VERSION 5.8 ;
BUSBITCHARS "[]" ;
DIVIDERCHAR "/" ;
UNITS
    DATABASE MICRONS 1000 ;
END UNITS

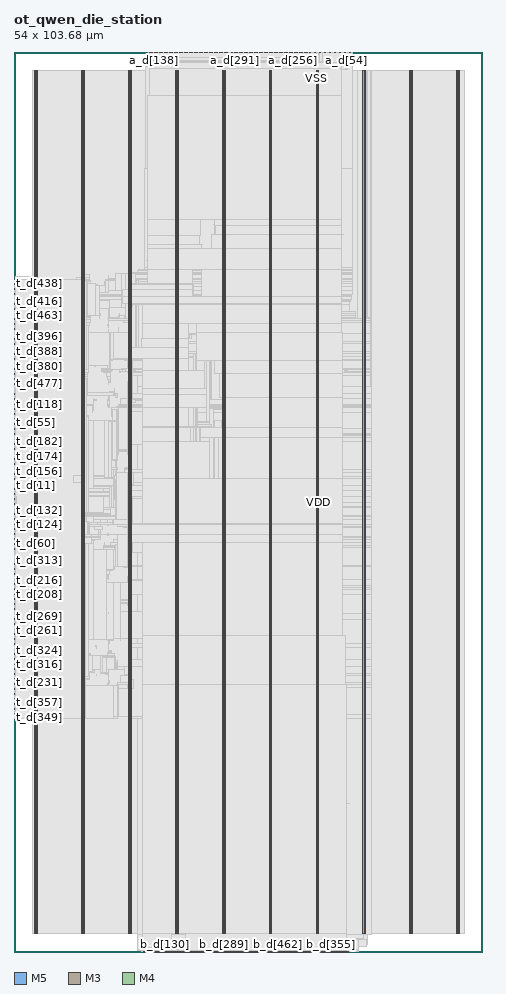
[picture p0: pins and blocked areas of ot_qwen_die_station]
MACRO ot_qwen_die_station
  FOREIGN ot_qwen_die_station 0 0 ;
  CLASS BLOCK ;
  SIZE 54 BY 103.68 ;
  PIN a_d[0]
    DIRECTION INPUT ;
    USE SIGNAL ;
    PORT
      LAYER M5 ;
        RECT  15.696 103.596 15.72 103.68 ;
    END
  END a_d[0]
  PIN a_d[100]
    DIRECTION INPUT ;
    USE SIGNAL ;
    PORT
      LAYER M5 ;
        RECT  22.224 103.596 22.248 103.68 ;
    END
  END a_d[100]
  PIN a_d[101]
    DIRECTION INPUT ;
    USE SIGNAL ;
    PORT
      LAYER M5 ;
        RECT  22.32 103.596 22.344 103.68 ;
    END
  END a_d[101]
  PIN a_d[102]
    DIRECTION INPUT ;
    USE SIGNAL ;
    PORT
      LAYER M5 ;
        RECT  22.416 103.596 22.44 103.68 ;
    END
  END a_d[102]
  PIN a_d[103]
    DIRECTION INPUT ;
    USE SIGNAL ;
    PORT
      LAYER M5 ;
        RECT  22.512 103.596 22.536 103.68 ;
    END
  END a_d[103]
  PIN a_d[104]
    DIRECTION INPUT ;
    USE SIGNAL ;
    PORT
      LAYER M5 ;
        RECT  22.608 103.596 22.632 103.68 ;
    END
  END a_d[104]
  PIN a_d[105]
    DIRECTION INPUT ;
    USE SIGNAL ;
    PORT
      LAYER M5 ;
        RECT  22.704 103.596 22.728 103.68 ;
    END
  END a_d[105]
  PIN a_d[106]
    DIRECTION INPUT ;
    USE SIGNAL ;
    PORT
      LAYER M5 ;
        RECT  22.8 103.596 22.824 103.68 ;
    END
  END a_d[106]
  PIN a_d[107]
    DIRECTION INPUT ;
    USE SIGNAL ;
    PORT
      LAYER M5 ;
        RECT  22.896 103.596 22.92 103.68 ;
    END
  END a_d[107]
  PIN a_d[108]
    DIRECTION INPUT ;
    USE SIGNAL ;
    PORT
      LAYER M5 ;
        RECT  22.992 103.596 23.016 103.68 ;
    END
  END a_d[108]
  PIN a_d[109]
    DIRECTION INPUT ;
    USE SIGNAL ;
    PORT
      LAYER M5 ;
        RECT  23.088 103.596 23.112 103.68 ;
    END
  END a_d[109]
  PIN a_d[10]
    DIRECTION INPUT ;
    USE SIGNAL ;
    PORT
      LAYER M5 ;
        RECT  16.656 103.596 16.68 103.68 ;
    END
  END a_d[10]
  PIN a_d[110]
    DIRECTION INPUT ;
    USE SIGNAL ;
    PORT
      LAYER M5 ;
        RECT  23.184 103.596 23.208 103.68 ;
    END
  END a_d[110]
  PIN a_d[111]
    DIRECTION INPUT ;
    USE SIGNAL ;
    PORT
      LAYER M5 ;
        RECT  23.28 103.596 23.304 103.68 ;
    END
  END a_d[111]
  PIN a_d[112]
    DIRECTION INPUT ;
    USE SIGNAL ;
    PORT
      LAYER M5 ;
        RECT  23.376 103.596 23.4 103.68 ;
    END
  END a_d[112]
  PIN a_d[113]
    DIRECTION INPUT ;
    USE SIGNAL ;
    PORT
      LAYER M5 ;
        RECT  23.472 103.596 23.496 103.68 ;
    END
  END a_d[113]
  PIN a_d[114]
    DIRECTION INPUT ;
    USE SIGNAL ;
    PORT
      LAYER M5 ;
        RECT  23.568 103.596 23.592 103.68 ;
    END
  END a_d[114]
  PIN a_d[115]
    DIRECTION INPUT ;
    USE SIGNAL ;
    PORT
      LAYER M5 ;
        RECT  23.664 103.596 23.688 103.68 ;
    END
  END a_d[115]
  PIN a_d[116]
    DIRECTION INPUT ;
    USE SIGNAL ;
    PORT
      LAYER M5 ;
        RECT  23.76 103.596 23.784 103.68 ;
    END
  END a_d[116]
  PIN a_d[117]
    DIRECTION INPUT ;
    USE SIGNAL ;
    PORT
      LAYER M5 ;
        RECT  23.856 103.596 23.88 103.68 ;
    END
  END a_d[117]
  PIN a_d[118]
    DIRECTION INPUT ;
    USE SIGNAL ;
    PORT
      LAYER M5 ;
        RECT  23.952 103.596 23.976 103.68 ;
    END
  END a_d[118]
  PIN a_d[119]
    DIRECTION INPUT ;
    USE SIGNAL ;
    PORT
      LAYER M5 ;
        RECT  24.048 103.596 24.072 103.68 ;
    END
  END a_d[119]
  PIN a_d[11]
    DIRECTION INPUT ;
    USE SIGNAL ;
    PORT
      LAYER M5 ;
        RECT  16.752 103.596 16.776 103.68 ;
    END
  END a_d[11]
  PIN a_d[120]
    DIRECTION INPUT ;
    USE SIGNAL ;
    PORT
      LAYER M5 ;
        RECT  24.144 103.596 24.168 103.68 ;
    END
  END a_d[120]
  PIN a_d[121]
    DIRECTION INPUT ;
    USE SIGNAL ;
    PORT
      LAYER M5 ;
        RECT  24.24 103.596 24.264 103.68 ;
    END
  END a_d[121]
  PIN a_d[122]
    DIRECTION INPUT ;
    USE SIGNAL ;
    PORT
      LAYER M5 ;
        RECT  24.336 103.596 24.36 103.68 ;
    END
  END a_d[122]
  PIN a_d[123]
    DIRECTION INPUT ;
    USE SIGNAL ;
    PORT
      LAYER M5 ;
        RECT  24.432 103.596 24.456 103.68 ;
    END
  END a_d[123]
  PIN a_d[124]
    DIRECTION INPUT ;
    USE SIGNAL ;
    PORT
      LAYER M5 ;
        RECT  24.528 103.596 24.552 103.68 ;
    END
  END a_d[124]
  PIN a_d[125]
    DIRECTION INPUT ;
    USE SIGNAL ;
    PORT
      LAYER M5 ;
        RECT  24.624 103.596 24.648 103.68 ;
    END
  END a_d[125]
  PIN a_d[126]
    DIRECTION INPUT ;
    USE SIGNAL ;
    PORT
      LAYER M5 ;
        RECT  24.72 103.596 24.744 103.68 ;
    END
  END a_d[126]
  PIN a_d[127]
    DIRECTION INPUT ;
    USE SIGNAL ;
    PORT
      LAYER M5 ;
        RECT  24.816 103.596 24.84 103.68 ;
    END
  END a_d[127]
  PIN a_d[128]
    DIRECTION INPUT ;
    USE SIGNAL ;
    PORT
      LAYER M3 ;
        RECT  15.444 103.643 15.462 103.68 ;
    END
  END a_d[128]
  PIN a_d[129]
    DIRECTION INPUT ;
    USE SIGNAL ;
    PORT
      LAYER M3 ;
        RECT  15.516 103.643 15.534 103.68 ;
    END
  END a_d[129]
  PIN a_d[12]
    DIRECTION INPUT ;
    USE SIGNAL ;
    PORT
      LAYER M5 ;
        RECT  16.848 103.596 16.872 103.68 ;
    END
  END a_d[12]
  PIN a_d[130]
    DIRECTION INPUT ;
    USE SIGNAL ;
    PORT
      LAYER M3 ;
        RECT  15.588 103.643 15.606 103.68 ;
    END
  END a_d[130]
  PIN a_d[131]
    DIRECTION INPUT ;
    USE SIGNAL ;
    PORT
      LAYER M3 ;
        RECT  15.66 103.643 15.678 103.68 ;
    END
  END a_d[131]
  PIN a_d[132]
    DIRECTION INPUT ;
    USE SIGNAL ;
    PORT
      LAYER M3 ;
        RECT  15.732 103.643 15.75 103.68 ;
    END
  END a_d[132]
  PIN a_d[133]
    DIRECTION INPUT ;
    USE SIGNAL ;
    PORT
      LAYER M3 ;
        RECT  15.804 103.643 15.822 103.68 ;
    END
  END a_d[133]
  PIN a_d[134]
    DIRECTION INPUT ;
    USE SIGNAL ;
    PORT
      LAYER M3 ;
        RECT  15.876 103.643 15.894 103.68 ;
    END
  END a_d[134]
  PIN a_d[135]
    DIRECTION INPUT ;
    USE SIGNAL ;
    PORT
      LAYER M3 ;
        RECT  15.948 103.643 15.966 103.68 ;
    END
  END a_d[135]
  PIN a_d[136]
    DIRECTION INPUT ;
    USE SIGNAL ;
    PORT
      LAYER M3 ;
        RECT  16.02 103.643 16.038 103.68 ;
    END
  END a_d[136]
  PIN a_d[137]
    DIRECTION INPUT ;
    USE SIGNAL ;
    PORT
      LAYER M3 ;
        RECT  16.092 103.643 16.11 103.68 ;
    END
  END a_d[137]
  PIN a_d[138]
    DIRECTION INPUT ;
    USE SIGNAL ;
    PORT
      LAYER M3 ;
        RECT  16.164 103.643 16.182 103.68 ;
    END
  END a_d[138]
  PIN a_d[139]
    DIRECTION INPUT ;
    USE SIGNAL ;
    PORT
      LAYER M3 ;
        RECT  16.236 103.643 16.254 103.68 ;
    END
  END a_d[139]
  PIN a_d[13]
    DIRECTION INPUT ;
    USE SIGNAL ;
    PORT
      LAYER M5 ;
        RECT  16.944 103.596 16.968 103.68 ;
    END
  END a_d[13]
  PIN a_d[140]
    DIRECTION INPUT ;
    USE SIGNAL ;
    PORT
      LAYER M3 ;
        RECT  16.308 103.643 16.326 103.68 ;
    END
  END a_d[140]
  PIN a_d[141]
    DIRECTION INPUT ;
    USE SIGNAL ;
    PORT
      LAYER M3 ;
        RECT  16.38 103.643 16.398 103.68 ;
    END
  END a_d[141]
  PIN a_d[142]
    DIRECTION INPUT ;
    USE SIGNAL ;
    PORT
      LAYER M3 ;
        RECT  16.452 103.643 16.47 103.68 ;
    END
  END a_d[142]
  PIN a_d[143]
    DIRECTION INPUT ;
    USE SIGNAL ;
    PORT
      LAYER M3 ;
        RECT  16.524 103.643 16.542 103.68 ;
    END
  END a_d[143]
  PIN a_d[144]
    DIRECTION INPUT ;
    USE SIGNAL ;
    PORT
      LAYER M3 ;
        RECT  16.596 103.643 16.614 103.68 ;
    END
  END a_d[144]
  PIN a_d[145]
    DIRECTION INPUT ;
    USE SIGNAL ;
    PORT
      LAYER M3 ;
        RECT  16.668 103.643 16.686 103.68 ;
    END
  END a_d[145]
  PIN a_d[146]
    DIRECTION INPUT ;
    USE SIGNAL ;
    PORT
      LAYER M3 ;
        RECT  16.74 103.643 16.758 103.68 ;
    END
  END a_d[146]
  PIN a_d[147]
    DIRECTION INPUT ;
    USE SIGNAL ;
    PORT
      LAYER M3 ;
        RECT  16.812 103.643 16.83 103.68 ;
    END
  END a_d[147]
  PIN a_d[148]
    DIRECTION INPUT ;
    USE SIGNAL ;
    PORT
      LAYER M3 ;
        RECT  16.884 103.643 16.902 103.68 ;
    END
  END a_d[148]
  PIN a_d[149]
    DIRECTION INPUT ;
    USE SIGNAL ;
    PORT
      LAYER M3 ;
        RECT  16.956 103.643 16.974 103.68 ;
    END
  END a_d[149]
  PIN a_d[14]
    DIRECTION INPUT ;
    USE SIGNAL ;
    PORT
      LAYER M5 ;
        RECT  17.04 103.596 17.064 103.68 ;
    END
  END a_d[14]
  PIN a_d[150]
    DIRECTION INPUT ;
    USE SIGNAL ;
    PORT
      LAYER M3 ;
        RECT  17.028 103.643 17.046 103.68 ;
    END
  END a_d[150]
  PIN a_d[151]
    DIRECTION INPUT ;
    USE SIGNAL ;
    PORT
      LAYER M3 ;
        RECT  17.1 103.643 17.118 103.68 ;
    END
  END a_d[151]
  PIN a_d[152]
    DIRECTION INPUT ;
    USE SIGNAL ;
    PORT
      LAYER M3 ;
        RECT  17.172 103.643 17.19 103.68 ;
    END
  END a_d[152]
  PIN a_d[153]
    DIRECTION INPUT ;
    USE SIGNAL ;
    PORT
      LAYER M3 ;
        RECT  17.244 103.643 17.262 103.68 ;
    END
  END a_d[153]
  PIN a_d[154]
    DIRECTION INPUT ;
    USE SIGNAL ;
    PORT
      LAYER M3 ;
        RECT  17.316 103.643 17.334 103.68 ;
    END
  END a_d[154]
  PIN a_d[155]
    DIRECTION INPUT ;
    USE SIGNAL ;
    PORT
      LAYER M3 ;
        RECT  17.388 103.643 17.406 103.68 ;
    END
  END a_d[155]
  PIN a_d[156]
    DIRECTION INPUT ;
    USE SIGNAL ;
    PORT
      LAYER M3 ;
        RECT  17.46 103.643 17.478 103.68 ;
    END
  END a_d[156]
  PIN a_d[157]
    DIRECTION INPUT ;
    USE SIGNAL ;
    PORT
      LAYER M3 ;
        RECT  17.532 103.643 17.55 103.68 ;
    END
  END a_d[157]
  PIN a_d[158]
    DIRECTION INPUT ;
    USE SIGNAL ;
    PORT
      LAYER M3 ;
        RECT  17.604 103.643 17.622 103.68 ;
    END
  END a_d[158]
  PIN a_d[159]
    DIRECTION INPUT ;
    USE SIGNAL ;
    PORT
      LAYER M3 ;
        RECT  17.676 103.643 17.694 103.68 ;
    END
  END a_d[159]
  PIN a_d[15]
    DIRECTION INPUT ;
    USE SIGNAL ;
    PORT
      LAYER M5 ;
        RECT  17.136 103.596 17.16 103.68 ;
    END
  END a_d[15]
  PIN a_d[160]
    DIRECTION INPUT ;
    USE SIGNAL ;
    PORT
      LAYER M5 ;
        RECT  24.912 103.596 24.936 103.68 ;
    END
  END a_d[160]
  PIN a_d[161]
    DIRECTION INPUT ;
    USE SIGNAL ;
    PORT
      LAYER M5 ;
        RECT  25.008 103.596 25.032 103.68 ;
    END
  END a_d[161]
  PIN a_d[162]
    DIRECTION INPUT ;
    USE SIGNAL ;
    PORT
      LAYER M5 ;
        RECT  25.104 103.596 25.128 103.68 ;
    END
  END a_d[162]
  PIN a_d[163]
    DIRECTION INPUT ;
    USE SIGNAL ;
    PORT
      LAYER M5 ;
        RECT  25.2 103.596 25.224 103.68 ;
    END
  END a_d[163]
  PIN a_d[164]
    DIRECTION INPUT ;
    USE SIGNAL ;
    PORT
      LAYER M5 ;
        RECT  25.296 103.596 25.32 103.68 ;
    END
  END a_d[164]
  PIN a_d[165]
    DIRECTION INPUT ;
    USE SIGNAL ;
    PORT
      LAYER M5 ;
        RECT  25.392 103.596 25.416 103.68 ;
    END
  END a_d[165]
  PIN a_d[166]
    DIRECTION INPUT ;
    USE SIGNAL ;
    PORT
      LAYER M5 ;
        RECT  25.488 103.596 25.512 103.68 ;
    END
  END a_d[166]
  PIN a_d[167]
    DIRECTION INPUT ;
    USE SIGNAL ;
    PORT
      LAYER M5 ;
        RECT  25.584 103.596 25.608 103.68 ;
    END
  END a_d[167]
  PIN a_d[168]
    DIRECTION INPUT ;
    USE SIGNAL ;
    PORT
      LAYER M5 ;
        RECT  25.68 103.596 25.704 103.68 ;
    END
  END a_d[168]
  PIN a_d[169]
    DIRECTION INPUT ;
    USE SIGNAL ;
    PORT
      LAYER M5 ;
        RECT  25.776 103.596 25.8 103.68 ;
    END
  END a_d[169]
  PIN a_d[16]
    DIRECTION INPUT ;
    USE SIGNAL ;
    PORT
      LAYER M5 ;
        RECT  17.232 103.596 17.256 103.68 ;
    END
  END a_d[16]
  PIN a_d[170]
    DIRECTION INPUT ;
    USE SIGNAL ;
    PORT
      LAYER M5 ;
        RECT  25.872 103.596 25.896 103.68 ;
    END
  END a_d[170]
  PIN a_d[171]
    DIRECTION INPUT ;
    USE SIGNAL ;
    PORT
      LAYER M5 ;
        RECT  25.968 103.596 25.992 103.68 ;
    END
  END a_d[171]
  PIN a_d[172]
    DIRECTION INPUT ;
    USE SIGNAL ;
    PORT
      LAYER M5 ;
        RECT  26.064 103.596 26.088 103.68 ;
    END
  END a_d[172]
  PIN a_d[173]
    DIRECTION INPUT ;
    USE SIGNAL ;
    PORT
      LAYER M5 ;
        RECT  26.16 103.596 26.184 103.68 ;
    END
  END a_d[173]
  PIN a_d[174]
    DIRECTION INPUT ;
    USE SIGNAL ;
    PORT
      LAYER M5 ;
        RECT  26.256 103.596 26.28 103.68 ;
    END
  END a_d[174]
  PIN a_d[175]
    DIRECTION INPUT ;
    USE SIGNAL ;
    PORT
      LAYER M5 ;
        RECT  26.352 103.596 26.376 103.68 ;
    END
  END a_d[175]
  PIN a_d[176]
    DIRECTION INPUT ;
    USE SIGNAL ;
    PORT
      LAYER M5 ;
        RECT  26.448 103.596 26.472 103.68 ;
    END
  END a_d[176]
  PIN a_d[177]
    DIRECTION INPUT ;
    USE SIGNAL ;
    PORT
      LAYER M5 ;
        RECT  26.544 103.596 26.568 103.68 ;
    END
  END a_d[177]
  PIN a_d[178]
    DIRECTION INPUT ;
    USE SIGNAL ;
    PORT
      LAYER M5 ;
        RECT  26.64 103.596 26.664 103.68 ;
    END
  END a_d[178]
  PIN a_d[179]
    DIRECTION INPUT ;
    USE SIGNAL ;
    PORT
      LAYER M5 ;
        RECT  26.736 103.596 26.76 103.68 ;
    END
  END a_d[179]
  PIN a_d[17]
    DIRECTION INPUT ;
    USE SIGNAL ;
    PORT
      LAYER M5 ;
        RECT  17.328 103.596 17.352 103.68 ;
    END
  END a_d[17]
  PIN a_d[180]
    DIRECTION INPUT ;
    USE SIGNAL ;
    PORT
      LAYER M5 ;
        RECT  26.832 103.596 26.856 103.68 ;
    END
  END a_d[180]
  PIN a_d[181]
    DIRECTION INPUT ;
    USE SIGNAL ;
    PORT
      LAYER M5 ;
        RECT  26.928 103.596 26.952 103.68 ;
    END
  END a_d[181]
  PIN a_d[182]
    DIRECTION INPUT ;
    USE SIGNAL ;
    PORT
      LAYER M5 ;
        RECT  27.024 103.596 27.048 103.68 ;
    END
  END a_d[182]
  PIN a_d[183]
    DIRECTION INPUT ;
    USE SIGNAL ;
    PORT
      LAYER M5 ;
        RECT  27.12 103.596 27.144 103.68 ;
    END
  END a_d[183]
  PIN a_d[184]
    DIRECTION INPUT ;
    USE SIGNAL ;
    PORT
      LAYER M5 ;
        RECT  27.216 103.596 27.24 103.68 ;
    END
  END a_d[184]
  PIN a_d[185]
    DIRECTION INPUT ;
    USE SIGNAL ;
    PORT
      LAYER M5 ;
        RECT  27.312 103.596 27.336 103.68 ;
    END
  END a_d[185]
  PIN a_d[186]
    DIRECTION INPUT ;
    USE SIGNAL ;
    PORT
      LAYER M5 ;
        RECT  27.408 103.596 27.432 103.68 ;
    END
  END a_d[186]
  PIN a_d[187]
    DIRECTION INPUT ;
    USE SIGNAL ;
    PORT
      LAYER M5 ;
        RECT  27.504 103.596 27.528 103.68 ;
    END
  END a_d[187]
  PIN a_d[188]
    DIRECTION INPUT ;
    USE SIGNAL ;
    PORT
      LAYER M5 ;
        RECT  27.6 103.596 27.624 103.68 ;
    END
  END a_d[188]
  PIN a_d[189]
    DIRECTION INPUT ;
    USE SIGNAL ;
    PORT
      LAYER M5 ;
        RECT  27.696 103.596 27.72 103.68 ;
    END
  END a_d[189]
  PIN a_d[18]
    DIRECTION INPUT ;
    USE SIGNAL ;
    PORT
      LAYER M5 ;
        RECT  17.424 103.596 17.448 103.68 ;
    END
  END a_d[18]
  PIN a_d[190]
    DIRECTION INPUT ;
    USE SIGNAL ;
    PORT
      LAYER M5 ;
        RECT  27.792 103.596 27.816 103.68 ;
    END
  END a_d[190]
  PIN a_d[191]
    DIRECTION INPUT ;
    USE SIGNAL ;
    PORT
      LAYER M5 ;
        RECT  27.888 103.596 27.912 103.68 ;
    END
  END a_d[191]
  PIN a_d[192]
    DIRECTION INPUT ;
    USE SIGNAL ;
    PORT
      LAYER M5 ;
        RECT  27.984 103.596 28.008 103.68 ;
    END
  END a_d[192]
  PIN a_d[193]
    DIRECTION INPUT ;
    USE SIGNAL ;
    PORT
      LAYER M5 ;
        RECT  28.08 103.596 28.104 103.68 ;
    END
  END a_d[193]
  PIN a_d[194]
    DIRECTION INPUT ;
    USE SIGNAL ;
    PORT
      LAYER M5 ;
        RECT  28.176 103.596 28.2 103.68 ;
    END
  END a_d[194]
  PIN a_d[195]
    DIRECTION INPUT ;
    USE SIGNAL ;
    PORT
      LAYER M5 ;
        RECT  28.272 103.596 28.296 103.68 ;
    END
  END a_d[195]
  PIN a_d[196]
    DIRECTION INPUT ;
    USE SIGNAL ;
    PORT
      LAYER M5 ;
        RECT  28.368 103.596 28.392 103.68 ;
    END
  END a_d[196]
  PIN a_d[197]
    DIRECTION INPUT ;
    USE SIGNAL ;
    PORT
      LAYER M5 ;
        RECT  28.464 103.596 28.488 103.68 ;
    END
  END a_d[197]
  PIN a_d[198]
    DIRECTION INPUT ;
    USE SIGNAL ;
    PORT
      LAYER M5 ;
        RECT  28.56 103.596 28.584 103.68 ;
    END
  END a_d[198]
  PIN a_d[199]
    DIRECTION INPUT ;
    USE SIGNAL ;
    PORT
      LAYER M5 ;
        RECT  28.656 103.596 28.68 103.68 ;
    END
  END a_d[199]
  PIN a_d[19]
    DIRECTION INPUT ;
    USE SIGNAL ;
    PORT
      LAYER M5 ;
        RECT  17.52 103.596 17.544 103.68 ;
    END
  END a_d[19]
  PIN a_d[1]
    DIRECTION INPUT ;
    USE SIGNAL ;
    PORT
      LAYER M5 ;
        RECT  15.792 103.596 15.816 103.68 ;
    END
  END a_d[1]
  PIN a_d[200]
    DIRECTION INPUT ;
    USE SIGNAL ;
    PORT
      LAYER M5 ;
        RECT  28.752 103.596 28.776 103.68 ;
    END
  END a_d[200]
  PIN a_d[201]
    DIRECTION INPUT ;
    USE SIGNAL ;
    PORT
      LAYER M5 ;
        RECT  28.848 103.596 28.872 103.68 ;
    END
  END a_d[201]
  PIN a_d[202]
    DIRECTION INPUT ;
    USE SIGNAL ;
    PORT
      LAYER M5 ;
        RECT  28.944 103.596 28.968 103.68 ;
    END
  END a_d[202]
  PIN a_d[203]
    DIRECTION INPUT ;
    USE SIGNAL ;
    PORT
      LAYER M5 ;
        RECT  29.04 103.596 29.064 103.68 ;
    END
  END a_d[203]
  PIN a_d[204]
    DIRECTION INPUT ;
    USE SIGNAL ;
    PORT
      LAYER M5 ;
        RECT  29.136 103.596 29.16 103.68 ;
    END
  END a_d[204]
  PIN a_d[205]
    DIRECTION INPUT ;
    USE SIGNAL ;
    PORT
      LAYER M5 ;
        RECT  29.232 103.596 29.256 103.68 ;
    END
  END a_d[205]
  PIN a_d[206]
    DIRECTION INPUT ;
    USE SIGNAL ;
    PORT
      LAYER M5 ;
        RECT  29.328 103.596 29.352 103.68 ;
    END
  END a_d[206]
  PIN a_d[207]
    DIRECTION INPUT ;
    USE SIGNAL ;
    PORT
      LAYER M5 ;
        RECT  29.424 103.596 29.448 103.68 ;
    END
  END a_d[207]
  PIN a_d[208]
    DIRECTION INPUT ;
    USE SIGNAL ;
    PORT
      LAYER M5 ;
        RECT  29.52 103.596 29.544 103.68 ;
    END
  END a_d[208]
  PIN a_d[209]
    DIRECTION INPUT ;
    USE SIGNAL ;
    PORT
      LAYER M5 ;
        RECT  29.616 103.596 29.64 103.68 ;
    END
  END a_d[209]
  PIN a_d[20]
    DIRECTION INPUT ;
    USE SIGNAL ;
    PORT
      LAYER M5 ;
        RECT  17.616 103.596 17.64 103.68 ;
    END
  END a_d[20]
  PIN a_d[210]
    DIRECTION INPUT ;
    USE SIGNAL ;
    PORT
      LAYER M5 ;
        RECT  29.712 103.596 29.736 103.68 ;
    END
  END a_d[210]
  PIN a_d[211]
    DIRECTION INPUT ;
    USE SIGNAL ;
    PORT
      LAYER M5 ;
        RECT  29.808 103.596 29.832 103.68 ;
    END
  END a_d[211]
  PIN a_d[212]
    DIRECTION INPUT ;
    USE SIGNAL ;
    PORT
      LAYER M5 ;
        RECT  29.904 103.596 29.928 103.68 ;
    END
  END a_d[212]
  PIN a_d[213]
    DIRECTION INPUT ;
    USE SIGNAL ;
    PORT
      LAYER M5 ;
        RECT  30 103.596 30.024 103.68 ;
    END
  END a_d[213]
  PIN a_d[214]
    DIRECTION INPUT ;
    USE SIGNAL ;
    PORT
      LAYER M5 ;
        RECT  30.096 103.596 30.12 103.68 ;
    END
  END a_d[214]
  PIN a_d[215]
    DIRECTION INPUT ;
    USE SIGNAL ;
    PORT
      LAYER M5 ;
        RECT  30.192 103.596 30.216 103.68 ;
    END
  END a_d[215]
  PIN a_d[216]
    DIRECTION INPUT ;
    USE SIGNAL ;
    PORT
      LAYER M5 ;
        RECT  30.288 103.596 30.312 103.68 ;
    END
  END a_d[216]
  PIN a_d[217]
    DIRECTION INPUT ;
    USE SIGNAL ;
    PORT
      LAYER M5 ;
        RECT  30.384 103.596 30.408 103.68 ;
    END
  END a_d[217]
  PIN a_d[218]
    DIRECTION INPUT ;
    USE SIGNAL ;
    PORT
      LAYER M5 ;
        RECT  30.48 103.596 30.504 103.68 ;
    END
  END a_d[218]
  PIN a_d[219]
    DIRECTION INPUT ;
    USE SIGNAL ;
    PORT
      LAYER M5 ;
        RECT  30.576 103.596 30.6 103.68 ;
    END
  END a_d[219]
  PIN a_d[21]
    DIRECTION INPUT ;
    USE SIGNAL ;
    PORT
      LAYER M5 ;
        RECT  17.712 103.596 17.736 103.68 ;
    END
  END a_d[21]
  PIN a_d[220]
    DIRECTION INPUT ;
    USE SIGNAL ;
    PORT
      LAYER M5 ;
        RECT  30.672 103.596 30.696 103.68 ;
    END
  END a_d[220]
  PIN a_d[221]
    DIRECTION INPUT ;
    USE SIGNAL ;
    PORT
      LAYER M5 ;
        RECT  30.768 103.596 30.792 103.68 ;
    END
  END a_d[221]
  PIN a_d[222]
    DIRECTION INPUT ;
    USE SIGNAL ;
    PORT
      LAYER M5 ;
        RECT  30.864 103.596 30.888 103.68 ;
    END
  END a_d[222]
  PIN a_d[223]
    DIRECTION INPUT ;
    USE SIGNAL ;
    PORT
      LAYER M5 ;
        RECT  30.96 103.596 30.984 103.68 ;
    END
  END a_d[223]
  PIN a_d[224]
    DIRECTION INPUT ;
    USE SIGNAL ;
    PORT
      LAYER M5 ;
        RECT  31.056 103.596 31.08 103.68 ;
    END
  END a_d[224]
  PIN a_d[225]
    DIRECTION INPUT ;
    USE SIGNAL ;
    PORT
      LAYER M5 ;
        RECT  31.152 103.596 31.176 103.68 ;
    END
  END a_d[225]
  PIN a_d[226]
    DIRECTION INPUT ;
    USE SIGNAL ;
    PORT
      LAYER M5 ;
        RECT  31.248 103.596 31.272 103.68 ;
    END
  END a_d[226]
  PIN a_d[227]
    DIRECTION INPUT ;
    USE SIGNAL ;
    PORT
      LAYER M5 ;
        RECT  31.344 103.596 31.368 103.68 ;
    END
  END a_d[227]
  PIN a_d[228]
    DIRECTION INPUT ;
    USE SIGNAL ;
    PORT
      LAYER M5 ;
        RECT  31.44 103.596 31.464 103.68 ;
    END
  END a_d[228]
  PIN a_d[229]
    DIRECTION INPUT ;
    USE SIGNAL ;
    PORT
      LAYER M5 ;
        RECT  31.536 103.596 31.56 103.68 ;
    END
  END a_d[229]
  PIN a_d[22]
    DIRECTION INPUT ;
    USE SIGNAL ;
    PORT
      LAYER M5 ;
        RECT  17.808 103.596 17.832 103.68 ;
    END
  END a_d[22]
  PIN a_d[230]
    DIRECTION INPUT ;
    USE SIGNAL ;
    PORT
      LAYER M5 ;
        RECT  31.632 103.596 31.656 103.68 ;
    END
  END a_d[230]
  PIN a_d[231]
    DIRECTION INPUT ;
    USE SIGNAL ;
    PORT
      LAYER M5 ;
        RECT  31.728 103.596 31.752 103.68 ;
    END
  END a_d[231]
  PIN a_d[232]
    DIRECTION INPUT ;
    USE SIGNAL ;
    PORT
      LAYER M5 ;
        RECT  31.824 103.596 31.848 103.68 ;
    END
  END a_d[232]
  PIN a_d[233]
    DIRECTION INPUT ;
    USE SIGNAL ;
    PORT
      LAYER M5 ;
        RECT  31.92 103.596 31.944 103.68 ;
    END
  END a_d[233]
  PIN a_d[234]
    DIRECTION INPUT ;
    USE SIGNAL ;
    PORT
      LAYER M5 ;
        RECT  32.016 103.596 32.04 103.68 ;
    END
  END a_d[234]
  PIN a_d[235]
    DIRECTION INPUT ;
    USE SIGNAL ;
    PORT
      LAYER M5 ;
        RECT  32.112 103.596 32.136 103.68 ;
    END
  END a_d[235]
  PIN a_d[236]
    DIRECTION INPUT ;
    USE SIGNAL ;
    PORT
      LAYER M5 ;
        RECT  32.208 103.596 32.232 103.68 ;
    END
  END a_d[236]
  PIN a_d[237]
    DIRECTION INPUT ;
    USE SIGNAL ;
    PORT
      LAYER M5 ;
        RECT  32.304 103.596 32.328 103.68 ;
    END
  END a_d[237]
  PIN a_d[238]
    DIRECTION INPUT ;
    USE SIGNAL ;
    PORT
      LAYER M5 ;
        RECT  32.4 103.596 32.424 103.68 ;
    END
  END a_d[238]
  PIN a_d[239]
    DIRECTION INPUT ;
    USE SIGNAL ;
    PORT
      LAYER M5 ;
        RECT  32.496 103.596 32.52 103.68 ;
    END
  END a_d[239]
  PIN a_d[23]
    DIRECTION INPUT ;
    USE SIGNAL ;
    PORT
      LAYER M5 ;
        RECT  17.904 103.596 17.928 103.68 ;
    END
  END a_d[23]
  PIN a_d[240]
    DIRECTION INPUT ;
    USE SIGNAL ;
    PORT
      LAYER M5 ;
        RECT  32.592 103.596 32.616 103.68 ;
    END
  END a_d[240]
  PIN a_d[241]
    DIRECTION INPUT ;
    USE SIGNAL ;
    PORT
      LAYER M5 ;
        RECT  32.688 103.596 32.712 103.68 ;
    END
  END a_d[241]
  PIN a_d[242]
    DIRECTION INPUT ;
    USE SIGNAL ;
    PORT
      LAYER M5 ;
        RECT  32.784 103.596 32.808 103.68 ;
    END
  END a_d[242]
  PIN a_d[243]
    DIRECTION INPUT ;
    USE SIGNAL ;
    PORT
      LAYER M5 ;
        RECT  32.88 103.596 32.904 103.68 ;
    END
  END a_d[243]
  PIN a_d[244]
    DIRECTION INPUT ;
    USE SIGNAL ;
    PORT
      LAYER M5 ;
        RECT  32.976 103.596 33 103.68 ;
    END
  END a_d[244]
  PIN a_d[245]
    DIRECTION INPUT ;
    USE SIGNAL ;
    PORT
      LAYER M5 ;
        RECT  33.072 103.596 33.096 103.68 ;
    END
  END a_d[245]
  PIN a_d[246]
    DIRECTION INPUT ;
    USE SIGNAL ;
    PORT
      LAYER M5 ;
        RECT  33.168 103.596 33.192 103.68 ;
    END
  END a_d[246]
  PIN a_d[247]
    DIRECTION INPUT ;
    USE SIGNAL ;
    PORT
      LAYER M5 ;
        RECT  33.264 103.596 33.288 103.68 ;
    END
  END a_d[247]
  PIN a_d[248]
    DIRECTION INPUT ;
    USE SIGNAL ;
    PORT
      LAYER M5 ;
        RECT  33.36 103.596 33.384 103.68 ;
    END
  END a_d[248]
  PIN a_d[249]
    DIRECTION INPUT ;
    USE SIGNAL ;
    PORT
      LAYER M5 ;
        RECT  33.456 103.596 33.48 103.68 ;
    END
  END a_d[249]
  PIN a_d[24]
    DIRECTION INPUT ;
    USE SIGNAL ;
    PORT
      LAYER M5 ;
        RECT  18 103.596 18.024 103.68 ;
    END
  END a_d[24]
  PIN a_d[250]
    DIRECTION INPUT ;
    USE SIGNAL ;
    PORT
      LAYER M5 ;
        RECT  33.552 103.596 33.576 103.68 ;
    END
  END a_d[250]
  PIN a_d[251]
    DIRECTION INPUT ;
    USE SIGNAL ;
    PORT
      LAYER M5 ;
        RECT  33.648 103.596 33.672 103.68 ;
    END
  END a_d[251]
  PIN a_d[252]
    DIRECTION INPUT ;
    USE SIGNAL ;
    PORT
      LAYER M5 ;
        RECT  33.744 103.596 33.768 103.68 ;
    END
  END a_d[252]
  PIN a_d[253]
    DIRECTION INPUT ;
    USE SIGNAL ;
    PORT
      LAYER M5 ;
        RECT  33.84 103.596 33.864 103.68 ;
    END
  END a_d[253]
  PIN a_d[254]
    DIRECTION INPUT ;
    USE SIGNAL ;
    PORT
      LAYER M5 ;
        RECT  33.936 103.596 33.96 103.68 ;
    END
  END a_d[254]
  PIN a_d[255]
    DIRECTION INPUT ;
    USE SIGNAL ;
    PORT
      LAYER M5 ;
        RECT  34.032 103.596 34.056 103.68 ;
    END
  END a_d[255]
  PIN a_d[256]
    DIRECTION INPUT ;
    USE SIGNAL ;
    PORT
      LAYER M3 ;
        RECT  32.148 103.643 32.166 103.68 ;
    END
  END a_d[256]
  PIN a_d[257]
    DIRECTION INPUT ;
    USE SIGNAL ;
    PORT
      LAYER M3 ;
        RECT  32.22 103.643 32.238 103.68 ;
    END
  END a_d[257]
  PIN a_d[258]
    DIRECTION INPUT ;
    USE SIGNAL ;
    PORT
      LAYER M3 ;
        RECT  32.292 103.643 32.31 103.68 ;
    END
  END a_d[258]
  PIN a_d[259]
    DIRECTION INPUT ;
    USE SIGNAL ;
    PORT
      LAYER M3 ;
        RECT  32.364 103.643 32.382 103.68 ;
    END
  END a_d[259]
  PIN a_d[25]
    DIRECTION INPUT ;
    USE SIGNAL ;
    PORT
      LAYER M5 ;
        RECT  18.096 103.596 18.12 103.68 ;
    END
  END a_d[25]
  PIN a_d[260]
    DIRECTION INPUT ;
    USE SIGNAL ;
    PORT
      LAYER M3 ;
        RECT  32.436 103.643 32.454 103.68 ;
    END
  END a_d[260]
  PIN a_d[261]
    DIRECTION INPUT ;
    USE SIGNAL ;
    PORT
      LAYER M3 ;
        RECT  32.508 103.643 32.526 103.68 ;
    END
  END a_d[261]
  PIN a_d[262]
    DIRECTION INPUT ;
    USE SIGNAL ;
    PORT
      LAYER M3 ;
        RECT  32.58 103.643 32.598 103.68 ;
    END
  END a_d[262]
  PIN a_d[263]
    DIRECTION INPUT ;
    USE SIGNAL ;
    PORT
      LAYER M3 ;
        RECT  32.652 103.643 32.67 103.68 ;
    END
  END a_d[263]
  PIN a_d[264]
    DIRECTION INPUT ;
    USE SIGNAL ;
    PORT
      LAYER M3 ;
        RECT  32.724 103.643 32.742 103.68 ;
    END
  END a_d[264]
  PIN a_d[265]
    DIRECTION INPUT ;
    USE SIGNAL ;
    PORT
      LAYER M3 ;
        RECT  32.796 103.643 32.814 103.68 ;
    END
  END a_d[265]
  PIN a_d[266]
    DIRECTION INPUT ;
    USE SIGNAL ;
    PORT
      LAYER M3 ;
        RECT  32.868 103.643 32.886 103.68 ;
    END
  END a_d[266]
  PIN a_d[267]
    DIRECTION INPUT ;
    USE SIGNAL ;
    PORT
      LAYER M3 ;
        RECT  32.94 103.643 32.958 103.68 ;
    END
  END a_d[267]
  PIN a_d[268]
    DIRECTION INPUT ;
    USE SIGNAL ;
    PORT
      LAYER M3 ;
        RECT  33.012 103.643 33.03 103.68 ;
    END
  END a_d[268]
  PIN a_d[269]
    DIRECTION INPUT ;
    USE SIGNAL ;
    PORT
      LAYER M3 ;
        RECT  33.084 103.643 33.102 103.68 ;
    END
  END a_d[269]
  PIN a_d[26]
    DIRECTION INPUT ;
    USE SIGNAL ;
    PORT
      LAYER M5 ;
        RECT  18.192 103.596 18.216 103.68 ;
    END
  END a_d[26]
  PIN a_d[270]
    DIRECTION INPUT ;
    USE SIGNAL ;
    PORT
      LAYER M3 ;
        RECT  33.156 103.643 33.174 103.68 ;
    END
  END a_d[270]
  PIN a_d[271]
    DIRECTION INPUT ;
    USE SIGNAL ;
    PORT
      LAYER M3 ;
        RECT  33.228 103.643 33.246 103.68 ;
    END
  END a_d[271]
  PIN a_d[272]
    DIRECTION INPUT ;
    USE SIGNAL ;
    PORT
      LAYER M3 ;
        RECT  33.3 103.643 33.318 103.68 ;
    END
  END a_d[272]
  PIN a_d[273]
    DIRECTION INPUT ;
    USE SIGNAL ;
    PORT
      LAYER M3 ;
        RECT  33.372 103.643 33.39 103.68 ;
    END
  END a_d[273]
  PIN a_d[274]
    DIRECTION INPUT ;
    USE SIGNAL ;
    PORT
      LAYER M3 ;
        RECT  33.444 103.643 33.462 103.68 ;
    END
  END a_d[274]
  PIN a_d[275]
    DIRECTION INPUT ;
    USE SIGNAL ;
    PORT
      LAYER M3 ;
        RECT  33.516 103.643 33.534 103.68 ;
    END
  END a_d[275]
  PIN a_d[276]
    DIRECTION INPUT ;
    USE SIGNAL ;
    PORT
      LAYER M3 ;
        RECT  33.588 103.643 33.606 103.68 ;
    END
  END a_d[276]
  PIN a_d[277]
    DIRECTION INPUT ;
    USE SIGNAL ;
    PORT
      LAYER M3 ;
        RECT  33.66 103.643 33.678 103.68 ;
    END
  END a_d[277]
  PIN a_d[278]
    DIRECTION INPUT ;
    USE SIGNAL ;
    PORT
      LAYER M3 ;
        RECT  33.732 103.643 33.75 103.68 ;
    END
  END a_d[278]
  PIN a_d[279]
    DIRECTION INPUT ;
    USE SIGNAL ;
    PORT
      LAYER M3 ;
        RECT  33.804 103.643 33.822 103.68 ;
    END
  END a_d[279]
  PIN a_d[27]
    DIRECTION INPUT ;
    USE SIGNAL ;
    PORT
      LAYER M5 ;
        RECT  18.288 103.596 18.312 103.68 ;
    END
  END a_d[27]
  PIN a_d[280]
    DIRECTION INPUT ;
    USE SIGNAL ;
    PORT
      LAYER M3 ;
        RECT  33.876 103.643 33.894 103.68 ;
    END
  END a_d[280]
  PIN a_d[281]
    DIRECTION INPUT ;
    USE SIGNAL ;
    PORT
      LAYER M3 ;
        RECT  33.948 103.643 33.966 103.68 ;
    END
  END a_d[281]
  PIN a_d[282]
    DIRECTION INPUT ;
    USE SIGNAL ;
    PORT
      LAYER M3 ;
        RECT  34.02 103.643 34.038 103.68 ;
    END
  END a_d[282]
  PIN a_d[283]
    DIRECTION INPUT ;
    USE SIGNAL ;
    PORT
      LAYER M3 ;
        RECT  34.092 103.643 34.11 103.68 ;
    END
  END a_d[283]
  PIN a_d[284]
    DIRECTION INPUT ;
    USE SIGNAL ;
    PORT
      LAYER M3 ;
        RECT  34.164 103.643 34.182 103.68 ;
    END
  END a_d[284]
  PIN a_d[285]
    DIRECTION INPUT ;
    USE SIGNAL ;
    PORT
      LAYER M3 ;
        RECT  34.236 103.643 34.254 103.68 ;
    END
  END a_d[285]
  PIN a_d[286]
    DIRECTION INPUT ;
    USE SIGNAL ;
    PORT
      LAYER M3 ;
        RECT  34.308 103.643 34.326 103.68 ;
    END
  END a_d[286]
  PIN a_d[287]
    DIRECTION INPUT ;
    USE SIGNAL ;
    PORT
      LAYER M3 ;
        RECT  34.38 103.643 34.398 103.68 ;
    END
  END a_d[287]
  PIN a_d[288]
    DIRECTION INPUT ;
    USE SIGNAL ;
    PORT
      LAYER M3 ;
        RECT  25.236 103.643 25.254 103.68 ;
    END
  END a_d[288]
  PIN a_d[289]
    DIRECTION INPUT ;
    USE SIGNAL ;
    PORT
      LAYER M3 ;
        RECT  25.308 103.643 25.326 103.68 ;
    END
  END a_d[289]
  PIN a_d[28]
    DIRECTION INPUT ;
    USE SIGNAL ;
    PORT
      LAYER M5 ;
        RECT  18.384 103.596 18.408 103.68 ;
    END
  END a_d[28]
  PIN a_d[290]
    DIRECTION INPUT ;
    USE SIGNAL ;
    PORT
      LAYER M3 ;
        RECT  25.38 103.643 25.398 103.68 ;
    END
  END a_d[290]
  PIN a_d[291]
    DIRECTION INPUT ;
    USE SIGNAL ;
    PORT
      LAYER M3 ;
        RECT  25.452 103.643 25.47 103.68 ;
    END
  END a_d[291]
  PIN a_d[292]
    DIRECTION INPUT ;
    USE SIGNAL ;
    PORT
      LAYER M3 ;
        RECT  25.524 103.643 25.542 103.68 ;
    END
  END a_d[292]
  PIN a_d[293]
    DIRECTION INPUT ;
    USE SIGNAL ;
    PORT
      LAYER M3 ;
        RECT  25.596 103.643 25.614 103.68 ;
    END
  END a_d[293]
  PIN a_d[294]
    DIRECTION INPUT ;
    USE SIGNAL ;
    PORT
      LAYER M3 ;
        RECT  25.668 103.643 25.686 103.68 ;
    END
  END a_d[294]
  PIN a_d[295]
    DIRECTION INPUT ;
    USE SIGNAL ;
    PORT
      LAYER M3 ;
        RECT  25.74 103.643 25.758 103.68 ;
    END
  END a_d[295]
  PIN a_d[296]
    DIRECTION INPUT ;
    USE SIGNAL ;
    PORT
      LAYER M3 ;
        RECT  25.812 103.643 25.83 103.68 ;
    END
  END a_d[296]
  PIN a_d[297]
    DIRECTION INPUT ;
    USE SIGNAL ;
    PORT
      LAYER M3 ;
        RECT  25.884 103.643 25.902 103.68 ;
    END
  END a_d[297]
  PIN a_d[298]
    DIRECTION INPUT ;
    USE SIGNAL ;
    PORT
      LAYER M3 ;
        RECT  25.956 103.643 25.974 103.68 ;
    END
  END a_d[298]
  PIN a_d[299]
    DIRECTION INPUT ;
    USE SIGNAL ;
    PORT
      LAYER M3 ;
        RECT  26.028 103.643 26.046 103.68 ;
    END
  END a_d[299]
  PIN a_d[29]
    DIRECTION INPUT ;
    USE SIGNAL ;
    PORT
      LAYER M5 ;
        RECT  18.48 103.596 18.504 103.68 ;
    END
  END a_d[29]
  PIN a_d[2]
    DIRECTION INPUT ;
    USE SIGNAL ;
    PORT
      LAYER M5 ;
        RECT  15.888 103.596 15.912 103.68 ;
    END
  END a_d[2]
  PIN a_d[300]
    DIRECTION INPUT ;
    USE SIGNAL ;
    PORT
      LAYER M3 ;
        RECT  26.1 103.643 26.118 103.68 ;
    END
  END a_d[300]
  PIN a_d[301]
    DIRECTION INPUT ;
    USE SIGNAL ;
    PORT
      LAYER M3 ;
        RECT  26.172 103.643 26.19 103.68 ;
    END
  END a_d[301]
  PIN a_d[302]
    DIRECTION INPUT ;
    USE SIGNAL ;
    PORT
      LAYER M3 ;
        RECT  26.244 103.643 26.262 103.68 ;
    END
  END a_d[302]
  PIN a_d[303]
    DIRECTION INPUT ;
    USE SIGNAL ;
    PORT
      LAYER M3 ;
        RECT  26.316 103.643 26.334 103.68 ;
    END
  END a_d[303]
  PIN a_d[304]
    DIRECTION INPUT ;
    USE SIGNAL ;
    PORT
      LAYER M3 ;
        RECT  26.388 103.643 26.406 103.68 ;
    END
  END a_d[304]
  PIN a_d[305]
    DIRECTION INPUT ;
    USE SIGNAL ;
    PORT
      LAYER M3 ;
        RECT  26.46 103.643 26.478 103.68 ;
    END
  END a_d[305]
  PIN a_d[306]
    DIRECTION INPUT ;
    USE SIGNAL ;
    PORT
      LAYER M3 ;
        RECT  26.532 103.643 26.55 103.68 ;
    END
  END a_d[306]
  PIN a_d[307]
    DIRECTION INPUT ;
    USE SIGNAL ;
    PORT
      LAYER M3 ;
        RECT  26.604 103.643 26.622 103.68 ;
    END
  END a_d[307]
  PIN a_d[308]
    DIRECTION INPUT ;
    USE SIGNAL ;
    PORT
      LAYER M3 ;
        RECT  26.676 103.643 26.694 103.68 ;
    END
  END a_d[308]
  PIN a_d[309]
    DIRECTION INPUT ;
    USE SIGNAL ;
    PORT
      LAYER M3 ;
        RECT  26.748 103.643 26.766 103.68 ;
    END
  END a_d[309]
  PIN a_d[30]
    DIRECTION INPUT ;
    USE SIGNAL ;
    PORT
      LAYER M5 ;
        RECT  18.576 103.596 18.6 103.68 ;
    END
  END a_d[30]
  PIN a_d[310]
    DIRECTION INPUT ;
    USE SIGNAL ;
    PORT
      LAYER M3 ;
        RECT  26.82 103.643 26.838 103.68 ;
    END
  END a_d[310]
  PIN a_d[311]
    DIRECTION INPUT ;
    USE SIGNAL ;
    PORT
      LAYER M3 ;
        RECT  26.892 103.643 26.91 103.68 ;
    END
  END a_d[311]
  PIN a_d[312]
    DIRECTION INPUT ;
    USE SIGNAL ;
    PORT
      LAYER M3 ;
        RECT  26.964 103.643 26.982 103.68 ;
    END
  END a_d[312]
  PIN a_d[313]
    DIRECTION INPUT ;
    USE SIGNAL ;
    PORT
      LAYER M3 ;
        RECT  27.036 103.643 27.054 103.68 ;
    END
  END a_d[313]
  PIN a_d[314]
    DIRECTION INPUT ;
    USE SIGNAL ;
    PORT
      LAYER M3 ;
        RECT  27.108 103.643 27.126 103.68 ;
    END
  END a_d[314]
  PIN a_d[315]
    DIRECTION INPUT ;
    USE SIGNAL ;
    PORT
      LAYER M3 ;
        RECT  27.18 103.643 27.198 103.68 ;
    END
  END a_d[315]
  PIN a_d[316]
    DIRECTION INPUT ;
    USE SIGNAL ;
    PORT
      LAYER M3 ;
        RECT  27.252 103.643 27.27 103.68 ;
    END
  END a_d[316]
  PIN a_d[317]
    DIRECTION INPUT ;
    USE SIGNAL ;
    PORT
      LAYER M3 ;
        RECT  27.324 103.643 27.342 103.68 ;
    END
  END a_d[317]
  PIN a_d[318]
    DIRECTION INPUT ;
    USE SIGNAL ;
    PORT
      LAYER M3 ;
        RECT  27.396 103.643 27.414 103.68 ;
    END
  END a_d[318]
  PIN a_d[319]
    DIRECTION INPUT ;
    USE SIGNAL ;
    PORT
      LAYER M3 ;
        RECT  27.468 103.643 27.486 103.68 ;
    END
  END a_d[319]
  PIN a_d[31]
    DIRECTION INPUT ;
    USE SIGNAL ;
    PORT
      LAYER M5 ;
        RECT  18.672 103.596 18.696 103.68 ;
    END
  END a_d[31]
  PIN a_d[320]
    DIRECTION INPUT ;
    USE SIGNAL ;
    PORT
      LAYER M3 ;
        RECT  27.54 103.643 27.558 103.68 ;
    END
  END a_d[320]
  PIN a_d[321]
    DIRECTION INPUT ;
    USE SIGNAL ;
    PORT
      LAYER M3 ;
        RECT  27.612 103.643 27.63 103.68 ;
    END
  END a_d[321]
  PIN a_d[322]
    DIRECTION INPUT ;
    USE SIGNAL ;
    PORT
      LAYER M3 ;
        RECT  27.684 103.643 27.702 103.68 ;
    END
  END a_d[322]
  PIN a_d[323]
    DIRECTION INPUT ;
    USE SIGNAL ;
    PORT
      LAYER M3 ;
        RECT  27.756 103.643 27.774 103.68 ;
    END
  END a_d[323]
  PIN a_d[324]
    DIRECTION INPUT ;
    USE SIGNAL ;
    PORT
      LAYER M3 ;
        RECT  27.828 103.643 27.846 103.68 ;
    END
  END a_d[324]
  PIN a_d[325]
    DIRECTION INPUT ;
    USE SIGNAL ;
    PORT
      LAYER M3 ;
        RECT  27.9 103.643 27.918 103.68 ;
    END
  END a_d[325]
  PIN a_d[326]
    DIRECTION INPUT ;
    USE SIGNAL ;
    PORT
      LAYER M3 ;
        RECT  27.972 103.643 27.99 103.68 ;
    END
  END a_d[326]
  PIN a_d[327]
    DIRECTION INPUT ;
    USE SIGNAL ;
    PORT
      LAYER M3 ;
        RECT  28.044 103.643 28.062 103.68 ;
    END
  END a_d[327]
  PIN a_d[328]
    DIRECTION INPUT ;
    USE SIGNAL ;
    PORT
      LAYER M3 ;
        RECT  28.116 103.643 28.134 103.68 ;
    END
  END a_d[328]
  PIN a_d[329]
    DIRECTION INPUT ;
    USE SIGNAL ;
    PORT
      LAYER M3 ;
        RECT  28.188 103.643 28.206 103.68 ;
    END
  END a_d[329]
  PIN a_d[32]
    DIRECTION INPUT ;
    USE SIGNAL ;
    PORT
      LAYER M3 ;
        RECT  36.756 103.643 36.774 103.68 ;
    END
  END a_d[32]
  PIN a_d[330]
    DIRECTION INPUT ;
    USE SIGNAL ;
    PORT
      LAYER M3 ;
        RECT  28.26 103.643 28.278 103.68 ;
    END
  END a_d[330]
  PIN a_d[331]
    DIRECTION INPUT ;
    USE SIGNAL ;
    PORT
      LAYER M3 ;
        RECT  28.332 103.643 28.35 103.68 ;
    END
  END a_d[331]
  PIN a_d[332]
    DIRECTION INPUT ;
    USE SIGNAL ;
    PORT
      LAYER M3 ;
        RECT  28.404 103.643 28.422 103.68 ;
    END
  END a_d[332]
  PIN a_d[333]
    DIRECTION INPUT ;
    USE SIGNAL ;
    PORT
      LAYER M3 ;
        RECT  28.476 103.643 28.494 103.68 ;
    END
  END a_d[333]
  PIN a_d[334]
    DIRECTION INPUT ;
    USE SIGNAL ;
    PORT
      LAYER M3 ;
        RECT  28.548 103.643 28.566 103.68 ;
    END
  END a_d[334]
  PIN a_d[335]
    DIRECTION INPUT ;
    USE SIGNAL ;
    PORT
      LAYER M3 ;
        RECT  28.62 103.643 28.638 103.68 ;
    END
  END a_d[335]
  PIN a_d[336]
    DIRECTION INPUT ;
    USE SIGNAL ;
    PORT
      LAYER M3 ;
        RECT  28.692 103.643 28.71 103.68 ;
    END
  END a_d[336]
  PIN a_d[337]
    DIRECTION INPUT ;
    USE SIGNAL ;
    PORT
      LAYER M3 ;
        RECT  28.764 103.643 28.782 103.68 ;
    END
  END a_d[337]
  PIN a_d[338]
    DIRECTION INPUT ;
    USE SIGNAL ;
    PORT
      LAYER M3 ;
        RECT  28.836 103.643 28.854 103.68 ;
    END
  END a_d[338]
  PIN a_d[339]
    DIRECTION INPUT ;
    USE SIGNAL ;
    PORT
      LAYER M3 ;
        RECT  28.908 103.643 28.926 103.68 ;
    END
  END a_d[339]
  PIN a_d[33]
    DIRECTION INPUT ;
    USE SIGNAL ;
    PORT
      LAYER M3 ;
        RECT  36.828 103.643 36.846 103.68 ;
    END
  END a_d[33]
  PIN a_d[340]
    DIRECTION INPUT ;
    USE SIGNAL ;
    PORT
      LAYER M3 ;
        RECT  28.98 103.643 28.998 103.68 ;
    END
  END a_d[340]
  PIN a_d[341]
    DIRECTION INPUT ;
    USE SIGNAL ;
    PORT
      LAYER M3 ;
        RECT  29.052 103.643 29.07 103.68 ;
    END
  END a_d[341]
  PIN a_d[342]
    DIRECTION INPUT ;
    USE SIGNAL ;
    PORT
      LAYER M3 ;
        RECT  29.124 103.643 29.142 103.68 ;
    END
  END a_d[342]
  PIN a_d[343]
    DIRECTION INPUT ;
    USE SIGNAL ;
    PORT
      LAYER M3 ;
        RECT  29.196 103.643 29.214 103.68 ;
    END
  END a_d[343]
  PIN a_d[344]
    DIRECTION INPUT ;
    USE SIGNAL ;
    PORT
      LAYER M3 ;
        RECT  29.268 103.643 29.286 103.68 ;
    END
  END a_d[344]
  PIN a_d[345]
    DIRECTION INPUT ;
    USE SIGNAL ;
    PORT
      LAYER M3 ;
        RECT  29.34 103.643 29.358 103.68 ;
    END
  END a_d[345]
  PIN a_d[346]
    DIRECTION INPUT ;
    USE SIGNAL ;
    PORT
      LAYER M3 ;
        RECT  29.412 103.643 29.43 103.68 ;
    END
  END a_d[346]
  PIN a_d[347]
    DIRECTION INPUT ;
    USE SIGNAL ;
    PORT
      LAYER M3 ;
        RECT  29.484 103.643 29.502 103.68 ;
    END
  END a_d[347]
  PIN a_d[348]
    DIRECTION INPUT ;
    USE SIGNAL ;
    PORT
      LAYER M3 ;
        RECT  29.556 103.643 29.574 103.68 ;
    END
  END a_d[348]
  PIN a_d[349]
    DIRECTION INPUT ;
    USE SIGNAL ;
    PORT
      LAYER M3 ;
        RECT  29.628 103.643 29.646 103.68 ;
    END
  END a_d[349]
  PIN a_d[34]
    DIRECTION INPUT ;
    USE SIGNAL ;
    PORT
      LAYER M3 ;
        RECT  36.9 103.643 36.918 103.68 ;
    END
  END a_d[34]
  PIN a_d[350]
    DIRECTION INPUT ;
    USE SIGNAL ;
    PORT
      LAYER M3 ;
        RECT  29.7 103.643 29.718 103.68 ;
    END
  END a_d[350]
  PIN a_d[351]
    DIRECTION INPUT ;
    USE SIGNAL ;
    PORT
      LAYER M3 ;
        RECT  29.772 103.643 29.79 103.68 ;
    END
  END a_d[351]
  PIN a_d[352]
    DIRECTION INPUT ;
    USE SIGNAL ;
    PORT
      LAYER M3 ;
        RECT  34.452 103.643 34.47 103.68 ;
    END
  END a_d[352]
  PIN a_d[353]
    DIRECTION INPUT ;
    USE SIGNAL ;
    PORT
      LAYER M3 ;
        RECT  34.524 103.643 34.542 103.68 ;
    END
  END a_d[353]
  PIN a_d[354]
    DIRECTION INPUT ;
    USE SIGNAL ;
    PORT
      LAYER M3 ;
        RECT  34.596 103.643 34.614 103.68 ;
    END
  END a_d[354]
  PIN a_d[355]
    DIRECTION INPUT ;
    USE SIGNAL ;
    PORT
      LAYER M3 ;
        RECT  34.668 103.643 34.686 103.68 ;
    END
  END a_d[355]
  PIN a_d[356]
    DIRECTION INPUT ;
    USE SIGNAL ;
    PORT
      LAYER M3 ;
        RECT  34.74 103.643 34.758 103.68 ;
    END
  END a_d[356]
  PIN a_d[357]
    DIRECTION INPUT ;
    USE SIGNAL ;
    PORT
      LAYER M3 ;
        RECT  34.812 103.643 34.83 103.68 ;
    END
  END a_d[357]
  PIN a_d[358]
    DIRECTION INPUT ;
    USE SIGNAL ;
    PORT
      LAYER M3 ;
        RECT  34.884 103.643 34.902 103.68 ;
    END
  END a_d[358]
  PIN a_d[359]
    DIRECTION INPUT ;
    USE SIGNAL ;
    PORT
      LAYER M3 ;
        RECT  34.956 103.643 34.974 103.68 ;
    END
  END a_d[359]
  PIN a_d[35]
    DIRECTION INPUT ;
    USE SIGNAL ;
    PORT
      LAYER M3 ;
        RECT  36.972 103.643 36.99 103.68 ;
    END
  END a_d[35]
  PIN a_d[360]
    DIRECTION INPUT ;
    USE SIGNAL ;
    PORT
      LAYER M3 ;
        RECT  35.028 103.643 35.046 103.68 ;
    END
  END a_d[360]
  PIN a_d[361]
    DIRECTION INPUT ;
    USE SIGNAL ;
    PORT
      LAYER M3 ;
        RECT  35.1 103.643 35.118 103.68 ;
    END
  END a_d[361]
  PIN a_d[362]
    DIRECTION INPUT ;
    USE SIGNAL ;
    PORT
      LAYER M3 ;
        RECT  35.172 103.643 35.19 103.68 ;
    END
  END a_d[362]
  PIN a_d[363]
    DIRECTION INPUT ;
    USE SIGNAL ;
    PORT
      LAYER M3 ;
        RECT  35.244 103.643 35.262 103.68 ;
    END
  END a_d[363]
  PIN a_d[364]
    DIRECTION INPUT ;
    USE SIGNAL ;
    PORT
      LAYER M3 ;
        RECT  35.316 103.643 35.334 103.68 ;
    END
  END a_d[364]
  PIN a_d[365]
    DIRECTION INPUT ;
    USE SIGNAL ;
    PORT
      LAYER M3 ;
        RECT  35.388 103.643 35.406 103.68 ;
    END
  END a_d[365]
  PIN a_d[366]
    DIRECTION INPUT ;
    USE SIGNAL ;
    PORT
      LAYER M3 ;
        RECT  35.46 103.643 35.478 103.68 ;
    END
  END a_d[366]
  PIN a_d[367]
    DIRECTION INPUT ;
    USE SIGNAL ;
    PORT
      LAYER M3 ;
        RECT  35.532 103.643 35.55 103.68 ;
    END
  END a_d[367]
  PIN a_d[368]
    DIRECTION INPUT ;
    USE SIGNAL ;
    PORT
      LAYER M3 ;
        RECT  35.604 103.643 35.622 103.68 ;
    END
  END a_d[368]
  PIN a_d[369]
    DIRECTION INPUT ;
    USE SIGNAL ;
    PORT
      LAYER M3 ;
        RECT  35.676 103.643 35.694 103.68 ;
    END
  END a_d[369]
  PIN a_d[36]
    DIRECTION INPUT ;
    USE SIGNAL ;
    PORT
      LAYER M3 ;
        RECT  37.044 103.643 37.062 103.68 ;
    END
  END a_d[36]
  PIN a_d[370]
    DIRECTION INPUT ;
    USE SIGNAL ;
    PORT
      LAYER M3 ;
        RECT  35.748 103.643 35.766 103.68 ;
    END
  END a_d[370]
  PIN a_d[371]
    DIRECTION INPUT ;
    USE SIGNAL ;
    PORT
      LAYER M3 ;
        RECT  35.82 103.643 35.838 103.68 ;
    END
  END a_d[371]
  PIN a_d[372]
    DIRECTION INPUT ;
    USE SIGNAL ;
    PORT
      LAYER M3 ;
        RECT  35.892 103.643 35.91 103.68 ;
    END
  END a_d[372]
  PIN a_d[373]
    DIRECTION INPUT ;
    USE SIGNAL ;
    PORT
      LAYER M3 ;
        RECT  35.964 103.643 35.982 103.68 ;
    END
  END a_d[373]
  PIN a_d[374]
    DIRECTION INPUT ;
    USE SIGNAL ;
    PORT
      LAYER M3 ;
        RECT  36.036 103.643 36.054 103.68 ;
    END
  END a_d[374]
  PIN a_d[375]
    DIRECTION INPUT ;
    USE SIGNAL ;
    PORT
      LAYER M3 ;
        RECT  36.108 103.643 36.126 103.68 ;
    END
  END a_d[375]
  PIN a_d[376]
    DIRECTION INPUT ;
    USE SIGNAL ;
    PORT
      LAYER M3 ;
        RECT  36.18 103.643 36.198 103.68 ;
    END
  END a_d[376]
  PIN a_d[377]
    DIRECTION INPUT ;
    USE SIGNAL ;
    PORT
      LAYER M3 ;
        RECT  36.252 103.643 36.27 103.68 ;
    END
  END a_d[377]
  PIN a_d[378]
    DIRECTION INPUT ;
    USE SIGNAL ;
    PORT
      LAYER M3 ;
        RECT  36.324 103.643 36.342 103.68 ;
    END
  END a_d[378]
  PIN a_d[379]
    DIRECTION INPUT ;
    USE SIGNAL ;
    PORT
      LAYER M3 ;
        RECT  36.396 103.643 36.414 103.68 ;
    END
  END a_d[379]
  PIN a_d[37]
    DIRECTION INPUT ;
    USE SIGNAL ;
    PORT
      LAYER M3 ;
        RECT  37.116 103.643 37.134 103.68 ;
    END
  END a_d[37]
  PIN a_d[380]
    DIRECTION INPUT ;
    USE SIGNAL ;
    PORT
      LAYER M3 ;
        RECT  36.468 103.643 36.486 103.68 ;
    END
  END a_d[380]
  PIN a_d[381]
    DIRECTION INPUT ;
    USE SIGNAL ;
    PORT
      LAYER M3 ;
        RECT  36.54 103.643 36.558 103.68 ;
    END
  END a_d[381]
  PIN a_d[382]
    DIRECTION INPUT ;
    USE SIGNAL ;
    PORT
      LAYER M3 ;
        RECT  36.612 103.643 36.63 103.68 ;
    END
  END a_d[382]
  PIN a_d[383]
    DIRECTION INPUT ;
    USE SIGNAL ;
    PORT
      LAYER M3 ;
        RECT  36.684 103.643 36.702 103.68 ;
    END
  END a_d[383]
  PIN a_d[384]
    DIRECTION INPUT ;
    USE SIGNAL ;
    PORT
      LAYER M3 ;
        RECT  29.844 103.643 29.862 103.68 ;
    END
  END a_d[384]
  PIN a_d[385]
    DIRECTION INPUT ;
    USE SIGNAL ;
    PORT
      LAYER M3 ;
        RECT  29.916 103.643 29.934 103.68 ;
    END
  END a_d[385]
  PIN a_d[386]
    DIRECTION INPUT ;
    USE SIGNAL ;
    PORT
      LAYER M3 ;
        RECT  29.988 103.643 30.006 103.68 ;
    END
  END a_d[386]
  PIN a_d[387]
    DIRECTION INPUT ;
    USE SIGNAL ;
    PORT
      LAYER M3 ;
        RECT  30.06 103.643 30.078 103.68 ;
    END
  END a_d[387]
  PIN a_d[388]
    DIRECTION INPUT ;
    USE SIGNAL ;
    PORT
      LAYER M3 ;
        RECT  30.132 103.643 30.15 103.68 ;
    END
  END a_d[388]
  PIN a_d[389]
    DIRECTION INPUT ;
    USE SIGNAL ;
    PORT
      LAYER M3 ;
        RECT  30.204 103.643 30.222 103.68 ;
    END
  END a_d[389]
  PIN a_d[38]
    DIRECTION INPUT ;
    USE SIGNAL ;
    PORT
      LAYER M3 ;
        RECT  37.188 103.643 37.206 103.68 ;
    END
  END a_d[38]
  PIN a_d[390]
    DIRECTION INPUT ;
    USE SIGNAL ;
    PORT
      LAYER M3 ;
        RECT  30.276 103.643 30.294 103.68 ;
    END
  END a_d[390]
  PIN a_d[391]
    DIRECTION INPUT ;
    USE SIGNAL ;
    PORT
      LAYER M3 ;
        RECT  30.348 103.643 30.366 103.68 ;
    END
  END a_d[391]
  PIN a_d[392]
    DIRECTION INPUT ;
    USE SIGNAL ;
    PORT
      LAYER M3 ;
        RECT  30.42 103.643 30.438 103.68 ;
    END
  END a_d[392]
  PIN a_d[393]
    DIRECTION INPUT ;
    USE SIGNAL ;
    PORT
      LAYER M3 ;
        RECT  30.492 103.643 30.51 103.68 ;
    END
  END a_d[393]
  PIN a_d[394]
    DIRECTION INPUT ;
    USE SIGNAL ;
    PORT
      LAYER M3 ;
        RECT  30.564 103.643 30.582 103.68 ;
    END
  END a_d[394]
  PIN a_d[395]
    DIRECTION INPUT ;
    USE SIGNAL ;
    PORT
      LAYER M3 ;
        RECT  30.636 103.643 30.654 103.68 ;
    END
  END a_d[395]
  PIN a_d[396]
    DIRECTION INPUT ;
    USE SIGNAL ;
    PORT
      LAYER M3 ;
        RECT  30.708 103.643 30.726 103.68 ;
    END
  END a_d[396]
  PIN a_d[397]
    DIRECTION INPUT ;
    USE SIGNAL ;
    PORT
      LAYER M3 ;
        RECT  30.78 103.643 30.798 103.68 ;
    END
  END a_d[397]
  PIN a_d[398]
    DIRECTION INPUT ;
    USE SIGNAL ;
    PORT
      LAYER M3 ;
        RECT  30.852 103.643 30.87 103.68 ;
    END
  END a_d[398]
  PIN a_d[399]
    DIRECTION INPUT ;
    USE SIGNAL ;
    PORT
      LAYER M3 ;
        RECT  30.924 103.643 30.942 103.68 ;
    END
  END a_d[399]
  PIN a_d[39]
    DIRECTION INPUT ;
    USE SIGNAL ;
    PORT
      LAYER M3 ;
        RECT  37.26 103.643 37.278 103.68 ;
    END
  END a_d[39]
  PIN a_d[3]
    DIRECTION INPUT ;
    USE SIGNAL ;
    PORT
      LAYER M5 ;
        RECT  15.984 103.596 16.008 103.68 ;
    END
  END a_d[3]
  PIN a_d[400]
    DIRECTION INPUT ;
    USE SIGNAL ;
    PORT
      LAYER M3 ;
        RECT  30.996 103.643 31.014 103.68 ;
    END
  END a_d[400]
  PIN a_d[401]
    DIRECTION INPUT ;
    USE SIGNAL ;
    PORT
      LAYER M3 ;
        RECT  31.068 103.643 31.086 103.68 ;
    END
  END a_d[401]
  PIN a_d[402]
    DIRECTION INPUT ;
    USE SIGNAL ;
    PORT
      LAYER M3 ;
        RECT  31.14 103.643 31.158 103.68 ;
    END
  END a_d[402]
  PIN a_d[403]
    DIRECTION INPUT ;
    USE SIGNAL ;
    PORT
      LAYER M3 ;
        RECT  31.212 103.643 31.23 103.68 ;
    END
  END a_d[403]
  PIN a_d[404]
    DIRECTION INPUT ;
    USE SIGNAL ;
    PORT
      LAYER M3 ;
        RECT  31.284 103.643 31.302 103.68 ;
    END
  END a_d[404]
  PIN a_d[405]
    DIRECTION INPUT ;
    USE SIGNAL ;
    PORT
      LAYER M3 ;
        RECT  31.356 103.643 31.374 103.68 ;
    END
  END a_d[405]
  PIN a_d[406]
    DIRECTION INPUT ;
    USE SIGNAL ;
    PORT
      LAYER M3 ;
        RECT  31.428 103.643 31.446 103.68 ;
    END
  END a_d[406]
  PIN a_d[407]
    DIRECTION INPUT ;
    USE SIGNAL ;
    PORT
      LAYER M3 ;
        RECT  31.5 103.643 31.518 103.68 ;
    END
  END a_d[407]
  PIN a_d[408]
    DIRECTION INPUT ;
    USE SIGNAL ;
    PORT
      LAYER M3 ;
        RECT  31.572 103.643 31.59 103.68 ;
    END
  END a_d[408]
  PIN a_d[409]
    DIRECTION INPUT ;
    USE SIGNAL ;
    PORT
      LAYER M3 ;
        RECT  31.644 103.643 31.662 103.68 ;
    END
  END a_d[409]
  PIN a_d[40]
    DIRECTION INPUT ;
    USE SIGNAL ;
    PORT
      LAYER M3 ;
        RECT  37.332 103.643 37.35 103.68 ;
    END
  END a_d[40]
  PIN a_d[410]
    DIRECTION INPUT ;
    USE SIGNAL ;
    PORT
      LAYER M3 ;
        RECT  31.716 103.643 31.734 103.68 ;
    END
  END a_d[410]
  PIN a_d[411]
    DIRECTION INPUT ;
    USE SIGNAL ;
    PORT
      LAYER M3 ;
        RECT  31.788 103.643 31.806 103.68 ;
    END
  END a_d[411]
  PIN a_d[412]
    DIRECTION INPUT ;
    USE SIGNAL ;
    PORT
      LAYER M3 ;
        RECT  31.86 103.643 31.878 103.68 ;
    END
  END a_d[412]
  PIN a_d[413]
    DIRECTION INPUT ;
    USE SIGNAL ;
    PORT
      LAYER M3 ;
        RECT  31.932 103.643 31.95 103.68 ;
    END
  END a_d[413]
  PIN a_d[414]
    DIRECTION INPUT ;
    USE SIGNAL ;
    PORT
      LAYER M3 ;
        RECT  32.004 103.643 32.022 103.68 ;
    END
  END a_d[414]
  PIN a_d[415]
    DIRECTION INPUT ;
    USE SIGNAL ;
    PORT
      LAYER M3 ;
        RECT  32.076 103.643 32.094 103.68 ;
    END
  END a_d[415]
  PIN a_d[416]
    DIRECTION INPUT ;
    USE SIGNAL ;
    PORT
      LAYER M3 ;
        RECT  20.052 103.643 20.07 103.68 ;
    END
  END a_d[416]
  PIN a_d[417]
    DIRECTION INPUT ;
    USE SIGNAL ;
    PORT
      LAYER M3 ;
        RECT  20.124 103.643 20.142 103.68 ;
    END
  END a_d[417]
  PIN a_d[418]
    DIRECTION INPUT ;
    USE SIGNAL ;
    PORT
      LAYER M3 ;
        RECT  20.196 103.643 20.214 103.68 ;
    END
  END a_d[418]
  PIN a_d[419]
    DIRECTION INPUT ;
    USE SIGNAL ;
    PORT
      LAYER M3 ;
        RECT  20.268 103.643 20.286 103.68 ;
    END
  END a_d[419]
  PIN a_d[41]
    DIRECTION INPUT ;
    USE SIGNAL ;
    PORT
      LAYER M3 ;
        RECT  37.404 103.643 37.422 103.68 ;
    END
  END a_d[41]
  PIN a_d[420]
    DIRECTION INPUT ;
    USE SIGNAL ;
    PORT
      LAYER M3 ;
        RECT  20.34 103.643 20.358 103.68 ;
    END
  END a_d[420]
  PIN a_d[421]
    DIRECTION INPUT ;
    USE SIGNAL ;
    PORT
      LAYER M3 ;
        RECT  20.412 103.643 20.43 103.68 ;
    END
  END a_d[421]
  PIN a_d[422]
    DIRECTION INPUT ;
    USE SIGNAL ;
    PORT
      LAYER M3 ;
        RECT  20.484 103.643 20.502 103.68 ;
    END
  END a_d[422]
  PIN a_d[423]
    DIRECTION INPUT ;
    USE SIGNAL ;
    PORT
      LAYER M3 ;
        RECT  20.556 103.643 20.574 103.68 ;
    END
  END a_d[423]
  PIN a_d[424]
    DIRECTION INPUT ;
    USE SIGNAL ;
    PORT
      LAYER M3 ;
        RECT  20.628 103.643 20.646 103.68 ;
    END
  END a_d[424]
  PIN a_d[425]
    DIRECTION INPUT ;
    USE SIGNAL ;
    PORT
      LAYER M3 ;
        RECT  20.7 103.643 20.718 103.68 ;
    END
  END a_d[425]
  PIN a_d[426]
    DIRECTION INPUT ;
    USE SIGNAL ;
    PORT
      LAYER M3 ;
        RECT  20.772 103.643 20.79 103.68 ;
    END
  END a_d[426]
  PIN a_d[427]
    DIRECTION INPUT ;
    USE SIGNAL ;
    PORT
      LAYER M3 ;
        RECT  20.844 103.643 20.862 103.68 ;
    END
  END a_d[427]
  PIN a_d[428]
    DIRECTION INPUT ;
    USE SIGNAL ;
    PORT
      LAYER M3 ;
        RECT  20.916 103.643 20.934 103.68 ;
    END
  END a_d[428]
  PIN a_d[429]
    DIRECTION INPUT ;
    USE SIGNAL ;
    PORT
      LAYER M3 ;
        RECT  20.988 103.643 21.006 103.68 ;
    END
  END a_d[429]
  PIN a_d[42]
    DIRECTION INPUT ;
    USE SIGNAL ;
    PORT
      LAYER M3 ;
        RECT  37.476 103.643 37.494 103.68 ;
    END
  END a_d[42]
  PIN a_d[430]
    DIRECTION INPUT ;
    USE SIGNAL ;
    PORT
      LAYER M3 ;
        RECT  21.06 103.643 21.078 103.68 ;
    END
  END a_d[430]
  PIN a_d[431]
    DIRECTION INPUT ;
    USE SIGNAL ;
    PORT
      LAYER M3 ;
        RECT  21.132 103.643 21.15 103.68 ;
    END
  END a_d[431]
  PIN a_d[432]
    DIRECTION INPUT ;
    USE SIGNAL ;
    PORT
      LAYER M3 ;
        RECT  21.204 103.643 21.222 103.68 ;
    END
  END a_d[432]
  PIN a_d[433]
    DIRECTION INPUT ;
    USE SIGNAL ;
    PORT
      LAYER M3 ;
        RECT  21.276 103.643 21.294 103.68 ;
    END
  END a_d[433]
  PIN a_d[434]
    DIRECTION INPUT ;
    USE SIGNAL ;
    PORT
      LAYER M3 ;
        RECT  21.348 103.643 21.366 103.68 ;
    END
  END a_d[434]
  PIN a_d[435]
    DIRECTION INPUT ;
    USE SIGNAL ;
    PORT
      LAYER M3 ;
        RECT  21.42 103.643 21.438 103.68 ;
    END
  END a_d[435]
  PIN a_d[436]
    DIRECTION INPUT ;
    USE SIGNAL ;
    PORT
      LAYER M3 ;
        RECT  21.492 103.643 21.51 103.68 ;
    END
  END a_d[436]
  PIN a_d[437]
    DIRECTION INPUT ;
    USE SIGNAL ;
    PORT
      LAYER M3 ;
        RECT  21.564 103.643 21.582 103.68 ;
    END
  END a_d[437]
  PIN a_d[438]
    DIRECTION INPUT ;
    USE SIGNAL ;
    PORT
      LAYER M3 ;
        RECT  21.636 103.643 21.654 103.68 ;
    END
  END a_d[438]
  PIN a_d[439]
    DIRECTION INPUT ;
    USE SIGNAL ;
    PORT
      LAYER M3 ;
        RECT  21.708 103.643 21.726 103.68 ;
    END
  END a_d[439]
  PIN a_d[43]
    DIRECTION INPUT ;
    USE SIGNAL ;
    PORT
      LAYER M3 ;
        RECT  37.548 103.643 37.566 103.68 ;
    END
  END a_d[43]
  PIN a_d[440]
    DIRECTION INPUT ;
    USE SIGNAL ;
    PORT
      LAYER M3 ;
        RECT  21.78 103.643 21.798 103.68 ;
    END
  END a_d[440]
  PIN a_d[441]
    DIRECTION INPUT ;
    USE SIGNAL ;
    PORT
      LAYER M3 ;
        RECT  21.852 103.643 21.87 103.68 ;
    END
  END a_d[441]
  PIN a_d[442]
    DIRECTION INPUT ;
    USE SIGNAL ;
    PORT
      LAYER M3 ;
        RECT  21.924 103.643 21.942 103.68 ;
    END
  END a_d[442]
  PIN a_d[443]
    DIRECTION INPUT ;
    USE SIGNAL ;
    PORT
      LAYER M3 ;
        RECT  21.996 103.643 22.014 103.68 ;
    END
  END a_d[443]
  PIN a_d[444]
    DIRECTION INPUT ;
    USE SIGNAL ;
    PORT
      LAYER M3 ;
        RECT  22.068 103.643 22.086 103.68 ;
    END
  END a_d[444]
  PIN a_d[445]
    DIRECTION INPUT ;
    USE SIGNAL ;
    PORT
      LAYER M3 ;
        RECT  22.14 103.643 22.158 103.68 ;
    END
  END a_d[445]
  PIN a_d[446]
    DIRECTION INPUT ;
    USE SIGNAL ;
    PORT
      LAYER M3 ;
        RECT  22.212 103.643 22.23 103.68 ;
    END
  END a_d[446]
  PIN a_d[447]
    DIRECTION INPUT ;
    USE SIGNAL ;
    PORT
      LAYER M3 ;
        RECT  22.284 103.643 22.302 103.68 ;
    END
  END a_d[447]
  PIN a_d[448]
    DIRECTION INPUT ;
    USE SIGNAL ;
    PORT
      LAYER M3 ;
        RECT  17.748 103.643 17.766 103.68 ;
    END
  END a_d[448]
  PIN a_d[449]
    DIRECTION INPUT ;
    USE SIGNAL ;
    PORT
      LAYER M3 ;
        RECT  17.82 103.643 17.838 103.68 ;
    END
  END a_d[449]
  PIN a_d[44]
    DIRECTION INPUT ;
    USE SIGNAL ;
    PORT
      LAYER M3 ;
        RECT  37.62 103.643 37.638 103.68 ;
    END
  END a_d[44]
  PIN a_d[450]
    DIRECTION INPUT ;
    USE SIGNAL ;
    PORT
      LAYER M3 ;
        RECT  17.892 103.643 17.91 103.68 ;
    END
  END a_d[450]
  PIN a_d[451]
    DIRECTION INPUT ;
    USE SIGNAL ;
    PORT
      LAYER M3 ;
        RECT  17.964 103.643 17.982 103.68 ;
    END
  END a_d[451]
  PIN a_d[452]
    DIRECTION INPUT ;
    USE SIGNAL ;
    PORT
      LAYER M3 ;
        RECT  18.036 103.643 18.054 103.68 ;
    END
  END a_d[452]
  PIN a_d[453]
    DIRECTION INPUT ;
    USE SIGNAL ;
    PORT
      LAYER M3 ;
        RECT  18.108 103.643 18.126 103.68 ;
    END
  END a_d[453]
  PIN a_d[454]
    DIRECTION INPUT ;
    USE SIGNAL ;
    PORT
      LAYER M3 ;
        RECT  18.18 103.643 18.198 103.68 ;
    END
  END a_d[454]
  PIN a_d[455]
    DIRECTION INPUT ;
    USE SIGNAL ;
    PORT
      LAYER M3 ;
        RECT  18.252 103.643 18.27 103.68 ;
    END
  END a_d[455]
  PIN a_d[456]
    DIRECTION INPUT ;
    USE SIGNAL ;
    PORT
      LAYER M3 ;
        RECT  18.324 103.643 18.342 103.68 ;
    END
  END a_d[456]
  PIN a_d[457]
    DIRECTION INPUT ;
    USE SIGNAL ;
    PORT
      LAYER M3 ;
        RECT  18.396 103.643 18.414 103.68 ;
    END
  END a_d[457]
  PIN a_d[458]
    DIRECTION INPUT ;
    USE SIGNAL ;
    PORT
      LAYER M3 ;
        RECT  18.468 103.643 18.486 103.68 ;
    END
  END a_d[458]
  PIN a_d[459]
    DIRECTION INPUT ;
    USE SIGNAL ;
    PORT
      LAYER M3 ;
        RECT  18.54 103.643 18.558 103.68 ;
    END
  END a_d[459]
  PIN a_d[45]
    DIRECTION INPUT ;
    USE SIGNAL ;
    PORT
      LAYER M3 ;
        RECT  37.692 103.643 37.71 103.68 ;
    END
  END a_d[45]
  PIN a_d[460]
    DIRECTION INPUT ;
    USE SIGNAL ;
    PORT
      LAYER M3 ;
        RECT  18.612 103.643 18.63 103.68 ;
    END
  END a_d[460]
  PIN a_d[461]
    DIRECTION INPUT ;
    USE SIGNAL ;
    PORT
      LAYER M3 ;
        RECT  18.684 103.643 18.702 103.68 ;
    END
  END a_d[461]
  PIN a_d[462]
    DIRECTION INPUT ;
    USE SIGNAL ;
    PORT
      LAYER M3 ;
        RECT  18.756 103.643 18.774 103.68 ;
    END
  END a_d[462]
  PIN a_d[463]
    DIRECTION INPUT ;
    USE SIGNAL ;
    PORT
      LAYER M3 ;
        RECT  18.828 103.643 18.846 103.68 ;
    END
  END a_d[463]
  PIN a_d[464]
    DIRECTION INPUT ;
    USE SIGNAL ;
    PORT
      LAYER M3 ;
        RECT  18.9 103.643 18.918 103.68 ;
    END
  END a_d[464]
  PIN a_d[465]
    DIRECTION INPUT ;
    USE SIGNAL ;
    PORT
      LAYER M3 ;
        RECT  18.972 103.643 18.99 103.68 ;
    END
  END a_d[465]
  PIN a_d[466]
    DIRECTION INPUT ;
    USE SIGNAL ;
    PORT
      LAYER M3 ;
        RECT  19.044 103.643 19.062 103.68 ;
    END
  END a_d[466]
  PIN a_d[467]
    DIRECTION INPUT ;
    USE SIGNAL ;
    PORT
      LAYER M3 ;
        RECT  19.116 103.643 19.134 103.68 ;
    END
  END a_d[467]
  PIN a_d[468]
    DIRECTION INPUT ;
    USE SIGNAL ;
    PORT
      LAYER M3 ;
        RECT  19.188 103.643 19.206 103.68 ;
    END
  END a_d[468]
  PIN a_d[469]
    DIRECTION INPUT ;
    USE SIGNAL ;
    PORT
      LAYER M3 ;
        RECT  19.26 103.643 19.278 103.68 ;
    END
  END a_d[469]
  PIN a_d[46]
    DIRECTION INPUT ;
    USE SIGNAL ;
    PORT
      LAYER M3 ;
        RECT  37.764 103.643 37.782 103.68 ;
    END
  END a_d[46]
  PIN a_d[470]
    DIRECTION INPUT ;
    USE SIGNAL ;
    PORT
      LAYER M3 ;
        RECT  19.332 103.643 19.35 103.68 ;
    END
  END a_d[470]
  PIN a_d[471]
    DIRECTION INPUT ;
    USE SIGNAL ;
    PORT
      LAYER M3 ;
        RECT  19.404 103.643 19.422 103.68 ;
    END
  END a_d[471]
  PIN a_d[472]
    DIRECTION INPUT ;
    USE SIGNAL ;
    PORT
      LAYER M3 ;
        RECT  19.476 103.643 19.494 103.68 ;
    END
  END a_d[472]
  PIN a_d[473]
    DIRECTION INPUT ;
    USE SIGNAL ;
    PORT
      LAYER M3 ;
        RECT  19.548 103.643 19.566 103.68 ;
    END
  END a_d[473]
  PIN a_d[474]
    DIRECTION INPUT ;
    USE SIGNAL ;
    PORT
      LAYER M3 ;
        RECT  19.62 103.643 19.638 103.68 ;
    END
  END a_d[474]
  PIN a_d[475]
    DIRECTION INPUT ;
    USE SIGNAL ;
    PORT
      LAYER M3 ;
        RECT  19.692 103.643 19.71 103.68 ;
    END
  END a_d[475]
  PIN a_d[476]
    DIRECTION INPUT ;
    USE SIGNAL ;
    PORT
      LAYER M3 ;
        RECT  19.764 103.643 19.782 103.68 ;
    END
  END a_d[476]
  PIN a_d[477]
    DIRECTION INPUT ;
    USE SIGNAL ;
    PORT
      LAYER M3 ;
        RECT  19.836 103.643 19.854 103.68 ;
    END
  END a_d[477]
  PIN a_d[478]
    DIRECTION INPUT ;
    USE SIGNAL ;
    PORT
      LAYER M3 ;
        RECT  19.908 103.643 19.926 103.68 ;
    END
  END a_d[478]
  PIN a_d[479]
    DIRECTION INPUT ;
    USE SIGNAL ;
    PORT
      LAYER M3 ;
        RECT  19.98 103.643 19.998 103.68 ;
    END
  END a_d[479]
  PIN a_d[47]
    DIRECTION INPUT ;
    USE SIGNAL ;
    PORT
      LAYER M3 ;
        RECT  37.836 103.643 37.854 103.68 ;
    END
  END a_d[47]
  PIN a_d[480]
    DIRECTION INPUT ;
    USE SIGNAL ;
    PORT
      LAYER M3 ;
        RECT  22.572 103.643 22.59 103.68 ;
    END
  END a_d[480]
  PIN a_d[481]
    DIRECTION INPUT ;
    USE SIGNAL ;
    PORT
      LAYER M3 ;
        RECT  22.644 103.643 22.662 103.68 ;
    END
  END a_d[481]
  PIN a_d[482]
    DIRECTION INPUT ;
    USE SIGNAL ;
    PORT
      LAYER M3 ;
        RECT  22.716 103.643 22.734 103.68 ;
    END
  END a_d[482]
  PIN a_d[483]
    DIRECTION INPUT ;
    USE SIGNAL ;
    PORT
      LAYER M3 ;
        RECT  22.788 103.643 22.806 103.68 ;
    END
  END a_d[483]
  PIN a_d[484]
    DIRECTION INPUT ;
    USE SIGNAL ;
    PORT
      LAYER M3 ;
        RECT  22.86 103.643 22.878 103.68 ;
    END
  END a_d[484]
  PIN a_d[485]
    DIRECTION INPUT ;
    USE SIGNAL ;
    PORT
      LAYER M3 ;
        RECT  22.932 103.643 22.95 103.68 ;
    END
  END a_d[485]
  PIN a_d[486]
    DIRECTION INPUT ;
    USE SIGNAL ;
    PORT
      LAYER M3 ;
        RECT  23.004 103.643 23.022 103.68 ;
    END
  END a_d[486]
  PIN a_d[487]
    DIRECTION INPUT ;
    USE SIGNAL ;
    PORT
      LAYER M3 ;
        RECT  23.076 103.643 23.094 103.68 ;
    END
  END a_d[487]
  PIN a_d[488]
    DIRECTION INPUT ;
    USE SIGNAL ;
    PORT
      LAYER M3 ;
        RECT  23.148 103.643 23.166 103.68 ;
    END
  END a_d[488]
  PIN a_d[489]
    DIRECTION INPUT ;
    USE SIGNAL ;
    PORT
      LAYER M3 ;
        RECT  23.22 103.643 23.238 103.68 ;
    END
  END a_d[489]
  PIN a_d[48]
    DIRECTION INPUT ;
    USE SIGNAL ;
    PORT
      LAYER M3 ;
        RECT  37.908 103.643 37.926 103.68 ;
    END
  END a_d[48]
  PIN a_d[490]
    DIRECTION INPUT ;
    USE SIGNAL ;
    PORT
      LAYER M3 ;
        RECT  23.292 103.643 23.31 103.68 ;
    END
  END a_d[490]
  PIN a_d[491]
    DIRECTION INPUT ;
    USE SIGNAL ;
    PORT
      LAYER M3 ;
        RECT  23.364 103.643 23.382 103.68 ;
    END
  END a_d[491]
  PIN a_d[492]
    DIRECTION INPUT ;
    USE SIGNAL ;
    PORT
      LAYER M3 ;
        RECT  23.436 103.643 23.454 103.68 ;
    END
  END a_d[492]
  PIN a_d[493]
    DIRECTION INPUT ;
    USE SIGNAL ;
    PORT
      LAYER M3 ;
        RECT  23.508 103.643 23.526 103.68 ;
    END
  END a_d[493]
  PIN a_d[494]
    DIRECTION INPUT ;
    USE SIGNAL ;
    PORT
      LAYER M3 ;
        RECT  23.58 103.643 23.598 103.68 ;
    END
  END a_d[494]
  PIN a_d[495]
    DIRECTION INPUT ;
    USE SIGNAL ;
    PORT
      LAYER M3 ;
        RECT  23.652 103.643 23.67 103.68 ;
    END
  END a_d[495]
  PIN a_d[496]
    DIRECTION INPUT ;
    USE SIGNAL ;
    PORT
      LAYER M3 ;
        RECT  23.724 103.643 23.742 103.68 ;
    END
  END a_d[496]
  PIN a_d[497]
    DIRECTION INPUT ;
    USE SIGNAL ;
    PORT
      LAYER M3 ;
        RECT  23.796 103.643 23.814 103.68 ;
    END
  END a_d[497]
  PIN a_d[498]
    DIRECTION INPUT ;
    USE SIGNAL ;
    PORT
      LAYER M3 ;
        RECT  23.868 103.643 23.886 103.68 ;
    END
  END a_d[498]
  PIN a_d[499]
    DIRECTION INPUT ;
    USE SIGNAL ;
    PORT
      LAYER M3 ;
        RECT  23.94 103.643 23.958 103.68 ;
    END
  END a_d[499]
  PIN a_d[49]
    DIRECTION INPUT ;
    USE SIGNAL ;
    PORT
      LAYER M3 ;
        RECT  37.98 103.643 37.998 103.68 ;
    END
  END a_d[49]
  PIN a_d[4]
    DIRECTION INPUT ;
    USE SIGNAL ;
    PORT
      LAYER M5 ;
        RECT  16.08 103.596 16.104 103.68 ;
    END
  END a_d[4]
  PIN a_d[500]
    DIRECTION INPUT ;
    USE SIGNAL ;
    PORT
      LAYER M3 ;
        RECT  24.012 103.643 24.03 103.68 ;
    END
  END a_d[500]
  PIN a_d[501]
    DIRECTION INPUT ;
    USE SIGNAL ;
    PORT
      LAYER M3 ;
        RECT  24.084 103.643 24.102 103.68 ;
    END
  END a_d[501]
  PIN a_d[502]
    DIRECTION INPUT ;
    USE SIGNAL ;
    PORT
      LAYER M3 ;
        RECT  24.156 103.643 24.174 103.68 ;
    END
  END a_d[502]
  PIN a_d[503]
    DIRECTION INPUT ;
    USE SIGNAL ;
    PORT
      LAYER M3 ;
        RECT  24.228 103.643 24.246 103.68 ;
    END
  END a_d[503]
  PIN a_d[504]
    DIRECTION INPUT ;
    USE SIGNAL ;
    PORT
      LAYER M3 ;
        RECT  24.3 103.643 24.318 103.68 ;
    END
  END a_d[504]
  PIN a_d[505]
    DIRECTION INPUT ;
    USE SIGNAL ;
    PORT
      LAYER M3 ;
        RECT  24.372 103.643 24.39 103.68 ;
    END
  END a_d[505]
  PIN a_d[506]
    DIRECTION INPUT ;
    USE SIGNAL ;
    PORT
      LAYER M3 ;
        RECT  24.444 103.643 24.462 103.68 ;
    END
  END a_d[506]
  PIN a_d[507]
    DIRECTION INPUT ;
    USE SIGNAL ;
    PORT
      LAYER M3 ;
        RECT  24.516 103.643 24.534 103.68 ;
    END
  END a_d[507]
  PIN a_d[50]
    DIRECTION INPUT ;
    USE SIGNAL ;
    PORT
      LAYER M3 ;
        RECT  38.052 103.643 38.07 103.68 ;
    END
  END a_d[50]
  PIN a_d[51]
    DIRECTION INPUT ;
    USE SIGNAL ;
    PORT
      LAYER M3 ;
        RECT  38.124 103.643 38.142 103.68 ;
    END
  END a_d[51]
  PIN a_d[52]
    DIRECTION INPUT ;
    USE SIGNAL ;
    PORT
      LAYER M3 ;
        RECT  38.196 103.643 38.214 103.68 ;
    END
  END a_d[52]
  PIN a_d[53]
    DIRECTION INPUT ;
    USE SIGNAL ;
    PORT
      LAYER M3 ;
        RECT  38.268 103.643 38.286 103.68 ;
    END
  END a_d[53]
  PIN a_d[54]
    DIRECTION INPUT ;
    USE SIGNAL ;
    PORT
      LAYER M3 ;
        RECT  38.34 103.643 38.358 103.68 ;
    END
  END a_d[54]
  PIN a_d[55]
    DIRECTION INPUT ;
    USE SIGNAL ;
    PORT
      LAYER M3 ;
        RECT  38.412 103.643 38.43 103.68 ;
    END
  END a_d[55]
  PIN a_d[56]
    DIRECTION INPUT ;
    USE SIGNAL ;
    PORT
      LAYER M3 ;
        RECT  38.484 103.643 38.502 103.68 ;
    END
  END a_d[56]
  PIN a_d[57]
    DIRECTION INPUT ;
    USE SIGNAL ;
    PORT
      LAYER M3 ;
        RECT  38.556 103.643 38.574 103.68 ;
    END
  END a_d[57]
  PIN a_d[58]
    DIRECTION INPUT ;
    USE SIGNAL ;
    PORT
      LAYER M3 ;
        RECT  38.628 103.643 38.646 103.68 ;
    END
  END a_d[58]
  PIN a_d[59]
    DIRECTION INPUT ;
    USE SIGNAL ;
    PORT
      LAYER M3 ;
        RECT  38.7 103.643 38.718 103.68 ;
    END
  END a_d[59]
  PIN a_d[5]
    DIRECTION INPUT ;
    USE SIGNAL ;
    PORT
      LAYER M5 ;
        RECT  16.176 103.596 16.2 103.68 ;
    END
  END a_d[5]
  PIN a_d[60]
    DIRECTION INPUT ;
    USE SIGNAL ;
    PORT
      LAYER M3 ;
        RECT  38.772 103.643 38.79 103.68 ;
    END
  END a_d[60]
  PIN a_d[61]
    DIRECTION INPUT ;
    USE SIGNAL ;
    PORT
      LAYER M3 ;
        RECT  38.844 103.643 38.862 103.68 ;
    END
  END a_d[61]
  PIN a_d[62]
    DIRECTION INPUT ;
    USE SIGNAL ;
    PORT
      LAYER M3 ;
        RECT  38.916 103.643 38.934 103.68 ;
    END
  END a_d[62]
  PIN a_d[63]
    DIRECTION INPUT ;
    USE SIGNAL ;
    PORT
      LAYER M3 ;
        RECT  38.988 103.643 39.006 103.68 ;
    END
  END a_d[63]
  PIN a_d[64]
    DIRECTION INPUT ;
    USE SIGNAL ;
    PORT
      LAYER M5 ;
        RECT  18.768 103.596 18.792 103.68 ;
    END
  END a_d[64]
  PIN a_d[65]
    DIRECTION INPUT ;
    USE SIGNAL ;
    PORT
      LAYER M5 ;
        RECT  18.864 103.596 18.888 103.68 ;
    END
  END a_d[65]
  PIN a_d[66]
    DIRECTION INPUT ;
    USE SIGNAL ;
    PORT
      LAYER M5 ;
        RECT  18.96 103.596 18.984 103.68 ;
    END
  END a_d[66]
  PIN a_d[67]
    DIRECTION INPUT ;
    USE SIGNAL ;
    PORT
      LAYER M5 ;
        RECT  19.056 103.596 19.08 103.68 ;
    END
  END a_d[67]
  PIN a_d[68]
    DIRECTION INPUT ;
    USE SIGNAL ;
    PORT
      LAYER M5 ;
        RECT  19.152 103.596 19.176 103.68 ;
    END
  END a_d[68]
  PIN a_d[69]
    DIRECTION INPUT ;
    USE SIGNAL ;
    PORT
      LAYER M5 ;
        RECT  19.248 103.596 19.272 103.68 ;
    END
  END a_d[69]
  PIN a_d[6]
    DIRECTION INPUT ;
    USE SIGNAL ;
    PORT
      LAYER M5 ;
        RECT  16.272 103.596 16.296 103.68 ;
    END
  END a_d[6]
  PIN a_d[70]
    DIRECTION INPUT ;
    USE SIGNAL ;
    PORT
      LAYER M5 ;
        RECT  19.344 103.596 19.368 103.68 ;
    END
  END a_d[70]
  PIN a_d[71]
    DIRECTION INPUT ;
    USE SIGNAL ;
    PORT
      LAYER M5 ;
        RECT  19.44 103.596 19.464 103.68 ;
    END
  END a_d[71]
  PIN a_d[72]
    DIRECTION INPUT ;
    USE SIGNAL ;
    PORT
      LAYER M5 ;
        RECT  19.536 103.596 19.56 103.68 ;
    END
  END a_d[72]
  PIN a_d[73]
    DIRECTION INPUT ;
    USE SIGNAL ;
    PORT
      LAYER M5 ;
        RECT  19.632 103.596 19.656 103.68 ;
    END
  END a_d[73]
  PIN a_d[74]
    DIRECTION INPUT ;
    USE SIGNAL ;
    PORT
      LAYER M5 ;
        RECT  19.728 103.596 19.752 103.68 ;
    END
  END a_d[74]
  PIN a_d[75]
    DIRECTION INPUT ;
    USE SIGNAL ;
    PORT
      LAYER M5 ;
        RECT  19.824 103.596 19.848 103.68 ;
    END
  END a_d[75]
  PIN a_d[76]
    DIRECTION INPUT ;
    USE SIGNAL ;
    PORT
      LAYER M5 ;
        RECT  19.92 103.596 19.944 103.68 ;
    END
  END a_d[76]
  PIN a_d[77]
    DIRECTION INPUT ;
    USE SIGNAL ;
    PORT
      LAYER M5 ;
        RECT  20.016 103.596 20.04 103.68 ;
    END
  END a_d[77]
  PIN a_d[78]
    DIRECTION INPUT ;
    USE SIGNAL ;
    PORT
      LAYER M5 ;
        RECT  20.112 103.596 20.136 103.68 ;
    END
  END a_d[78]
  PIN a_d[79]
    DIRECTION INPUT ;
    USE SIGNAL ;
    PORT
      LAYER M5 ;
        RECT  20.208 103.596 20.232 103.68 ;
    END
  END a_d[79]
  PIN a_d[7]
    DIRECTION INPUT ;
    USE SIGNAL ;
    PORT
      LAYER M5 ;
        RECT  16.368 103.596 16.392 103.68 ;
    END
  END a_d[7]
  PIN a_d[80]
    DIRECTION INPUT ;
    USE SIGNAL ;
    PORT
      LAYER M5 ;
        RECT  20.304 103.596 20.328 103.68 ;
    END
  END a_d[80]
  PIN a_d[81]
    DIRECTION INPUT ;
    USE SIGNAL ;
    PORT
      LAYER M5 ;
        RECT  20.4 103.596 20.424 103.68 ;
    END
  END a_d[81]
  PIN a_d[82]
    DIRECTION INPUT ;
    USE SIGNAL ;
    PORT
      LAYER M5 ;
        RECT  20.496 103.596 20.52 103.68 ;
    END
  END a_d[82]
  PIN a_d[83]
    DIRECTION INPUT ;
    USE SIGNAL ;
    PORT
      LAYER M5 ;
        RECT  20.592 103.596 20.616 103.68 ;
    END
  END a_d[83]
  PIN a_d[84]
    DIRECTION INPUT ;
    USE SIGNAL ;
    PORT
      LAYER M5 ;
        RECT  20.688 103.596 20.712 103.68 ;
    END
  END a_d[84]
  PIN a_d[85]
    DIRECTION INPUT ;
    USE SIGNAL ;
    PORT
      LAYER M5 ;
        RECT  20.784 103.596 20.808 103.68 ;
    END
  END a_d[85]
  PIN a_d[86]
    DIRECTION INPUT ;
    USE SIGNAL ;
    PORT
      LAYER M5 ;
        RECT  20.88 103.596 20.904 103.68 ;
    END
  END a_d[86]
  PIN a_d[87]
    DIRECTION INPUT ;
    USE SIGNAL ;
    PORT
      LAYER M5 ;
        RECT  20.976 103.596 21 103.68 ;
    END
  END a_d[87]
  PIN a_d[88]
    DIRECTION INPUT ;
    USE SIGNAL ;
    PORT
      LAYER M5 ;
        RECT  21.072 103.596 21.096 103.68 ;
    END
  END a_d[88]
  PIN a_d[89]
    DIRECTION INPUT ;
    USE SIGNAL ;
    PORT
      LAYER M5 ;
        RECT  21.168 103.596 21.192 103.68 ;
    END
  END a_d[89]
  PIN a_d[8]
    DIRECTION INPUT ;
    USE SIGNAL ;
    PORT
      LAYER M5 ;
        RECT  16.464 103.596 16.488 103.68 ;
    END
  END a_d[8]
  PIN a_d[90]
    DIRECTION INPUT ;
    USE SIGNAL ;
    PORT
      LAYER M5 ;
        RECT  21.264 103.596 21.288 103.68 ;
    END
  END a_d[90]
  PIN a_d[91]
    DIRECTION INPUT ;
    USE SIGNAL ;
    PORT
      LAYER M5 ;
        RECT  21.36 103.596 21.384 103.68 ;
    END
  END a_d[91]
  PIN a_d[92]
    DIRECTION INPUT ;
    USE SIGNAL ;
    PORT
      LAYER M5 ;
        RECT  21.456 103.596 21.48 103.68 ;
    END
  END a_d[92]
  PIN a_d[93]
    DIRECTION INPUT ;
    USE SIGNAL ;
    PORT
      LAYER M5 ;
        RECT  21.552 103.596 21.576 103.68 ;
    END
  END a_d[93]
  PIN a_d[94]
    DIRECTION INPUT ;
    USE SIGNAL ;
    PORT
      LAYER M5 ;
        RECT  21.648 103.596 21.672 103.68 ;
    END
  END a_d[94]
  PIN a_d[95]
    DIRECTION INPUT ;
    USE SIGNAL ;
    PORT
      LAYER M5 ;
        RECT  21.744 103.596 21.768 103.68 ;
    END
  END a_d[95]
  PIN a_d[96]
    DIRECTION INPUT ;
    USE SIGNAL ;
    PORT
      LAYER M5 ;
        RECT  21.84 103.596 21.864 103.68 ;
    END
  END a_d[96]
  PIN a_d[97]
    DIRECTION INPUT ;
    USE SIGNAL ;
    PORT
      LAYER M5 ;
        RECT  21.936 103.596 21.96 103.68 ;
    END
  END a_d[97]
  PIN a_d[98]
    DIRECTION INPUT ;
    USE SIGNAL ;
    PORT
      LAYER M5 ;
        RECT  22.032 103.596 22.056 103.68 ;
    END
  END a_d[98]
  PIN a_d[99]
    DIRECTION INPUT ;
    USE SIGNAL ;
    PORT
      LAYER M5 ;
        RECT  22.128 103.596 22.152 103.68 ;
    END
  END a_d[99]
  PIN a_d[9]
    DIRECTION INPUT ;
    USE SIGNAL ;
    PORT
      LAYER M5 ;
        RECT  16.56 103.596 16.584 103.68 ;
    END
  END a_d[9]
  PIN a_r
    DIRECTION OUTPUT ;
    USE SIGNAL ;
    PORT
      LAYER M3 ;
        RECT  24.588 103.643 24.606 103.68 ;
    END
  END a_r
  PIN b_d[0]
    DIRECTION OUTPUT ;
    USE SIGNAL ;
    PORT
      LAYER M3 ;
        RECT  19.548 0 19.566 0.037 ;
    END
  END b_d[0]
  PIN b_d[100]
    DIRECTION OUTPUT ;
    USE SIGNAL ;
    PORT
      LAYER M5 ;
        RECT  20.304 0 20.328 0.084 ;
    END
  END b_d[100]
  PIN b_d[101]
    DIRECTION OUTPUT ;
    USE SIGNAL ;
    PORT
      LAYER M5 ;
        RECT  20.4 0 20.424 0.084 ;
    END
  END b_d[101]
  PIN b_d[102]
    DIRECTION OUTPUT ;
    USE SIGNAL ;
    PORT
      LAYER M5 ;
        RECT  20.496 0 20.52 0.084 ;
    END
  END b_d[102]
  PIN b_d[103]
    DIRECTION OUTPUT ;
    USE SIGNAL ;
    PORT
      LAYER M5 ;
        RECT  20.592 0 20.616 0.084 ;
    END
  END b_d[103]
  PIN b_d[104]
    DIRECTION OUTPUT ;
    USE SIGNAL ;
    PORT
      LAYER M5 ;
        RECT  20.688 0 20.712 0.084 ;
    END
  END b_d[104]
  PIN b_d[105]
    DIRECTION OUTPUT ;
    USE SIGNAL ;
    PORT
      LAYER M5 ;
        RECT  20.784 0 20.808 0.084 ;
    END
  END b_d[105]
  PIN b_d[106]
    DIRECTION OUTPUT ;
    USE SIGNAL ;
    PORT
      LAYER M5 ;
        RECT  20.88 0 20.904 0.084 ;
    END
  END b_d[106]
  PIN b_d[107]
    DIRECTION OUTPUT ;
    USE SIGNAL ;
    PORT
      LAYER M5 ;
        RECT  20.976 0 21 0.084 ;
    END
  END b_d[107]
  PIN b_d[108]
    DIRECTION OUTPUT ;
    USE SIGNAL ;
    PORT
      LAYER M5 ;
        RECT  21.072 0 21.096 0.084 ;
    END
  END b_d[108]
  PIN b_d[109]
    DIRECTION OUTPUT ;
    USE SIGNAL ;
    PORT
      LAYER M5 ;
        RECT  21.168 0 21.192 0.084 ;
    END
  END b_d[109]
  PIN b_d[10]
    DIRECTION OUTPUT ;
    USE SIGNAL ;
    PORT
      LAYER M3 ;
        RECT  20.268 0 20.286 0.037 ;
    END
  END b_d[10]
  PIN b_d[110]
    DIRECTION OUTPUT ;
    USE SIGNAL ;
    PORT
      LAYER M5 ;
        RECT  21.264 0 21.288 0.084 ;
    END
  END b_d[110]
  PIN b_d[111]
    DIRECTION OUTPUT ;
    USE SIGNAL ;
    PORT
      LAYER M5 ;
        RECT  21.36 0 21.384 0.084 ;
    END
  END b_d[111]
  PIN b_d[112]
    DIRECTION OUTPUT ;
    USE SIGNAL ;
    PORT
      LAYER M5 ;
        RECT  21.456 0 21.48 0.084 ;
    END
  END b_d[112]
  PIN b_d[113]
    DIRECTION OUTPUT ;
    USE SIGNAL ;
    PORT
      LAYER M5 ;
        RECT  21.552 0 21.576 0.084 ;
    END
  END b_d[113]
  PIN b_d[114]
    DIRECTION OUTPUT ;
    USE SIGNAL ;
    PORT
      LAYER M5 ;
        RECT  21.648 0 21.672 0.084 ;
    END
  END b_d[114]
  PIN b_d[115]
    DIRECTION OUTPUT ;
    USE SIGNAL ;
    PORT
      LAYER M5 ;
        RECT  21.744 0 21.768 0.084 ;
    END
  END b_d[115]
  PIN b_d[116]
    DIRECTION OUTPUT ;
    USE SIGNAL ;
    PORT
      LAYER M5 ;
        RECT  21.84 0 21.864 0.084 ;
    END
  END b_d[116]
  PIN b_d[117]
    DIRECTION OUTPUT ;
    USE SIGNAL ;
    PORT
      LAYER M5 ;
        RECT  21.936 0 21.96 0.084 ;
    END
  END b_d[117]
  PIN b_d[118]
    DIRECTION OUTPUT ;
    USE SIGNAL ;
    PORT
      LAYER M5 ;
        RECT  22.032 0 22.056 0.084 ;
    END
  END b_d[118]
  PIN b_d[119]
    DIRECTION OUTPUT ;
    USE SIGNAL ;
    PORT
      LAYER M5 ;
        RECT  22.128 0 22.152 0.084 ;
    END
  END b_d[119]
  PIN b_d[11]
    DIRECTION OUTPUT ;
    USE SIGNAL ;
    PORT
      LAYER M3 ;
        RECT  20.34 0 20.358 0.037 ;
    END
  END b_d[11]
  PIN b_d[120]
    DIRECTION OUTPUT ;
    USE SIGNAL ;
    PORT
      LAYER M5 ;
        RECT  22.224 0 22.248 0.084 ;
    END
  END b_d[120]
  PIN b_d[121]
    DIRECTION OUTPUT ;
    USE SIGNAL ;
    PORT
      LAYER M5 ;
        RECT  22.32 0 22.344 0.084 ;
    END
  END b_d[121]
  PIN b_d[122]
    DIRECTION OUTPUT ;
    USE SIGNAL ;
    PORT
      LAYER M5 ;
        RECT  22.416 0 22.44 0.084 ;
    END
  END b_d[122]
  PIN b_d[123]
    DIRECTION OUTPUT ;
    USE SIGNAL ;
    PORT
      LAYER M5 ;
        RECT  22.512 0 22.536 0.084 ;
    END
  END b_d[123]
  PIN b_d[124]
    DIRECTION OUTPUT ;
    USE SIGNAL ;
    PORT
      LAYER M5 ;
        RECT  22.608 0 22.632 0.084 ;
    END
  END b_d[124]
  PIN b_d[125]
    DIRECTION OUTPUT ;
    USE SIGNAL ;
    PORT
      LAYER M5 ;
        RECT  22.704 0 22.728 0.084 ;
    END
  END b_d[125]
  PIN b_d[126]
    DIRECTION OUTPUT ;
    USE SIGNAL ;
    PORT
      LAYER M5 ;
        RECT  22.8 0 22.824 0.084 ;
    END
  END b_d[126]
  PIN b_d[127]
    DIRECTION OUTPUT ;
    USE SIGNAL ;
    PORT
      LAYER M5 ;
        RECT  22.896 0 22.92 0.084 ;
    END
  END b_d[127]
  PIN b_d[128]
    DIRECTION OUTPUT ;
    USE SIGNAL ;
    PORT
      LAYER M3 ;
        RECT  17.244 0 17.262 0.037 ;
    END
  END b_d[128]
  PIN b_d[129]
    DIRECTION OUTPUT ;
    USE SIGNAL ;
    PORT
      LAYER M3 ;
        RECT  17.316 0 17.334 0.037 ;
    END
  END b_d[129]
  PIN b_d[12]
    DIRECTION OUTPUT ;
    USE SIGNAL ;
    PORT
      LAYER M3 ;
        RECT  20.412 0 20.43 0.037 ;
    END
  END b_d[12]
  PIN b_d[130]
    DIRECTION OUTPUT ;
    USE SIGNAL ;
    PORT
      LAYER M3 ;
        RECT  17.388 0 17.406 0.037 ;
    END
  END b_d[130]
  PIN b_d[131]
    DIRECTION OUTPUT ;
    USE SIGNAL ;
    PORT
      LAYER M3 ;
        RECT  17.46 0 17.478 0.037 ;
    END
  END b_d[131]
  PIN b_d[132]
    DIRECTION OUTPUT ;
    USE SIGNAL ;
    PORT
      LAYER M3 ;
        RECT  17.532 0 17.55 0.037 ;
    END
  END b_d[132]
  PIN b_d[133]
    DIRECTION OUTPUT ;
    USE SIGNAL ;
    PORT
      LAYER M3 ;
        RECT  17.604 0 17.622 0.037 ;
    END
  END b_d[133]
  PIN b_d[134]
    DIRECTION OUTPUT ;
    USE SIGNAL ;
    PORT
      LAYER M3 ;
        RECT  17.676 0 17.694 0.037 ;
    END
  END b_d[134]
  PIN b_d[135]
    DIRECTION OUTPUT ;
    USE SIGNAL ;
    PORT
      LAYER M3 ;
        RECT  17.748 0 17.766 0.037 ;
    END
  END b_d[135]
  PIN b_d[136]
    DIRECTION OUTPUT ;
    USE SIGNAL ;
    PORT
      LAYER M3 ;
        RECT  17.82 0 17.838 0.037 ;
    END
  END b_d[136]
  PIN b_d[137]
    DIRECTION OUTPUT ;
    USE SIGNAL ;
    PORT
      LAYER M3 ;
        RECT  17.892 0 17.91 0.037 ;
    END
  END b_d[137]
  PIN b_d[138]
    DIRECTION OUTPUT ;
    USE SIGNAL ;
    PORT
      LAYER M3 ;
        RECT  17.964 0 17.982 0.037 ;
    END
  END b_d[138]
  PIN b_d[139]
    DIRECTION OUTPUT ;
    USE SIGNAL ;
    PORT
      LAYER M3 ;
        RECT  18.036 0 18.054 0.037 ;
    END
  END b_d[139]
  PIN b_d[13]
    DIRECTION OUTPUT ;
    USE SIGNAL ;
    PORT
      LAYER M3 ;
        RECT  20.484 0 20.502 0.037 ;
    END
  END b_d[13]
  PIN b_d[140]
    DIRECTION OUTPUT ;
    USE SIGNAL ;
    PORT
      LAYER M3 ;
        RECT  18.108 0 18.126 0.037 ;
    END
  END b_d[140]
  PIN b_d[141]
    DIRECTION OUTPUT ;
    USE SIGNAL ;
    PORT
      LAYER M3 ;
        RECT  18.18 0 18.198 0.037 ;
    END
  END b_d[141]
  PIN b_d[142]
    DIRECTION OUTPUT ;
    USE SIGNAL ;
    PORT
      LAYER M3 ;
        RECT  18.252 0 18.27 0.037 ;
    END
  END b_d[142]
  PIN b_d[143]
    DIRECTION OUTPUT ;
    USE SIGNAL ;
    PORT
      LAYER M3 ;
        RECT  18.324 0 18.342 0.037 ;
    END
  END b_d[143]
  PIN b_d[144]
    DIRECTION OUTPUT ;
    USE SIGNAL ;
    PORT
      LAYER M3 ;
        RECT  18.396 0 18.414 0.037 ;
    END
  END b_d[144]
  PIN b_d[145]
    DIRECTION OUTPUT ;
    USE SIGNAL ;
    PORT
      LAYER M3 ;
        RECT  18.468 0 18.486 0.037 ;
    END
  END b_d[145]
  PIN b_d[146]
    DIRECTION OUTPUT ;
    USE SIGNAL ;
    PORT
      LAYER M3 ;
        RECT  18.54 0 18.558 0.037 ;
    END
  END b_d[146]
  PIN b_d[147]
    DIRECTION OUTPUT ;
    USE SIGNAL ;
    PORT
      LAYER M3 ;
        RECT  18.612 0 18.63 0.037 ;
    END
  END b_d[147]
  PIN b_d[148]
    DIRECTION OUTPUT ;
    USE SIGNAL ;
    PORT
      LAYER M3 ;
        RECT  18.684 0 18.702 0.037 ;
    END
  END b_d[148]
  PIN b_d[149]
    DIRECTION OUTPUT ;
    USE SIGNAL ;
    PORT
      LAYER M3 ;
        RECT  18.756 0 18.774 0.037 ;
    END
  END b_d[149]
  PIN b_d[14]
    DIRECTION OUTPUT ;
    USE SIGNAL ;
    PORT
      LAYER M3 ;
        RECT  20.556 0 20.574 0.037 ;
    END
  END b_d[14]
  PIN b_d[150]
    DIRECTION OUTPUT ;
    USE SIGNAL ;
    PORT
      LAYER M3 ;
        RECT  18.828 0 18.846 0.037 ;
    END
  END b_d[150]
  PIN b_d[151]
    DIRECTION OUTPUT ;
    USE SIGNAL ;
    PORT
      LAYER M3 ;
        RECT  18.9 0 18.918 0.037 ;
    END
  END b_d[151]
  PIN b_d[152]
    DIRECTION OUTPUT ;
    USE SIGNAL ;
    PORT
      LAYER M3 ;
        RECT  18.972 0 18.99 0.037 ;
    END
  END b_d[152]
  PIN b_d[153]
    DIRECTION OUTPUT ;
    USE SIGNAL ;
    PORT
      LAYER M3 ;
        RECT  19.044 0 19.062 0.037 ;
    END
  END b_d[153]
  PIN b_d[154]
    DIRECTION OUTPUT ;
    USE SIGNAL ;
    PORT
      LAYER M3 ;
        RECT  19.116 0 19.134 0.037 ;
    END
  END b_d[154]
  PIN b_d[155]
    DIRECTION OUTPUT ;
    USE SIGNAL ;
    PORT
      LAYER M3 ;
        RECT  19.188 0 19.206 0.037 ;
    END
  END b_d[155]
  PIN b_d[156]
    DIRECTION OUTPUT ;
    USE SIGNAL ;
    PORT
      LAYER M3 ;
        RECT  19.26 0 19.278 0.037 ;
    END
  END b_d[156]
  PIN b_d[157]
    DIRECTION OUTPUT ;
    USE SIGNAL ;
    PORT
      LAYER M3 ;
        RECT  19.332 0 19.35 0.037 ;
    END
  END b_d[157]
  PIN b_d[158]
    DIRECTION OUTPUT ;
    USE SIGNAL ;
    PORT
      LAYER M3 ;
        RECT  19.404 0 19.422 0.037 ;
    END
  END b_d[158]
  PIN b_d[159]
    DIRECTION OUTPUT ;
    USE SIGNAL ;
    PORT
      LAYER M3 ;
        RECT  19.476 0 19.494 0.037 ;
    END
  END b_d[159]
  PIN b_d[15]
    DIRECTION OUTPUT ;
    USE SIGNAL ;
    PORT
      LAYER M3 ;
        RECT  20.628 0 20.646 0.037 ;
    END
  END b_d[15]
  PIN b_d[160]
    DIRECTION OUTPUT ;
    USE SIGNAL ;
    PORT
      LAYER M5 ;
        RECT  22.992 0 23.016 0.084 ;
    END
  END b_d[160]
  PIN b_d[161]
    DIRECTION OUTPUT ;
    USE SIGNAL ;
    PORT
      LAYER M5 ;
        RECT  23.088 0 23.112 0.084 ;
    END
  END b_d[161]
  PIN b_d[162]
    DIRECTION OUTPUT ;
    USE SIGNAL ;
    PORT
      LAYER M5 ;
        RECT  23.184 0 23.208 0.084 ;
    END
  END b_d[162]
  PIN b_d[163]
    DIRECTION OUTPUT ;
    USE SIGNAL ;
    PORT
      LAYER M5 ;
        RECT  23.28 0 23.304 0.084 ;
    END
  END b_d[163]
  PIN b_d[164]
    DIRECTION OUTPUT ;
    USE SIGNAL ;
    PORT
      LAYER M5 ;
        RECT  23.376 0 23.4 0.084 ;
    END
  END b_d[164]
  PIN b_d[165]
    DIRECTION OUTPUT ;
    USE SIGNAL ;
    PORT
      LAYER M5 ;
        RECT  23.472 0 23.496 0.084 ;
    END
  END b_d[165]
  PIN b_d[166]
    DIRECTION OUTPUT ;
    USE SIGNAL ;
    PORT
      LAYER M5 ;
        RECT  23.568 0 23.592 0.084 ;
    END
  END b_d[166]
  PIN b_d[167]
    DIRECTION OUTPUT ;
    USE SIGNAL ;
    PORT
      LAYER M5 ;
        RECT  23.664 0 23.688 0.084 ;
    END
  END b_d[167]
  PIN b_d[168]
    DIRECTION OUTPUT ;
    USE SIGNAL ;
    PORT
      LAYER M5 ;
        RECT  23.76 0 23.784 0.084 ;
    END
  END b_d[168]
  PIN b_d[169]
    DIRECTION OUTPUT ;
    USE SIGNAL ;
    PORT
      LAYER M5 ;
        RECT  23.856 0 23.88 0.084 ;
    END
  END b_d[169]
  PIN b_d[16]
    DIRECTION OUTPUT ;
    USE SIGNAL ;
    PORT
      LAYER M3 ;
        RECT  20.7 0 20.718 0.037 ;
    END
  END b_d[16]
  PIN b_d[170]
    DIRECTION OUTPUT ;
    USE SIGNAL ;
    PORT
      LAYER M5 ;
        RECT  23.952 0 23.976 0.084 ;
    END
  END b_d[170]
  PIN b_d[171]
    DIRECTION OUTPUT ;
    USE SIGNAL ;
    PORT
      LAYER M5 ;
        RECT  24.048 0 24.072 0.084 ;
    END
  END b_d[171]
  PIN b_d[172]
    DIRECTION OUTPUT ;
    USE SIGNAL ;
    PORT
      LAYER M5 ;
        RECT  24.144 0 24.168 0.084 ;
    END
  END b_d[172]
  PIN b_d[173]
    DIRECTION OUTPUT ;
    USE SIGNAL ;
    PORT
      LAYER M5 ;
        RECT  24.24 0 24.264 0.084 ;
    END
  END b_d[173]
  PIN b_d[174]
    DIRECTION OUTPUT ;
    USE SIGNAL ;
    PORT
      LAYER M5 ;
        RECT  24.336 0 24.36 0.084 ;
    END
  END b_d[174]
  PIN b_d[175]
    DIRECTION OUTPUT ;
    USE SIGNAL ;
    PORT
      LAYER M5 ;
        RECT  24.432 0 24.456 0.084 ;
    END
  END b_d[175]
  PIN b_d[176]
    DIRECTION OUTPUT ;
    USE SIGNAL ;
    PORT
      LAYER M5 ;
        RECT  24.528 0 24.552 0.084 ;
    END
  END b_d[176]
  PIN b_d[177]
    DIRECTION OUTPUT ;
    USE SIGNAL ;
    PORT
      LAYER M5 ;
        RECT  24.624 0 24.648 0.084 ;
    END
  END b_d[177]
  PIN b_d[178]
    DIRECTION OUTPUT ;
    USE SIGNAL ;
    PORT
      LAYER M5 ;
        RECT  24.72 0 24.744 0.084 ;
    END
  END b_d[178]
  PIN b_d[179]
    DIRECTION OUTPUT ;
    USE SIGNAL ;
    PORT
      LAYER M5 ;
        RECT  24.816 0 24.84 0.084 ;
    END
  END b_d[179]
  PIN b_d[17]
    DIRECTION OUTPUT ;
    USE SIGNAL ;
    PORT
      LAYER M3 ;
        RECT  20.772 0 20.79 0.037 ;
    END
  END b_d[17]
  PIN b_d[180]
    DIRECTION OUTPUT ;
    USE SIGNAL ;
    PORT
      LAYER M5 ;
        RECT  24.912 0 24.936 0.084 ;
    END
  END b_d[180]
  PIN b_d[181]
    DIRECTION OUTPUT ;
    USE SIGNAL ;
    PORT
      LAYER M5 ;
        RECT  25.008 0 25.032 0.084 ;
    END
  END b_d[181]
  PIN b_d[182]
    DIRECTION OUTPUT ;
    USE SIGNAL ;
    PORT
      LAYER M5 ;
        RECT  25.104 0 25.128 0.084 ;
    END
  END b_d[182]
  PIN b_d[183]
    DIRECTION OUTPUT ;
    USE SIGNAL ;
    PORT
      LAYER M5 ;
        RECT  25.2 0 25.224 0.084 ;
    END
  END b_d[183]
  PIN b_d[184]
    DIRECTION OUTPUT ;
    USE SIGNAL ;
    PORT
      LAYER M5 ;
        RECT  25.296 0 25.32 0.084 ;
    END
  END b_d[184]
  PIN b_d[185]
    DIRECTION OUTPUT ;
    USE SIGNAL ;
    PORT
      LAYER M5 ;
        RECT  25.392 0 25.416 0.084 ;
    END
  END b_d[185]
  PIN b_d[186]
    DIRECTION OUTPUT ;
    USE SIGNAL ;
    PORT
      LAYER M5 ;
        RECT  25.488 0 25.512 0.084 ;
    END
  END b_d[186]
  PIN b_d[187]
    DIRECTION OUTPUT ;
    USE SIGNAL ;
    PORT
      LAYER M5 ;
        RECT  25.584 0 25.608 0.084 ;
    END
  END b_d[187]
  PIN b_d[188]
    DIRECTION OUTPUT ;
    USE SIGNAL ;
    PORT
      LAYER M5 ;
        RECT  25.68 0 25.704 0.084 ;
    END
  END b_d[188]
  PIN b_d[189]
    DIRECTION OUTPUT ;
    USE SIGNAL ;
    PORT
      LAYER M5 ;
        RECT  25.776 0 25.8 0.084 ;
    END
  END b_d[189]
  PIN b_d[18]
    DIRECTION OUTPUT ;
    USE SIGNAL ;
    PORT
      LAYER M3 ;
        RECT  20.844 0 20.862 0.037 ;
    END
  END b_d[18]
  PIN b_d[190]
    DIRECTION OUTPUT ;
    USE SIGNAL ;
    PORT
      LAYER M5 ;
        RECT  25.872 0 25.896 0.084 ;
    END
  END b_d[190]
  PIN b_d[191]
    DIRECTION OUTPUT ;
    USE SIGNAL ;
    PORT
      LAYER M5 ;
        RECT  25.968 0 25.992 0.084 ;
    END
  END b_d[191]
  PIN b_d[192]
    DIRECTION OUTPUT ;
    USE SIGNAL ;
    PORT
      LAYER M5 ;
        RECT  29.136 0 29.16 0.084 ;
    END
  END b_d[192]
  PIN b_d[193]
    DIRECTION OUTPUT ;
    USE SIGNAL ;
    PORT
      LAYER M5 ;
        RECT  29.232 0 29.256 0.084 ;
    END
  END b_d[193]
  PIN b_d[194]
    DIRECTION OUTPUT ;
    USE SIGNAL ;
    PORT
      LAYER M5 ;
        RECT  29.328 0 29.352 0.084 ;
    END
  END b_d[194]
  PIN b_d[195]
    DIRECTION OUTPUT ;
    USE SIGNAL ;
    PORT
      LAYER M5 ;
        RECT  29.424 0 29.448 0.084 ;
    END
  END b_d[195]
  PIN b_d[196]
    DIRECTION OUTPUT ;
    USE SIGNAL ;
    PORT
      LAYER M5 ;
        RECT  29.52 0 29.544 0.084 ;
    END
  END b_d[196]
  PIN b_d[197]
    DIRECTION OUTPUT ;
    USE SIGNAL ;
    PORT
      LAYER M5 ;
        RECT  29.616 0 29.64 0.084 ;
    END
  END b_d[197]
  PIN b_d[198]
    DIRECTION OUTPUT ;
    USE SIGNAL ;
    PORT
      LAYER M5 ;
        RECT  29.712 0 29.736 0.084 ;
    END
  END b_d[198]
  PIN b_d[199]
    DIRECTION OUTPUT ;
    USE SIGNAL ;
    PORT
      LAYER M5 ;
        RECT  29.808 0 29.832 0.084 ;
    END
  END b_d[199]
  PIN b_d[19]
    DIRECTION OUTPUT ;
    USE SIGNAL ;
    PORT
      LAYER M3 ;
        RECT  20.916 0 20.934 0.037 ;
    END
  END b_d[19]
  PIN b_d[1]
    DIRECTION OUTPUT ;
    USE SIGNAL ;
    PORT
      LAYER M3 ;
        RECT  19.62 0 19.638 0.037 ;
    END
  END b_d[1]
  PIN b_d[200]
    DIRECTION OUTPUT ;
    USE SIGNAL ;
    PORT
      LAYER M5 ;
        RECT  29.904 0 29.928 0.084 ;
    END
  END b_d[200]
  PIN b_d[201]
    DIRECTION OUTPUT ;
    USE SIGNAL ;
    PORT
      LAYER M5 ;
        RECT  30 0 30.024 0.084 ;
    END
  END b_d[201]
  PIN b_d[202]
    DIRECTION OUTPUT ;
    USE SIGNAL ;
    PORT
      LAYER M5 ;
        RECT  30.096 0 30.12 0.084 ;
    END
  END b_d[202]
  PIN b_d[203]
    DIRECTION OUTPUT ;
    USE SIGNAL ;
    PORT
      LAYER M5 ;
        RECT  30.192 0 30.216 0.084 ;
    END
  END b_d[203]
  PIN b_d[204]
    DIRECTION OUTPUT ;
    USE SIGNAL ;
    PORT
      LAYER M5 ;
        RECT  30.288 0 30.312 0.084 ;
    END
  END b_d[204]
  PIN b_d[205]
    DIRECTION OUTPUT ;
    USE SIGNAL ;
    PORT
      LAYER M5 ;
        RECT  30.384 0 30.408 0.084 ;
    END
  END b_d[205]
  PIN b_d[206]
    DIRECTION OUTPUT ;
    USE SIGNAL ;
    PORT
      LAYER M5 ;
        RECT  30.48 0 30.504 0.084 ;
    END
  END b_d[206]
  PIN b_d[207]
    DIRECTION OUTPUT ;
    USE SIGNAL ;
    PORT
      LAYER M5 ;
        RECT  30.576 0 30.6 0.084 ;
    END
  END b_d[207]
  PIN b_d[208]
    DIRECTION OUTPUT ;
    USE SIGNAL ;
    PORT
      LAYER M5 ;
        RECT  30.672 0 30.696 0.084 ;
    END
  END b_d[208]
  PIN b_d[209]
    DIRECTION OUTPUT ;
    USE SIGNAL ;
    PORT
      LAYER M5 ;
        RECT  30.768 0 30.792 0.084 ;
    END
  END b_d[209]
  PIN b_d[20]
    DIRECTION OUTPUT ;
    USE SIGNAL ;
    PORT
      LAYER M3 ;
        RECT  20.988 0 21.006 0.037 ;
    END
  END b_d[20]
  PIN b_d[210]
    DIRECTION OUTPUT ;
    USE SIGNAL ;
    PORT
      LAYER M5 ;
        RECT  30.864 0 30.888 0.084 ;
    END
  END b_d[210]
  PIN b_d[211]
    DIRECTION OUTPUT ;
    USE SIGNAL ;
    PORT
      LAYER M5 ;
        RECT  30.96 0 30.984 0.084 ;
    END
  END b_d[211]
  PIN b_d[212]
    DIRECTION OUTPUT ;
    USE SIGNAL ;
    PORT
      LAYER M5 ;
        RECT  31.056 0 31.08 0.084 ;
    END
  END b_d[212]
  PIN b_d[213]
    DIRECTION OUTPUT ;
    USE SIGNAL ;
    PORT
      LAYER M5 ;
        RECT  31.152 0 31.176 0.084 ;
    END
  END b_d[213]
  PIN b_d[214]
    DIRECTION OUTPUT ;
    USE SIGNAL ;
    PORT
      LAYER M5 ;
        RECT  31.248 0 31.272 0.084 ;
    END
  END b_d[214]
  PIN b_d[215]
    DIRECTION OUTPUT ;
    USE SIGNAL ;
    PORT
      LAYER M5 ;
        RECT  31.344 0 31.368 0.084 ;
    END
  END b_d[215]
  PIN b_d[216]
    DIRECTION OUTPUT ;
    USE SIGNAL ;
    PORT
      LAYER M5 ;
        RECT  31.44 0 31.464 0.084 ;
    END
  END b_d[216]
  PIN b_d[217]
    DIRECTION OUTPUT ;
    USE SIGNAL ;
    PORT
      LAYER M5 ;
        RECT  31.536 0 31.56 0.084 ;
    END
  END b_d[217]
  PIN b_d[218]
    DIRECTION OUTPUT ;
    USE SIGNAL ;
    PORT
      LAYER M5 ;
        RECT  31.632 0 31.656 0.084 ;
    END
  END b_d[218]
  PIN b_d[219]
    DIRECTION OUTPUT ;
    USE SIGNAL ;
    PORT
      LAYER M5 ;
        RECT  31.728 0 31.752 0.084 ;
    END
  END b_d[219]
  PIN b_d[21]
    DIRECTION OUTPUT ;
    USE SIGNAL ;
    PORT
      LAYER M3 ;
        RECT  21.06 0 21.078 0.037 ;
    END
  END b_d[21]
  PIN b_d[220]
    DIRECTION OUTPUT ;
    USE SIGNAL ;
    PORT
      LAYER M5 ;
        RECT  31.824 0 31.848 0.084 ;
    END
  END b_d[220]
  PIN b_d[221]
    DIRECTION OUTPUT ;
    USE SIGNAL ;
    PORT
      LAYER M5 ;
        RECT  31.92 0 31.944 0.084 ;
    END
  END b_d[221]
  PIN b_d[222]
    DIRECTION OUTPUT ;
    USE SIGNAL ;
    PORT
      LAYER M5 ;
        RECT  32.016 0 32.04 0.084 ;
    END
  END b_d[222]
  PIN b_d[223]
    DIRECTION OUTPUT ;
    USE SIGNAL ;
    PORT
      LAYER M5 ;
        RECT  32.112 0 32.136 0.084 ;
    END
  END b_d[223]
  PIN b_d[224]
    DIRECTION OUTPUT ;
    USE SIGNAL ;
    PORT
      LAYER M5 ;
        RECT  26.064 0 26.088 0.084 ;
    END
  END b_d[224]
  PIN b_d[225]
    DIRECTION OUTPUT ;
    USE SIGNAL ;
    PORT
      LAYER M5 ;
        RECT  26.16 0 26.184 0.084 ;
    END
  END b_d[225]
  PIN b_d[226]
    DIRECTION OUTPUT ;
    USE SIGNAL ;
    PORT
      LAYER M5 ;
        RECT  26.256 0 26.28 0.084 ;
    END
  END b_d[226]
  PIN b_d[227]
    DIRECTION OUTPUT ;
    USE SIGNAL ;
    PORT
      LAYER M5 ;
        RECT  26.352 0 26.376 0.084 ;
    END
  END b_d[227]
  PIN b_d[228]
    DIRECTION OUTPUT ;
    USE SIGNAL ;
    PORT
      LAYER M5 ;
        RECT  26.448 0 26.472 0.084 ;
    END
  END b_d[228]
  PIN b_d[229]
    DIRECTION OUTPUT ;
    USE SIGNAL ;
    PORT
      LAYER M5 ;
        RECT  26.544 0 26.568 0.084 ;
    END
  END b_d[229]
  PIN b_d[22]
    DIRECTION OUTPUT ;
    USE SIGNAL ;
    PORT
      LAYER M3 ;
        RECT  21.132 0 21.15 0.037 ;
    END
  END b_d[22]
  PIN b_d[230]
    DIRECTION OUTPUT ;
    USE SIGNAL ;
    PORT
      LAYER M5 ;
        RECT  26.64 0 26.664 0.084 ;
    END
  END b_d[230]
  PIN b_d[231]
    DIRECTION OUTPUT ;
    USE SIGNAL ;
    PORT
      LAYER M5 ;
        RECT  26.736 0 26.76 0.084 ;
    END
  END b_d[231]
  PIN b_d[232]
    DIRECTION OUTPUT ;
    USE SIGNAL ;
    PORT
      LAYER M5 ;
        RECT  26.832 0 26.856 0.084 ;
    END
  END b_d[232]
  PIN b_d[233]
    DIRECTION OUTPUT ;
    USE SIGNAL ;
    PORT
      LAYER M5 ;
        RECT  26.928 0 26.952 0.084 ;
    END
  END b_d[233]
  PIN b_d[234]
    DIRECTION OUTPUT ;
    USE SIGNAL ;
    PORT
      LAYER M5 ;
        RECT  27.024 0 27.048 0.084 ;
    END
  END b_d[234]
  PIN b_d[235]
    DIRECTION OUTPUT ;
    USE SIGNAL ;
    PORT
      LAYER M5 ;
        RECT  27.12 0 27.144 0.084 ;
    END
  END b_d[235]
  PIN b_d[236]
    DIRECTION OUTPUT ;
    USE SIGNAL ;
    PORT
      LAYER M5 ;
        RECT  27.216 0 27.24 0.084 ;
    END
  END b_d[236]
  PIN b_d[237]
    DIRECTION OUTPUT ;
    USE SIGNAL ;
    PORT
      LAYER M5 ;
        RECT  27.312 0 27.336 0.084 ;
    END
  END b_d[237]
  PIN b_d[238]
    DIRECTION OUTPUT ;
    USE SIGNAL ;
    PORT
      LAYER M5 ;
        RECT  27.408 0 27.432 0.084 ;
    END
  END b_d[238]
  PIN b_d[239]
    DIRECTION OUTPUT ;
    USE SIGNAL ;
    PORT
      LAYER M5 ;
        RECT  27.504 0 27.528 0.084 ;
    END
  END b_d[239]
  PIN b_d[23]
    DIRECTION OUTPUT ;
    USE SIGNAL ;
    PORT
      LAYER M3 ;
        RECT  21.204 0 21.222 0.037 ;
    END
  END b_d[23]
  PIN b_d[240]
    DIRECTION OUTPUT ;
    USE SIGNAL ;
    PORT
      LAYER M5 ;
        RECT  27.6 0 27.624 0.084 ;
    END
  END b_d[240]
  PIN b_d[241]
    DIRECTION OUTPUT ;
    USE SIGNAL ;
    PORT
      LAYER M5 ;
        RECT  27.696 0 27.72 0.084 ;
    END
  END b_d[241]
  PIN b_d[242]
    DIRECTION OUTPUT ;
    USE SIGNAL ;
    PORT
      LAYER M5 ;
        RECT  27.792 0 27.816 0.084 ;
    END
  END b_d[242]
  PIN b_d[243]
    DIRECTION OUTPUT ;
    USE SIGNAL ;
    PORT
      LAYER M5 ;
        RECT  27.888 0 27.912 0.084 ;
    END
  END b_d[243]
  PIN b_d[244]
    DIRECTION OUTPUT ;
    USE SIGNAL ;
    PORT
      LAYER M5 ;
        RECT  27.984 0 28.008 0.084 ;
    END
  END b_d[244]
  PIN b_d[245]
    DIRECTION OUTPUT ;
    USE SIGNAL ;
    PORT
      LAYER M5 ;
        RECT  28.08 0 28.104 0.084 ;
    END
  END b_d[245]
  PIN b_d[246]
    DIRECTION OUTPUT ;
    USE SIGNAL ;
    PORT
      LAYER M5 ;
        RECT  28.176 0 28.2 0.084 ;
    END
  END b_d[246]
  PIN b_d[247]
    DIRECTION OUTPUT ;
    USE SIGNAL ;
    PORT
      LAYER M5 ;
        RECT  28.272 0 28.296 0.084 ;
    END
  END b_d[247]
  PIN b_d[248]
    DIRECTION OUTPUT ;
    USE SIGNAL ;
    PORT
      LAYER M5 ;
        RECT  28.368 0 28.392 0.084 ;
    END
  END b_d[248]
  PIN b_d[249]
    DIRECTION OUTPUT ;
    USE SIGNAL ;
    PORT
      LAYER M5 ;
        RECT  28.464 0 28.488 0.084 ;
    END
  END b_d[249]
  PIN b_d[24]
    DIRECTION OUTPUT ;
    USE SIGNAL ;
    PORT
      LAYER M3 ;
        RECT  21.276 0 21.294 0.037 ;
    END
  END b_d[24]
  PIN b_d[250]
    DIRECTION OUTPUT ;
    USE SIGNAL ;
    PORT
      LAYER M5 ;
        RECT  28.56 0 28.584 0.084 ;
    END
  END b_d[250]
  PIN b_d[251]
    DIRECTION OUTPUT ;
    USE SIGNAL ;
    PORT
      LAYER M5 ;
        RECT  28.656 0 28.68 0.084 ;
    END
  END b_d[251]
  PIN b_d[252]
    DIRECTION OUTPUT ;
    USE SIGNAL ;
    PORT
      LAYER M5 ;
        RECT  28.752 0 28.776 0.084 ;
    END
  END b_d[252]
  PIN b_d[253]
    DIRECTION OUTPUT ;
    USE SIGNAL ;
    PORT
      LAYER M5 ;
        RECT  28.848 0 28.872 0.084 ;
    END
  END b_d[253]
  PIN b_d[254]
    DIRECTION OUTPUT ;
    USE SIGNAL ;
    PORT
      LAYER M5 ;
        RECT  28.944 0 28.968 0.084 ;
    END
  END b_d[254]
  PIN b_d[255]
    DIRECTION OUTPUT ;
    USE SIGNAL ;
    PORT
      LAYER M5 ;
        RECT  29.04 0 29.064 0.084 ;
    END
  END b_d[255]
  PIN b_d[256]
    DIRECTION OUTPUT ;
    USE SIGNAL ;
    PORT
      LAYER M5 ;
        RECT  35.28 0 35.304 0.084 ;
    END
  END b_d[256]
  PIN b_d[257]
    DIRECTION OUTPUT ;
    USE SIGNAL ;
    PORT
      LAYER M5 ;
        RECT  35.376 0 35.4 0.084 ;
    END
  END b_d[257]
  PIN b_d[258]
    DIRECTION OUTPUT ;
    USE SIGNAL ;
    PORT
      LAYER M5 ;
        RECT  35.472 0 35.496 0.084 ;
    END
  END b_d[258]
  PIN b_d[259]
    DIRECTION OUTPUT ;
    USE SIGNAL ;
    PORT
      LAYER M5 ;
        RECT  35.568 0 35.592 0.084 ;
    END
  END b_d[259]
  PIN b_d[25]
    DIRECTION OUTPUT ;
    USE SIGNAL ;
    PORT
      LAYER M3 ;
        RECT  21.348 0 21.366 0.037 ;
    END
  END b_d[25]
  PIN b_d[260]
    DIRECTION OUTPUT ;
    USE SIGNAL ;
    PORT
      LAYER M5 ;
        RECT  35.664 0 35.688 0.084 ;
    END
  END b_d[260]
  PIN b_d[261]
    DIRECTION OUTPUT ;
    USE SIGNAL ;
    PORT
      LAYER M5 ;
        RECT  35.76 0 35.784 0.084 ;
    END
  END b_d[261]
  PIN b_d[262]
    DIRECTION OUTPUT ;
    USE SIGNAL ;
    PORT
      LAYER M5 ;
        RECT  35.856 0 35.88 0.084 ;
    END
  END b_d[262]
  PIN b_d[263]
    DIRECTION OUTPUT ;
    USE SIGNAL ;
    PORT
      LAYER M5 ;
        RECT  35.952 0 35.976 0.084 ;
    END
  END b_d[263]
  PIN b_d[264]
    DIRECTION OUTPUT ;
    USE SIGNAL ;
    PORT
      LAYER M5 ;
        RECT  36.048 0 36.072 0.084 ;
    END
  END b_d[264]
  PIN b_d[265]
    DIRECTION OUTPUT ;
    USE SIGNAL ;
    PORT
      LAYER M5 ;
        RECT  36.144 0 36.168 0.084 ;
    END
  END b_d[265]
  PIN b_d[266]
    DIRECTION OUTPUT ;
    USE SIGNAL ;
    PORT
      LAYER M5 ;
        RECT  36.24 0 36.264 0.084 ;
    END
  END b_d[266]
  PIN b_d[267]
    DIRECTION OUTPUT ;
    USE SIGNAL ;
    PORT
      LAYER M5 ;
        RECT  36.336 0 36.36 0.084 ;
    END
  END b_d[267]
  PIN b_d[268]
    DIRECTION OUTPUT ;
    USE SIGNAL ;
    PORT
      LAYER M5 ;
        RECT  36.432 0 36.456 0.084 ;
    END
  END b_d[268]
  PIN b_d[269]
    DIRECTION OUTPUT ;
    USE SIGNAL ;
    PORT
      LAYER M5 ;
        RECT  36.528 0 36.552 0.084 ;
    END
  END b_d[269]
  PIN b_d[26]
    DIRECTION OUTPUT ;
    USE SIGNAL ;
    PORT
      LAYER M3 ;
        RECT  21.42 0 21.438 0.037 ;
    END
  END b_d[26]
  PIN b_d[270]
    DIRECTION OUTPUT ;
    USE SIGNAL ;
    PORT
      LAYER M5 ;
        RECT  36.624 0 36.648 0.084 ;
    END
  END b_d[270]
  PIN b_d[271]
    DIRECTION OUTPUT ;
    USE SIGNAL ;
    PORT
      LAYER M5 ;
        RECT  36.72 0 36.744 0.084 ;
    END
  END b_d[271]
  PIN b_d[272]
    DIRECTION OUTPUT ;
    USE SIGNAL ;
    PORT
      LAYER M5 ;
        RECT  36.816 0 36.84 0.084 ;
    END
  END b_d[272]
  PIN b_d[273]
    DIRECTION OUTPUT ;
    USE SIGNAL ;
    PORT
      LAYER M5 ;
        RECT  36.912 0 36.936 0.084 ;
    END
  END b_d[273]
  PIN b_d[274]
    DIRECTION OUTPUT ;
    USE SIGNAL ;
    PORT
      LAYER M5 ;
        RECT  37.008 0 37.032 0.084 ;
    END
  END b_d[274]
  PIN b_d[275]
    DIRECTION OUTPUT ;
    USE SIGNAL ;
    PORT
      LAYER M5 ;
        RECT  37.104 0 37.128 0.084 ;
    END
  END b_d[275]
  PIN b_d[276]
    DIRECTION OUTPUT ;
    USE SIGNAL ;
    PORT
      LAYER M5 ;
        RECT  37.2 0 37.224 0.084 ;
    END
  END b_d[276]
  PIN b_d[277]
    DIRECTION OUTPUT ;
    USE SIGNAL ;
    PORT
      LAYER M5 ;
        RECT  37.296 0 37.32 0.084 ;
    END
  END b_d[277]
  PIN b_d[278]
    DIRECTION OUTPUT ;
    USE SIGNAL ;
    PORT
      LAYER M5 ;
        RECT  37.392 0 37.416 0.084 ;
    END
  END b_d[278]
  PIN b_d[279]
    DIRECTION OUTPUT ;
    USE SIGNAL ;
    PORT
      LAYER M5 ;
        RECT  37.488 0 37.512 0.084 ;
    END
  END b_d[279]
  PIN b_d[27]
    DIRECTION OUTPUT ;
    USE SIGNAL ;
    PORT
      LAYER M3 ;
        RECT  21.492 0 21.51 0.037 ;
    END
  END b_d[27]
  PIN b_d[280]
    DIRECTION OUTPUT ;
    USE SIGNAL ;
    PORT
      LAYER M5 ;
        RECT  37.584 0 37.608 0.084 ;
    END
  END b_d[280]
  PIN b_d[281]
    DIRECTION OUTPUT ;
    USE SIGNAL ;
    PORT
      LAYER M5 ;
        RECT  37.68 0 37.704 0.084 ;
    END
  END b_d[281]
  PIN b_d[282]
    DIRECTION OUTPUT ;
    USE SIGNAL ;
    PORT
      LAYER M5 ;
        RECT  37.776 0 37.8 0.084 ;
    END
  END b_d[282]
  PIN b_d[283]
    DIRECTION OUTPUT ;
    USE SIGNAL ;
    PORT
      LAYER M5 ;
        RECT  37.872 0 37.896 0.084 ;
    END
  END b_d[283]
  PIN b_d[284]
    DIRECTION OUTPUT ;
    USE SIGNAL ;
    PORT
      LAYER M5 ;
        RECT  37.968 0 37.992 0.084 ;
    END
  END b_d[284]
  PIN b_d[285]
    DIRECTION OUTPUT ;
    USE SIGNAL ;
    PORT
      LAYER M5 ;
        RECT  38.064 0 38.088 0.084 ;
    END
  END b_d[285]
  PIN b_d[286]
    DIRECTION OUTPUT ;
    USE SIGNAL ;
    PORT
      LAYER M5 ;
        RECT  38.16 0 38.184 0.084 ;
    END
  END b_d[286]
  PIN b_d[287]
    DIRECTION OUTPUT ;
    USE SIGNAL ;
    PORT
      LAYER M5 ;
        RECT  38.256 0 38.28 0.084 ;
    END
  END b_d[287]
  PIN b_d[288]
    DIRECTION OUTPUT ;
    USE SIGNAL ;
    PORT
      LAYER M3 ;
        RECT  24.156 0 24.174 0.037 ;
    END
  END b_d[288]
  PIN b_d[289]
    DIRECTION OUTPUT ;
    USE SIGNAL ;
    PORT
      LAYER M3 ;
        RECT  24.228 0 24.246 0.037 ;
    END
  END b_d[289]
  PIN b_d[28]
    DIRECTION OUTPUT ;
    USE SIGNAL ;
    PORT
      LAYER M3 ;
        RECT  21.564 0 21.582 0.037 ;
    END
  END b_d[28]
  PIN b_d[290]
    DIRECTION OUTPUT ;
    USE SIGNAL ;
    PORT
      LAYER M3 ;
        RECT  24.3 0 24.318 0.037 ;
    END
  END b_d[290]
  PIN b_d[291]
    DIRECTION OUTPUT ;
    USE SIGNAL ;
    PORT
      LAYER M3 ;
        RECT  24.372 0 24.39 0.037 ;
    END
  END b_d[291]
  PIN b_d[292]
    DIRECTION OUTPUT ;
    USE SIGNAL ;
    PORT
      LAYER M3 ;
        RECT  24.444 0 24.462 0.037 ;
    END
  END b_d[292]
  PIN b_d[293]
    DIRECTION OUTPUT ;
    USE SIGNAL ;
    PORT
      LAYER M3 ;
        RECT  24.516 0 24.534 0.037 ;
    END
  END b_d[293]
  PIN b_d[294]
    DIRECTION OUTPUT ;
    USE SIGNAL ;
    PORT
      LAYER M3 ;
        RECT  24.588 0 24.606 0.037 ;
    END
  END b_d[294]
  PIN b_d[295]
    DIRECTION OUTPUT ;
    USE SIGNAL ;
    PORT
      LAYER M3 ;
        RECT  24.66 0 24.678 0.037 ;
    END
  END b_d[295]
  PIN b_d[296]
    DIRECTION OUTPUT ;
    USE SIGNAL ;
    PORT
      LAYER M3 ;
        RECT  24.732 0 24.75 0.037 ;
    END
  END b_d[296]
  PIN b_d[297]
    DIRECTION OUTPUT ;
    USE SIGNAL ;
    PORT
      LAYER M3 ;
        RECT  24.804 0 24.822 0.037 ;
    END
  END b_d[297]
  PIN b_d[298]
    DIRECTION OUTPUT ;
    USE SIGNAL ;
    PORT
      LAYER M3 ;
        RECT  24.876 0 24.894 0.037 ;
    END
  END b_d[298]
  PIN b_d[299]
    DIRECTION OUTPUT ;
    USE SIGNAL ;
    PORT
      LAYER M3 ;
        RECT  24.948 0 24.966 0.037 ;
    END
  END b_d[299]
  PIN b_d[29]
    DIRECTION OUTPUT ;
    USE SIGNAL ;
    PORT
      LAYER M3 ;
        RECT  21.636 0 21.654 0.037 ;
    END
  END b_d[29]
  PIN b_d[2]
    DIRECTION OUTPUT ;
    USE SIGNAL ;
    PORT
      LAYER M3 ;
        RECT  19.692 0 19.71 0.037 ;
    END
  END b_d[2]
  PIN b_d[300]
    DIRECTION OUTPUT ;
    USE SIGNAL ;
    PORT
      LAYER M3 ;
        RECT  25.02 0 25.038 0.037 ;
    END
  END b_d[300]
  PIN b_d[301]
    DIRECTION OUTPUT ;
    USE SIGNAL ;
    PORT
      LAYER M3 ;
        RECT  25.092 0 25.11 0.037 ;
    END
  END b_d[301]
  PIN b_d[302]
    DIRECTION OUTPUT ;
    USE SIGNAL ;
    PORT
      LAYER M3 ;
        RECT  25.164 0 25.182 0.037 ;
    END
  END b_d[302]
  PIN b_d[303]
    DIRECTION OUTPUT ;
    USE SIGNAL ;
    PORT
      LAYER M3 ;
        RECT  25.236 0 25.254 0.037 ;
    END
  END b_d[303]
  PIN b_d[304]
    DIRECTION OUTPUT ;
    USE SIGNAL ;
    PORT
      LAYER M3 ;
        RECT  25.308 0 25.326 0.037 ;
    END
  END b_d[304]
  PIN b_d[305]
    DIRECTION OUTPUT ;
    USE SIGNAL ;
    PORT
      LAYER M3 ;
        RECT  25.38 0 25.398 0.037 ;
    END
  END b_d[305]
  PIN b_d[306]
    DIRECTION OUTPUT ;
    USE SIGNAL ;
    PORT
      LAYER M3 ;
        RECT  25.452 0 25.47 0.037 ;
    END
  END b_d[306]
  PIN b_d[307]
    DIRECTION OUTPUT ;
    USE SIGNAL ;
    PORT
      LAYER M3 ;
        RECT  25.524 0 25.542 0.037 ;
    END
  END b_d[307]
  PIN b_d[308]
    DIRECTION OUTPUT ;
    USE SIGNAL ;
    PORT
      LAYER M3 ;
        RECT  25.596 0 25.614 0.037 ;
    END
  END b_d[308]
  PIN b_d[309]
    DIRECTION OUTPUT ;
    USE SIGNAL ;
    PORT
      LAYER M3 ;
        RECT  25.668 0 25.686 0.037 ;
    END
  END b_d[309]
  PIN b_d[30]
    DIRECTION OUTPUT ;
    USE SIGNAL ;
    PORT
      LAYER M3 ;
        RECT  21.708 0 21.726 0.037 ;
    END
  END b_d[30]
  PIN b_d[310]
    DIRECTION OUTPUT ;
    USE SIGNAL ;
    PORT
      LAYER M3 ;
        RECT  25.74 0 25.758 0.037 ;
    END
  END b_d[310]
  PIN b_d[311]
    DIRECTION OUTPUT ;
    USE SIGNAL ;
    PORT
      LAYER M3 ;
        RECT  25.812 0 25.83 0.037 ;
    END
  END b_d[311]
  PIN b_d[312]
    DIRECTION OUTPUT ;
    USE SIGNAL ;
    PORT
      LAYER M3 ;
        RECT  25.884 0 25.902 0.037 ;
    END
  END b_d[312]
  PIN b_d[313]
    DIRECTION OUTPUT ;
    USE SIGNAL ;
    PORT
      LAYER M3 ;
        RECT  25.956 0 25.974 0.037 ;
    END
  END b_d[313]
  PIN b_d[314]
    DIRECTION OUTPUT ;
    USE SIGNAL ;
    PORT
      LAYER M3 ;
        RECT  26.028 0 26.046 0.037 ;
    END
  END b_d[314]
  PIN b_d[315]
    DIRECTION OUTPUT ;
    USE SIGNAL ;
    PORT
      LAYER M3 ;
        RECT  26.1 0 26.118 0.037 ;
    END
  END b_d[315]
  PIN b_d[316]
    DIRECTION OUTPUT ;
    USE SIGNAL ;
    PORT
      LAYER M3 ;
        RECT  26.172 0 26.19 0.037 ;
    END
  END b_d[316]
  PIN b_d[317]
    DIRECTION OUTPUT ;
    USE SIGNAL ;
    PORT
      LAYER M3 ;
        RECT  26.244 0 26.262 0.037 ;
    END
  END b_d[317]
  PIN b_d[318]
    DIRECTION OUTPUT ;
    USE SIGNAL ;
    PORT
      LAYER M3 ;
        RECT  26.316 0 26.334 0.037 ;
    END
  END b_d[318]
  PIN b_d[319]
    DIRECTION OUTPUT ;
    USE SIGNAL ;
    PORT
      LAYER M3 ;
        RECT  26.388 0 26.406 0.037 ;
    END
  END b_d[319]
  PIN b_d[31]
    DIRECTION OUTPUT ;
    USE SIGNAL ;
    PORT
      LAYER M3 ;
        RECT  21.78 0 21.798 0.037 ;
    END
  END b_d[31]
  PIN b_d[320]
    DIRECTION OUTPUT ;
    USE SIGNAL ;
    PORT
      LAYER M3 ;
        RECT  26.46 0 26.478 0.037 ;
    END
  END b_d[320]
  PIN b_d[321]
    DIRECTION OUTPUT ;
    USE SIGNAL ;
    PORT
      LAYER M3 ;
        RECT  26.532 0 26.55 0.037 ;
    END
  END b_d[321]
  PIN b_d[322]
    DIRECTION OUTPUT ;
    USE SIGNAL ;
    PORT
      LAYER M3 ;
        RECT  26.604 0 26.622 0.037 ;
    END
  END b_d[322]
  PIN b_d[323]
    DIRECTION OUTPUT ;
    USE SIGNAL ;
    PORT
      LAYER M3 ;
        RECT  26.676 0 26.694 0.037 ;
    END
  END b_d[323]
  PIN b_d[324]
    DIRECTION OUTPUT ;
    USE SIGNAL ;
    PORT
      LAYER M3 ;
        RECT  26.748 0 26.766 0.037 ;
    END
  END b_d[324]
  PIN b_d[325]
    DIRECTION OUTPUT ;
    USE SIGNAL ;
    PORT
      LAYER M3 ;
        RECT  26.82 0 26.838 0.037 ;
    END
  END b_d[325]
  PIN b_d[326]
    DIRECTION OUTPUT ;
    USE SIGNAL ;
    PORT
      LAYER M3 ;
        RECT  26.892 0 26.91 0.037 ;
    END
  END b_d[326]
  PIN b_d[327]
    DIRECTION OUTPUT ;
    USE SIGNAL ;
    PORT
      LAYER M3 ;
        RECT  26.964 0 26.982 0.037 ;
    END
  END b_d[327]
  PIN b_d[328]
    DIRECTION OUTPUT ;
    USE SIGNAL ;
    PORT
      LAYER M3 ;
        RECT  27.036 0 27.054 0.037 ;
    END
  END b_d[328]
  PIN b_d[329]
    DIRECTION OUTPUT ;
    USE SIGNAL ;
    PORT
      LAYER M3 ;
        RECT  27.108 0 27.126 0.037 ;
    END
  END b_d[329]
  PIN b_d[32]
    DIRECTION OUTPUT ;
    USE SIGNAL ;
    PORT
      LAYER M5 ;
        RECT  32.208 0 32.232 0.084 ;
    END
  END b_d[32]
  PIN b_d[330]
    DIRECTION OUTPUT ;
    USE SIGNAL ;
    PORT
      LAYER M3 ;
        RECT  27.18 0 27.198 0.037 ;
    END
  END b_d[330]
  PIN b_d[331]
    DIRECTION OUTPUT ;
    USE SIGNAL ;
    PORT
      LAYER M3 ;
        RECT  27.252 0 27.27 0.037 ;
    END
  END b_d[331]
  PIN b_d[332]
    DIRECTION OUTPUT ;
    USE SIGNAL ;
    PORT
      LAYER M3 ;
        RECT  27.324 0 27.342 0.037 ;
    END
  END b_d[332]
  PIN b_d[333]
    DIRECTION OUTPUT ;
    USE SIGNAL ;
    PORT
      LAYER M3 ;
        RECT  27.396 0 27.414 0.037 ;
    END
  END b_d[333]
  PIN b_d[334]
    DIRECTION OUTPUT ;
    USE SIGNAL ;
    PORT
      LAYER M3 ;
        RECT  27.468 0 27.486 0.037 ;
    END
  END b_d[334]
  PIN b_d[335]
    DIRECTION OUTPUT ;
    USE SIGNAL ;
    PORT
      LAYER M3 ;
        RECT  27.54 0 27.558 0.037 ;
    END
  END b_d[335]
  PIN b_d[336]
    DIRECTION OUTPUT ;
    USE SIGNAL ;
    PORT
      LAYER M3 ;
        RECT  27.612 0 27.63 0.037 ;
    END
  END b_d[336]
  PIN b_d[337]
    DIRECTION OUTPUT ;
    USE SIGNAL ;
    PORT
      LAYER M3 ;
        RECT  27.684 0 27.702 0.037 ;
    END
  END b_d[337]
  PIN b_d[338]
    DIRECTION OUTPUT ;
    USE SIGNAL ;
    PORT
      LAYER M3 ;
        RECT  27.756 0 27.774 0.037 ;
    END
  END b_d[338]
  PIN b_d[339]
    DIRECTION OUTPUT ;
    USE SIGNAL ;
    PORT
      LAYER M3 ;
        RECT  27.828 0 27.846 0.037 ;
    END
  END b_d[339]
  PIN b_d[33]
    DIRECTION OUTPUT ;
    USE SIGNAL ;
    PORT
      LAYER M5 ;
        RECT  32.304 0 32.328 0.084 ;
    END
  END b_d[33]
  PIN b_d[340]
    DIRECTION OUTPUT ;
    USE SIGNAL ;
    PORT
      LAYER M3 ;
        RECT  27.9 0 27.918 0.037 ;
    END
  END b_d[340]
  PIN b_d[341]
    DIRECTION OUTPUT ;
    USE SIGNAL ;
    PORT
      LAYER M3 ;
        RECT  27.972 0 27.99 0.037 ;
    END
  END b_d[341]
  PIN b_d[342]
    DIRECTION OUTPUT ;
    USE SIGNAL ;
    PORT
      LAYER M3 ;
        RECT  28.044 0 28.062 0.037 ;
    END
  END b_d[342]
  PIN b_d[343]
    DIRECTION OUTPUT ;
    USE SIGNAL ;
    PORT
      LAYER M3 ;
        RECT  28.116 0 28.134 0.037 ;
    END
  END b_d[343]
  PIN b_d[344]
    DIRECTION OUTPUT ;
    USE SIGNAL ;
    PORT
      LAYER M3 ;
        RECT  28.188 0 28.206 0.037 ;
    END
  END b_d[344]
  PIN b_d[345]
    DIRECTION OUTPUT ;
    USE SIGNAL ;
    PORT
      LAYER M3 ;
        RECT  28.26 0 28.278 0.037 ;
    END
  END b_d[345]
  PIN b_d[346]
    DIRECTION OUTPUT ;
    USE SIGNAL ;
    PORT
      LAYER M3 ;
        RECT  28.332 0 28.35 0.037 ;
    END
  END b_d[346]
  PIN b_d[347]
    DIRECTION OUTPUT ;
    USE SIGNAL ;
    PORT
      LAYER M3 ;
        RECT  28.404 0 28.422 0.037 ;
    END
  END b_d[347]
  PIN b_d[348]
    DIRECTION OUTPUT ;
    USE SIGNAL ;
    PORT
      LAYER M3 ;
        RECT  28.476 0 28.494 0.037 ;
    END
  END b_d[348]
  PIN b_d[349]
    DIRECTION OUTPUT ;
    USE SIGNAL ;
    PORT
      LAYER M3 ;
        RECT  28.548 0 28.566 0.037 ;
    END
  END b_d[349]
  PIN b_d[34]
    DIRECTION OUTPUT ;
    USE SIGNAL ;
    PORT
      LAYER M5 ;
        RECT  32.4 0 32.424 0.084 ;
    END
  END b_d[34]
  PIN b_d[350]
    DIRECTION OUTPUT ;
    USE SIGNAL ;
    PORT
      LAYER M3 ;
        RECT  28.62 0 28.638 0.037 ;
    END
  END b_d[350]
  PIN b_d[351]
    DIRECTION OUTPUT ;
    USE SIGNAL ;
    PORT
      LAYER M3 ;
        RECT  28.692 0 28.71 0.037 ;
    END
  END b_d[351]
  PIN b_d[352]
    DIRECTION OUTPUT ;
    USE SIGNAL ;
    PORT
      LAYER M3 ;
        RECT  36.252 0 36.27 0.037 ;
    END
  END b_d[352]
  PIN b_d[353]
    DIRECTION OUTPUT ;
    USE SIGNAL ;
    PORT
      LAYER M3 ;
        RECT  36.324 0 36.342 0.037 ;
    END
  END b_d[353]
  PIN b_d[354]
    DIRECTION OUTPUT ;
    USE SIGNAL ;
    PORT
      LAYER M3 ;
        RECT  36.396 0 36.414 0.037 ;
    END
  END b_d[354]
  PIN b_d[355]
    DIRECTION OUTPUT ;
    USE SIGNAL ;
    PORT
      LAYER M3 ;
        RECT  36.468 0 36.486 0.037 ;
    END
  END b_d[355]
  PIN b_d[356]
    DIRECTION OUTPUT ;
    USE SIGNAL ;
    PORT
      LAYER M3 ;
        RECT  36.54 0 36.558 0.037 ;
    END
  END b_d[356]
  PIN b_d[357]
    DIRECTION OUTPUT ;
    USE SIGNAL ;
    PORT
      LAYER M3 ;
        RECT  36.612 0 36.63 0.037 ;
    END
  END b_d[357]
  PIN b_d[358]
    DIRECTION OUTPUT ;
    USE SIGNAL ;
    PORT
      LAYER M3 ;
        RECT  36.684 0 36.702 0.037 ;
    END
  END b_d[358]
  PIN b_d[359]
    DIRECTION OUTPUT ;
    USE SIGNAL ;
    PORT
      LAYER M3 ;
        RECT  36.756 0 36.774 0.037 ;
    END
  END b_d[359]
  PIN b_d[35]
    DIRECTION OUTPUT ;
    USE SIGNAL ;
    PORT
      LAYER M5 ;
        RECT  32.496 0 32.52 0.084 ;
    END
  END b_d[35]
  PIN b_d[360]
    DIRECTION OUTPUT ;
    USE SIGNAL ;
    PORT
      LAYER M3 ;
        RECT  36.828 0 36.846 0.037 ;
    END
  END b_d[360]
  PIN b_d[361]
    DIRECTION OUTPUT ;
    USE SIGNAL ;
    PORT
      LAYER M3 ;
        RECT  36.9 0 36.918 0.037 ;
    END
  END b_d[361]
  PIN b_d[362]
    DIRECTION OUTPUT ;
    USE SIGNAL ;
    PORT
      LAYER M3 ;
        RECT  36.972 0 36.99 0.037 ;
    END
  END b_d[362]
  PIN b_d[363]
    DIRECTION OUTPUT ;
    USE SIGNAL ;
    PORT
      LAYER M3 ;
        RECT  37.044 0 37.062 0.037 ;
    END
  END b_d[363]
  PIN b_d[364]
    DIRECTION OUTPUT ;
    USE SIGNAL ;
    PORT
      LAYER M3 ;
        RECT  37.116 0 37.134 0.037 ;
    END
  END b_d[364]
  PIN b_d[365]
    DIRECTION OUTPUT ;
    USE SIGNAL ;
    PORT
      LAYER M3 ;
        RECT  37.188 0 37.206 0.037 ;
    END
  END b_d[365]
  PIN b_d[366]
    DIRECTION OUTPUT ;
    USE SIGNAL ;
    PORT
      LAYER M3 ;
        RECT  37.26 0 37.278 0.037 ;
    END
  END b_d[366]
  PIN b_d[367]
    DIRECTION OUTPUT ;
    USE SIGNAL ;
    PORT
      LAYER M3 ;
        RECT  37.332 0 37.35 0.037 ;
    END
  END b_d[367]
  PIN b_d[368]
    DIRECTION OUTPUT ;
    USE SIGNAL ;
    PORT
      LAYER M3 ;
        RECT  37.404 0 37.422 0.037 ;
    END
  END b_d[368]
  PIN b_d[369]
    DIRECTION OUTPUT ;
    USE SIGNAL ;
    PORT
      LAYER M3 ;
        RECT  37.476 0 37.494 0.037 ;
    END
  END b_d[369]
  PIN b_d[36]
    DIRECTION OUTPUT ;
    USE SIGNAL ;
    PORT
      LAYER M5 ;
        RECT  32.592 0 32.616 0.084 ;
    END
  END b_d[36]
  PIN b_d[370]
    DIRECTION OUTPUT ;
    USE SIGNAL ;
    PORT
      LAYER M3 ;
        RECT  37.548 0 37.566 0.037 ;
    END
  END b_d[370]
  PIN b_d[371]
    DIRECTION OUTPUT ;
    USE SIGNAL ;
    PORT
      LAYER M3 ;
        RECT  37.62 0 37.638 0.037 ;
    END
  END b_d[371]
  PIN b_d[372]
    DIRECTION OUTPUT ;
    USE SIGNAL ;
    PORT
      LAYER M3 ;
        RECT  37.692 0 37.71 0.037 ;
    END
  END b_d[372]
  PIN b_d[373]
    DIRECTION OUTPUT ;
    USE SIGNAL ;
    PORT
      LAYER M3 ;
        RECT  37.764 0 37.782 0.037 ;
    END
  END b_d[373]
  PIN b_d[374]
    DIRECTION OUTPUT ;
    USE SIGNAL ;
    PORT
      LAYER M3 ;
        RECT  37.836 0 37.854 0.037 ;
    END
  END b_d[374]
  PIN b_d[375]
    DIRECTION OUTPUT ;
    USE SIGNAL ;
    PORT
      LAYER M3 ;
        RECT  37.908 0 37.926 0.037 ;
    END
  END b_d[375]
  PIN b_d[376]
    DIRECTION OUTPUT ;
    USE SIGNAL ;
    PORT
      LAYER M3 ;
        RECT  37.98 0 37.998 0.037 ;
    END
  END b_d[376]
  PIN b_d[377]
    DIRECTION OUTPUT ;
    USE SIGNAL ;
    PORT
      LAYER M3 ;
        RECT  38.052 0 38.07 0.037 ;
    END
  END b_d[377]
  PIN b_d[378]
    DIRECTION OUTPUT ;
    USE SIGNAL ;
    PORT
      LAYER M3 ;
        RECT  38.124 0 38.142 0.037 ;
    END
  END b_d[378]
  PIN b_d[379]
    DIRECTION OUTPUT ;
    USE SIGNAL ;
    PORT
      LAYER M3 ;
        RECT  38.196 0 38.214 0.037 ;
    END
  END b_d[379]
  PIN b_d[37]
    DIRECTION OUTPUT ;
    USE SIGNAL ;
    PORT
      LAYER M5 ;
        RECT  32.688 0 32.712 0.084 ;
    END
  END b_d[37]
  PIN b_d[380]
    DIRECTION OUTPUT ;
    USE SIGNAL ;
    PORT
      LAYER M3 ;
        RECT  38.268 0 38.286 0.037 ;
    END
  END b_d[380]
  PIN b_d[381]
    DIRECTION OUTPUT ;
    USE SIGNAL ;
    PORT
      LAYER M3 ;
        RECT  38.34 0 38.358 0.037 ;
    END
  END b_d[381]
  PIN b_d[382]
    DIRECTION OUTPUT ;
    USE SIGNAL ;
    PORT
      LAYER M3 ;
        RECT  38.412 0 38.43 0.037 ;
    END
  END b_d[382]
  PIN b_d[383]
    DIRECTION OUTPUT ;
    USE SIGNAL ;
    PORT
      LAYER M3 ;
        RECT  38.484 0 38.502 0.037 ;
    END
  END b_d[383]
  PIN b_d[384]
    DIRECTION OUTPUT ;
    USE SIGNAL ;
    PORT
      LAYER M3 ;
        RECT  33.948 0 33.966 0.037 ;
    END
  END b_d[384]
  PIN b_d[385]
    DIRECTION OUTPUT ;
    USE SIGNAL ;
    PORT
      LAYER M3 ;
        RECT  34.02 0 34.038 0.037 ;
    END
  END b_d[385]
  PIN b_d[386]
    DIRECTION OUTPUT ;
    USE SIGNAL ;
    PORT
      LAYER M3 ;
        RECT  34.092 0 34.11 0.037 ;
    END
  END b_d[386]
  PIN b_d[387]
    DIRECTION OUTPUT ;
    USE SIGNAL ;
    PORT
      LAYER M3 ;
        RECT  34.164 0 34.182 0.037 ;
    END
  END b_d[387]
  PIN b_d[388]
    DIRECTION OUTPUT ;
    USE SIGNAL ;
    PORT
      LAYER M3 ;
        RECT  34.236 0 34.254 0.037 ;
    END
  END b_d[388]
  PIN b_d[389]
    DIRECTION OUTPUT ;
    USE SIGNAL ;
    PORT
      LAYER M3 ;
        RECT  34.308 0 34.326 0.037 ;
    END
  END b_d[389]
  PIN b_d[38]
    DIRECTION OUTPUT ;
    USE SIGNAL ;
    PORT
      LAYER M5 ;
        RECT  32.784 0 32.808 0.084 ;
    END
  END b_d[38]
  PIN b_d[390]
    DIRECTION OUTPUT ;
    USE SIGNAL ;
    PORT
      LAYER M3 ;
        RECT  34.38 0 34.398 0.037 ;
    END
  END b_d[390]
  PIN b_d[391]
    DIRECTION OUTPUT ;
    USE SIGNAL ;
    PORT
      LAYER M3 ;
        RECT  34.452 0 34.47 0.037 ;
    END
  END b_d[391]
  PIN b_d[392]
    DIRECTION OUTPUT ;
    USE SIGNAL ;
    PORT
      LAYER M3 ;
        RECT  34.524 0 34.542 0.037 ;
    END
  END b_d[392]
  PIN b_d[393]
    DIRECTION OUTPUT ;
    USE SIGNAL ;
    PORT
      LAYER M3 ;
        RECT  34.596 0 34.614 0.037 ;
    END
  END b_d[393]
  PIN b_d[394]
    DIRECTION OUTPUT ;
    USE SIGNAL ;
    PORT
      LAYER M3 ;
        RECT  34.668 0 34.686 0.037 ;
    END
  END b_d[394]
  PIN b_d[395]
    DIRECTION OUTPUT ;
    USE SIGNAL ;
    PORT
      LAYER M3 ;
        RECT  34.74 0 34.758 0.037 ;
    END
  END b_d[395]
  PIN b_d[396]
    DIRECTION OUTPUT ;
    USE SIGNAL ;
    PORT
      LAYER M3 ;
        RECT  34.812 0 34.83 0.037 ;
    END
  END b_d[396]
  PIN b_d[397]
    DIRECTION OUTPUT ;
    USE SIGNAL ;
    PORT
      LAYER M3 ;
        RECT  34.884 0 34.902 0.037 ;
    END
  END b_d[397]
  PIN b_d[398]
    DIRECTION OUTPUT ;
    USE SIGNAL ;
    PORT
      LAYER M3 ;
        RECT  34.956 0 34.974 0.037 ;
    END
  END b_d[398]
  PIN b_d[399]
    DIRECTION OUTPUT ;
    USE SIGNAL ;
    PORT
      LAYER M3 ;
        RECT  35.028 0 35.046 0.037 ;
    END
  END b_d[399]
  PIN b_d[39]
    DIRECTION OUTPUT ;
    USE SIGNAL ;
    PORT
      LAYER M5 ;
        RECT  32.88 0 32.904 0.084 ;
    END
  END b_d[39]
  PIN b_d[3]
    DIRECTION OUTPUT ;
    USE SIGNAL ;
    PORT
      LAYER M3 ;
        RECT  19.764 0 19.782 0.037 ;
    END
  END b_d[3]
  PIN b_d[400]
    DIRECTION OUTPUT ;
    USE SIGNAL ;
    PORT
      LAYER M3 ;
        RECT  35.1 0 35.118 0.037 ;
    END
  END b_d[400]
  PIN b_d[401]
    DIRECTION OUTPUT ;
    USE SIGNAL ;
    PORT
      LAYER M3 ;
        RECT  35.172 0 35.19 0.037 ;
    END
  END b_d[401]
  PIN b_d[402]
    DIRECTION OUTPUT ;
    USE SIGNAL ;
    PORT
      LAYER M3 ;
        RECT  35.244 0 35.262 0.037 ;
    END
  END b_d[402]
  PIN b_d[403]
    DIRECTION OUTPUT ;
    USE SIGNAL ;
    PORT
      LAYER M3 ;
        RECT  35.316 0 35.334 0.037 ;
    END
  END b_d[403]
  PIN b_d[404]
    DIRECTION OUTPUT ;
    USE SIGNAL ;
    PORT
      LAYER M3 ;
        RECT  35.388 0 35.406 0.037 ;
    END
  END b_d[404]
  PIN b_d[405]
    DIRECTION OUTPUT ;
    USE SIGNAL ;
    PORT
      LAYER M3 ;
        RECT  35.46 0 35.478 0.037 ;
    END
  END b_d[405]
  PIN b_d[406]
    DIRECTION OUTPUT ;
    USE SIGNAL ;
    PORT
      LAYER M3 ;
        RECT  35.532 0 35.55 0.037 ;
    END
  END b_d[406]
  PIN b_d[407]
    DIRECTION OUTPUT ;
    USE SIGNAL ;
    PORT
      LAYER M3 ;
        RECT  35.604 0 35.622 0.037 ;
    END
  END b_d[407]
  PIN b_d[408]
    DIRECTION OUTPUT ;
    USE SIGNAL ;
    PORT
      LAYER M3 ;
        RECT  35.676 0 35.694 0.037 ;
    END
  END b_d[408]
  PIN b_d[409]
    DIRECTION OUTPUT ;
    USE SIGNAL ;
    PORT
      LAYER M3 ;
        RECT  35.748 0 35.766 0.037 ;
    END
  END b_d[409]
  PIN b_d[40]
    DIRECTION OUTPUT ;
    USE SIGNAL ;
    PORT
      LAYER M5 ;
        RECT  32.976 0 33 0.084 ;
    END
  END b_d[40]
  PIN b_d[410]
    DIRECTION OUTPUT ;
    USE SIGNAL ;
    PORT
      LAYER M3 ;
        RECT  35.82 0 35.838 0.037 ;
    END
  END b_d[410]
  PIN b_d[411]
    DIRECTION OUTPUT ;
    USE SIGNAL ;
    PORT
      LAYER M3 ;
        RECT  35.892 0 35.91 0.037 ;
    END
  END b_d[411]
  PIN b_d[412]
    DIRECTION OUTPUT ;
    USE SIGNAL ;
    PORT
      LAYER M3 ;
        RECT  35.964 0 35.982 0.037 ;
    END
  END b_d[412]
  PIN b_d[413]
    DIRECTION OUTPUT ;
    USE SIGNAL ;
    PORT
      LAYER M3 ;
        RECT  36.036 0 36.054 0.037 ;
    END
  END b_d[413]
  PIN b_d[414]
    DIRECTION OUTPUT ;
    USE SIGNAL ;
    PORT
      LAYER M3 ;
        RECT  36.108 0 36.126 0.037 ;
    END
  END b_d[414]
  PIN b_d[415]
    DIRECTION OUTPUT ;
    USE SIGNAL ;
    PORT
      LAYER M3 ;
        RECT  36.18 0 36.198 0.037 ;
    END
  END b_d[415]
  PIN b_d[416]
    DIRECTION OUTPUT ;
    USE SIGNAL ;
    PORT
      LAYER M3 ;
        RECT  14.94 0 14.958 0.037 ;
    END
  END b_d[416]
  PIN b_d[417]
    DIRECTION OUTPUT ;
    USE SIGNAL ;
    PORT
      LAYER M3 ;
        RECT  15.012 0 15.03 0.037 ;
    END
  END b_d[417]
  PIN b_d[418]
    DIRECTION OUTPUT ;
    USE SIGNAL ;
    PORT
      LAYER M3 ;
        RECT  15.084 0 15.102 0.037 ;
    END
  END b_d[418]
  PIN b_d[419]
    DIRECTION OUTPUT ;
    USE SIGNAL ;
    PORT
      LAYER M3 ;
        RECT  15.156 0 15.174 0.037 ;
    END
  END b_d[419]
  PIN b_d[41]
    DIRECTION OUTPUT ;
    USE SIGNAL ;
    PORT
      LAYER M5 ;
        RECT  33.072 0 33.096 0.084 ;
    END
  END b_d[41]
  PIN b_d[420]
    DIRECTION OUTPUT ;
    USE SIGNAL ;
    PORT
      LAYER M3 ;
        RECT  15.228 0 15.246 0.037 ;
    END
  END b_d[420]
  PIN b_d[421]
    DIRECTION OUTPUT ;
    USE SIGNAL ;
    PORT
      LAYER M3 ;
        RECT  15.3 0 15.318 0.037 ;
    END
  END b_d[421]
  PIN b_d[422]
    DIRECTION OUTPUT ;
    USE SIGNAL ;
    PORT
      LAYER M3 ;
        RECT  15.372 0 15.39 0.037 ;
    END
  END b_d[422]
  PIN b_d[423]
    DIRECTION OUTPUT ;
    USE SIGNAL ;
    PORT
      LAYER M3 ;
        RECT  15.444 0 15.462 0.037 ;
    END
  END b_d[423]
  PIN b_d[424]
    DIRECTION OUTPUT ;
    USE SIGNAL ;
    PORT
      LAYER M3 ;
        RECT  15.516 0 15.534 0.037 ;
    END
  END b_d[424]
  PIN b_d[425]
    DIRECTION OUTPUT ;
    USE SIGNAL ;
    PORT
      LAYER M3 ;
        RECT  15.588 0 15.606 0.037 ;
    END
  END b_d[425]
  PIN b_d[426]
    DIRECTION OUTPUT ;
    USE SIGNAL ;
    PORT
      LAYER M3 ;
        RECT  15.66 0 15.678 0.037 ;
    END
  END b_d[426]
  PIN b_d[427]
    DIRECTION OUTPUT ;
    USE SIGNAL ;
    PORT
      LAYER M3 ;
        RECT  15.732 0 15.75 0.037 ;
    END
  END b_d[427]
  PIN b_d[428]
    DIRECTION OUTPUT ;
    USE SIGNAL ;
    PORT
      LAYER M3 ;
        RECT  15.804 0 15.822 0.037 ;
    END
  END b_d[428]
  PIN b_d[429]
    DIRECTION OUTPUT ;
    USE SIGNAL ;
    PORT
      LAYER M3 ;
        RECT  15.876 0 15.894 0.037 ;
    END
  END b_d[429]
  PIN b_d[42]
    DIRECTION OUTPUT ;
    USE SIGNAL ;
    PORT
      LAYER M5 ;
        RECT  33.168 0 33.192 0.084 ;
    END
  END b_d[42]
  PIN b_d[430]
    DIRECTION OUTPUT ;
    USE SIGNAL ;
    PORT
      LAYER M3 ;
        RECT  15.948 0 15.966 0.037 ;
    END
  END b_d[430]
  PIN b_d[431]
    DIRECTION OUTPUT ;
    USE SIGNAL ;
    PORT
      LAYER M3 ;
        RECT  16.02 0 16.038 0.037 ;
    END
  END b_d[431]
  PIN b_d[432]
    DIRECTION OUTPUT ;
    USE SIGNAL ;
    PORT
      LAYER M3 ;
        RECT  16.092 0 16.11 0.037 ;
    END
  END b_d[432]
  PIN b_d[433]
    DIRECTION OUTPUT ;
    USE SIGNAL ;
    PORT
      LAYER M3 ;
        RECT  16.164 0 16.182 0.037 ;
    END
  END b_d[433]
  PIN b_d[434]
    DIRECTION OUTPUT ;
    USE SIGNAL ;
    PORT
      LAYER M3 ;
        RECT  16.236 0 16.254 0.037 ;
    END
  END b_d[434]
  PIN b_d[435]
    DIRECTION OUTPUT ;
    USE SIGNAL ;
    PORT
      LAYER M3 ;
        RECT  16.308 0 16.326 0.037 ;
    END
  END b_d[435]
  PIN b_d[436]
    DIRECTION OUTPUT ;
    USE SIGNAL ;
    PORT
      LAYER M3 ;
        RECT  16.38 0 16.398 0.037 ;
    END
  END b_d[436]
  PIN b_d[437]
    DIRECTION OUTPUT ;
    USE SIGNAL ;
    PORT
      LAYER M3 ;
        RECT  16.452 0 16.47 0.037 ;
    END
  END b_d[437]
  PIN b_d[438]
    DIRECTION OUTPUT ;
    USE SIGNAL ;
    PORT
      LAYER M3 ;
        RECT  16.524 0 16.542 0.037 ;
    END
  END b_d[438]
  PIN b_d[439]
    DIRECTION OUTPUT ;
    USE SIGNAL ;
    PORT
      LAYER M3 ;
        RECT  16.596 0 16.614 0.037 ;
    END
  END b_d[439]
  PIN b_d[43]
    DIRECTION OUTPUT ;
    USE SIGNAL ;
    PORT
      LAYER M5 ;
        RECT  33.264 0 33.288 0.084 ;
    END
  END b_d[43]
  PIN b_d[440]
    DIRECTION OUTPUT ;
    USE SIGNAL ;
    PORT
      LAYER M3 ;
        RECT  16.668 0 16.686 0.037 ;
    END
  END b_d[440]
  PIN b_d[441]
    DIRECTION OUTPUT ;
    USE SIGNAL ;
    PORT
      LAYER M3 ;
        RECT  16.74 0 16.758 0.037 ;
    END
  END b_d[441]
  PIN b_d[442]
    DIRECTION OUTPUT ;
    USE SIGNAL ;
    PORT
      LAYER M3 ;
        RECT  16.812 0 16.83 0.037 ;
    END
  END b_d[442]
  PIN b_d[443]
    DIRECTION OUTPUT ;
    USE SIGNAL ;
    PORT
      LAYER M3 ;
        RECT  16.884 0 16.902 0.037 ;
    END
  END b_d[443]
  PIN b_d[444]
    DIRECTION OUTPUT ;
    USE SIGNAL ;
    PORT
      LAYER M3 ;
        RECT  16.956 0 16.974 0.037 ;
    END
  END b_d[444]
  PIN b_d[445]
    DIRECTION OUTPUT ;
    USE SIGNAL ;
    PORT
      LAYER M3 ;
        RECT  17.028 0 17.046 0.037 ;
    END
  END b_d[445]
  PIN b_d[446]
    DIRECTION OUTPUT ;
    USE SIGNAL ;
    PORT
      LAYER M3 ;
        RECT  17.1 0 17.118 0.037 ;
    END
  END b_d[446]
  PIN b_d[447]
    DIRECTION OUTPUT ;
    USE SIGNAL ;
    PORT
      LAYER M3 ;
        RECT  17.172 0 17.19 0.037 ;
    END
  END b_d[447]
  PIN b_d[448]
    DIRECTION OUTPUT ;
    USE SIGNAL ;
    PORT
      LAYER M3 ;
        RECT  29.34 0 29.358 0.037 ;
    END
  END b_d[448]
  PIN b_d[449]
    DIRECTION OUTPUT ;
    USE SIGNAL ;
    PORT
      LAYER M3 ;
        RECT  29.412 0 29.43 0.037 ;
    END
  END b_d[449]
  PIN b_d[44]
    DIRECTION OUTPUT ;
    USE SIGNAL ;
    PORT
      LAYER M5 ;
        RECT  33.36 0 33.384 0.084 ;
    END
  END b_d[44]
  PIN b_d[450]
    DIRECTION OUTPUT ;
    USE SIGNAL ;
    PORT
      LAYER M3 ;
        RECT  29.484 0 29.502 0.037 ;
    END
  END b_d[450]
  PIN b_d[451]
    DIRECTION OUTPUT ;
    USE SIGNAL ;
    PORT
      LAYER M3 ;
        RECT  29.556 0 29.574 0.037 ;
    END
  END b_d[451]
  PIN b_d[452]
    DIRECTION OUTPUT ;
    USE SIGNAL ;
    PORT
      LAYER M3 ;
        RECT  29.628 0 29.646 0.037 ;
    END
  END b_d[452]
  PIN b_d[453]
    DIRECTION OUTPUT ;
    USE SIGNAL ;
    PORT
      LAYER M3 ;
        RECT  29.7 0 29.718 0.037 ;
    END
  END b_d[453]
  PIN b_d[454]
    DIRECTION OUTPUT ;
    USE SIGNAL ;
    PORT
      LAYER M3 ;
        RECT  29.772 0 29.79 0.037 ;
    END
  END b_d[454]
  PIN b_d[455]
    DIRECTION OUTPUT ;
    USE SIGNAL ;
    PORT
      LAYER M3 ;
        RECT  29.844 0 29.862 0.037 ;
    END
  END b_d[455]
  PIN b_d[456]
    DIRECTION OUTPUT ;
    USE SIGNAL ;
    PORT
      LAYER M3 ;
        RECT  29.916 0 29.934 0.037 ;
    END
  END b_d[456]
  PIN b_d[457]
    DIRECTION OUTPUT ;
    USE SIGNAL ;
    PORT
      LAYER M3 ;
        RECT  29.988 0 30.006 0.037 ;
    END
  END b_d[457]
  PIN b_d[458]
    DIRECTION OUTPUT ;
    USE SIGNAL ;
    PORT
      LAYER M3 ;
        RECT  30.06 0 30.078 0.037 ;
    END
  END b_d[458]
  PIN b_d[459]
    DIRECTION OUTPUT ;
    USE SIGNAL ;
    PORT
      LAYER M3 ;
        RECT  30.132 0 30.15 0.037 ;
    END
  END b_d[459]
  PIN b_d[45]
    DIRECTION OUTPUT ;
    USE SIGNAL ;
    PORT
      LAYER M5 ;
        RECT  33.456 0 33.48 0.084 ;
    END
  END b_d[45]
  PIN b_d[460]
    DIRECTION OUTPUT ;
    USE SIGNAL ;
    PORT
      LAYER M3 ;
        RECT  30.204 0 30.222 0.037 ;
    END
  END b_d[460]
  PIN b_d[461]
    DIRECTION OUTPUT ;
    USE SIGNAL ;
    PORT
      LAYER M3 ;
        RECT  30.276 0 30.294 0.037 ;
    END
  END b_d[461]
  PIN b_d[462]
    DIRECTION OUTPUT ;
    USE SIGNAL ;
    PORT
      LAYER M3 ;
        RECT  30.348 0 30.366 0.037 ;
    END
  END b_d[462]
  PIN b_d[463]
    DIRECTION OUTPUT ;
    USE SIGNAL ;
    PORT
      LAYER M3 ;
        RECT  30.42 0 30.438 0.037 ;
    END
  END b_d[463]
  PIN b_d[464]
    DIRECTION OUTPUT ;
    USE SIGNAL ;
    PORT
      LAYER M3 ;
        RECT  30.492 0 30.51 0.037 ;
    END
  END b_d[464]
  PIN b_d[465]
    DIRECTION OUTPUT ;
    USE SIGNAL ;
    PORT
      LAYER M3 ;
        RECT  30.564 0 30.582 0.037 ;
    END
  END b_d[465]
  PIN b_d[466]
    DIRECTION OUTPUT ;
    USE SIGNAL ;
    PORT
      LAYER M3 ;
        RECT  30.636 0 30.654 0.037 ;
    END
  END b_d[466]
  PIN b_d[467]
    DIRECTION OUTPUT ;
    USE SIGNAL ;
    PORT
      LAYER M3 ;
        RECT  30.708 0 30.726 0.037 ;
    END
  END b_d[467]
  PIN b_d[468]
    DIRECTION OUTPUT ;
    USE SIGNAL ;
    PORT
      LAYER M3 ;
        RECT  30.78 0 30.798 0.037 ;
    END
  END b_d[468]
  PIN b_d[469]
    DIRECTION OUTPUT ;
    USE SIGNAL ;
    PORT
      LAYER M3 ;
        RECT  30.852 0 30.87 0.037 ;
    END
  END b_d[469]
  PIN b_d[46]
    DIRECTION OUTPUT ;
    USE SIGNAL ;
    PORT
      LAYER M5 ;
        RECT  33.552 0 33.576 0.084 ;
    END
  END b_d[46]
  PIN b_d[470]
    DIRECTION OUTPUT ;
    USE SIGNAL ;
    PORT
      LAYER M3 ;
        RECT  30.924 0 30.942 0.037 ;
    END
  END b_d[470]
  PIN b_d[471]
    DIRECTION OUTPUT ;
    USE SIGNAL ;
    PORT
      LAYER M3 ;
        RECT  30.996 0 31.014 0.037 ;
    END
  END b_d[471]
  PIN b_d[472]
    DIRECTION OUTPUT ;
    USE SIGNAL ;
    PORT
      LAYER M3 ;
        RECT  31.068 0 31.086 0.037 ;
    END
  END b_d[472]
  PIN b_d[473]
    DIRECTION OUTPUT ;
    USE SIGNAL ;
    PORT
      LAYER M3 ;
        RECT  31.14 0 31.158 0.037 ;
    END
  END b_d[473]
  PIN b_d[474]
    DIRECTION OUTPUT ;
    USE SIGNAL ;
    PORT
      LAYER M3 ;
        RECT  31.212 0 31.23 0.037 ;
    END
  END b_d[474]
  PIN b_d[475]
    DIRECTION OUTPUT ;
    USE SIGNAL ;
    PORT
      LAYER M3 ;
        RECT  31.284 0 31.302 0.037 ;
    END
  END b_d[475]
  PIN b_d[476]
    DIRECTION OUTPUT ;
    USE SIGNAL ;
    PORT
      LAYER M3 ;
        RECT  31.356 0 31.374 0.037 ;
    END
  END b_d[476]
  PIN b_d[477]
    DIRECTION OUTPUT ;
    USE SIGNAL ;
    PORT
      LAYER M3 ;
        RECT  31.428 0 31.446 0.037 ;
    END
  END b_d[477]
  PIN b_d[478]
    DIRECTION OUTPUT ;
    USE SIGNAL ;
    PORT
      LAYER M3 ;
        RECT  31.5 0 31.518 0.037 ;
    END
  END b_d[478]
  PIN b_d[479]
    DIRECTION OUTPUT ;
    USE SIGNAL ;
    PORT
      LAYER M3 ;
        RECT  31.572 0 31.59 0.037 ;
    END
  END b_d[479]
  PIN b_d[47]
    DIRECTION OUTPUT ;
    USE SIGNAL ;
    PORT
      LAYER M5 ;
        RECT  33.648 0 33.672 0.084 ;
    END
  END b_d[47]
  PIN b_d[480]
    DIRECTION OUTPUT ;
    USE SIGNAL ;
    PORT
      LAYER M3 ;
        RECT  31.644 0 31.662 0.037 ;
    END
  END b_d[480]
  PIN b_d[481]
    DIRECTION OUTPUT ;
    USE SIGNAL ;
    PORT
      LAYER M3 ;
        RECT  31.716 0 31.734 0.037 ;
    END
  END b_d[481]
  PIN b_d[482]
    DIRECTION OUTPUT ;
    USE SIGNAL ;
    PORT
      LAYER M3 ;
        RECT  31.788 0 31.806 0.037 ;
    END
  END b_d[482]
  PIN b_d[483]
    DIRECTION OUTPUT ;
    USE SIGNAL ;
    PORT
      LAYER M3 ;
        RECT  31.86 0 31.878 0.037 ;
    END
  END b_d[483]
  PIN b_d[484]
    DIRECTION OUTPUT ;
    USE SIGNAL ;
    PORT
      LAYER M3 ;
        RECT  31.932 0 31.95 0.037 ;
    END
  END b_d[484]
  PIN b_d[485]
    DIRECTION OUTPUT ;
    USE SIGNAL ;
    PORT
      LAYER M3 ;
        RECT  32.004 0 32.022 0.037 ;
    END
  END b_d[485]
  PIN b_d[486]
    DIRECTION OUTPUT ;
    USE SIGNAL ;
    PORT
      LAYER M3 ;
        RECT  32.076 0 32.094 0.037 ;
    END
  END b_d[486]
  PIN b_d[487]
    DIRECTION OUTPUT ;
    USE SIGNAL ;
    PORT
      LAYER M3 ;
        RECT  32.148 0 32.166 0.037 ;
    END
  END b_d[487]
  PIN b_d[488]
    DIRECTION OUTPUT ;
    USE SIGNAL ;
    PORT
      LAYER M3 ;
        RECT  32.22 0 32.238 0.037 ;
    END
  END b_d[488]
  PIN b_d[489]
    DIRECTION OUTPUT ;
    USE SIGNAL ;
    PORT
      LAYER M3 ;
        RECT  32.292 0 32.31 0.037 ;
    END
  END b_d[489]
  PIN b_d[48]
    DIRECTION OUTPUT ;
    USE SIGNAL ;
    PORT
      LAYER M5 ;
        RECT  33.744 0 33.768 0.084 ;
    END
  END b_d[48]
  PIN b_d[490]
    DIRECTION OUTPUT ;
    USE SIGNAL ;
    PORT
      LAYER M3 ;
        RECT  32.364 0 32.382 0.037 ;
    END
  END b_d[490]
  PIN b_d[491]
    DIRECTION OUTPUT ;
    USE SIGNAL ;
    PORT
      LAYER M3 ;
        RECT  32.436 0 32.454 0.037 ;
    END
  END b_d[491]
  PIN b_d[492]
    DIRECTION OUTPUT ;
    USE SIGNAL ;
    PORT
      LAYER M3 ;
        RECT  32.508 0 32.526 0.037 ;
    END
  END b_d[492]
  PIN b_d[493]
    DIRECTION OUTPUT ;
    USE SIGNAL ;
    PORT
      LAYER M3 ;
        RECT  32.58 0 32.598 0.037 ;
    END
  END b_d[493]
  PIN b_d[494]
    DIRECTION OUTPUT ;
    USE SIGNAL ;
    PORT
      LAYER M3 ;
        RECT  32.652 0 32.67 0.037 ;
    END
  END b_d[494]
  PIN b_d[495]
    DIRECTION OUTPUT ;
    USE SIGNAL ;
    PORT
      LAYER M3 ;
        RECT  32.724 0 32.742 0.037 ;
    END
  END b_d[495]
  PIN b_d[496]
    DIRECTION OUTPUT ;
    USE SIGNAL ;
    PORT
      LAYER M3 ;
        RECT  32.796 0 32.814 0.037 ;
    END
  END b_d[496]
  PIN b_d[497]
    DIRECTION OUTPUT ;
    USE SIGNAL ;
    PORT
      LAYER M3 ;
        RECT  32.868 0 32.886 0.037 ;
    END
  END b_d[497]
  PIN b_d[498]
    DIRECTION OUTPUT ;
    USE SIGNAL ;
    PORT
      LAYER M3 ;
        RECT  32.94 0 32.958 0.037 ;
    END
  END b_d[498]
  PIN b_d[499]
    DIRECTION OUTPUT ;
    USE SIGNAL ;
    PORT
      LAYER M3 ;
        RECT  33.012 0 33.03 0.037 ;
    END
  END b_d[499]
  PIN b_d[49]
    DIRECTION OUTPUT ;
    USE SIGNAL ;
    PORT
      LAYER M5 ;
        RECT  33.84 0 33.864 0.084 ;
    END
  END b_d[49]
  PIN b_d[4]
    DIRECTION OUTPUT ;
    USE SIGNAL ;
    PORT
      LAYER M3 ;
        RECT  19.836 0 19.854 0.037 ;
    END
  END b_d[4]
  PIN b_d[500]
    DIRECTION OUTPUT ;
    USE SIGNAL ;
    PORT
      LAYER M3 ;
        RECT  33.084 0 33.102 0.037 ;
    END
  END b_d[500]
  PIN b_d[501]
    DIRECTION OUTPUT ;
    USE SIGNAL ;
    PORT
      LAYER M3 ;
        RECT  33.156 0 33.174 0.037 ;
    END
  END b_d[501]
  PIN b_d[502]
    DIRECTION OUTPUT ;
    USE SIGNAL ;
    PORT
      LAYER M3 ;
        RECT  33.228 0 33.246 0.037 ;
    END
  END b_d[502]
  PIN b_d[503]
    DIRECTION OUTPUT ;
    USE SIGNAL ;
    PORT
      LAYER M3 ;
        RECT  33.3 0 33.318 0.037 ;
    END
  END b_d[503]
  PIN b_d[504]
    DIRECTION OUTPUT ;
    USE SIGNAL ;
    PORT
      LAYER M3 ;
        RECT  33.372 0 33.39 0.037 ;
    END
  END b_d[504]
  PIN b_d[505]
    DIRECTION OUTPUT ;
    USE SIGNAL ;
    PORT
      LAYER M3 ;
        RECT  33.444 0 33.462 0.037 ;
    END
  END b_d[505]
  PIN b_d[506]
    DIRECTION OUTPUT ;
    USE SIGNAL ;
    PORT
      LAYER M3 ;
        RECT  33.516 0 33.534 0.037 ;
    END
  END b_d[506]
  PIN b_d[507]
    DIRECTION OUTPUT ;
    USE SIGNAL ;
    PORT
      LAYER M3 ;
        RECT  33.588 0 33.606 0.037 ;
    END
  END b_d[507]
  PIN b_d[50]
    DIRECTION OUTPUT ;
    USE SIGNAL ;
    PORT
      LAYER M5 ;
        RECT  33.936 0 33.96 0.084 ;
    END
  END b_d[50]
  PIN b_d[51]
    DIRECTION OUTPUT ;
    USE SIGNAL ;
    PORT
      LAYER M5 ;
        RECT  34.032 0 34.056 0.084 ;
    END
  END b_d[51]
  PIN b_d[52]
    DIRECTION OUTPUT ;
    USE SIGNAL ;
    PORT
      LAYER M5 ;
        RECT  34.128 0 34.152 0.084 ;
    END
  END b_d[52]
  PIN b_d[53]
    DIRECTION OUTPUT ;
    USE SIGNAL ;
    PORT
      LAYER M5 ;
        RECT  34.224 0 34.248 0.084 ;
    END
  END b_d[53]
  PIN b_d[54]
    DIRECTION OUTPUT ;
    USE SIGNAL ;
    PORT
      LAYER M5 ;
        RECT  34.32 0 34.344 0.084 ;
    END
  END b_d[54]
  PIN b_d[55]
    DIRECTION OUTPUT ;
    USE SIGNAL ;
    PORT
      LAYER M5 ;
        RECT  34.416 0 34.44 0.084 ;
    END
  END b_d[55]
  PIN b_d[56]
    DIRECTION OUTPUT ;
    USE SIGNAL ;
    PORT
      LAYER M5 ;
        RECT  34.512 0 34.536 0.084 ;
    END
  END b_d[56]
  PIN b_d[57]
    DIRECTION OUTPUT ;
    USE SIGNAL ;
    PORT
      LAYER M5 ;
        RECT  34.608 0 34.632 0.084 ;
    END
  END b_d[57]
  PIN b_d[58]
    DIRECTION OUTPUT ;
    USE SIGNAL ;
    PORT
      LAYER M5 ;
        RECT  34.704 0 34.728 0.084 ;
    END
  END b_d[58]
  PIN b_d[59]
    DIRECTION OUTPUT ;
    USE SIGNAL ;
    PORT
      LAYER M5 ;
        RECT  34.8 0 34.824 0.084 ;
    END
  END b_d[59]
  PIN b_d[5]
    DIRECTION OUTPUT ;
    USE SIGNAL ;
    PORT
      LAYER M3 ;
        RECT  19.908 0 19.926 0.037 ;
    END
  END b_d[5]
  PIN b_d[60]
    DIRECTION OUTPUT ;
    USE SIGNAL ;
    PORT
      LAYER M5 ;
        RECT  34.896 0 34.92 0.084 ;
    END
  END b_d[60]
  PIN b_d[61]
    DIRECTION OUTPUT ;
    USE SIGNAL ;
    PORT
      LAYER M5 ;
        RECT  34.992 0 35.016 0.084 ;
    END
  END b_d[61]
  PIN b_d[62]
    DIRECTION OUTPUT ;
    USE SIGNAL ;
    PORT
      LAYER M5 ;
        RECT  35.088 0 35.112 0.084 ;
    END
  END b_d[62]
  PIN b_d[63]
    DIRECTION OUTPUT ;
    USE SIGNAL ;
    PORT
      LAYER M5 ;
        RECT  35.184 0 35.208 0.084 ;
    END
  END b_d[63]
  PIN b_d[64]
    DIRECTION OUTPUT ;
    USE SIGNAL ;
    PORT
      LAYER M3 ;
        RECT  21.852 0 21.87 0.037 ;
    END
  END b_d[64]
  PIN b_d[65]
    DIRECTION OUTPUT ;
    USE SIGNAL ;
    PORT
      LAYER M3 ;
        RECT  21.924 0 21.942 0.037 ;
    END
  END b_d[65]
  PIN b_d[66]
    DIRECTION OUTPUT ;
    USE SIGNAL ;
    PORT
      LAYER M3 ;
        RECT  21.996 0 22.014 0.037 ;
    END
  END b_d[66]
  PIN b_d[67]
    DIRECTION OUTPUT ;
    USE SIGNAL ;
    PORT
      LAYER M3 ;
        RECT  22.068 0 22.086 0.037 ;
    END
  END b_d[67]
  PIN b_d[68]
    DIRECTION OUTPUT ;
    USE SIGNAL ;
    PORT
      LAYER M3 ;
        RECT  22.14 0 22.158 0.037 ;
    END
  END b_d[68]
  PIN b_d[69]
    DIRECTION OUTPUT ;
    USE SIGNAL ;
    PORT
      LAYER M3 ;
        RECT  22.212 0 22.23 0.037 ;
    END
  END b_d[69]
  PIN b_d[6]
    DIRECTION OUTPUT ;
    USE SIGNAL ;
    PORT
      LAYER M3 ;
        RECT  19.98 0 19.998 0.037 ;
    END
  END b_d[6]
  PIN b_d[70]
    DIRECTION OUTPUT ;
    USE SIGNAL ;
    PORT
      LAYER M3 ;
        RECT  22.284 0 22.302 0.037 ;
    END
  END b_d[70]
  PIN b_d[71]
    DIRECTION OUTPUT ;
    USE SIGNAL ;
    PORT
      LAYER M3 ;
        RECT  22.356 0 22.374 0.037 ;
    END
  END b_d[71]
  PIN b_d[72]
    DIRECTION OUTPUT ;
    USE SIGNAL ;
    PORT
      LAYER M3 ;
        RECT  22.428 0 22.446 0.037 ;
    END
  END b_d[72]
  PIN b_d[73]
    DIRECTION OUTPUT ;
    USE SIGNAL ;
    PORT
      LAYER M3 ;
        RECT  22.5 0 22.518 0.037 ;
    END
  END b_d[73]
  PIN b_d[74]
    DIRECTION OUTPUT ;
    USE SIGNAL ;
    PORT
      LAYER M3 ;
        RECT  22.572 0 22.59 0.037 ;
    END
  END b_d[74]
  PIN b_d[75]
    DIRECTION OUTPUT ;
    USE SIGNAL ;
    PORT
      LAYER M3 ;
        RECT  22.644 0 22.662 0.037 ;
    END
  END b_d[75]
  PIN b_d[76]
    DIRECTION OUTPUT ;
    USE SIGNAL ;
    PORT
      LAYER M3 ;
        RECT  22.716 0 22.734 0.037 ;
    END
  END b_d[76]
  PIN b_d[77]
    DIRECTION OUTPUT ;
    USE SIGNAL ;
    PORT
      LAYER M3 ;
        RECT  22.788 0 22.806 0.037 ;
    END
  END b_d[77]
  PIN b_d[78]
    DIRECTION OUTPUT ;
    USE SIGNAL ;
    PORT
      LAYER M3 ;
        RECT  22.86 0 22.878 0.037 ;
    END
  END b_d[78]
  PIN b_d[79]
    DIRECTION OUTPUT ;
    USE SIGNAL ;
    PORT
      LAYER M3 ;
        RECT  22.932 0 22.95 0.037 ;
    END
  END b_d[79]
  PIN b_d[7]
    DIRECTION OUTPUT ;
    USE SIGNAL ;
    PORT
      LAYER M3 ;
        RECT  20.052 0 20.07 0.037 ;
    END
  END b_d[7]
  PIN b_d[80]
    DIRECTION OUTPUT ;
    USE SIGNAL ;
    PORT
      LAYER M3 ;
        RECT  23.004 0 23.022 0.037 ;
    END
  END b_d[80]
  PIN b_d[81]
    DIRECTION OUTPUT ;
    USE SIGNAL ;
    PORT
      LAYER M3 ;
        RECT  23.076 0 23.094 0.037 ;
    END
  END b_d[81]
  PIN b_d[82]
    DIRECTION OUTPUT ;
    USE SIGNAL ;
    PORT
      LAYER M3 ;
        RECT  23.148 0 23.166 0.037 ;
    END
  END b_d[82]
  PIN b_d[83]
    DIRECTION OUTPUT ;
    USE SIGNAL ;
    PORT
      LAYER M3 ;
        RECT  23.22 0 23.238 0.037 ;
    END
  END b_d[83]
  PIN b_d[84]
    DIRECTION OUTPUT ;
    USE SIGNAL ;
    PORT
      LAYER M3 ;
        RECT  23.292 0 23.31 0.037 ;
    END
  END b_d[84]
  PIN b_d[85]
    DIRECTION OUTPUT ;
    USE SIGNAL ;
    PORT
      LAYER M3 ;
        RECT  23.364 0 23.382 0.037 ;
    END
  END b_d[85]
  PIN b_d[86]
    DIRECTION OUTPUT ;
    USE SIGNAL ;
    PORT
      LAYER M3 ;
        RECT  23.436 0 23.454 0.037 ;
    END
  END b_d[86]
  PIN b_d[87]
    DIRECTION OUTPUT ;
    USE SIGNAL ;
    PORT
      LAYER M3 ;
        RECT  23.508 0 23.526 0.037 ;
    END
  END b_d[87]
  PIN b_d[88]
    DIRECTION OUTPUT ;
    USE SIGNAL ;
    PORT
      LAYER M3 ;
        RECT  23.58 0 23.598 0.037 ;
    END
  END b_d[88]
  PIN b_d[89]
    DIRECTION OUTPUT ;
    USE SIGNAL ;
    PORT
      LAYER M3 ;
        RECT  23.652 0 23.67 0.037 ;
    END
  END b_d[89]
  PIN b_d[8]
    DIRECTION OUTPUT ;
    USE SIGNAL ;
    PORT
      LAYER M3 ;
        RECT  20.124 0 20.142 0.037 ;
    END
  END b_d[8]
  PIN b_d[90]
    DIRECTION OUTPUT ;
    USE SIGNAL ;
    PORT
      LAYER M3 ;
        RECT  23.724 0 23.742 0.037 ;
    END
  END b_d[90]
  PIN b_d[91]
    DIRECTION OUTPUT ;
    USE SIGNAL ;
    PORT
      LAYER M3 ;
        RECT  23.796 0 23.814 0.037 ;
    END
  END b_d[91]
  PIN b_d[92]
    DIRECTION OUTPUT ;
    USE SIGNAL ;
    PORT
      LAYER M3 ;
        RECT  23.868 0 23.886 0.037 ;
    END
  END b_d[92]
  PIN b_d[93]
    DIRECTION OUTPUT ;
    USE SIGNAL ;
    PORT
      LAYER M3 ;
        RECT  23.94 0 23.958 0.037 ;
    END
  END b_d[93]
  PIN b_d[94]
    DIRECTION OUTPUT ;
    USE SIGNAL ;
    PORT
      LAYER M3 ;
        RECT  24.012 0 24.03 0.037 ;
    END
  END b_d[94]
  PIN b_d[95]
    DIRECTION OUTPUT ;
    USE SIGNAL ;
    PORT
      LAYER M3 ;
        RECT  24.084 0 24.102 0.037 ;
    END
  END b_d[95]
  PIN b_d[96]
    DIRECTION OUTPUT ;
    USE SIGNAL ;
    PORT
      LAYER M5 ;
        RECT  19.92 0 19.944 0.084 ;
    END
  END b_d[96]
  PIN b_d[97]
    DIRECTION OUTPUT ;
    USE SIGNAL ;
    PORT
      LAYER M5 ;
        RECT  20.016 0 20.04 0.084 ;
    END
  END b_d[97]
  PIN b_d[98]
    DIRECTION OUTPUT ;
    USE SIGNAL ;
    PORT
      LAYER M5 ;
        RECT  20.112 0 20.136 0.084 ;
    END
  END b_d[98]
  PIN b_d[99]
    DIRECTION OUTPUT ;
    USE SIGNAL ;
    PORT
      LAYER M5 ;
        RECT  20.208 0 20.232 0.084 ;
    END
  END b_d[99]
  PIN b_d[9]
    DIRECTION OUTPUT ;
    USE SIGNAL ;
    PORT
      LAYER M3 ;
        RECT  20.196 0 20.214 0.037 ;
    END
  END b_d[9]
  PIN b_r
    DIRECTION INPUT ;
    USE SIGNAL ;
    PORT
      LAYER M3 ;
        RECT  33.66 0 33.678 0.037 ;
    END
  END b_r
  PIN c_d[0]
    DIRECTION OUTPUT ;
    USE SIGNAL ;
    PORT
      LAYER M4 ;
        RECT  0 52.272 0.084 52.296 ;
    END
  END c_d[0]
  PIN c_r
    DIRECTION INPUT ;
    USE SIGNAL ;
    PORT
      LAYER M4 ;
        RECT  0 52.368 0.084 52.392 ;
    END
  END c_r
  PIN clk
    DIRECTION INPUT ;
    USE SIGNAL ;
    PORT
      LAYER M4 ;
        RECT  0 52.464 0.084 52.488 ;
    END
  END clk
  PIN rst_n
    DIRECTION INPUT ;
    USE SIGNAL ;
    PORT
      LAYER M4 ;
        RECT  0 52.56 0.084 52.584 ;
    END
  END rst_n
  PIN t_d[0]
    DIRECTION OUTPUT ;
    USE SIGNAL ;
    PORT
      LAYER M4 ;
        RECT  0 52.656 0.084 52.68 ;
    END
  END t_d[0]
  PIN t_d[100]
    DIRECTION OUTPUT ;
    USE SIGNAL ;
    PORT
      LAYER M4 ;
        RECT  0 62.256 0.084 62.28 ;
    END
  END t_d[100]
  PIN t_d[101]
    DIRECTION OUTPUT ;
    USE SIGNAL ;
    PORT
      LAYER M4 ;
        RECT  0 62.352 0.084 62.376 ;
    END
  END t_d[101]
  PIN t_d[102]
    DIRECTION OUTPUT ;
    USE SIGNAL ;
    PORT
      LAYER M4 ;
        RECT  0 62.448 0.084 62.472 ;
    END
  END t_d[102]
  PIN t_d[103]
    DIRECTION OUTPUT ;
    USE SIGNAL ;
    PORT
      LAYER M4 ;
        RECT  0 62.544 0.084 62.568 ;
    END
  END t_d[103]
  PIN t_d[104]
    DIRECTION OUTPUT ;
    USE SIGNAL ;
    PORT
      LAYER M4 ;
        RECT  0 62.64 0.084 62.664 ;
    END
  END t_d[104]
  PIN t_d[105]
    DIRECTION OUTPUT ;
    USE SIGNAL ;
    PORT
      LAYER M4 ;
        RECT  0 62.736 0.084 62.76 ;
    END
  END t_d[105]
  PIN t_d[106]
    DIRECTION OUTPUT ;
    USE SIGNAL ;
    PORT
      LAYER M4 ;
        RECT  0 62.832 0.084 62.856 ;
    END
  END t_d[106]
  PIN t_d[107]
    DIRECTION OUTPUT ;
    USE SIGNAL ;
    PORT
      LAYER M4 ;
        RECT  0 62.928 0.084 62.952 ;
    END
  END t_d[107]
  PIN t_d[108]
    DIRECTION OUTPUT ;
    USE SIGNAL ;
    PORT
      LAYER M4 ;
        RECT  0 63.024 0.084 63.048 ;
    END
  END t_d[108]
  PIN t_d[109]
    DIRECTION OUTPUT ;
    USE SIGNAL ;
    PORT
      LAYER M4 ;
        RECT  0 63.12 0.084 63.144 ;
    END
  END t_d[109]
  PIN t_d[10]
    DIRECTION OUTPUT ;
    USE SIGNAL ;
    PORT
      LAYER M4 ;
        RECT  0 53.616 0.084 53.64 ;
    END
  END t_d[10]
  PIN t_d[110]
    DIRECTION OUTPUT ;
    USE SIGNAL ;
    PORT
      LAYER M4 ;
        RECT  0 63.216 0.084 63.24 ;
    END
  END t_d[110]
  PIN t_d[111]
    DIRECTION OUTPUT ;
    USE SIGNAL ;
    PORT
      LAYER M4 ;
        RECT  0 63.312 0.084 63.336 ;
    END
  END t_d[111]
  PIN t_d[112]
    DIRECTION OUTPUT ;
    USE SIGNAL ;
    PORT
      LAYER M4 ;
        RECT  0 63.408 0.084 63.432 ;
    END
  END t_d[112]
  PIN t_d[113]
    DIRECTION OUTPUT ;
    USE SIGNAL ;
    PORT
      LAYER M4 ;
        RECT  0 63.504 0.084 63.528 ;
    END
  END t_d[113]
  PIN t_d[114]
    DIRECTION OUTPUT ;
    USE SIGNAL ;
    PORT
      LAYER M4 ;
        RECT  0 63.6 0.084 63.624 ;
    END
  END t_d[114]
  PIN t_d[115]
    DIRECTION OUTPUT ;
    USE SIGNAL ;
    PORT
      LAYER M4 ;
        RECT  0 63.696 0.084 63.72 ;
    END
  END t_d[115]
  PIN t_d[116]
    DIRECTION OUTPUT ;
    USE SIGNAL ;
    PORT
      LAYER M4 ;
        RECT  0 63.792 0.084 63.816 ;
    END
  END t_d[116]
  PIN t_d[117]
    DIRECTION OUTPUT ;
    USE SIGNAL ;
    PORT
      LAYER M4 ;
        RECT  0 63.888 0.084 63.912 ;
    END
  END t_d[117]
  PIN t_d[118]
    DIRECTION OUTPUT ;
    USE SIGNAL ;
    PORT
      LAYER M4 ;
        RECT  0 63.984 0.084 64.008 ;
    END
  END t_d[118]
  PIN t_d[119]
    DIRECTION OUTPUT ;
    USE SIGNAL ;
    PORT
      LAYER M4 ;
        RECT  0 64.08 0.084 64.104 ;
    END
  END t_d[119]
  PIN t_d[11]
    DIRECTION OUTPUT ;
    USE SIGNAL ;
    PORT
      LAYER M4 ;
        RECT  0 53.712 0.084 53.736 ;
    END
  END t_d[11]
  PIN t_d[120]
    DIRECTION OUTPUT ;
    USE SIGNAL ;
    PORT
      LAYER M4 ;
        RECT  0 64.176 0.084 64.2 ;
    END
  END t_d[120]
  PIN t_d[121]
    DIRECTION OUTPUT ;
    USE SIGNAL ;
    PORT
      LAYER M4 ;
        RECT  0 64.272 0.084 64.296 ;
    END
  END t_d[121]
  PIN t_d[122]
    DIRECTION OUTPUT ;
    USE SIGNAL ;
    PORT
      LAYER M4 ;
        RECT  0 64.368 0.084 64.392 ;
    END
  END t_d[122]
  PIN t_d[123]
    DIRECTION OUTPUT ;
    USE SIGNAL ;
    PORT
      LAYER M4 ;
        RECT  0 64.464 0.084 64.488 ;
    END
  END t_d[123]
  PIN t_d[124]
    DIRECTION OUTPUT ;
    USE SIGNAL ;
    PORT
      LAYER M4 ;
        RECT  0 49.2 0.084 49.224 ;
    END
  END t_d[124]
  PIN t_d[125]
    DIRECTION OUTPUT ;
    USE SIGNAL ;
    PORT
      LAYER M4 ;
        RECT  0 49.296 0.084 49.32 ;
    END
  END t_d[125]
  PIN t_d[126]
    DIRECTION OUTPUT ;
    USE SIGNAL ;
    PORT
      LAYER M4 ;
        RECT  0 49.392 0.084 49.416 ;
    END
  END t_d[126]
  PIN t_d[127]
    DIRECTION OUTPUT ;
    USE SIGNAL ;
    PORT
      LAYER M4 ;
        RECT  0 49.488 0.084 49.512 ;
    END
  END t_d[127]
  PIN t_d[128]
    DIRECTION OUTPUT ;
    USE SIGNAL ;
    PORT
      LAYER M4 ;
        RECT  0 49.584 0.084 49.608 ;
    END
  END t_d[128]
  PIN t_d[129]
    DIRECTION OUTPUT ;
    USE SIGNAL ;
    PORT
      LAYER M4 ;
        RECT  0 49.68 0.084 49.704 ;
    END
  END t_d[129]
  PIN t_d[12]
    DIRECTION OUTPUT ;
    USE SIGNAL ;
    PORT
      LAYER M4 ;
        RECT  0 53.808 0.084 53.832 ;
    END
  END t_d[12]
  PIN t_d[130]
    DIRECTION OUTPUT ;
    USE SIGNAL ;
    PORT
      LAYER M4 ;
        RECT  0 49.776 0.084 49.8 ;
    END
  END t_d[130]
  PIN t_d[131]
    DIRECTION OUTPUT ;
    USE SIGNAL ;
    PORT
      LAYER M4 ;
        RECT  0 49.872 0.084 49.896 ;
    END
  END t_d[131]
  PIN t_d[132]
    DIRECTION OUTPUT ;
    USE SIGNAL ;
    PORT
      LAYER M4 ;
        RECT  0 49.968 0.084 49.992 ;
    END
  END t_d[132]
  PIN t_d[133]
    DIRECTION OUTPUT ;
    USE SIGNAL ;
    PORT
      LAYER M4 ;
        RECT  0 50.064 0.084 50.088 ;
    END
  END t_d[133]
  PIN t_d[134]
    DIRECTION OUTPUT ;
    USE SIGNAL ;
    PORT
      LAYER M4 ;
        RECT  0 50.16 0.084 50.184 ;
    END
  END t_d[134]
  PIN t_d[135]
    DIRECTION OUTPUT ;
    USE SIGNAL ;
    PORT
      LAYER M4 ;
        RECT  0 50.256 0.084 50.28 ;
    END
  END t_d[135]
  PIN t_d[136]
    DIRECTION OUTPUT ;
    USE SIGNAL ;
    PORT
      LAYER M4 ;
        RECT  0 50.352 0.084 50.376 ;
    END
  END t_d[136]
  PIN t_d[137]
    DIRECTION OUTPUT ;
    USE SIGNAL ;
    PORT
      LAYER M4 ;
        RECT  0 50.448 0.084 50.472 ;
    END
  END t_d[137]
  PIN t_d[138]
    DIRECTION OUTPUT ;
    USE SIGNAL ;
    PORT
      LAYER M4 ;
        RECT  0 50.544 0.084 50.568 ;
    END
  END t_d[138]
  PIN t_d[139]
    DIRECTION OUTPUT ;
    USE SIGNAL ;
    PORT
      LAYER M4 ;
        RECT  0 50.64 0.084 50.664 ;
    END
  END t_d[139]
  PIN t_d[13]
    DIRECTION OUTPUT ;
    USE SIGNAL ;
    PORT
      LAYER M4 ;
        RECT  0 53.904 0.084 53.928 ;
    END
  END t_d[13]
  PIN t_d[140]
    DIRECTION OUTPUT ;
    USE SIGNAL ;
    PORT
      LAYER M4 ;
        RECT  0 50.736 0.084 50.76 ;
    END
  END t_d[140]
  PIN t_d[141]
    DIRECTION OUTPUT ;
    USE SIGNAL ;
    PORT
      LAYER M4 ;
        RECT  0 50.832 0.084 50.856 ;
    END
  END t_d[141]
  PIN t_d[142]
    DIRECTION OUTPUT ;
    USE SIGNAL ;
    PORT
      LAYER M4 ;
        RECT  0 50.928 0.084 50.952 ;
    END
  END t_d[142]
  PIN t_d[143]
    DIRECTION OUTPUT ;
    USE SIGNAL ;
    PORT
      LAYER M4 ;
        RECT  0 51.024 0.084 51.048 ;
    END
  END t_d[143]
  PIN t_d[144]
    DIRECTION OUTPUT ;
    USE SIGNAL ;
    PORT
      LAYER M4 ;
        RECT  0 51.12 0.084 51.144 ;
    END
  END t_d[144]
  PIN t_d[145]
    DIRECTION OUTPUT ;
    USE SIGNAL ;
    PORT
      LAYER M4 ;
        RECT  0 51.216 0.084 51.24 ;
    END
  END t_d[145]
  PIN t_d[146]
    DIRECTION OUTPUT ;
    USE SIGNAL ;
    PORT
      LAYER M4 ;
        RECT  0 51.312 0.084 51.336 ;
    END
  END t_d[146]
  PIN t_d[147]
    DIRECTION OUTPUT ;
    USE SIGNAL ;
    PORT
      LAYER M4 ;
        RECT  0 51.408 0.084 51.432 ;
    END
  END t_d[147]
  PIN t_d[148]
    DIRECTION OUTPUT ;
    USE SIGNAL ;
    PORT
      LAYER M4 ;
        RECT  0 51.504 0.084 51.528 ;
    END
  END t_d[148]
  PIN t_d[149]
    DIRECTION OUTPUT ;
    USE SIGNAL ;
    PORT
      LAYER M4 ;
        RECT  0 51.6 0.084 51.624 ;
    END
  END t_d[149]
  PIN t_d[14]
    DIRECTION OUTPUT ;
    USE SIGNAL ;
    PORT
      LAYER M4 ;
        RECT  0 54 0.084 54.024 ;
    END
  END t_d[14]
  PIN t_d[150]
    DIRECTION OUTPUT ;
    USE SIGNAL ;
    PORT
      LAYER M4 ;
        RECT  0 51.696 0.084 51.72 ;
    END
  END t_d[150]
  PIN t_d[151]
    DIRECTION OUTPUT ;
    USE SIGNAL ;
    PORT
      LAYER M4 ;
        RECT  0 51.792 0.084 51.816 ;
    END
  END t_d[151]
  PIN t_d[152]
    DIRECTION OUTPUT ;
    USE SIGNAL ;
    PORT
      LAYER M4 ;
        RECT  0 51.888 0.084 51.912 ;
    END
  END t_d[152]
  PIN t_d[153]
    DIRECTION OUTPUT ;
    USE SIGNAL ;
    PORT
      LAYER M4 ;
        RECT  0 51.984 0.084 52.008 ;
    END
  END t_d[153]
  PIN t_d[154]
    DIRECTION OUTPUT ;
    USE SIGNAL ;
    PORT
      LAYER M4 ;
        RECT  0 52.08 0.084 52.104 ;
    END
  END t_d[154]
  PIN t_d[155]
    DIRECTION OUTPUT ;
    USE SIGNAL ;
    PORT
      LAYER M4 ;
        RECT  0 52.176 0.084 52.2 ;
    END
  END t_d[155]
  PIN t_d[156]
    DIRECTION OUTPUT ;
    USE SIGNAL ;
    PORT
      LAYER M4 ;
        RECT  0 55.344 0.084 55.368 ;
    END
  END t_d[156]
  PIN t_d[157]
    DIRECTION OUTPUT ;
    USE SIGNAL ;
    PORT
      LAYER M4 ;
        RECT  0 55.44 0.084 55.464 ;
    END
  END t_d[157]
  PIN t_d[158]
    DIRECTION OUTPUT ;
    USE SIGNAL ;
    PORT
      LAYER M4 ;
        RECT  0 55.536 0.084 55.56 ;
    END
  END t_d[158]
  PIN t_d[159]
    DIRECTION OUTPUT ;
    USE SIGNAL ;
    PORT
      LAYER M4 ;
        RECT  0 55.632 0.084 55.656 ;
    END
  END t_d[159]
  PIN t_d[15]
    DIRECTION OUTPUT ;
    USE SIGNAL ;
    PORT
      LAYER M4 ;
        RECT  0 54.096 0.084 54.12 ;
    END
  END t_d[15]
  PIN t_d[160]
    DIRECTION OUTPUT ;
    USE SIGNAL ;
    PORT
      LAYER M4 ;
        RECT  0 55.728 0.084 55.752 ;
    END
  END t_d[160]
  PIN t_d[161]
    DIRECTION OUTPUT ;
    USE SIGNAL ;
    PORT
      LAYER M4 ;
        RECT  0 55.824 0.084 55.848 ;
    END
  END t_d[161]
  PIN t_d[162]
    DIRECTION OUTPUT ;
    USE SIGNAL ;
    PORT
      LAYER M4 ;
        RECT  0 55.92 0.084 55.944 ;
    END
  END t_d[162]
  PIN t_d[163]
    DIRECTION OUTPUT ;
    USE SIGNAL ;
    PORT
      LAYER M4 ;
        RECT  0 56.016 0.084 56.04 ;
    END
  END t_d[163]
  PIN t_d[164]
    DIRECTION OUTPUT ;
    USE SIGNAL ;
    PORT
      LAYER M4 ;
        RECT  0 56.112 0.084 56.136 ;
    END
  END t_d[164]
  PIN t_d[165]
    DIRECTION OUTPUT ;
    USE SIGNAL ;
    PORT
      LAYER M4 ;
        RECT  0 56.208 0.084 56.232 ;
    END
  END t_d[165]
  PIN t_d[166]
    DIRECTION OUTPUT ;
    USE SIGNAL ;
    PORT
      LAYER M4 ;
        RECT  0 56.304 0.084 56.328 ;
    END
  END t_d[166]
  PIN t_d[167]
    DIRECTION OUTPUT ;
    USE SIGNAL ;
    PORT
      LAYER M4 ;
        RECT  0 56.4 0.084 56.424 ;
    END
  END t_d[167]
  PIN t_d[168]
    DIRECTION OUTPUT ;
    USE SIGNAL ;
    PORT
      LAYER M4 ;
        RECT  0 56.496 0.084 56.52 ;
    END
  END t_d[168]
  PIN t_d[169]
    DIRECTION OUTPUT ;
    USE SIGNAL ;
    PORT
      LAYER M4 ;
        RECT  0 56.592 0.084 56.616 ;
    END
  END t_d[169]
  PIN t_d[16]
    DIRECTION OUTPUT ;
    USE SIGNAL ;
    PORT
      LAYER M4 ;
        RECT  0 54.192 0.084 54.216 ;
    END
  END t_d[16]
  PIN t_d[170]
    DIRECTION OUTPUT ;
    USE SIGNAL ;
    PORT
      LAYER M4 ;
        RECT  0 56.688 0.084 56.712 ;
    END
  END t_d[170]
  PIN t_d[171]
    DIRECTION OUTPUT ;
    USE SIGNAL ;
    PORT
      LAYER M4 ;
        RECT  0 56.784 0.084 56.808 ;
    END
  END t_d[171]
  PIN t_d[172]
    DIRECTION OUTPUT ;
    USE SIGNAL ;
    PORT
      LAYER M4 ;
        RECT  0 56.88 0.084 56.904 ;
    END
  END t_d[172]
  PIN t_d[173]
    DIRECTION OUTPUT ;
    USE SIGNAL ;
    PORT
      LAYER M4 ;
        RECT  0 56.976 0.084 57 ;
    END
  END t_d[173]
  PIN t_d[174]
    DIRECTION OUTPUT ;
    USE SIGNAL ;
    PORT
      LAYER M4 ;
        RECT  0 57.072 0.084 57.096 ;
    END
  END t_d[174]
  PIN t_d[175]
    DIRECTION OUTPUT ;
    USE SIGNAL ;
    PORT
      LAYER M4 ;
        RECT  0 57.168 0.084 57.192 ;
    END
  END t_d[175]
  PIN t_d[176]
    DIRECTION OUTPUT ;
    USE SIGNAL ;
    PORT
      LAYER M4 ;
        RECT  0 57.264 0.084 57.288 ;
    END
  END t_d[176]
  PIN t_d[177]
    DIRECTION OUTPUT ;
    USE SIGNAL ;
    PORT
      LAYER M4 ;
        RECT  0 57.36 0.084 57.384 ;
    END
  END t_d[177]
  PIN t_d[178]
    DIRECTION OUTPUT ;
    USE SIGNAL ;
    PORT
      LAYER M4 ;
        RECT  0 57.456 0.084 57.48 ;
    END
  END t_d[178]
  PIN t_d[179]
    DIRECTION OUTPUT ;
    USE SIGNAL ;
    PORT
      LAYER M4 ;
        RECT  0 57.552 0.084 57.576 ;
    END
  END t_d[179]
  PIN t_d[17]
    DIRECTION OUTPUT ;
    USE SIGNAL ;
    PORT
      LAYER M4 ;
        RECT  0 54.288 0.084 54.312 ;
    END
  END t_d[17]
  PIN t_d[180]
    DIRECTION OUTPUT ;
    USE SIGNAL ;
    PORT
      LAYER M4 ;
        RECT  0 57.648 0.084 57.672 ;
    END
  END t_d[180]
  PIN t_d[181]
    DIRECTION OUTPUT ;
    USE SIGNAL ;
    PORT
      LAYER M4 ;
        RECT  0 57.744 0.084 57.768 ;
    END
  END t_d[181]
  PIN t_d[182]
    DIRECTION OUTPUT ;
    USE SIGNAL ;
    PORT
      LAYER M4 ;
        RECT  0 57.84 0.084 57.864 ;
    END
  END t_d[182]
  PIN t_d[183]
    DIRECTION OUTPUT ;
    USE SIGNAL ;
    PORT
      LAYER M4 ;
        RECT  0 57.936 0.084 57.96 ;
    END
  END t_d[183]
  PIN t_d[184]
    DIRECTION OUTPUT ;
    USE SIGNAL ;
    PORT
      LAYER M4 ;
        RECT  0 58.032 0.084 58.056 ;
    END
  END t_d[184]
  PIN t_d[185]
    DIRECTION OUTPUT ;
    USE SIGNAL ;
    PORT
      LAYER M4 ;
        RECT  0 58.128 0.084 58.152 ;
    END
  END t_d[185]
  PIN t_d[186]
    DIRECTION OUTPUT ;
    USE SIGNAL ;
    PORT
      LAYER M4 ;
        RECT  0 58.224 0.084 58.248 ;
    END
  END t_d[186]
  PIN t_d[187]
    DIRECTION OUTPUT ;
    USE SIGNAL ;
    PORT
      LAYER M4 ;
        RECT  0 58.32 0.084 58.344 ;
    END
  END t_d[187]
  PIN t_d[188]
    DIRECTION OUTPUT ;
    USE SIGNAL ;
    PORT
      LAYER M4 ;
        RECT  0 39.216 0.084 39.24 ;
    END
  END t_d[188]
  PIN t_d[189]
    DIRECTION OUTPUT ;
    USE SIGNAL ;
    PORT
      LAYER M4 ;
        RECT  0 39.312 0.084 39.336 ;
    END
  END t_d[189]
  PIN t_d[18]
    DIRECTION OUTPUT ;
    USE SIGNAL ;
    PORT
      LAYER M4 ;
        RECT  0 54.384 0.084 54.408 ;
    END
  END t_d[18]
  PIN t_d[190]
    DIRECTION OUTPUT ;
    USE SIGNAL ;
    PORT
      LAYER M4 ;
        RECT  0 39.408 0.084 39.432 ;
    END
  END t_d[190]
  PIN t_d[191]
    DIRECTION OUTPUT ;
    USE SIGNAL ;
    PORT
      LAYER M4 ;
        RECT  0 39.504 0.084 39.528 ;
    END
  END t_d[191]
  PIN t_d[192]
    DIRECTION OUTPUT ;
    USE SIGNAL ;
    PORT
      LAYER M4 ;
        RECT  0 39.6 0.084 39.624 ;
    END
  END t_d[192]
  PIN t_d[193]
    DIRECTION OUTPUT ;
    USE SIGNAL ;
    PORT
      LAYER M4 ;
        RECT  0 39.696 0.084 39.72 ;
    END
  END t_d[193]
  PIN t_d[194]
    DIRECTION OUTPUT ;
    USE SIGNAL ;
    PORT
      LAYER M4 ;
        RECT  0 39.792 0.084 39.816 ;
    END
  END t_d[194]
  PIN t_d[195]
    DIRECTION OUTPUT ;
    USE SIGNAL ;
    PORT
      LAYER M4 ;
        RECT  0 39.888 0.084 39.912 ;
    END
  END t_d[195]
  PIN t_d[196]
    DIRECTION OUTPUT ;
    USE SIGNAL ;
    PORT
      LAYER M4 ;
        RECT  0 39.984 0.084 40.008 ;
    END
  END t_d[196]
  PIN t_d[197]
    DIRECTION OUTPUT ;
    USE SIGNAL ;
    PORT
      LAYER M4 ;
        RECT  0 40.08 0.084 40.104 ;
    END
  END t_d[197]
  PIN t_d[198]
    DIRECTION OUTPUT ;
    USE SIGNAL ;
    PORT
      LAYER M4 ;
        RECT  0 40.176 0.084 40.2 ;
    END
  END t_d[198]
  PIN t_d[199]
    DIRECTION OUTPUT ;
    USE SIGNAL ;
    PORT
      LAYER M4 ;
        RECT  0 40.272 0.084 40.296 ;
    END
  END t_d[199]
  PIN t_d[19]
    DIRECTION OUTPUT ;
    USE SIGNAL ;
    PORT
      LAYER M4 ;
        RECT  0 54.48 0.084 54.504 ;
    END
  END t_d[19]
  PIN t_d[1]
    DIRECTION OUTPUT ;
    USE SIGNAL ;
    PORT
      LAYER M4 ;
        RECT  0 52.752 0.084 52.776 ;
    END
  END t_d[1]
  PIN t_d[200]
    DIRECTION OUTPUT ;
    USE SIGNAL ;
    PORT
      LAYER M4 ;
        RECT  0 40.368 0.084 40.392 ;
    END
  END t_d[200]
  PIN t_d[201]
    DIRECTION OUTPUT ;
    USE SIGNAL ;
    PORT
      LAYER M4 ;
        RECT  0 40.464 0.084 40.488 ;
    END
  END t_d[201]
  PIN t_d[202]
    DIRECTION OUTPUT ;
    USE SIGNAL ;
    PORT
      LAYER M4 ;
        RECT  0 40.56 0.084 40.584 ;
    END
  END t_d[202]
  PIN t_d[203]
    DIRECTION OUTPUT ;
    USE SIGNAL ;
    PORT
      LAYER M4 ;
        RECT  0 40.656 0.084 40.68 ;
    END
  END t_d[203]
  PIN t_d[204]
    DIRECTION OUTPUT ;
    USE SIGNAL ;
    PORT
      LAYER M4 ;
        RECT  0 40.752 0.084 40.776 ;
    END
  END t_d[204]
  PIN t_d[205]
    DIRECTION OUTPUT ;
    USE SIGNAL ;
    PORT
      LAYER M4 ;
        RECT  0 40.848 0.084 40.872 ;
    END
  END t_d[205]
  PIN t_d[206]
    DIRECTION OUTPUT ;
    USE SIGNAL ;
    PORT
      LAYER M4 ;
        RECT  0 40.944 0.084 40.968 ;
    END
  END t_d[206]
  PIN t_d[207]
    DIRECTION OUTPUT ;
    USE SIGNAL ;
    PORT
      LAYER M4 ;
        RECT  0 41.04 0.084 41.064 ;
    END
  END t_d[207]
  PIN t_d[208]
    DIRECTION OUTPUT ;
    USE SIGNAL ;
    PORT
      LAYER M4 ;
        RECT  0 41.136 0.084 41.16 ;
    END
  END t_d[208]
  PIN t_d[209]
    DIRECTION OUTPUT ;
    USE SIGNAL ;
    PORT
      LAYER M4 ;
        RECT  0 41.232 0.084 41.256 ;
    END
  END t_d[209]
  PIN t_d[20]
    DIRECTION OUTPUT ;
    USE SIGNAL ;
    PORT
      LAYER M4 ;
        RECT  0 54.576 0.084 54.6 ;
    END
  END t_d[20]
  PIN t_d[210]
    DIRECTION OUTPUT ;
    USE SIGNAL ;
    PORT
      LAYER M4 ;
        RECT  0 41.328 0.084 41.352 ;
    END
  END t_d[210]
  PIN t_d[211]
    DIRECTION OUTPUT ;
    USE SIGNAL ;
    PORT
      LAYER M4 ;
        RECT  0 41.424 0.084 41.448 ;
    END
  END t_d[211]
  PIN t_d[212]
    DIRECTION OUTPUT ;
    USE SIGNAL ;
    PORT
      LAYER M4 ;
        RECT  0 41.52 0.084 41.544 ;
    END
  END t_d[212]
  PIN t_d[213]
    DIRECTION OUTPUT ;
    USE SIGNAL ;
    PORT
      LAYER M4 ;
        RECT  0 41.616 0.084 41.64 ;
    END
  END t_d[213]
  PIN t_d[214]
    DIRECTION OUTPUT ;
    USE SIGNAL ;
    PORT
      LAYER M4 ;
        RECT  0 41.712 0.084 41.736 ;
    END
  END t_d[214]
  PIN t_d[215]
    DIRECTION OUTPUT ;
    USE SIGNAL ;
    PORT
      LAYER M4 ;
        RECT  0 41.808 0.084 41.832 ;
    END
  END t_d[215]
  PIN t_d[216]
    DIRECTION OUTPUT ;
    USE SIGNAL ;
    PORT
      LAYER M4 ;
        RECT  0 41.904 0.084 41.928 ;
    END
  END t_d[216]
  PIN t_d[217]
    DIRECTION OUTPUT ;
    USE SIGNAL ;
    PORT
      LAYER M4 ;
        RECT  0 42 0.084 42.024 ;
    END
  END t_d[217]
  PIN t_d[218]
    DIRECTION OUTPUT ;
    USE SIGNAL ;
    PORT
      LAYER M4 ;
        RECT  0 42.096 0.084 42.12 ;
    END
  END t_d[218]
  PIN t_d[219]
    DIRECTION OUTPUT ;
    USE SIGNAL ;
    PORT
      LAYER M4 ;
        RECT  0 42.192 0.084 42.216 ;
    END
  END t_d[219]
  PIN t_d[21]
    DIRECTION OUTPUT ;
    USE SIGNAL ;
    PORT
      LAYER M4 ;
        RECT  0 54.672 0.084 54.696 ;
    END
  END t_d[21]
  PIN t_d[220]
    DIRECTION OUTPUT ;
    USE SIGNAL ;
    PORT
      LAYER M4 ;
        RECT  0 30 0.084 30.024 ;
    END
  END t_d[220]
  PIN t_d[221]
    DIRECTION OUTPUT ;
    USE SIGNAL ;
    PORT
      LAYER M4 ;
        RECT  0 30.096 0.084 30.12 ;
    END
  END t_d[221]
  PIN t_d[222]
    DIRECTION OUTPUT ;
    USE SIGNAL ;
    PORT
      LAYER M4 ;
        RECT  0 30.192 0.084 30.216 ;
    END
  END t_d[222]
  PIN t_d[223]
    DIRECTION OUTPUT ;
    USE SIGNAL ;
    PORT
      LAYER M4 ;
        RECT  0 30.288 0.084 30.312 ;
    END
  END t_d[223]
  PIN t_d[224]
    DIRECTION OUTPUT ;
    USE SIGNAL ;
    PORT
      LAYER M4 ;
        RECT  0 30.384 0.084 30.408 ;
    END
  END t_d[224]
  PIN t_d[225]
    DIRECTION OUTPUT ;
    USE SIGNAL ;
    PORT
      LAYER M4 ;
        RECT  0 30.48 0.084 30.504 ;
    END
  END t_d[225]
  PIN t_d[226]
    DIRECTION OUTPUT ;
    USE SIGNAL ;
    PORT
      LAYER M4 ;
        RECT  0 30.576 0.084 30.6 ;
    END
  END t_d[226]
  PIN t_d[227]
    DIRECTION OUTPUT ;
    USE SIGNAL ;
    PORT
      LAYER M4 ;
        RECT  0 30.672 0.084 30.696 ;
    END
  END t_d[227]
  PIN t_d[228]
    DIRECTION OUTPUT ;
    USE SIGNAL ;
    PORT
      LAYER M4 ;
        RECT  0 30.768 0.084 30.792 ;
    END
  END t_d[228]
  PIN t_d[229]
    DIRECTION OUTPUT ;
    USE SIGNAL ;
    PORT
      LAYER M4 ;
        RECT  0 30.864 0.084 30.888 ;
    END
  END t_d[229]
  PIN t_d[22]
    DIRECTION OUTPUT ;
    USE SIGNAL ;
    PORT
      LAYER M4 ;
        RECT  0 54.768 0.084 54.792 ;
    END
  END t_d[22]
  PIN t_d[230]
    DIRECTION OUTPUT ;
    USE SIGNAL ;
    PORT
      LAYER M4 ;
        RECT  0 30.96 0.084 30.984 ;
    END
  END t_d[230]
  PIN t_d[231]
    DIRECTION OUTPUT ;
    USE SIGNAL ;
    PORT
      LAYER M4 ;
        RECT  0 31.056 0.084 31.08 ;
    END
  END t_d[231]
  PIN t_d[232]
    DIRECTION OUTPUT ;
    USE SIGNAL ;
    PORT
      LAYER M4 ;
        RECT  0 31.152 0.084 31.176 ;
    END
  END t_d[232]
  PIN t_d[233]
    DIRECTION OUTPUT ;
    USE SIGNAL ;
    PORT
      LAYER M4 ;
        RECT  0 31.248 0.084 31.272 ;
    END
  END t_d[233]
  PIN t_d[234]
    DIRECTION OUTPUT ;
    USE SIGNAL ;
    PORT
      LAYER M4 ;
        RECT  0 31.344 0.084 31.368 ;
    END
  END t_d[234]
  PIN t_d[235]
    DIRECTION OUTPUT ;
    USE SIGNAL ;
    PORT
      LAYER M4 ;
        RECT  0 31.44 0.084 31.464 ;
    END
  END t_d[235]
  PIN t_d[236]
    DIRECTION OUTPUT ;
    USE SIGNAL ;
    PORT
      LAYER M4 ;
        RECT  0 31.536 0.084 31.56 ;
    END
  END t_d[236]
  PIN t_d[237]
    DIRECTION OUTPUT ;
    USE SIGNAL ;
    PORT
      LAYER M4 ;
        RECT  0 31.632 0.084 31.656 ;
    END
  END t_d[237]
  PIN t_d[238]
    DIRECTION OUTPUT ;
    USE SIGNAL ;
    PORT
      LAYER M4 ;
        RECT  0 31.728 0.084 31.752 ;
    END
  END t_d[238]
  PIN t_d[239]
    DIRECTION OUTPUT ;
    USE SIGNAL ;
    PORT
      LAYER M4 ;
        RECT  0 31.824 0.084 31.848 ;
    END
  END t_d[239]
  PIN t_d[23]
    DIRECTION OUTPUT ;
    USE SIGNAL ;
    PORT
      LAYER M4 ;
        RECT  0 54.864 0.084 54.888 ;
    END
  END t_d[23]
  PIN t_d[240]
    DIRECTION OUTPUT ;
    USE SIGNAL ;
    PORT
      LAYER M4 ;
        RECT  0 31.92 0.084 31.944 ;
    END
  END t_d[240]
  PIN t_d[241]
    DIRECTION OUTPUT ;
    USE SIGNAL ;
    PORT
      LAYER M4 ;
        RECT  0 32.016 0.084 32.04 ;
    END
  END t_d[241]
  PIN t_d[242]
    DIRECTION OUTPUT ;
    USE SIGNAL ;
    PORT
      LAYER M4 ;
        RECT  0 32.112 0.084 32.136 ;
    END
  END t_d[242]
  PIN t_d[243]
    DIRECTION OUTPUT ;
    USE SIGNAL ;
    PORT
      LAYER M4 ;
        RECT  0 32.208 0.084 32.232 ;
    END
  END t_d[243]
  PIN t_d[244]
    DIRECTION OUTPUT ;
    USE SIGNAL ;
    PORT
      LAYER M4 ;
        RECT  0 32.304 0.084 32.328 ;
    END
  END t_d[244]
  PIN t_d[245]
    DIRECTION OUTPUT ;
    USE SIGNAL ;
    PORT
      LAYER M4 ;
        RECT  0 32.4 0.084 32.424 ;
    END
  END t_d[245]
  PIN t_d[246]
    DIRECTION OUTPUT ;
    USE SIGNAL ;
    PORT
      LAYER M4 ;
        RECT  0 32.496 0.084 32.52 ;
    END
  END t_d[246]
  PIN t_d[247]
    DIRECTION OUTPUT ;
    USE SIGNAL ;
    PORT
      LAYER M4 ;
        RECT  0 32.592 0.084 32.616 ;
    END
  END t_d[247]
  PIN t_d[248]
    DIRECTION OUTPUT ;
    USE SIGNAL ;
    PORT
      LAYER M4 ;
        RECT  0 32.688 0.084 32.712 ;
    END
  END t_d[248]
  PIN t_d[249]
    DIRECTION OUTPUT ;
    USE SIGNAL ;
    PORT
      LAYER M4 ;
        RECT  0 32.784 0.084 32.808 ;
    END
  END t_d[249]
  PIN t_d[24]
    DIRECTION OUTPUT ;
    USE SIGNAL ;
    PORT
      LAYER M4 ;
        RECT  0 54.96 0.084 54.984 ;
    END
  END t_d[24]
  PIN t_d[250]
    DIRECTION OUTPUT ;
    USE SIGNAL ;
    PORT
      LAYER M4 ;
        RECT  0 32.88 0.084 32.904 ;
    END
  END t_d[250]
  PIN t_d[251]
    DIRECTION OUTPUT ;
    USE SIGNAL ;
    PORT
      LAYER M4 ;
        RECT  0 32.976 0.084 33 ;
    END
  END t_d[251]
  PIN t_d[252]
    DIRECTION OUTPUT ;
    USE SIGNAL ;
    PORT
      LAYER M4 ;
        RECT  0 36.144 0.084 36.168 ;
    END
  END t_d[252]
  PIN t_d[253]
    DIRECTION OUTPUT ;
    USE SIGNAL ;
    PORT
      LAYER M4 ;
        RECT  0 36.24 0.084 36.264 ;
    END
  END t_d[253]
  PIN t_d[254]
    DIRECTION OUTPUT ;
    USE SIGNAL ;
    PORT
      LAYER M4 ;
        RECT  0 36.336 0.084 36.36 ;
    END
  END t_d[254]
  PIN t_d[255]
    DIRECTION OUTPUT ;
    USE SIGNAL ;
    PORT
      LAYER M4 ;
        RECT  0 36.432 0.084 36.456 ;
    END
  END t_d[255]
  PIN t_d[256]
    DIRECTION OUTPUT ;
    USE SIGNAL ;
    PORT
      LAYER M4 ;
        RECT  0 36.528 0.084 36.552 ;
    END
  END t_d[256]
  PIN t_d[257]
    DIRECTION OUTPUT ;
    USE SIGNAL ;
    PORT
      LAYER M4 ;
        RECT  0 36.624 0.084 36.648 ;
    END
  END t_d[257]
  PIN t_d[258]
    DIRECTION OUTPUT ;
    USE SIGNAL ;
    PORT
      LAYER M4 ;
        RECT  0 36.72 0.084 36.744 ;
    END
  END t_d[258]
  PIN t_d[259]
    DIRECTION OUTPUT ;
    USE SIGNAL ;
    PORT
      LAYER M4 ;
        RECT  0 36.816 0.084 36.84 ;
    END
  END t_d[259]
  PIN t_d[25]
    DIRECTION OUTPUT ;
    USE SIGNAL ;
    PORT
      LAYER M4 ;
        RECT  0 55.056 0.084 55.08 ;
    END
  END t_d[25]
  PIN t_d[260]
    DIRECTION OUTPUT ;
    USE SIGNAL ;
    PORT
      LAYER M4 ;
        RECT  0 36.912 0.084 36.936 ;
    END
  END t_d[260]
  PIN t_d[261]
    DIRECTION OUTPUT ;
    USE SIGNAL ;
    PORT
      LAYER M4 ;
        RECT  0 37.008 0.084 37.032 ;
    END
  END t_d[261]
  PIN t_d[262]
    DIRECTION OUTPUT ;
    USE SIGNAL ;
    PORT
      LAYER M4 ;
        RECT  0 37.104 0.084 37.128 ;
    END
  END t_d[262]
  PIN t_d[263]
    DIRECTION OUTPUT ;
    USE SIGNAL ;
    PORT
      LAYER M4 ;
        RECT  0 37.2 0.084 37.224 ;
    END
  END t_d[263]
  PIN t_d[264]
    DIRECTION OUTPUT ;
    USE SIGNAL ;
    PORT
      LAYER M4 ;
        RECT  0 37.296 0.084 37.32 ;
    END
  END t_d[264]
  PIN t_d[265]
    DIRECTION OUTPUT ;
    USE SIGNAL ;
    PORT
      LAYER M4 ;
        RECT  0 37.392 0.084 37.416 ;
    END
  END t_d[265]
  PIN t_d[266]
    DIRECTION OUTPUT ;
    USE SIGNAL ;
    PORT
      LAYER M4 ;
        RECT  0 37.488 0.084 37.512 ;
    END
  END t_d[266]
  PIN t_d[267]
    DIRECTION OUTPUT ;
    USE SIGNAL ;
    PORT
      LAYER M4 ;
        RECT  0 37.584 0.084 37.608 ;
    END
  END t_d[267]
  PIN t_d[268]
    DIRECTION OUTPUT ;
    USE SIGNAL ;
    PORT
      LAYER M4 ;
        RECT  0 37.68 0.084 37.704 ;
    END
  END t_d[268]
  PIN t_d[269]
    DIRECTION OUTPUT ;
    USE SIGNAL ;
    PORT
      LAYER M4 ;
        RECT  0 37.776 0.084 37.8 ;
    END
  END t_d[269]
  PIN t_d[26]
    DIRECTION OUTPUT ;
    USE SIGNAL ;
    PORT
      LAYER M4 ;
        RECT  0 55.152 0.084 55.176 ;
    END
  END t_d[26]
  PIN t_d[270]
    DIRECTION OUTPUT ;
    USE SIGNAL ;
    PORT
      LAYER M4 ;
        RECT  0 37.872 0.084 37.896 ;
    END
  END t_d[270]
  PIN t_d[271]
    DIRECTION OUTPUT ;
    USE SIGNAL ;
    PORT
      LAYER M4 ;
        RECT  0 37.968 0.084 37.992 ;
    END
  END t_d[271]
  PIN t_d[272]
    DIRECTION OUTPUT ;
    USE SIGNAL ;
    PORT
      LAYER M4 ;
        RECT  0 38.064 0.084 38.088 ;
    END
  END t_d[272]
  PIN t_d[273]
    DIRECTION OUTPUT ;
    USE SIGNAL ;
    PORT
      LAYER M4 ;
        RECT  0 38.16 0.084 38.184 ;
    END
  END t_d[273]
  PIN t_d[274]
    DIRECTION OUTPUT ;
    USE SIGNAL ;
    PORT
      LAYER M4 ;
        RECT  0 38.256 0.084 38.28 ;
    END
  END t_d[274]
  PIN t_d[275]
    DIRECTION OUTPUT ;
    USE SIGNAL ;
    PORT
      LAYER M4 ;
        RECT  0 38.352 0.084 38.376 ;
    END
  END t_d[275]
  PIN t_d[276]
    DIRECTION OUTPUT ;
    USE SIGNAL ;
    PORT
      LAYER M4 ;
        RECT  0 38.448 0.084 38.472 ;
    END
  END t_d[276]
  PIN t_d[277]
    DIRECTION OUTPUT ;
    USE SIGNAL ;
    PORT
      LAYER M4 ;
        RECT  0 38.544 0.084 38.568 ;
    END
  END t_d[277]
  PIN t_d[278]
    DIRECTION OUTPUT ;
    USE SIGNAL ;
    PORT
      LAYER M4 ;
        RECT  0 38.64 0.084 38.664 ;
    END
  END t_d[278]
  PIN t_d[279]
    DIRECTION OUTPUT ;
    USE SIGNAL ;
    PORT
      LAYER M4 ;
        RECT  0 38.736 0.084 38.76 ;
    END
  END t_d[279]
  PIN t_d[27]
    DIRECTION OUTPUT ;
    USE SIGNAL ;
    PORT
      LAYER M4 ;
        RECT  0 55.248 0.084 55.272 ;
    END
  END t_d[27]
  PIN t_d[280]
    DIRECTION OUTPUT ;
    USE SIGNAL ;
    PORT
      LAYER M4 ;
        RECT  0 38.832 0.084 38.856 ;
    END
  END t_d[280]
  PIN t_d[281]
    DIRECTION OUTPUT ;
    USE SIGNAL ;
    PORT
      LAYER M4 ;
        RECT  0 38.928 0.084 38.952 ;
    END
  END t_d[281]
  PIN t_d[282]
    DIRECTION OUTPUT ;
    USE SIGNAL ;
    PORT
      LAYER M4 ;
        RECT  0 39.024 0.084 39.048 ;
    END
  END t_d[282]
  PIN t_d[283]
    DIRECTION OUTPUT ;
    USE SIGNAL ;
    PORT
      LAYER M4 ;
        RECT  0 39.12 0.084 39.144 ;
    END
  END t_d[283]
  PIN t_d[284]
    DIRECTION OUTPUT ;
    USE SIGNAL ;
    PORT
      LAYER M4 ;
        RECT  0 42.288 0.084 42.312 ;
    END
  END t_d[284]
  PIN t_d[285]
    DIRECTION OUTPUT ;
    USE SIGNAL ;
    PORT
      LAYER M4 ;
        RECT  0 42.384 0.084 42.408 ;
    END
  END t_d[285]
  PIN t_d[286]
    DIRECTION OUTPUT ;
    USE SIGNAL ;
    PORT
      LAYER M4 ;
        RECT  0 42.48 0.084 42.504 ;
    END
  END t_d[286]
  PIN t_d[287]
    DIRECTION OUTPUT ;
    USE SIGNAL ;
    PORT
      LAYER M4 ;
        RECT  0 42.576 0.084 42.6 ;
    END
  END t_d[287]
  PIN t_d[288]
    DIRECTION OUTPUT ;
    USE SIGNAL ;
    PORT
      LAYER M4 ;
        RECT  0 42.672 0.084 42.696 ;
    END
  END t_d[288]
  PIN t_d[289]
    DIRECTION OUTPUT ;
    USE SIGNAL ;
    PORT
      LAYER M4 ;
        RECT  0 42.768 0.084 42.792 ;
    END
  END t_d[289]
  PIN t_d[28]
    DIRECTION OUTPUT ;
    USE SIGNAL ;
    PORT
      LAYER M4 ;
        RECT  0 58.416 0.084 58.44 ;
    END
  END t_d[28]
  PIN t_d[290]
    DIRECTION OUTPUT ;
    USE SIGNAL ;
    PORT
      LAYER M4 ;
        RECT  0 42.864 0.084 42.888 ;
    END
  END t_d[290]
  PIN t_d[291]
    DIRECTION OUTPUT ;
    USE SIGNAL ;
    PORT
      LAYER M4 ;
        RECT  0 42.96 0.084 42.984 ;
    END
  END t_d[291]
  PIN t_d[292]
    DIRECTION OUTPUT ;
    USE SIGNAL ;
    PORT
      LAYER M4 ;
        RECT  0 43.056 0.084 43.08 ;
    END
  END t_d[292]
  PIN t_d[293]
    DIRECTION OUTPUT ;
    USE SIGNAL ;
    PORT
      LAYER M4 ;
        RECT  0 43.152 0.084 43.176 ;
    END
  END t_d[293]
  PIN t_d[294]
    DIRECTION OUTPUT ;
    USE SIGNAL ;
    PORT
      LAYER M4 ;
        RECT  0 43.248 0.084 43.272 ;
    END
  END t_d[294]
  PIN t_d[295]
    DIRECTION OUTPUT ;
    USE SIGNAL ;
    PORT
      LAYER M4 ;
        RECT  0 43.344 0.084 43.368 ;
    END
  END t_d[295]
  PIN t_d[296]
    DIRECTION OUTPUT ;
    USE SIGNAL ;
    PORT
      LAYER M4 ;
        RECT  0 43.44 0.084 43.464 ;
    END
  END t_d[296]
  PIN t_d[297]
    DIRECTION OUTPUT ;
    USE SIGNAL ;
    PORT
      LAYER M4 ;
        RECT  0 43.536 0.084 43.56 ;
    END
  END t_d[297]
  PIN t_d[298]
    DIRECTION OUTPUT ;
    USE SIGNAL ;
    PORT
      LAYER M4 ;
        RECT  0 43.632 0.084 43.656 ;
    END
  END t_d[298]
  PIN t_d[299]
    DIRECTION OUTPUT ;
    USE SIGNAL ;
    PORT
      LAYER M4 ;
        RECT  0 43.728 0.084 43.752 ;
    END
  END t_d[299]
  PIN t_d[29]
    DIRECTION OUTPUT ;
    USE SIGNAL ;
    PORT
      LAYER M4 ;
        RECT  0 58.512 0.084 58.536 ;
    END
  END t_d[29]
  PIN t_d[2]
    DIRECTION OUTPUT ;
    USE SIGNAL ;
    PORT
      LAYER M4 ;
        RECT  0 52.848 0.084 52.872 ;
    END
  END t_d[2]
  PIN t_d[300]
    DIRECTION OUTPUT ;
    USE SIGNAL ;
    PORT
      LAYER M4 ;
        RECT  0 43.824 0.084 43.848 ;
    END
  END t_d[300]
  PIN t_d[301]
    DIRECTION OUTPUT ;
    USE SIGNAL ;
    PORT
      LAYER M4 ;
        RECT  0 43.92 0.084 43.944 ;
    END
  END t_d[301]
  PIN t_d[302]
    DIRECTION OUTPUT ;
    USE SIGNAL ;
    PORT
      LAYER M4 ;
        RECT  0 44.016 0.084 44.04 ;
    END
  END t_d[302]
  PIN t_d[303]
    DIRECTION OUTPUT ;
    USE SIGNAL ;
    PORT
      LAYER M4 ;
        RECT  0 44.112 0.084 44.136 ;
    END
  END t_d[303]
  PIN t_d[304]
    DIRECTION OUTPUT ;
    USE SIGNAL ;
    PORT
      LAYER M4 ;
        RECT  0 44.208 0.084 44.232 ;
    END
  END t_d[304]
  PIN t_d[305]
    DIRECTION OUTPUT ;
    USE SIGNAL ;
    PORT
      LAYER M4 ;
        RECT  0 44.304 0.084 44.328 ;
    END
  END t_d[305]
  PIN t_d[306]
    DIRECTION OUTPUT ;
    USE SIGNAL ;
    PORT
      LAYER M4 ;
        RECT  0 44.4 0.084 44.424 ;
    END
  END t_d[306]
  PIN t_d[307]
    DIRECTION OUTPUT ;
    USE SIGNAL ;
    PORT
      LAYER M4 ;
        RECT  0 44.496 0.084 44.52 ;
    END
  END t_d[307]
  PIN t_d[308]
    DIRECTION OUTPUT ;
    USE SIGNAL ;
    PORT
      LAYER M4 ;
        RECT  0 44.592 0.084 44.616 ;
    END
  END t_d[308]
  PIN t_d[309]
    DIRECTION OUTPUT ;
    USE SIGNAL ;
    PORT
      LAYER M4 ;
        RECT  0 44.688 0.084 44.712 ;
    END
  END t_d[309]
  PIN t_d[30]
    DIRECTION OUTPUT ;
    USE SIGNAL ;
    PORT
      LAYER M4 ;
        RECT  0 58.608 0.084 58.632 ;
    END
  END t_d[30]
  PIN t_d[310]
    DIRECTION OUTPUT ;
    USE SIGNAL ;
    PORT
      LAYER M4 ;
        RECT  0 44.784 0.084 44.808 ;
    END
  END t_d[310]
  PIN t_d[311]
    DIRECTION OUTPUT ;
    USE SIGNAL ;
    PORT
      LAYER M4 ;
        RECT  0 44.88 0.084 44.904 ;
    END
  END t_d[311]
  PIN t_d[312]
    DIRECTION OUTPUT ;
    USE SIGNAL ;
    PORT
      LAYER M4 ;
        RECT  0 44.976 0.084 45 ;
    END
  END t_d[312]
  PIN t_d[313]
    DIRECTION OUTPUT ;
    USE SIGNAL ;
    PORT
      LAYER M4 ;
        RECT  0 45.072 0.084 45.096 ;
    END
  END t_d[313]
  PIN t_d[314]
    DIRECTION OUTPUT ;
    USE SIGNAL ;
    PORT
      LAYER M4 ;
        RECT  0 45.168 0.084 45.192 ;
    END
  END t_d[314]
  PIN t_d[315]
    DIRECTION OUTPUT ;
    USE SIGNAL ;
    PORT
      LAYER M4 ;
        RECT  0 45.264 0.084 45.288 ;
    END
  END t_d[315]
  PIN t_d[316]
    DIRECTION OUTPUT ;
    USE SIGNAL ;
    PORT
      LAYER M4 ;
        RECT  0 33.072 0.084 33.096 ;
    END
  END t_d[316]
  PIN t_d[317]
    DIRECTION OUTPUT ;
    USE SIGNAL ;
    PORT
      LAYER M4 ;
        RECT  0 33.168 0.084 33.192 ;
    END
  END t_d[317]
  PIN t_d[318]
    DIRECTION OUTPUT ;
    USE SIGNAL ;
    PORT
      LAYER M4 ;
        RECT  0 33.264 0.084 33.288 ;
    END
  END t_d[318]
  PIN t_d[319]
    DIRECTION OUTPUT ;
    USE SIGNAL ;
    PORT
      LAYER M4 ;
        RECT  0 33.36 0.084 33.384 ;
    END
  END t_d[319]
  PIN t_d[31]
    DIRECTION OUTPUT ;
    USE SIGNAL ;
    PORT
      LAYER M4 ;
        RECT  0 58.704 0.084 58.728 ;
    END
  END t_d[31]
  PIN t_d[320]
    DIRECTION OUTPUT ;
    USE SIGNAL ;
    PORT
      LAYER M4 ;
        RECT  0 33.456 0.084 33.48 ;
    END
  END t_d[320]
  PIN t_d[321]
    DIRECTION OUTPUT ;
    USE SIGNAL ;
    PORT
      LAYER M4 ;
        RECT  0 33.552 0.084 33.576 ;
    END
  END t_d[321]
  PIN t_d[322]
    DIRECTION OUTPUT ;
    USE SIGNAL ;
    PORT
      LAYER M4 ;
        RECT  0 33.648 0.084 33.672 ;
    END
  END t_d[322]
  PIN t_d[323]
    DIRECTION OUTPUT ;
    USE SIGNAL ;
    PORT
      LAYER M4 ;
        RECT  0 33.744 0.084 33.768 ;
    END
  END t_d[323]
  PIN t_d[324]
    DIRECTION OUTPUT ;
    USE SIGNAL ;
    PORT
      LAYER M4 ;
        RECT  0 33.84 0.084 33.864 ;
    END
  END t_d[324]
  PIN t_d[325]
    DIRECTION OUTPUT ;
    USE SIGNAL ;
    PORT
      LAYER M4 ;
        RECT  0 33.936 0.084 33.96 ;
    END
  END t_d[325]
  PIN t_d[326]
    DIRECTION OUTPUT ;
    USE SIGNAL ;
    PORT
      LAYER M4 ;
        RECT  0 34.032 0.084 34.056 ;
    END
  END t_d[326]
  PIN t_d[327]
    DIRECTION OUTPUT ;
    USE SIGNAL ;
    PORT
      LAYER M4 ;
        RECT  0 34.128 0.084 34.152 ;
    END
  END t_d[327]
  PIN t_d[328]
    DIRECTION OUTPUT ;
    USE SIGNAL ;
    PORT
      LAYER M4 ;
        RECT  0 34.224 0.084 34.248 ;
    END
  END t_d[328]
  PIN t_d[329]
    DIRECTION OUTPUT ;
    USE SIGNAL ;
    PORT
      LAYER M4 ;
        RECT  0 34.32 0.084 34.344 ;
    END
  END t_d[329]
  PIN t_d[32]
    DIRECTION OUTPUT ;
    USE SIGNAL ;
    PORT
      LAYER M4 ;
        RECT  0 58.8 0.084 58.824 ;
    END
  END t_d[32]
  PIN t_d[330]
    DIRECTION OUTPUT ;
    USE SIGNAL ;
    PORT
      LAYER M4 ;
        RECT  0 34.416 0.084 34.44 ;
    END
  END t_d[330]
  PIN t_d[331]
    DIRECTION OUTPUT ;
    USE SIGNAL ;
    PORT
      LAYER M4 ;
        RECT  0 34.512 0.084 34.536 ;
    END
  END t_d[331]
  PIN t_d[332]
    DIRECTION OUTPUT ;
    USE SIGNAL ;
    PORT
      LAYER M4 ;
        RECT  0 34.608 0.084 34.632 ;
    END
  END t_d[332]
  PIN t_d[333]
    DIRECTION OUTPUT ;
    USE SIGNAL ;
    PORT
      LAYER M4 ;
        RECT  0 34.704 0.084 34.728 ;
    END
  END t_d[333]
  PIN t_d[334]
    DIRECTION OUTPUT ;
    USE SIGNAL ;
    PORT
      LAYER M4 ;
        RECT  0 34.8 0.084 34.824 ;
    END
  END t_d[334]
  PIN t_d[335]
    DIRECTION OUTPUT ;
    USE SIGNAL ;
    PORT
      LAYER M4 ;
        RECT  0 34.896 0.084 34.92 ;
    END
  END t_d[335]
  PIN t_d[336]
    DIRECTION OUTPUT ;
    USE SIGNAL ;
    PORT
      LAYER M4 ;
        RECT  0 34.992 0.084 35.016 ;
    END
  END t_d[336]
  PIN t_d[337]
    DIRECTION OUTPUT ;
    USE SIGNAL ;
    PORT
      LAYER M4 ;
        RECT  0 35.088 0.084 35.112 ;
    END
  END t_d[337]
  PIN t_d[338]
    DIRECTION OUTPUT ;
    USE SIGNAL ;
    PORT
      LAYER M4 ;
        RECT  0 35.184 0.084 35.208 ;
    END
  END t_d[338]
  PIN t_d[339]
    DIRECTION OUTPUT ;
    USE SIGNAL ;
    PORT
      LAYER M4 ;
        RECT  0 35.28 0.084 35.304 ;
    END
  END t_d[339]
  PIN t_d[33]
    DIRECTION OUTPUT ;
    USE SIGNAL ;
    PORT
      LAYER M4 ;
        RECT  0 58.896 0.084 58.92 ;
    END
  END t_d[33]
  PIN t_d[340]
    DIRECTION OUTPUT ;
    USE SIGNAL ;
    PORT
      LAYER M4 ;
        RECT  0 35.376 0.084 35.4 ;
    END
  END t_d[340]
  PIN t_d[341]
    DIRECTION OUTPUT ;
    USE SIGNAL ;
    PORT
      LAYER M4 ;
        RECT  0 35.472 0.084 35.496 ;
    END
  END t_d[341]
  PIN t_d[342]
    DIRECTION OUTPUT ;
    USE SIGNAL ;
    PORT
      LAYER M4 ;
        RECT  0 35.568 0.084 35.592 ;
    END
  END t_d[342]
  PIN t_d[343]
    DIRECTION OUTPUT ;
    USE SIGNAL ;
    PORT
      LAYER M4 ;
        RECT  0 35.664 0.084 35.688 ;
    END
  END t_d[343]
  PIN t_d[344]
    DIRECTION OUTPUT ;
    USE SIGNAL ;
    PORT
      LAYER M4 ;
        RECT  0 35.76 0.084 35.784 ;
    END
  END t_d[344]
  PIN t_d[345]
    DIRECTION OUTPUT ;
    USE SIGNAL ;
    PORT
      LAYER M4 ;
        RECT  0 35.856 0.084 35.88 ;
    END
  END t_d[345]
  PIN t_d[346]
    DIRECTION OUTPUT ;
    USE SIGNAL ;
    PORT
      LAYER M4 ;
        RECT  0 35.952 0.084 35.976 ;
    END
  END t_d[346]
  PIN t_d[347]
    DIRECTION OUTPUT ;
    USE SIGNAL ;
    PORT
      LAYER M4 ;
        RECT  0 36.048 0.084 36.072 ;
    END
  END t_d[347]
  PIN t_d[348]
    DIRECTION OUTPUT ;
    USE SIGNAL ;
    PORT
      LAYER M4 ;
        RECT  0 26.928 0.084 26.952 ;
    END
  END t_d[348]
  PIN t_d[349]
    DIRECTION OUTPUT ;
    USE SIGNAL ;
    PORT
      LAYER M4 ;
        RECT  0 27.024 0.084 27.048 ;
    END
  END t_d[349]
  PIN t_d[34]
    DIRECTION OUTPUT ;
    USE SIGNAL ;
    PORT
      LAYER M4 ;
        RECT  0 58.992 0.084 59.016 ;
    END
  END t_d[34]
  PIN t_d[350]
    DIRECTION OUTPUT ;
    USE SIGNAL ;
    PORT
      LAYER M4 ;
        RECT  0 27.12 0.084 27.144 ;
    END
  END t_d[350]
  PIN t_d[351]
    DIRECTION OUTPUT ;
    USE SIGNAL ;
    PORT
      LAYER M4 ;
        RECT  0 27.216 0.084 27.24 ;
    END
  END t_d[351]
  PIN t_d[352]
    DIRECTION OUTPUT ;
    USE SIGNAL ;
    PORT
      LAYER M4 ;
        RECT  0 27.312 0.084 27.336 ;
    END
  END t_d[352]
  PIN t_d[353]
    DIRECTION OUTPUT ;
    USE SIGNAL ;
    PORT
      LAYER M4 ;
        RECT  0 27.408 0.084 27.432 ;
    END
  END t_d[353]
  PIN t_d[354]
    DIRECTION OUTPUT ;
    USE SIGNAL ;
    PORT
      LAYER M4 ;
        RECT  0 27.504 0.084 27.528 ;
    END
  END t_d[354]
  PIN t_d[355]
    DIRECTION OUTPUT ;
    USE SIGNAL ;
    PORT
      LAYER M4 ;
        RECT  0 27.6 0.084 27.624 ;
    END
  END t_d[355]
  PIN t_d[356]
    DIRECTION OUTPUT ;
    USE SIGNAL ;
    PORT
      LAYER M4 ;
        RECT  0 27.696 0.084 27.72 ;
    END
  END t_d[356]
  PIN t_d[357]
    DIRECTION OUTPUT ;
    USE SIGNAL ;
    PORT
      LAYER M4 ;
        RECT  0 27.792 0.084 27.816 ;
    END
  END t_d[357]
  PIN t_d[358]
    DIRECTION OUTPUT ;
    USE SIGNAL ;
    PORT
      LAYER M4 ;
        RECT  0 27.888 0.084 27.912 ;
    END
  END t_d[358]
  PIN t_d[359]
    DIRECTION OUTPUT ;
    USE SIGNAL ;
    PORT
      LAYER M4 ;
        RECT  0 27.984 0.084 28.008 ;
    END
  END t_d[359]
  PIN t_d[35]
    DIRECTION OUTPUT ;
    USE SIGNAL ;
    PORT
      LAYER M4 ;
        RECT  0 59.088 0.084 59.112 ;
    END
  END t_d[35]
  PIN t_d[360]
    DIRECTION OUTPUT ;
    USE SIGNAL ;
    PORT
      LAYER M4 ;
        RECT  0 28.08 0.084 28.104 ;
    END
  END t_d[360]
  PIN t_d[361]
    DIRECTION OUTPUT ;
    USE SIGNAL ;
    PORT
      LAYER M4 ;
        RECT  0 28.176 0.084 28.2 ;
    END
  END t_d[361]
  PIN t_d[362]
    DIRECTION OUTPUT ;
    USE SIGNAL ;
    PORT
      LAYER M4 ;
        RECT  0 28.272 0.084 28.296 ;
    END
  END t_d[362]
  PIN t_d[363]
    DIRECTION OUTPUT ;
    USE SIGNAL ;
    PORT
      LAYER M4 ;
        RECT  0 28.368 0.084 28.392 ;
    END
  END t_d[363]
  PIN t_d[364]
    DIRECTION OUTPUT ;
    USE SIGNAL ;
    PORT
      LAYER M4 ;
        RECT  0 28.464 0.084 28.488 ;
    END
  END t_d[364]
  PIN t_d[365]
    DIRECTION OUTPUT ;
    USE SIGNAL ;
    PORT
      LAYER M4 ;
        RECT  0 28.56 0.084 28.584 ;
    END
  END t_d[365]
  PIN t_d[366]
    DIRECTION OUTPUT ;
    USE SIGNAL ;
    PORT
      LAYER M4 ;
        RECT  0 28.656 0.084 28.68 ;
    END
  END t_d[366]
  PIN t_d[367]
    DIRECTION OUTPUT ;
    USE SIGNAL ;
    PORT
      LAYER M4 ;
        RECT  0 28.752 0.084 28.776 ;
    END
  END t_d[367]
  PIN t_d[368]
    DIRECTION OUTPUT ;
    USE SIGNAL ;
    PORT
      LAYER M4 ;
        RECT  0 28.848 0.084 28.872 ;
    END
  END t_d[368]
  PIN t_d[369]
    DIRECTION OUTPUT ;
    USE SIGNAL ;
    PORT
      LAYER M4 ;
        RECT  0 28.944 0.084 28.968 ;
    END
  END t_d[369]
  PIN t_d[36]
    DIRECTION OUTPUT ;
    USE SIGNAL ;
    PORT
      LAYER M4 ;
        RECT  0 59.184 0.084 59.208 ;
    END
  END t_d[36]
  PIN t_d[370]
    DIRECTION OUTPUT ;
    USE SIGNAL ;
    PORT
      LAYER M4 ;
        RECT  0 29.04 0.084 29.064 ;
    END
  END t_d[370]
  PIN t_d[371]
    DIRECTION OUTPUT ;
    USE SIGNAL ;
    PORT
      LAYER M4 ;
        RECT  0 29.136 0.084 29.16 ;
    END
  END t_d[371]
  PIN t_d[372]
    DIRECTION OUTPUT ;
    USE SIGNAL ;
    PORT
      LAYER M4 ;
        RECT  0 29.232 0.084 29.256 ;
    END
  END t_d[372]
  PIN t_d[373]
    DIRECTION OUTPUT ;
    USE SIGNAL ;
    PORT
      LAYER M4 ;
        RECT  0 29.328 0.084 29.352 ;
    END
  END t_d[373]
  PIN t_d[374]
    DIRECTION OUTPUT ;
    USE SIGNAL ;
    PORT
      LAYER M4 ;
        RECT  0 29.424 0.084 29.448 ;
    END
  END t_d[374]
  PIN t_d[375]
    DIRECTION OUTPUT ;
    USE SIGNAL ;
    PORT
      LAYER M4 ;
        RECT  0 29.52 0.084 29.544 ;
    END
  END t_d[375]
  PIN t_d[376]
    DIRECTION OUTPUT ;
    USE SIGNAL ;
    PORT
      LAYER M4 ;
        RECT  0 29.616 0.084 29.64 ;
    END
  END t_d[376]
  PIN t_d[377]
    DIRECTION OUTPUT ;
    USE SIGNAL ;
    PORT
      LAYER M4 ;
        RECT  0 29.712 0.084 29.736 ;
    END
  END t_d[377]
  PIN t_d[378]
    DIRECTION OUTPUT ;
    USE SIGNAL ;
    PORT
      LAYER M4 ;
        RECT  0 29.808 0.084 29.832 ;
    END
  END t_d[378]
  PIN t_d[379]
    DIRECTION OUTPUT ;
    USE SIGNAL ;
    PORT
      LAYER M4 ;
        RECT  0 29.904 0.084 29.928 ;
    END
  END t_d[379]
  PIN t_d[37]
    DIRECTION OUTPUT ;
    USE SIGNAL ;
    PORT
      LAYER M4 ;
        RECT  0 59.28 0.084 59.304 ;
    END
  END t_d[37]
  PIN t_d[380]
    DIRECTION OUTPUT ;
    USE SIGNAL ;
    PORT
      LAYER M4 ;
        RECT  0 68.4 0.084 68.424 ;
    END
  END t_d[380]
  PIN t_d[381]
    DIRECTION OUTPUT ;
    USE SIGNAL ;
    PORT
      LAYER M4 ;
        RECT  0 68.496 0.084 68.52 ;
    END
  END t_d[381]
  PIN t_d[382]
    DIRECTION OUTPUT ;
    USE SIGNAL ;
    PORT
      LAYER M4 ;
        RECT  0 68.592 0.084 68.616 ;
    END
  END t_d[382]
  PIN t_d[383]
    DIRECTION OUTPUT ;
    USE SIGNAL ;
    PORT
      LAYER M4 ;
        RECT  0 68.688 0.084 68.712 ;
    END
  END t_d[383]
  PIN t_d[384]
    DIRECTION OUTPUT ;
    USE SIGNAL ;
    PORT
      LAYER M4 ;
        RECT  0 68.784 0.084 68.808 ;
    END
  END t_d[384]
  PIN t_d[385]
    DIRECTION OUTPUT ;
    USE SIGNAL ;
    PORT
      LAYER M4 ;
        RECT  0 68.88 0.084 68.904 ;
    END
  END t_d[385]
  PIN t_d[386]
    DIRECTION OUTPUT ;
    USE SIGNAL ;
    PORT
      LAYER M4 ;
        RECT  0 68.976 0.084 69 ;
    END
  END t_d[386]
  PIN t_d[387]
    DIRECTION OUTPUT ;
    USE SIGNAL ;
    PORT
      LAYER M4 ;
        RECT  0 69.072 0.084 69.096 ;
    END
  END t_d[387]
  PIN t_d[388]
    DIRECTION OUTPUT ;
    USE SIGNAL ;
    PORT
      LAYER M4 ;
        RECT  0 69.168 0.084 69.192 ;
    END
  END t_d[388]
  PIN t_d[389]
    DIRECTION OUTPUT ;
    USE SIGNAL ;
    PORT
      LAYER M4 ;
        RECT  0 69.264 0.084 69.288 ;
    END
  END t_d[389]
  PIN t_d[38]
    DIRECTION OUTPUT ;
    USE SIGNAL ;
    PORT
      LAYER M4 ;
        RECT  0 59.376 0.084 59.4 ;
    END
  END t_d[38]
  PIN t_d[390]
    DIRECTION OUTPUT ;
    USE SIGNAL ;
    PORT
      LAYER M4 ;
        RECT  0 69.36 0.084 69.384 ;
    END
  END t_d[390]
  PIN t_d[391]
    DIRECTION OUTPUT ;
    USE SIGNAL ;
    PORT
      LAYER M4 ;
        RECT  0 69.456 0.084 69.48 ;
    END
  END t_d[391]
  PIN t_d[392]
    DIRECTION OUTPUT ;
    USE SIGNAL ;
    PORT
      LAYER M4 ;
        RECT  0 69.552 0.084 69.576 ;
    END
  END t_d[392]
  PIN t_d[393]
    DIRECTION OUTPUT ;
    USE SIGNAL ;
    PORT
      LAYER M4 ;
        RECT  0 69.648 0.084 69.672 ;
    END
  END t_d[393]
  PIN t_d[394]
    DIRECTION OUTPUT ;
    USE SIGNAL ;
    PORT
      LAYER M4 ;
        RECT  0 69.744 0.084 69.768 ;
    END
  END t_d[394]
  PIN t_d[395]
    DIRECTION OUTPUT ;
    USE SIGNAL ;
    PORT
      LAYER M4 ;
        RECT  0 69.84 0.084 69.864 ;
    END
  END t_d[395]
  PIN t_d[396]
    DIRECTION OUTPUT ;
    USE SIGNAL ;
    PORT
      LAYER M4 ;
        RECT  0 69.936 0.084 69.96 ;
    END
  END t_d[396]
  PIN t_d[397]
    DIRECTION OUTPUT ;
    USE SIGNAL ;
    PORT
      LAYER M4 ;
        RECT  0 70.032 0.084 70.056 ;
    END
  END t_d[397]
  PIN t_d[398]
    DIRECTION OUTPUT ;
    USE SIGNAL ;
    PORT
      LAYER M4 ;
        RECT  0 70.128 0.084 70.152 ;
    END
  END t_d[398]
  PIN t_d[399]
    DIRECTION OUTPUT ;
    USE SIGNAL ;
    PORT
      LAYER M4 ;
        RECT  0 70.224 0.084 70.248 ;
    END
  END t_d[399]
  PIN t_d[39]
    DIRECTION OUTPUT ;
    USE SIGNAL ;
    PORT
      LAYER M4 ;
        RECT  0 59.472 0.084 59.496 ;
    END
  END t_d[39]
  PIN t_d[3]
    DIRECTION OUTPUT ;
    USE SIGNAL ;
    PORT
      LAYER M4 ;
        RECT  0 52.944 0.084 52.968 ;
    END
  END t_d[3]
  PIN t_d[400]
    DIRECTION OUTPUT ;
    USE SIGNAL ;
    PORT
      LAYER M4 ;
        RECT  0 70.32 0.084 70.344 ;
    END
  END t_d[400]
  PIN t_d[401]
    DIRECTION OUTPUT ;
    USE SIGNAL ;
    PORT
      LAYER M4 ;
        RECT  0 70.416 0.084 70.44 ;
    END
  END t_d[401]
  PIN t_d[402]
    DIRECTION OUTPUT ;
    USE SIGNAL ;
    PORT
      LAYER M4 ;
        RECT  0 70.512 0.084 70.536 ;
    END
  END t_d[402]
  PIN t_d[403]
    DIRECTION OUTPUT ;
    USE SIGNAL ;
    PORT
      LAYER M4 ;
        RECT  0 70.608 0.084 70.632 ;
    END
  END t_d[403]
  PIN t_d[404]
    DIRECTION OUTPUT ;
    USE SIGNAL ;
    PORT
      LAYER M4 ;
        RECT  0 70.704 0.084 70.728 ;
    END
  END t_d[404]
  PIN t_d[405]
    DIRECTION OUTPUT ;
    USE SIGNAL ;
    PORT
      LAYER M4 ;
        RECT  0 70.8 0.084 70.824 ;
    END
  END t_d[405]
  PIN t_d[406]
    DIRECTION OUTPUT ;
    USE SIGNAL ;
    PORT
      LAYER M4 ;
        RECT  0 70.896 0.084 70.92 ;
    END
  END t_d[406]
  PIN t_d[407]
    DIRECTION OUTPUT ;
    USE SIGNAL ;
    PORT
      LAYER M4 ;
        RECT  0 70.992 0.084 71.016 ;
    END
  END t_d[407]
  PIN t_d[408]
    DIRECTION OUTPUT ;
    USE SIGNAL ;
    PORT
      LAYER M4 ;
        RECT  0 71.088 0.084 71.112 ;
    END
  END t_d[408]
  PIN t_d[409]
    DIRECTION OUTPUT ;
    USE SIGNAL ;
    PORT
      LAYER M4 ;
        RECT  0 71.184 0.084 71.208 ;
    END
  END t_d[409]
  PIN t_d[40]
    DIRECTION OUTPUT ;
    USE SIGNAL ;
    PORT
      LAYER M4 ;
        RECT  0 59.568 0.084 59.592 ;
    END
  END t_d[40]
  PIN t_d[410]
    DIRECTION OUTPUT ;
    USE SIGNAL ;
    PORT
      LAYER M4 ;
        RECT  0 71.28 0.084 71.304 ;
    END
  END t_d[410]
  PIN t_d[411]
    DIRECTION OUTPUT ;
    USE SIGNAL ;
    PORT
      LAYER M4 ;
        RECT  0 71.376 0.084 71.4 ;
    END
  END t_d[411]
  PIN t_d[412]
    DIRECTION OUTPUT ;
    USE SIGNAL ;
    PORT
      LAYER M4 ;
        RECT  0 74.544 0.084 74.568 ;
    END
  END t_d[412]
  PIN t_d[413]
    DIRECTION OUTPUT ;
    USE SIGNAL ;
    PORT
      LAYER M4 ;
        RECT  0 74.64 0.084 74.664 ;
    END
  END t_d[413]
  PIN t_d[414]
    DIRECTION OUTPUT ;
    USE SIGNAL ;
    PORT
      LAYER M4 ;
        RECT  0 74.736 0.084 74.76 ;
    END
  END t_d[414]
  PIN t_d[415]
    DIRECTION OUTPUT ;
    USE SIGNAL ;
    PORT
      LAYER M4 ;
        RECT  0 74.832 0.084 74.856 ;
    END
  END t_d[415]
  PIN t_d[416]
    DIRECTION OUTPUT ;
    USE SIGNAL ;
    PORT
      LAYER M4 ;
        RECT  0 74.928 0.084 74.952 ;
    END
  END t_d[416]
  PIN t_d[417]
    DIRECTION OUTPUT ;
    USE SIGNAL ;
    PORT
      LAYER M4 ;
        RECT  0 75.024 0.084 75.048 ;
    END
  END t_d[417]
  PIN t_d[418]
    DIRECTION OUTPUT ;
    USE SIGNAL ;
    PORT
      LAYER M4 ;
        RECT  0 75.12 0.084 75.144 ;
    END
  END t_d[418]
  PIN t_d[419]
    DIRECTION OUTPUT ;
    USE SIGNAL ;
    PORT
      LAYER M4 ;
        RECT  0 75.216 0.084 75.24 ;
    END
  END t_d[419]
  PIN t_d[41]
    DIRECTION OUTPUT ;
    USE SIGNAL ;
    PORT
      LAYER M4 ;
        RECT  0 59.664 0.084 59.688 ;
    END
  END t_d[41]
  PIN t_d[420]
    DIRECTION OUTPUT ;
    USE SIGNAL ;
    PORT
      LAYER M4 ;
        RECT  0 75.312 0.084 75.336 ;
    END
  END t_d[420]
  PIN t_d[421]
    DIRECTION OUTPUT ;
    USE SIGNAL ;
    PORT
      LAYER M4 ;
        RECT  0 75.408 0.084 75.432 ;
    END
  END t_d[421]
  PIN t_d[422]
    DIRECTION OUTPUT ;
    USE SIGNAL ;
    PORT
      LAYER M4 ;
        RECT  0 75.504 0.084 75.528 ;
    END
  END t_d[422]
  PIN t_d[423]
    DIRECTION OUTPUT ;
    USE SIGNAL ;
    PORT
      LAYER M4 ;
        RECT  0 75.6 0.084 75.624 ;
    END
  END t_d[423]
  PIN t_d[424]
    DIRECTION OUTPUT ;
    USE SIGNAL ;
    PORT
      LAYER M4 ;
        RECT  0 75.696 0.084 75.72 ;
    END
  END t_d[424]
  PIN t_d[425]
    DIRECTION OUTPUT ;
    USE SIGNAL ;
    PORT
      LAYER M4 ;
        RECT  0 75.792 0.084 75.816 ;
    END
  END t_d[425]
  PIN t_d[426]
    DIRECTION OUTPUT ;
    USE SIGNAL ;
    PORT
      LAYER M4 ;
        RECT  0 75.888 0.084 75.912 ;
    END
  END t_d[426]
  PIN t_d[427]
    DIRECTION OUTPUT ;
    USE SIGNAL ;
    PORT
      LAYER M4 ;
        RECT  0 75.984 0.084 76.008 ;
    END
  END t_d[427]
  PIN t_d[428]
    DIRECTION OUTPUT ;
    USE SIGNAL ;
    PORT
      LAYER M4 ;
        RECT  0 76.08 0.084 76.104 ;
    END
  END t_d[428]
  PIN t_d[429]
    DIRECTION OUTPUT ;
    USE SIGNAL ;
    PORT
      LAYER M4 ;
        RECT  0 76.176 0.084 76.2 ;
    END
  END t_d[429]
  PIN t_d[42]
    DIRECTION OUTPUT ;
    USE SIGNAL ;
    PORT
      LAYER M4 ;
        RECT  0 59.76 0.084 59.784 ;
    END
  END t_d[42]
  PIN t_d[430]
    DIRECTION OUTPUT ;
    USE SIGNAL ;
    PORT
      LAYER M4 ;
        RECT  0 76.272 0.084 76.296 ;
    END
  END t_d[430]
  PIN t_d[431]
    DIRECTION OUTPUT ;
    USE SIGNAL ;
    PORT
      LAYER M4 ;
        RECT  0 76.368 0.084 76.392 ;
    END
  END t_d[431]
  PIN t_d[432]
    DIRECTION OUTPUT ;
    USE SIGNAL ;
    PORT
      LAYER M4 ;
        RECT  0 76.464 0.084 76.488 ;
    END
  END t_d[432]
  PIN t_d[433]
    DIRECTION OUTPUT ;
    USE SIGNAL ;
    PORT
      LAYER M4 ;
        RECT  0 76.56 0.084 76.584 ;
    END
  END t_d[433]
  PIN t_d[434]
    DIRECTION OUTPUT ;
    USE SIGNAL ;
    PORT
      LAYER M4 ;
        RECT  0 76.656 0.084 76.68 ;
    END
  END t_d[434]
  PIN t_d[435]
    DIRECTION OUTPUT ;
    USE SIGNAL ;
    PORT
      LAYER M4 ;
        RECT  0 76.752 0.084 76.776 ;
    END
  END t_d[435]
  PIN t_d[436]
    DIRECTION OUTPUT ;
    USE SIGNAL ;
    PORT
      LAYER M4 ;
        RECT  0 76.848 0.084 76.872 ;
    END
  END t_d[436]
  PIN t_d[437]
    DIRECTION OUTPUT ;
    USE SIGNAL ;
    PORT
      LAYER M4 ;
        RECT  0 76.944 0.084 76.968 ;
    END
  END t_d[437]
  PIN t_d[438]
    DIRECTION OUTPUT ;
    USE SIGNAL ;
    PORT
      LAYER M4 ;
        RECT  0 77.04 0.084 77.064 ;
    END
  END t_d[438]
  PIN t_d[439]
    DIRECTION OUTPUT ;
    USE SIGNAL ;
    PORT
      LAYER M4 ;
        RECT  0 77.136 0.084 77.16 ;
    END
  END t_d[439]
  PIN t_d[43]
    DIRECTION OUTPUT ;
    USE SIGNAL ;
    PORT
      LAYER M4 ;
        RECT  0 59.856 0.084 59.88 ;
    END
  END t_d[43]
  PIN t_d[440]
    DIRECTION OUTPUT ;
    USE SIGNAL ;
    PORT
      LAYER M4 ;
        RECT  0 77.232 0.084 77.256 ;
    END
  END t_d[440]
  PIN t_d[441]
    DIRECTION OUTPUT ;
    USE SIGNAL ;
    PORT
      LAYER M4 ;
        RECT  0 77.328 0.084 77.352 ;
    END
  END t_d[441]
  PIN t_d[442]
    DIRECTION OUTPUT ;
    USE SIGNAL ;
    PORT
      LAYER M4 ;
        RECT  0 77.424 0.084 77.448 ;
    END
  END t_d[442]
  PIN t_d[443]
    DIRECTION OUTPUT ;
    USE SIGNAL ;
    PORT
      LAYER M4 ;
        RECT  0 77.52 0.084 77.544 ;
    END
  END t_d[443]
  PIN t_d[444]
    DIRECTION OUTPUT ;
    USE SIGNAL ;
    PORT
      LAYER M4 ;
        RECT  0 71.472 0.084 71.496 ;
    END
  END t_d[444]
  PIN t_d[445]
    DIRECTION OUTPUT ;
    USE SIGNAL ;
    PORT
      LAYER M4 ;
        RECT  0 71.568 0.084 71.592 ;
    END
  END t_d[445]
  PIN t_d[446]
    DIRECTION OUTPUT ;
    USE SIGNAL ;
    PORT
      LAYER M4 ;
        RECT  0 71.664 0.084 71.688 ;
    END
  END t_d[446]
  PIN t_d[447]
    DIRECTION OUTPUT ;
    USE SIGNAL ;
    PORT
      LAYER M4 ;
        RECT  0 71.76 0.084 71.784 ;
    END
  END t_d[447]
  PIN t_d[448]
    DIRECTION OUTPUT ;
    USE SIGNAL ;
    PORT
      LAYER M4 ;
        RECT  0 71.856 0.084 71.88 ;
    END
  END t_d[448]
  PIN t_d[449]
    DIRECTION OUTPUT ;
    USE SIGNAL ;
    PORT
      LAYER M4 ;
        RECT  0 71.952 0.084 71.976 ;
    END
  END t_d[449]
  PIN t_d[44]
    DIRECTION OUTPUT ;
    USE SIGNAL ;
    PORT
      LAYER M4 ;
        RECT  0 59.952 0.084 59.976 ;
    END
  END t_d[44]
  PIN t_d[450]
    DIRECTION OUTPUT ;
    USE SIGNAL ;
    PORT
      LAYER M4 ;
        RECT  0 72.048 0.084 72.072 ;
    END
  END t_d[450]
  PIN t_d[451]
    DIRECTION OUTPUT ;
    USE SIGNAL ;
    PORT
      LAYER M4 ;
        RECT  0 72.144 0.084 72.168 ;
    END
  END t_d[451]
  PIN t_d[452]
    DIRECTION OUTPUT ;
    USE SIGNAL ;
    PORT
      LAYER M4 ;
        RECT  0 72.24 0.084 72.264 ;
    END
  END t_d[452]
  PIN t_d[453]
    DIRECTION OUTPUT ;
    USE SIGNAL ;
    PORT
      LAYER M4 ;
        RECT  0 72.336 0.084 72.36 ;
    END
  END t_d[453]
  PIN t_d[454]
    DIRECTION OUTPUT ;
    USE SIGNAL ;
    PORT
      LAYER M4 ;
        RECT  0 72.432 0.084 72.456 ;
    END
  END t_d[454]
  PIN t_d[455]
    DIRECTION OUTPUT ;
    USE SIGNAL ;
    PORT
      LAYER M4 ;
        RECT  0 72.528 0.084 72.552 ;
    END
  END t_d[455]
  PIN t_d[456]
    DIRECTION OUTPUT ;
    USE SIGNAL ;
    PORT
      LAYER M4 ;
        RECT  0 72.624 0.084 72.648 ;
    END
  END t_d[456]
  PIN t_d[457]
    DIRECTION OUTPUT ;
    USE SIGNAL ;
    PORT
      LAYER M4 ;
        RECT  0 72.72 0.084 72.744 ;
    END
  END t_d[457]
  PIN t_d[458]
    DIRECTION OUTPUT ;
    USE SIGNAL ;
    PORT
      LAYER M4 ;
        RECT  0 72.816 0.084 72.84 ;
    END
  END t_d[458]
  PIN t_d[459]
    DIRECTION OUTPUT ;
    USE SIGNAL ;
    PORT
      LAYER M4 ;
        RECT  0 72.912 0.084 72.936 ;
    END
  END t_d[459]
  PIN t_d[45]
    DIRECTION OUTPUT ;
    USE SIGNAL ;
    PORT
      LAYER M4 ;
        RECT  0 60.048 0.084 60.072 ;
    END
  END t_d[45]
  PIN t_d[460]
    DIRECTION OUTPUT ;
    USE SIGNAL ;
    PORT
      LAYER M4 ;
        RECT  0 73.008 0.084 73.032 ;
    END
  END t_d[460]
  PIN t_d[461]
    DIRECTION OUTPUT ;
    USE SIGNAL ;
    PORT
      LAYER M4 ;
        RECT  0 73.104 0.084 73.128 ;
    END
  END t_d[461]
  PIN t_d[462]
    DIRECTION OUTPUT ;
    USE SIGNAL ;
    PORT
      LAYER M4 ;
        RECT  0 73.2 0.084 73.224 ;
    END
  END t_d[462]
  PIN t_d[463]
    DIRECTION OUTPUT ;
    USE SIGNAL ;
    PORT
      LAYER M4 ;
        RECT  0 73.296 0.084 73.32 ;
    END
  END t_d[463]
  PIN t_d[464]
    DIRECTION OUTPUT ;
    USE SIGNAL ;
    PORT
      LAYER M4 ;
        RECT  0 73.392 0.084 73.416 ;
    END
  END t_d[464]
  PIN t_d[465]
    DIRECTION OUTPUT ;
    USE SIGNAL ;
    PORT
      LAYER M4 ;
        RECT  0 73.488 0.084 73.512 ;
    END
  END t_d[465]
  PIN t_d[466]
    DIRECTION OUTPUT ;
    USE SIGNAL ;
    PORT
      LAYER M4 ;
        RECT  0 73.584 0.084 73.608 ;
    END
  END t_d[466]
  PIN t_d[467]
    DIRECTION OUTPUT ;
    USE SIGNAL ;
    PORT
      LAYER M4 ;
        RECT  0 73.68 0.084 73.704 ;
    END
  END t_d[467]
  PIN t_d[468]
    DIRECTION OUTPUT ;
    USE SIGNAL ;
    PORT
      LAYER M4 ;
        RECT  0 73.776 0.084 73.8 ;
    END
  END t_d[468]
  PIN t_d[469]
    DIRECTION OUTPUT ;
    USE SIGNAL ;
    PORT
      LAYER M4 ;
        RECT  0 73.872 0.084 73.896 ;
    END
  END t_d[469]
  PIN t_d[46]
    DIRECTION OUTPUT ;
    USE SIGNAL ;
    PORT
      LAYER M4 ;
        RECT  0 60.144 0.084 60.168 ;
    END
  END t_d[46]
  PIN t_d[470]
    DIRECTION OUTPUT ;
    USE SIGNAL ;
    PORT
      LAYER M4 ;
        RECT  0 73.968 0.084 73.992 ;
    END
  END t_d[470]
  PIN t_d[471]
    DIRECTION OUTPUT ;
    USE SIGNAL ;
    PORT
      LAYER M4 ;
        RECT  0 74.064 0.084 74.088 ;
    END
  END t_d[471]
  PIN t_d[472]
    DIRECTION OUTPUT ;
    USE SIGNAL ;
    PORT
      LAYER M4 ;
        RECT  0 74.16 0.084 74.184 ;
    END
  END t_d[472]
  PIN t_d[473]
    DIRECTION OUTPUT ;
    USE SIGNAL ;
    PORT
      LAYER M4 ;
        RECT  0 74.256 0.084 74.28 ;
    END
  END t_d[473]
  PIN t_d[474]
    DIRECTION OUTPUT ;
    USE SIGNAL ;
    PORT
      LAYER M4 ;
        RECT  0 74.352 0.084 74.376 ;
    END
  END t_d[474]
  PIN t_d[475]
    DIRECTION OUTPUT ;
    USE SIGNAL ;
    PORT
      LAYER M4 ;
        RECT  0 74.448 0.084 74.472 ;
    END
  END t_d[475]
  PIN t_d[476]
    DIRECTION OUTPUT ;
    USE SIGNAL ;
    PORT
      LAYER M4 ;
        RECT  0 65.328 0.084 65.352 ;
    END
  END t_d[476]
  PIN t_d[477]
    DIRECTION OUTPUT ;
    USE SIGNAL ;
    PORT
      LAYER M4 ;
        RECT  0 65.424 0.084 65.448 ;
    END
  END t_d[477]
  PIN t_d[478]
    DIRECTION OUTPUT ;
    USE SIGNAL ;
    PORT
      LAYER M4 ;
        RECT  0 65.52 0.084 65.544 ;
    END
  END t_d[478]
  PIN t_d[479]
    DIRECTION OUTPUT ;
    USE SIGNAL ;
    PORT
      LAYER M4 ;
        RECT  0 65.616 0.084 65.64 ;
    END
  END t_d[479]
  PIN t_d[47]
    DIRECTION OUTPUT ;
    USE SIGNAL ;
    PORT
      LAYER M4 ;
        RECT  0 60.24 0.084 60.264 ;
    END
  END t_d[47]
  PIN t_d[480]
    DIRECTION OUTPUT ;
    USE SIGNAL ;
    PORT
      LAYER M4 ;
        RECT  0 65.712 0.084 65.736 ;
    END
  END t_d[480]
  PIN t_d[481]
    DIRECTION OUTPUT ;
    USE SIGNAL ;
    PORT
      LAYER M4 ;
        RECT  0 65.808 0.084 65.832 ;
    END
  END t_d[481]
  PIN t_d[482]
    DIRECTION OUTPUT ;
    USE SIGNAL ;
    PORT
      LAYER M4 ;
        RECT  0 65.904 0.084 65.928 ;
    END
  END t_d[482]
  PIN t_d[483]
    DIRECTION OUTPUT ;
    USE SIGNAL ;
    PORT
      LAYER M4 ;
        RECT  0 66 0.084 66.024 ;
    END
  END t_d[483]
  PIN t_d[484]
    DIRECTION OUTPUT ;
    USE SIGNAL ;
    PORT
      LAYER M4 ;
        RECT  0 66.096 0.084 66.12 ;
    END
  END t_d[484]
  PIN t_d[485]
    DIRECTION OUTPUT ;
    USE SIGNAL ;
    PORT
      LAYER M4 ;
        RECT  0 66.192 0.084 66.216 ;
    END
  END t_d[485]
  PIN t_d[486]
    DIRECTION OUTPUT ;
    USE SIGNAL ;
    PORT
      LAYER M4 ;
        RECT  0 66.288 0.084 66.312 ;
    END
  END t_d[486]
  PIN t_d[487]
    DIRECTION OUTPUT ;
    USE SIGNAL ;
    PORT
      LAYER M4 ;
        RECT  0 66.384 0.084 66.408 ;
    END
  END t_d[487]
  PIN t_d[488]
    DIRECTION OUTPUT ;
    USE SIGNAL ;
    PORT
      LAYER M4 ;
        RECT  0 66.48 0.084 66.504 ;
    END
  END t_d[488]
  PIN t_d[489]
    DIRECTION OUTPUT ;
    USE SIGNAL ;
    PORT
      LAYER M4 ;
        RECT  0 66.576 0.084 66.6 ;
    END
  END t_d[489]
  PIN t_d[48]
    DIRECTION OUTPUT ;
    USE SIGNAL ;
    PORT
      LAYER M4 ;
        RECT  0 60.336 0.084 60.36 ;
    END
  END t_d[48]
  PIN t_d[490]
    DIRECTION OUTPUT ;
    USE SIGNAL ;
    PORT
      LAYER M4 ;
        RECT  0 66.672 0.084 66.696 ;
    END
  END t_d[490]
  PIN t_d[491]
    DIRECTION OUTPUT ;
    USE SIGNAL ;
    PORT
      LAYER M4 ;
        RECT  0 66.768 0.084 66.792 ;
    END
  END t_d[491]
  PIN t_d[492]
    DIRECTION OUTPUT ;
    USE SIGNAL ;
    PORT
      LAYER M4 ;
        RECT  0 66.864 0.084 66.888 ;
    END
  END t_d[492]
  PIN t_d[493]
    DIRECTION OUTPUT ;
    USE SIGNAL ;
    PORT
      LAYER M4 ;
        RECT  0 66.96 0.084 66.984 ;
    END
  END t_d[493]
  PIN t_d[494]
    DIRECTION OUTPUT ;
    USE SIGNAL ;
    PORT
      LAYER M4 ;
        RECT  0 67.056 0.084 67.08 ;
    END
  END t_d[494]
  PIN t_d[495]
    DIRECTION OUTPUT ;
    USE SIGNAL ;
    PORT
      LAYER M4 ;
        RECT  0 67.152 0.084 67.176 ;
    END
  END t_d[495]
  PIN t_d[496]
    DIRECTION OUTPUT ;
    USE SIGNAL ;
    PORT
      LAYER M4 ;
        RECT  0 67.248 0.084 67.272 ;
    END
  END t_d[496]
  PIN t_d[497]
    DIRECTION OUTPUT ;
    USE SIGNAL ;
    PORT
      LAYER M4 ;
        RECT  0 67.344 0.084 67.368 ;
    END
  END t_d[497]
  PIN t_d[498]
    DIRECTION OUTPUT ;
    USE SIGNAL ;
    PORT
      LAYER M4 ;
        RECT  0 67.44 0.084 67.464 ;
    END
  END t_d[498]
  PIN t_d[499]
    DIRECTION OUTPUT ;
    USE SIGNAL ;
    PORT
      LAYER M4 ;
        RECT  0 67.536 0.084 67.56 ;
    END
  END t_d[499]
  PIN t_d[49]
    DIRECTION OUTPUT ;
    USE SIGNAL ;
    PORT
      LAYER M4 ;
        RECT  0 60.432 0.084 60.456 ;
    END
  END t_d[49]
  PIN t_d[4]
    DIRECTION OUTPUT ;
    USE SIGNAL ;
    PORT
      LAYER M4 ;
        RECT  0 53.04 0.084 53.064 ;
    END
  END t_d[4]
  PIN t_d[500]
    DIRECTION OUTPUT ;
    USE SIGNAL ;
    PORT
      LAYER M4 ;
        RECT  0 67.632 0.084 67.656 ;
    END
  END t_d[500]
  PIN t_d[501]
    DIRECTION OUTPUT ;
    USE SIGNAL ;
    PORT
      LAYER M4 ;
        RECT  0 67.728 0.084 67.752 ;
    END
  END t_d[501]
  PIN t_d[502]
    DIRECTION OUTPUT ;
    USE SIGNAL ;
    PORT
      LAYER M4 ;
        RECT  0 67.824 0.084 67.848 ;
    END
  END t_d[502]
  PIN t_d[503]
    DIRECTION OUTPUT ;
    USE SIGNAL ;
    PORT
      LAYER M4 ;
        RECT  0 67.92 0.084 67.944 ;
    END
  END t_d[503]
  PIN t_d[504]
    DIRECTION OUTPUT ;
    USE SIGNAL ;
    PORT
      LAYER M4 ;
        RECT  0 68.016 0.084 68.04 ;
    END
  END t_d[504]
  PIN t_d[505]
    DIRECTION OUTPUT ;
    USE SIGNAL ;
    PORT
      LAYER M4 ;
        RECT  0 68.112 0.084 68.136 ;
    END
  END t_d[505]
  PIN t_d[506]
    DIRECTION OUTPUT ;
    USE SIGNAL ;
    PORT
      LAYER M4 ;
        RECT  0 68.208 0.084 68.232 ;
    END
  END t_d[506]
  PIN t_d[507]
    DIRECTION OUTPUT ;
    USE SIGNAL ;
    PORT
      LAYER M4 ;
        RECT  0 68.304 0.084 68.328 ;
    END
  END t_d[507]
  PIN t_d[50]
    DIRECTION OUTPUT ;
    USE SIGNAL ;
    PORT
      LAYER M4 ;
        RECT  0 60.528 0.084 60.552 ;
    END
  END t_d[50]
  PIN t_d[51]
    DIRECTION OUTPUT ;
    USE SIGNAL ;
    PORT
      LAYER M4 ;
        RECT  0 60.624 0.084 60.648 ;
    END
  END t_d[51]
  PIN t_d[52]
    DIRECTION OUTPUT ;
    USE SIGNAL ;
    PORT
      LAYER M4 ;
        RECT  0 60.72 0.084 60.744 ;
    END
  END t_d[52]
  PIN t_d[53]
    DIRECTION OUTPUT ;
    USE SIGNAL ;
    PORT
      LAYER M4 ;
        RECT  0 60.816 0.084 60.84 ;
    END
  END t_d[53]
  PIN t_d[54]
    DIRECTION OUTPUT ;
    USE SIGNAL ;
    PORT
      LAYER M4 ;
        RECT  0 60.912 0.084 60.936 ;
    END
  END t_d[54]
  PIN t_d[55]
    DIRECTION OUTPUT ;
    USE SIGNAL ;
    PORT
      LAYER M4 ;
        RECT  0 61.008 0.084 61.032 ;
    END
  END t_d[55]
  PIN t_d[56]
    DIRECTION OUTPUT ;
    USE SIGNAL ;
    PORT
      LAYER M4 ;
        RECT  0 61.104 0.084 61.128 ;
    END
  END t_d[56]
  PIN t_d[57]
    DIRECTION OUTPUT ;
    USE SIGNAL ;
    PORT
      LAYER M4 ;
        RECT  0 61.2 0.084 61.224 ;
    END
  END t_d[57]
  PIN t_d[58]
    DIRECTION OUTPUT ;
    USE SIGNAL ;
    PORT
      LAYER M4 ;
        RECT  0 61.296 0.084 61.32 ;
    END
  END t_d[58]
  PIN t_d[59]
    DIRECTION OUTPUT ;
    USE SIGNAL ;
    PORT
      LAYER M4 ;
        RECT  0 61.392 0.084 61.416 ;
    END
  END t_d[59]
  PIN t_d[5]
    DIRECTION OUTPUT ;
    USE SIGNAL ;
    PORT
      LAYER M4 ;
        RECT  0 53.136 0.084 53.16 ;
    END
  END t_d[5]
  PIN t_d[60]
    DIRECTION OUTPUT ;
    USE SIGNAL ;
    PORT
      LAYER M4 ;
        RECT  0 46.128 0.084 46.152 ;
    END
  END t_d[60]
  PIN t_d[61]
    DIRECTION OUTPUT ;
    USE SIGNAL ;
    PORT
      LAYER M4 ;
        RECT  0 46.224 0.084 46.248 ;
    END
  END t_d[61]
  PIN t_d[62]
    DIRECTION OUTPUT ;
    USE SIGNAL ;
    PORT
      LAYER M4 ;
        RECT  0 46.32 0.084 46.344 ;
    END
  END t_d[62]
  PIN t_d[63]
    DIRECTION OUTPUT ;
    USE SIGNAL ;
    PORT
      LAYER M4 ;
        RECT  0 46.416 0.084 46.44 ;
    END
  END t_d[63]
  PIN t_d[64]
    DIRECTION OUTPUT ;
    USE SIGNAL ;
    PORT
      LAYER M4 ;
        RECT  0 46.512 0.084 46.536 ;
    END
  END t_d[64]
  PIN t_d[65]
    DIRECTION OUTPUT ;
    USE SIGNAL ;
    PORT
      LAYER M4 ;
        RECT  0 46.608 0.084 46.632 ;
    END
  END t_d[65]
  PIN t_d[66]
    DIRECTION OUTPUT ;
    USE SIGNAL ;
    PORT
      LAYER M4 ;
        RECT  0 46.704 0.084 46.728 ;
    END
  END t_d[66]
  PIN t_d[67]
    DIRECTION OUTPUT ;
    USE SIGNAL ;
    PORT
      LAYER M4 ;
        RECT  0 46.8 0.084 46.824 ;
    END
  END t_d[67]
  PIN t_d[68]
    DIRECTION OUTPUT ;
    USE SIGNAL ;
    PORT
      LAYER M4 ;
        RECT  0 46.896 0.084 46.92 ;
    END
  END t_d[68]
  PIN t_d[69]
    DIRECTION OUTPUT ;
    USE SIGNAL ;
    PORT
      LAYER M4 ;
        RECT  0 46.992 0.084 47.016 ;
    END
  END t_d[69]
  PIN t_d[6]
    DIRECTION OUTPUT ;
    USE SIGNAL ;
    PORT
      LAYER M4 ;
        RECT  0 53.232 0.084 53.256 ;
    END
  END t_d[6]
  PIN t_d[70]
    DIRECTION OUTPUT ;
    USE SIGNAL ;
    PORT
      LAYER M4 ;
        RECT  0 47.088 0.084 47.112 ;
    END
  END t_d[70]
  PIN t_d[71]
    DIRECTION OUTPUT ;
    USE SIGNAL ;
    PORT
      LAYER M4 ;
        RECT  0 47.184 0.084 47.208 ;
    END
  END t_d[71]
  PIN t_d[72]
    DIRECTION OUTPUT ;
    USE SIGNAL ;
    PORT
      LAYER M4 ;
        RECT  0 47.28 0.084 47.304 ;
    END
  END t_d[72]
  PIN t_d[73]
    DIRECTION OUTPUT ;
    USE SIGNAL ;
    PORT
      LAYER M4 ;
        RECT  0 47.376 0.084 47.4 ;
    END
  END t_d[73]
  PIN t_d[74]
    DIRECTION OUTPUT ;
    USE SIGNAL ;
    PORT
      LAYER M4 ;
        RECT  0 47.472 0.084 47.496 ;
    END
  END t_d[74]
  PIN t_d[75]
    DIRECTION OUTPUT ;
    USE SIGNAL ;
    PORT
      LAYER M4 ;
        RECT  0 47.568 0.084 47.592 ;
    END
  END t_d[75]
  PIN t_d[76]
    DIRECTION OUTPUT ;
    USE SIGNAL ;
    PORT
      LAYER M4 ;
        RECT  0 47.664 0.084 47.688 ;
    END
  END t_d[76]
  PIN t_d[77]
    DIRECTION OUTPUT ;
    USE SIGNAL ;
    PORT
      LAYER M4 ;
        RECT  0 47.76 0.084 47.784 ;
    END
  END t_d[77]
  PIN t_d[78]
    DIRECTION OUTPUT ;
    USE SIGNAL ;
    PORT
      LAYER M4 ;
        RECT  0 47.856 0.084 47.88 ;
    END
  END t_d[78]
  PIN t_d[79]
    DIRECTION OUTPUT ;
    USE SIGNAL ;
    PORT
      LAYER M4 ;
        RECT  0 47.952 0.084 47.976 ;
    END
  END t_d[79]
  PIN t_d[7]
    DIRECTION OUTPUT ;
    USE SIGNAL ;
    PORT
      LAYER M4 ;
        RECT  0 53.328 0.084 53.352 ;
    END
  END t_d[7]
  PIN t_d[80]
    DIRECTION OUTPUT ;
    USE SIGNAL ;
    PORT
      LAYER M4 ;
        RECT  0 48.048 0.084 48.072 ;
    END
  END t_d[80]
  PIN t_d[81]
    DIRECTION OUTPUT ;
    USE SIGNAL ;
    PORT
      LAYER M4 ;
        RECT  0 48.144 0.084 48.168 ;
    END
  END t_d[81]
  PIN t_d[82]
    DIRECTION OUTPUT ;
    USE SIGNAL ;
    PORT
      LAYER M4 ;
        RECT  0 48.24 0.084 48.264 ;
    END
  END t_d[82]
  PIN t_d[83]
    DIRECTION OUTPUT ;
    USE SIGNAL ;
    PORT
      LAYER M4 ;
        RECT  0 48.336 0.084 48.36 ;
    END
  END t_d[83]
  PIN t_d[84]
    DIRECTION OUTPUT ;
    USE SIGNAL ;
    PORT
      LAYER M4 ;
        RECT  0 48.432 0.084 48.456 ;
    END
  END t_d[84]
  PIN t_d[85]
    DIRECTION OUTPUT ;
    USE SIGNAL ;
    PORT
      LAYER M4 ;
        RECT  0 48.528 0.084 48.552 ;
    END
  END t_d[85]
  PIN t_d[86]
    DIRECTION OUTPUT ;
    USE SIGNAL ;
    PORT
      LAYER M4 ;
        RECT  0 48.624 0.084 48.648 ;
    END
  END t_d[86]
  PIN t_d[87]
    DIRECTION OUTPUT ;
    USE SIGNAL ;
    PORT
      LAYER M4 ;
        RECT  0 48.72 0.084 48.744 ;
    END
  END t_d[87]
  PIN t_d[88]
    DIRECTION OUTPUT ;
    USE SIGNAL ;
    PORT
      LAYER M4 ;
        RECT  0 48.816 0.084 48.84 ;
    END
  END t_d[88]
  PIN t_d[89]
    DIRECTION OUTPUT ;
    USE SIGNAL ;
    PORT
      LAYER M4 ;
        RECT  0 48.912 0.084 48.936 ;
    END
  END t_d[89]
  PIN t_d[8]
    DIRECTION OUTPUT ;
    USE SIGNAL ;
    PORT
      LAYER M4 ;
        RECT  0 53.424 0.084 53.448 ;
    END
  END t_d[8]
  PIN t_d[90]
    DIRECTION OUTPUT ;
    USE SIGNAL ;
    PORT
      LAYER M4 ;
        RECT  0 49.008 0.084 49.032 ;
    END
  END t_d[90]
  PIN t_d[91]
    DIRECTION OUTPUT ;
    USE SIGNAL ;
    PORT
      LAYER M4 ;
        RECT  0 49.104 0.084 49.128 ;
    END
  END t_d[91]
  PIN t_d[92]
    DIRECTION OUTPUT ;
    USE SIGNAL ;
    PORT
      LAYER M4 ;
        RECT  0 61.488 0.084 61.512 ;
    END
  END t_d[92]
  PIN t_d[93]
    DIRECTION OUTPUT ;
    USE SIGNAL ;
    PORT
      LAYER M4 ;
        RECT  0 61.584 0.084 61.608 ;
    END
  END t_d[93]
  PIN t_d[94]
    DIRECTION OUTPUT ;
    USE SIGNAL ;
    PORT
      LAYER M4 ;
        RECT  0 61.68 0.084 61.704 ;
    END
  END t_d[94]
  PIN t_d[95]
    DIRECTION OUTPUT ;
    USE SIGNAL ;
    PORT
      LAYER M4 ;
        RECT  0 61.776 0.084 61.8 ;
    END
  END t_d[95]
  PIN t_d[96]
    DIRECTION OUTPUT ;
    USE SIGNAL ;
    PORT
      LAYER M4 ;
        RECT  0 61.872 0.084 61.896 ;
    END
  END t_d[96]
  PIN t_d[97]
    DIRECTION OUTPUT ;
    USE SIGNAL ;
    PORT
      LAYER M4 ;
        RECT  0 61.968 0.084 61.992 ;
    END
  END t_d[97]
  PIN t_d[98]
    DIRECTION OUTPUT ;
    USE SIGNAL ;
    PORT
      LAYER M4 ;
        RECT  0 62.064 0.084 62.088 ;
    END
  END t_d[98]
  PIN t_d[99]
    DIRECTION OUTPUT ;
    USE SIGNAL ;
    PORT
      LAYER M4 ;
        RECT  0 62.16 0.084 62.184 ;
    END
  END t_d[99]
  PIN t_d[9]
    DIRECTION OUTPUT ;
    USE SIGNAL ;
    PORT
      LAYER M4 ;
        RECT  0 53.52 0.084 53.544 ;
    END
  END t_d[9]
  PIN t_r
    DIRECTION INPUT ;
    USE SIGNAL ;
    PORT
      LAYER M4 ;
        RECT  0 46.032 0.084 46.056 ;
    END
  END t_r
  PIN VDD
    DIRECTION INOUT ;
    USE POWER ;
    PORT
      LAYER M5 ;
        RECT  51.192 2.151 51.312 101.529 ;
        RECT  45.792 2.151 45.912 101.529 ;
        RECT  40.392 2.151 40.512 101.529 ;
        RECT  34.992 2.151 35.112 101.529 ;
        RECT  29.592 2.151 29.712 101.529 ;
        RECT  24.192 2.151 24.312 101.529 ;
        RECT  18.792 2.151 18.912 101.529 ;
        RECT  13.392 2.151 13.512 101.529 ;
        RECT  7.992 2.151 8.112 101.529 ;
        RECT  2.592 2.151 2.712 101.529 ;
    END
  END VDD
  PIN VSS
    DIRECTION INOUT ;
    USE GROUND ;
    PORT
      LAYER M5 ;
        RECT  51 2.137 51.12 101.543 ;
        RECT  45.6 2.137 45.72 101.543 ;
        RECT  40.2 2.137 40.32 101.543 ;
        RECT  34.8 2.137 34.92 101.543 ;
        RECT  29.4 2.137 29.52 101.543 ;
        RECT  24 2.137 24.12 101.543 ;
        RECT  18.6 2.137 18.72 101.543 ;
        RECT  13.2 2.137 13.32 101.543 ;
        RECT  7.8 2.137 7.92 101.543 ;
        RECT  2.4 2.137 2.52 101.543 ;
    END
  END VSS
  OBS
    LAYER RVTN ;
     RECT  2.16 2.16 51.84 2.295 ;
     RECT  2.16 2.565 51.84 2.835 ;
     RECT  2.16 3.105 51.84 3.375 ;
     RECT  2.16 3.645 51.84 3.915 ;
     RECT  2.16 4.185 51.84 4.455 ;
     RECT  2.16 4.725 51.84 4.995 ;
     RECT  2.16 5.265 51.84 5.535 ;
     RECT  2.16 5.805 51.84 6.075 ;
     RECT  2.16 6.345 51.84 6.615 ;
     RECT  2.16 6.885 51.84 7.155 ;
     RECT  2.16 7.425 51.84 7.695 ;
     RECT  2.16 7.965 51.84 8.235 ;
     RECT  2.16 8.505 51.84 8.775 ;
     RECT  2.16 9.045 51.84 9.315 ;
     RECT  2.16 9.585 51.84 9.855 ;
     RECT  2.16 10.125 51.84 10.395 ;
     RECT  2.16 10.665 51.84 10.935 ;
     RECT  2.16 11.205 51.84 11.475 ;
     RECT  2.16 11.745 51.84 12.015 ;
     RECT  2.16 12.285 51.84 12.555 ;
     RECT  2.16 12.825 51.84 13.095 ;
     RECT  2.16 13.365 51.84 13.635 ;
     RECT  2.16 13.905 51.84 14.175 ;
     RECT  2.16 14.445 51.84 14.715 ;
     RECT  2.16 14.985 51.84 15.255 ;
     RECT  2.16 15.525 51.84 15.795 ;
     RECT  2.16 16.065 51.84 16.335 ;
     RECT  2.16 16.605 51.84 16.875 ;
     RECT  2.16 17.145 51.84 17.415 ;
     RECT  2.16 17.685 51.84 17.955 ;
     RECT  2.16 18.225 51.84 18.495 ;
     RECT  2.16 18.765 51.84 19.035 ;
     RECT  2.16 19.305 51.84 19.575 ;
     RECT  2.16 19.845 51.84 20.115 ;
     RECT  2.16 20.385 51.84 20.655 ;
     RECT  2.16 20.925 51.84 21.195 ;
     RECT  2.16 21.465 51.84 21.735 ;
     RECT  2.16 22.005 51.84 22.275 ;
     RECT  2.16 22.545 51.84 22.815 ;
     RECT  2.16 23.085 51.84 23.355 ;
     RECT  2.16 23.625 51.84 23.895 ;
     RECT  2.16 24.165 51.84 24.435 ;
     RECT  2.16 24.705 51.84 24.975 ;
     RECT  2.16 25.245 51.84 25.515 ;
     RECT  2.16 25.785 51.84 26.055 ;
     RECT  2.16 26.325 51.84 26.595 ;
     RECT  2.16 26.865 51.84 27.135 ;
     RECT  2.16 27.405 51.84 27.675 ;
     RECT  2.16 27.945 51.84 28.215 ;
     RECT  2.16 28.485 51.84 28.755 ;
     RECT  2.16 29.025 51.84 29.295 ;
     RECT  2.16 29.565 51.84 29.835 ;
     RECT  2.16 30.105 51.84 30.375 ;
     RECT  2.16 30.645 51.84 30.915 ;
     RECT  2.16 31.185 51.84 31.455 ;
     RECT  2.16 31.725 51.84 31.995 ;
     RECT  2.16 32.265 51.84 32.535 ;
     RECT  2.16 32.805 51.84 33.075 ;
     RECT  2.16 33.345 51.84 33.615 ;
     RECT  2.16 33.885 51.84 34.155 ;
     RECT  2.16 34.425 51.84 34.695 ;
     RECT  2.16 34.965 51.84 35.235 ;
     RECT  2.16 35.505 51.84 35.775 ;
     RECT  2.16 36.045 51.84 36.315 ;
     RECT  2.16 36.585 51.84 36.855 ;
     RECT  2.16 37.125 51.84 37.395 ;
     RECT  2.16 37.665 51.84 37.935 ;
     RECT  2.16 38.205 51.84 38.475 ;
     RECT  2.16 38.745 51.84 39.015 ;
     RECT  2.16 39.285 51.84 39.555 ;
     RECT  2.16 39.825 51.84 40.095 ;
     RECT  2.16 40.365 51.84 40.635 ;
     RECT  2.16 40.905 51.84 41.175 ;
     RECT  2.16 41.445 51.84 41.715 ;
     RECT  2.16 41.985 51.84 42.255 ;
     RECT  2.16 42.525 51.84 42.795 ;
     RECT  2.16 43.065 51.84 43.335 ;
     RECT  2.16 43.605 51.84 43.875 ;
     RECT  2.16 44.145 51.84 44.415 ;
     RECT  2.16 44.685 51.84 44.955 ;
     RECT  2.16 45.225 51.84 45.495 ;
     RECT  2.16 45.765 51.84 46.035 ;
     RECT  2.16 46.305 51.84 46.575 ;
     RECT  2.16 46.845 51.84 47.115 ;
     RECT  2.16 47.385 51.84 47.655 ;
     RECT  2.16 47.925 51.84 48.195 ;
     RECT  2.16 48.465 51.84 48.735 ;
     RECT  2.16 49.005 51.84 49.275 ;
     RECT  2.16 49.545 51.84 49.815 ;
     RECT  2.16 50.085 51.84 50.355 ;
     RECT  2.16 50.625 51.84 50.895 ;
     RECT  2.16 51.165 51.84 51.435 ;
     RECT  2.16 51.705 51.84 51.975 ;
     RECT  2.16 52.245 51.84 52.515 ;
     RECT  2.16 52.785 51.84 53.055 ;
     RECT  2.16 53.325 51.84 53.595 ;
     RECT  2.16 53.865 51.84 54.135 ;
     RECT  2.16 54.405 51.84 54.675 ;
     RECT  2.16 54.945 51.84 55.215 ;
     RECT  2.16 55.485 51.84 55.755 ;
     RECT  2.16 56.025 51.84 56.295 ;
     RECT  2.16 56.565 51.84 56.835 ;
     RECT  2.16 57.105 51.84 57.375 ;
     RECT  2.16 57.645 51.84 57.915 ;
     RECT  2.16 58.185 51.84 58.455 ;
     RECT  2.16 58.725 51.84 58.995 ;
     RECT  2.16 59.265 51.84 59.535 ;
     RECT  2.16 59.805 51.84 60.075 ;
     RECT  2.16 60.345 51.84 60.615 ;
     RECT  2.16 60.885 51.84 61.155 ;
     RECT  2.16 61.425 51.84 61.695 ;
     RECT  2.16 61.965 51.84 62.235 ;
     RECT  2.16 62.505 51.84 62.775 ;
     RECT  2.16 63.045 51.84 63.315 ;
     RECT  2.16 63.585 51.84 63.855 ;
     RECT  2.16 64.125 51.84 64.395 ;
     RECT  2.16 64.665 51.84 64.935 ;
     RECT  2.16 65.205 51.84 65.475 ;
     RECT  2.16 65.745 51.84 66.015 ;
     RECT  2.16 66.285 51.84 66.555 ;
     RECT  2.16 66.825 51.84 67.095 ;
     RECT  2.16 67.365 51.84 67.635 ;
     RECT  2.16 67.905 51.84 68.175 ;
     RECT  2.16 68.445 51.84 68.715 ;
     RECT  2.16 68.985 51.84 69.255 ;
     RECT  2.16 69.525 51.84 69.795 ;
     RECT  2.16 70.065 51.84 70.335 ;
     RECT  2.16 70.605 51.84 70.875 ;
     RECT  2.16 71.145 51.84 71.415 ;
     RECT  2.16 71.685 51.84 71.955 ;
     RECT  2.16 72.225 51.84 72.495 ;
     RECT  2.16 72.765 51.84 73.035 ;
     RECT  2.16 73.305 51.84 73.575 ;
     RECT  2.16 73.845 51.84 74.115 ;
     RECT  2.16 74.385 51.84 74.655 ;
     RECT  2.16 74.925 51.84 75.195 ;
     RECT  2.16 75.465 51.84 75.735 ;
     RECT  2.16 76.005 51.84 76.275 ;
     RECT  2.16 76.545 51.84 76.815 ;
     RECT  2.16 77.085 51.84 77.355 ;
     RECT  2.16 77.625 51.84 77.895 ;
     RECT  2.16 78.165 51.84 78.435 ;
     RECT  2.16 78.705 51.84 78.975 ;
     RECT  2.16 79.245 51.84 79.515 ;
     RECT  2.16 79.785 51.84 80.055 ;
     RECT  2.16 80.325 51.84 80.595 ;
     RECT  2.16 80.865 51.84 81.135 ;
     RECT  2.16 81.405 51.84 81.675 ;
     RECT  2.16 81.945 51.84 82.215 ;
     RECT  2.16 82.485 51.84 82.755 ;
     RECT  2.16 83.025 51.84 83.295 ;
     RECT  2.16 83.565 51.84 83.835 ;
     RECT  2.16 84.105 51.84 84.375 ;
     RECT  2.16 84.645 51.84 84.915 ;
     RECT  2.16 85.185 51.84 85.455 ;
     RECT  2.16 85.725 51.84 85.995 ;
     RECT  2.16 86.265 51.84 86.535 ;
     RECT  2.16 86.805 51.84 87.075 ;
     RECT  2.16 87.345 51.84 87.615 ;
     RECT  2.16 87.885 51.84 88.155 ;
     RECT  2.16 88.425 51.84 88.695 ;
     RECT  2.16 88.965 51.84 89.235 ;
     RECT  2.16 89.505 51.84 89.775 ;
     RECT  2.16 90.045 51.84 90.315 ;
     RECT  2.16 90.585 51.84 90.855 ;
     RECT  2.16 91.125 51.84 91.395 ;
     RECT  2.16 91.665 51.84 91.935 ;
     RECT  2.16 92.205 51.84 92.475 ;
     RECT  2.16 92.745 51.84 93.015 ;
     RECT  2.16 93.285 51.84 93.555 ;
     RECT  2.16 93.825 51.84 94.095 ;
     RECT  2.16 94.365 51.84 94.635 ;
     RECT  2.16 94.905 51.84 95.175 ;
     RECT  2.16 95.445 51.84 95.715 ;
     RECT  2.16 95.985 51.84 96.255 ;
     RECT  2.16 96.525 51.84 96.795 ;
     RECT  2.16 97.065 51.84 97.335 ;
     RECT  2.16 97.605 51.84 97.875 ;
     RECT  2.16 98.145 51.84 98.415 ;
     RECT  2.16 98.685 51.84 98.955 ;
     RECT  2.16 99.225 51.84 99.495 ;
     RECT  2.16 99.765 51.84 100.035 ;
     RECT  2.16 100.305 51.84 100.575 ;
     RECT  2.16 100.845 51.84 101.115 ;
     RECT  2.16 101.385 51.84 101.52 ;
    LAYER RVTP ;
     RECT  2.16 2.295 51.84 2.565 ;
     RECT  2.16 2.835 51.84 3.105 ;
     RECT  2.16 3.375 51.84 3.645 ;
     RECT  2.16 3.915 51.84 4.185 ;
     RECT  2.16 4.455 51.84 4.725 ;
     RECT  2.16 4.995 51.84 5.265 ;
     RECT  2.16 5.535 51.84 5.805 ;
     RECT  2.16 6.075 51.84 6.345 ;
     RECT  2.16 6.615 51.84 6.885 ;
     RECT  2.16 7.155 51.84 7.425 ;
     RECT  2.16 7.695 51.84 7.965 ;
     RECT  2.16 8.235 51.84 8.505 ;
     RECT  2.16 8.775 51.84 9.045 ;
     RECT  2.16 9.315 51.84 9.585 ;
     RECT  2.16 9.855 51.84 10.125 ;
     RECT  2.16 10.395 51.84 10.665 ;
     RECT  2.16 10.935 51.84 11.205 ;
     RECT  2.16 11.475 51.84 11.745 ;
     RECT  2.16 12.015 51.84 12.285 ;
     RECT  2.16 12.555 51.84 12.825 ;
     RECT  2.16 13.095 51.84 13.365 ;
     RECT  2.16 13.635 51.84 13.905 ;
     RECT  2.16 14.175 51.84 14.445 ;
     RECT  2.16 14.715 51.84 14.985 ;
     RECT  2.16 15.255 51.84 15.525 ;
     RECT  2.16 15.795 51.84 16.065 ;
     RECT  2.16 16.335 51.84 16.605 ;
     RECT  2.16 16.875 51.84 17.145 ;
     RECT  2.16 17.415 51.84 17.685 ;
     RECT  2.16 17.955 51.84 18.225 ;
     RECT  2.16 18.495 51.84 18.765 ;
     RECT  2.16 19.035 51.84 19.305 ;
     RECT  2.16 19.575 51.84 19.845 ;
     RECT  2.16 20.115 51.84 20.385 ;
     RECT  2.16 20.655 51.84 20.925 ;
     RECT  2.16 21.195 51.84 21.465 ;
     RECT  2.16 21.735 51.84 22.005 ;
     RECT  2.16 22.275 51.84 22.545 ;
     RECT  2.16 22.815 51.84 23.085 ;
     RECT  2.16 23.355 51.84 23.625 ;
     RECT  2.16 23.895 51.84 24.165 ;
     RECT  2.16 24.435 51.84 24.705 ;
     RECT  2.16 24.975 51.84 25.245 ;
     RECT  2.16 25.515 51.84 25.785 ;
     RECT  2.16 26.055 51.84 26.325 ;
     RECT  2.16 26.595 51.84 26.865 ;
     RECT  2.16 27.135 51.84 27.405 ;
     RECT  2.16 27.675 51.84 27.945 ;
     RECT  2.16 28.215 51.84 28.485 ;
     RECT  2.16 28.755 51.84 29.025 ;
     RECT  2.16 29.295 51.84 29.565 ;
     RECT  2.16 29.835 51.84 30.105 ;
     RECT  2.16 30.375 51.84 30.645 ;
     RECT  2.16 30.915 51.84 31.185 ;
     RECT  2.16 31.455 51.84 31.725 ;
     RECT  2.16 31.995 51.84 32.265 ;
     RECT  2.16 32.535 51.84 32.805 ;
     RECT  2.16 33.075 51.84 33.345 ;
     RECT  2.16 33.615 51.84 33.885 ;
     RECT  2.16 34.155 51.84 34.425 ;
     RECT  2.16 34.695 51.84 34.965 ;
     RECT  2.16 35.235 51.84 35.505 ;
     RECT  2.16 35.775 51.84 36.045 ;
     RECT  2.16 36.315 51.84 36.585 ;
     RECT  2.16 36.855 51.84 37.125 ;
     RECT  2.16 37.395 51.84 37.665 ;
     RECT  2.16 37.935 51.84 38.205 ;
     RECT  2.16 38.475 51.84 38.745 ;
     RECT  2.16 39.015 51.84 39.285 ;
     RECT  2.16 39.555 51.84 39.825 ;
     RECT  2.16 40.095 51.84 40.365 ;
     RECT  2.16 40.635 51.84 40.905 ;
     RECT  2.16 41.175 51.84 41.445 ;
     RECT  2.16 41.715 51.84 41.985 ;
     RECT  2.16 42.255 51.84 42.525 ;
     RECT  2.16 42.795 51.84 43.065 ;
     RECT  2.16 43.335 51.84 43.605 ;
     RECT  2.16 43.875 51.84 44.145 ;
     RECT  2.16 44.415 51.84 44.685 ;
     RECT  2.16 44.955 51.84 45.225 ;
     RECT  2.16 45.495 51.84 45.765 ;
     RECT  2.16 46.035 51.84 46.305 ;
     RECT  2.16 46.575 51.84 46.845 ;
     RECT  2.16 47.115 51.84 47.385 ;
     RECT  2.16 47.655 51.84 47.925 ;
     RECT  2.16 48.195 51.84 48.465 ;
     RECT  2.16 48.735 51.84 49.005 ;
     RECT  2.16 49.275 51.84 49.545 ;
     RECT  2.16 49.815 51.84 50.085 ;
     RECT  2.16 50.355 51.84 50.625 ;
     RECT  2.16 50.895 51.84 51.165 ;
     RECT  2.16 51.435 51.84 51.705 ;
     RECT  2.16 51.975 51.84 52.245 ;
     RECT  2.16 52.515 51.84 52.785 ;
     RECT  2.16 53.055 51.84 53.325 ;
     RECT  2.16 53.595 51.84 53.865 ;
     RECT  2.16 54.135 51.84 54.405 ;
     RECT  2.16 54.675 51.84 54.945 ;
     RECT  2.16 55.215 51.84 55.485 ;
     RECT  2.16 55.755 51.84 56.025 ;
     RECT  2.16 56.295 51.84 56.565 ;
     RECT  2.16 56.835 51.84 57.105 ;
     RECT  2.16 57.375 51.84 57.645 ;
     RECT  2.16 57.915 51.84 58.185 ;
     RECT  2.16 58.455 51.84 58.725 ;
     RECT  2.16 58.995 51.84 59.265 ;
     RECT  2.16 59.535 51.84 59.805 ;
     RECT  2.16 60.075 51.84 60.345 ;
     RECT  2.16 60.615 51.84 60.885 ;
     RECT  2.16 61.155 51.84 61.425 ;
     RECT  2.16 61.695 51.84 61.965 ;
     RECT  2.16 62.235 51.84 62.505 ;
     RECT  2.16 62.775 51.84 63.045 ;
     RECT  2.16 63.315 51.84 63.585 ;
     RECT  2.16 63.855 51.84 64.125 ;
     RECT  2.16 64.395 51.84 64.665 ;
     RECT  2.16 64.935 51.84 65.205 ;
     RECT  2.16 65.475 51.84 65.745 ;
     RECT  2.16 66.015 51.84 66.285 ;
     RECT  2.16 66.555 51.84 66.825 ;
     RECT  2.16 67.095 51.84 67.365 ;
     RECT  2.16 67.635 51.84 67.905 ;
     RECT  2.16 68.175 51.84 68.445 ;
     RECT  2.16 68.715 51.84 68.985 ;
     RECT  2.16 69.255 51.84 69.525 ;
     RECT  2.16 69.795 51.84 70.065 ;
     RECT  2.16 70.335 51.84 70.605 ;
     RECT  2.16 70.875 51.84 71.145 ;
     RECT  2.16 71.415 51.84 71.685 ;
     RECT  2.16 71.955 51.84 72.225 ;
     RECT  2.16 72.495 51.84 72.765 ;
     RECT  2.16 73.035 51.84 73.305 ;
     RECT  2.16 73.575 51.84 73.845 ;
     RECT  2.16 74.115 51.84 74.385 ;
     RECT  2.16 74.655 51.84 74.925 ;
     RECT  2.16 75.195 51.84 75.465 ;
     RECT  2.16 75.735 51.84 76.005 ;
     RECT  2.16 76.275 51.84 76.545 ;
     RECT  2.16 76.815 51.84 77.085 ;
     RECT  2.16 77.355 51.84 77.625 ;
     RECT  2.16 77.895 51.84 78.165 ;
     RECT  2.16 78.435 51.84 78.705 ;
     RECT  2.16 78.975 51.84 79.245 ;
     RECT  2.16 79.515 51.84 79.785 ;
     RECT  2.16 80.055 51.84 80.325 ;
     RECT  2.16 80.595 51.84 80.865 ;
     RECT  2.16 81.135 51.84 81.405 ;
     RECT  2.16 81.675 51.84 81.945 ;
     RECT  2.16 82.215 51.84 82.485 ;
     RECT  2.16 82.755 51.84 83.025 ;
     RECT  2.16 83.295 51.84 83.565 ;
     RECT  2.16 83.835 51.84 84.105 ;
     RECT  2.16 84.375 51.84 84.645 ;
     RECT  2.16 84.915 51.84 85.185 ;
     RECT  2.16 85.455 51.84 85.725 ;
     RECT  2.16 85.995 51.84 86.265 ;
     RECT  2.16 86.535 51.84 86.805 ;
     RECT  2.16 87.075 51.84 87.345 ;
     RECT  2.16 87.615 51.84 87.885 ;
     RECT  2.16 88.155 51.84 88.425 ;
     RECT  2.16 88.695 51.84 88.965 ;
     RECT  2.16 89.235 51.84 89.505 ;
     RECT  2.16 89.775 51.84 90.045 ;
     RECT  2.16 90.315 51.84 90.585 ;
     RECT  2.16 90.855 51.84 91.125 ;
     RECT  2.16 91.395 51.84 91.665 ;
     RECT  2.16 91.935 51.84 92.205 ;
     RECT  2.16 92.475 51.84 92.745 ;
     RECT  2.16 93.015 51.84 93.285 ;
     RECT  2.16 93.555 51.84 93.825 ;
     RECT  2.16 94.095 51.84 94.365 ;
     RECT  2.16 94.635 51.84 94.905 ;
     RECT  2.16 95.175 51.84 95.445 ;
     RECT  2.16 95.715 51.84 95.985 ;
     RECT  2.16 96.255 51.84 96.525 ;
     RECT  2.16 96.795 51.84 97.065 ;
     RECT  2.16 97.335 51.84 97.605 ;
     RECT  2.16 97.875 51.84 98.145 ;
     RECT  2.16 98.415 51.84 98.685 ;
     RECT  2.16 98.955 51.84 99.225 ;
     RECT  2.16 99.495 51.84 99.765 ;
     RECT  2.16 100.035 51.84 100.305 ;
     RECT  2.16 100.575 51.84 100.845 ;
     RECT  2.16 101.115 51.84 101.385 ;
    LAYER M1 ;
     RECT  2.16 2.151 51.84 101.529 ;
    LAYER M2 ;
     RECT  0.103 38.448 0.139 38.889 ;
     RECT  0.103 42.768 0.139 43.209 ;
     RECT  0.103 54.801 0.139 57.519 ;
     RECT  0.103 77.481 0.139 77.499 ;
     RECT  0.103 62.01 0.175 63.414 ;
     RECT  0.103 27.144 0.203 31.914 ;
     RECT  0.103 34.128 0.203 36.108 ;
     RECT  0.103 39.834 0.203 39.852 ;
     RECT  0.139 42.696 0.203 43.209 ;
     RECT  0.103 44.118 0.203 44.748 ;
     RECT  0.103 46.746 0.203 47.34 ;
     RECT  0.103 48.366 0.203 49.032 ;
     RECT  0.103 51.678 0.203 52.164 ;
     RECT  0.139 54.801 0.203 57.564 ;
     RECT  0.103 60.246 0.203 60.714 ;
     RECT  0.175 61.596 0.203 63.414 ;
     RECT  0.103 65.718 0.203 66.159 ;
     RECT  0.103 68.688 0.203 69.129 ;
     RECT  0.103 69.966 0.203 70.668 ;
     RECT  0.103 72.972 0.203 73.449 ;
     RECT  0.103 74.286 0.203 74.952 ;
     RECT  0.103 76.131 0.203 76.149 ;
     RECT  0.139 77.481 0.203 77.814 ;
     RECT  0.203 55.26 0.239 55.278 ;
     RECT  0.203 52.146 0.463 52.164 ;
     RECT  0.463 52.146 0.535 52.848 ;
     RECT  0.535 52.146 0.635 53.154 ;
     RECT  0.203 27.648 2.16 29.124 ;
     RECT  0.203 31.896 2.16 31.914 ;
     RECT  0.103 32.706 2.16 32.724 ;
     RECT  0.103 37.566 2.16 37.584 ;
     RECT  0.139 38.376 2.16 39.078 ;
     RECT  0.203 42.696 2.16 42.714 ;
     RECT  0.203 48.366 2.16 48.384 ;
     RECT  0.103 50.058 2.16 50.076 ;
     RECT  0.635 52.146 2.16 52.614 ;
     RECT  0.203 57.546 2.16 57.564 ;
     RECT  0.103 58.698 2.16 59.184 ;
     RECT  0.203 61.596 2.16 62.064 ;
     RECT  0.203 63.396 2.16 63.414 ;
     RECT  0.203 66.096 2.16 66.114 ;
     RECT  0.103 67.716 2.16 67.734 ;
     RECT  0.203 68.796 2.16 68.814 ;
     RECT  0.203 69.966 2.16 69.984 ;
     RECT  0.103 72.126 2.16 72.144 ;
     RECT  0.203 77.796 2.16 77.814 ;
     RECT  14.215 0.144 14.287 0.162 ;
     RECT  14.287 0.144 14.683 0.36 ;
     RECT  14.683 0.108 14.827 1.17 ;
     RECT  14.827 0.036 15.755 1.17 ;
     RECT  16.015 102.546 16.231 102.564 ;
     RECT  15.755 0.036 16.439 0.738 ;
     RECT  16.231 102.474 17.131 102.564 ;
     RECT  2.16 2.151 17.167 101.529 ;
     RECT  17.131 102.438 17.231 102.564 ;
     RECT  18.067 103.401 18.203 103.419 ;
     RECT  17.167 1.728 18.283 101.529 ;
     RECT  18.283 1.728 18.499 101.61 ;
     RECT  18.499 1.728 18.571 101.682 ;
     RECT  18.571 1.728 18.779 101.754 ;
     RECT  18.779 1.728 19.067 101.529 ;
     RECT  16.439 0.036 19.211 0.666 ;
     RECT  19.211 0.036 20.515 0.549 ;
     RECT  21.883 102.78 22.063 102.798 ;
     RECT  22.063 102.708 22.163 102.798 ;
     RECT  20.515 0.036 23.099 0.774 ;
     RECT  22.963 103.401 23.099 103.419 ;
     RECT  23.099 0.036 23.315 0.702 ;
     RECT  23.179 102.591 23.315 102.609 ;
     RECT  23.647 102.708 23.747 102.879 ;
     RECT  19.067 2.151 23.755 101.529 ;
     RECT  23.747 102.78 23.819 102.879 ;
     RECT  23.755 2.151 23.891 101.754 ;
     RECT  23.819 102.861 23.927 102.879 ;
     RECT  23.315 0.036 24.295 0.279 ;
     RECT  23.891 2.151 24.611 101.718 ;
     RECT  25.375 103.626 25.511 103.644 ;
     RECT  24.295 0.036 25.619 0.324 ;
     RECT  24.611 2.151 26.455 101.529 ;
     RECT  26.455 2.151 26.491 101.574 ;
     RECT  26.491 2.151 26.771 101.718 ;
     RECT  25.619 0.036 26.959 0.054 ;
     RECT  26.959 0.036 27.095 0.09 ;
     RECT  27.103 102.591 27.239 102.609 ;
     RECT  27.355 102.906 27.563 102.996 ;
     RECT  27.095 0.036 28.219 0.054 ;
     RECT  28.363 103.554 28.499 103.572 ;
     RECT  28.219 0.036 28.507 0.126 ;
     RECT  28.507 0.036 28.615 0.198 ;
     RECT  28.615 0.036 28.751 0.279 ;
     RECT  28.723 103.626 28.859 103.644 ;
     RECT  26.771 2.151 29.263 101.529 ;
     RECT  29.119 102.321 29.263 102.339 ;
     RECT  29.263 2.151 29.435 102.339 ;
     RECT  29.435 2.151 29.551 101.529 ;
     RECT  29.551 1.53 29.695 101.529 ;
     RECT  28.751 0.036 29.911 0.198 ;
     RECT  29.695 1.494 29.911 101.529 ;
     RECT  29.839 103.626 29.975 103.644 ;
     RECT  29.435 102.276 30.199 102.339 ;
     RECT  30.703 103.626 30.739 103.644 ;
     RECT  30.739 103.554 30.839 103.644 ;
     RECT  29.911 0.036 31.379 101.529 ;
     RECT  30.199 102.276 31.639 102.564 ;
     RECT  31.639 102.276 31.775 102.726 ;
     RECT  31.379 0.108 32.287 101.529 ;
     RECT  32.287 0.036 32.495 101.529 ;
     RECT  32.683 103.518 32.819 103.536 ;
     RECT  31.775 102.276 33.071 102.564 ;
     RECT  32.935 103.446 33.071 103.464 ;
     RECT  33.071 102.438 33.187 102.564 ;
     RECT  32.495 0.18 33.223 101.529 ;
     RECT  33.187 102.438 33.395 102.609 ;
     RECT  33.223 0.036 33.431 101.529 ;
     RECT  33.395 102.51 33.467 102.609 ;
     RECT  33.467 102.546 33.575 102.609 ;
     RECT  33.655 103.554 33.907 103.572 ;
     RECT  33.907 103.554 34.043 103.644 ;
     RECT  33.431 0.036 34.375 0.054 ;
     RECT  33.431 0.846 34.375 101.529 ;
     RECT  33.575 102.546 34.375 102.564 ;
     RECT  34.375 102.474 34.447 102.564 ;
     RECT  34.447 102.474 34.583 102.609 ;
     RECT  34.375 0.036 35.159 101.529 ;
     RECT  34.583 102.474 35.167 102.564 ;
     RECT  35.167 102.438 35.455 102.564 ;
     RECT  35.455 102.402 35.671 102.564 ;
     RECT  35.671 102.402 35.771 102.609 ;
     RECT  35.771 102.474 35.807 102.609 ;
     RECT  35.159 0.18 35.959 101.529 ;
     RECT  35.959 0.144 36.355 101.529 ;
     RECT  35.807 102.474 36.383 102.564 ;
     RECT  36.383 102.474 36.455 102.492 ;
     RECT  36.355 0.036 38.227 101.529 ;
     RECT  38.227 0.036 38.363 101.718 ;
     RECT  38.363 0.036 38.651 101.529 ;
     RECT  38.651 0.216 39.551 101.529 ;
     RECT  39.551 0.684 40.595 101.529 ;
     RECT  40.595 0.846 40.703 101.529 ;
     RECT  40.703 1.422 40.775 101.529 ;
     RECT  40.775 1.998 41.063 101.529 ;
     RECT  41.063 2.07 41.135 101.529 ;
     RECT  41.135 2.151 51.84 101.529 ;
    LAYER M3 ;
     RECT  14.94 0.012 38.502 0.031 ;
     RECT  14.832 0.031 38.646 0.103 ;
     RECT  14.688 0.103 38.646 0.139 ;
     RECT  39.708 0.043 39.726 0.211 ;
     RECT  14.22 0.139 38.646 0.256 ;
     RECT  39.528 0.211 39.726 0.256 ;
     RECT  40.572 0.679 40.59 0.841 ;
     RECT  40.572 0.841 40.698 1.387 ;
     RECT  40.536 1.387 40.698 1.417 ;
     RECT  14.22 0.256 39.726 1.483 ;
     RECT  40.536 1.417 40.77 1.483 ;
     RECT  14.22 1.483 40.77 1.993 ;
     RECT  14.22 1.993 41.058 2.065 ;
     RECT  2.415 2.143 2.505 2.413 ;
     RECT  7.815 2.143 7.905 2.413 ;
     RECT  13.215 2.143 13.305 2.413 ;
     RECT  45.615 2.143 45.705 2.413 ;
     RECT  51.015 2.143 51.105 2.413 ;
     RECT  13.215 2.413 13.497 26.905 ;
     RECT  14.22 2.065 41.13 26.905 ;
     RECT  2.415 2.413 2.697 26.923 ;
     RECT  11.412 26.923 11.43 26.941 ;
     RECT  2.304 26.923 2.697 26.969 ;
     RECT  0.108 27.019 0.126 27.067 ;
     RECT  11.412 26.941 11.97 27.149 ;
     RECT  2.415 26.969 2.697 27.301 ;
     RECT  13.215 26.905 41.13 27.365 ;
     RECT  11.412 27.149 11.43 27.509 ;
     RECT  0.108 27.067 0.198 27.643 ;
     RECT  2.415 27.301 2.79 27.779 ;
     RECT  0.108 27.643 0.558 28.183 ;
     RECT  0.108 28.183 1.134 28.301 ;
     RECT  11.412 28.381 11.43 28.493 ;
     RECT  2.415 27.779 2.697 28.552 ;
     RECT  1.116 28.301 1.134 28.685 ;
     RECT  10.836 28.555 10.854 28.733 ;
     RECT  13.215 27.365 13.497 29.065 ;
     RECT  13.104 29.065 13.497 29.117 ;
     RECT  2.304 28.552 2.697 29.165 ;
     RECT  0.108 28.301 0.126 29.275 ;
     RECT  0.108 29.275 0.162 29.452 ;
     RECT  13.215 29.117 13.497 30.139 ;
     RECT  2.415 29.165 2.697 30.271 ;
     RECT  10.872 30.283 10.89 30.307 ;
     RECT  2.304 30.271 2.697 30.317 ;
     RECT  13.104 30.139 13.497 30.451 ;
     RECT  14.22 27.365 41.13 30.451 ;
     RECT  11.664 30.427 11.682 30.569 ;
     RECT  11.808 30.571 11.826 30.667 ;
     RECT  7.815 2.413 8.097 30.811 ;
     RECT  11.808 30.667 11.934 30.811 ;
     RECT  13.104 30.451 41.13 30.811 ;
     RECT  11.808 30.811 41.13 30.839 ;
     RECT  10.836 30.307 10.89 30.847 ;
     RECT  11.916 30.839 41.13 30.848 ;
     RECT  10.728 30.847 10.926 30.946 ;
     RECT  6.84 30.811 6.858 30.955 ;
     RECT  7.815 30.811 8.226 30.955 ;
     RECT  10.728 30.946 10.962 30.983 ;
     RECT  6.84 30.955 8.226 30.991 ;
     RECT  11.952 30.848 41.13 31.019 ;
     RECT  6.768 30.991 8.226 31.109 ;
     RECT  6.768 31.109 6.93 31.145 ;
     RECT  6.84 31.145 6.93 31.181 ;
     RECT  2.415 30.317 2.697 31.243 ;
     RECT  2.304 31.243 2.697 31.289 ;
     RECT  10.836 30.983 10.962 31.289 ;
     RECT  3.996 31.099 4.014 31.379 ;
     RECT  7.704 31.109 8.226 31.423 ;
     RECT  0.108 29.452 0.198 31.517 ;
     RECT  7.704 31.423 8.73 31.523 ;
     RECT  5.148 31.483 5.166 31.627 ;
     RECT  5.148 31.627 5.202 31.649 ;
     RECT  6.84 31.181 6.858 31.649 ;
     RECT  5.184 31.649 5.202 31.829 ;
     RECT  12.24 31.019 41.13 31.829 ;
     RECT  0.108 31.517 0.126 31.919 ;
     RECT  9.504 31.801 9.522 31.919 ;
     RECT  10.836 31.289 10.926 31.927 ;
     RECT  10.512 31.927 10.926 32.035 ;
     RECT  2.415 31.289 2.697 32.059 ;
     RECT  2.415 32.059 2.79 32.099 ;
     RECT  12.708 31.829 41.13 32.099 ;
     RECT  10.008 32.035 10.926 32.195 ;
     RECT  7.815 31.523 8.73 32.197 ;
     RECT  10.08 32.195 10.926 32.225 ;
     RECT  2.415 32.099 2.754 32.395 ;
     RECT  7.815 32.197 9.234 32.431 ;
     RECT  7.704 32.431 9.234 32.459 ;
     RECT  7.704 32.459 8.946 32.477 ;
     RECT  7.815 32.477 8.946 32.495 ;
     RECT  10.62 32.225 10.926 32.495 ;
     RECT  10.836 32.495 10.926 32.587 ;
     RECT  0.108 32.683 0.126 32.729 ;
     RECT  13.215 32.099 41.13 32.845 ;
     RECT  2.304 32.395 2.754 32.909 ;
     RECT  13.104 32.845 41.13 32.909 ;
     RECT  10.836 32.587 11.43 33.019 ;
     RECT  7.815 32.495 8.097 33.277 ;
     RECT  7.815 33.277 8.55 33.307 ;
     RECT  7.704 33.307 8.55 33.341 ;
     RECT  9.9 33.115 9.918 33.349 ;
     RECT  10.836 33.019 11.934 33.349 ;
     RECT  7.704 33.341 8.262 33.437 ;
     RECT  2.304 32.909 2.697 33.485 ;
     RECT  9.9 33.349 11.934 33.575 ;
     RECT  9.9 33.575 11.682 33.655 ;
     RECT  13.215 32.909 41.13 33.719 ;
     RECT  2.415 33.485 2.697 33.781 ;
     RECT  2.415 33.781 2.79 33.821 ;
     RECT  9.576 33.655 11.682 33.845 ;
     RECT  10.08 33.845 11.682 34.079 ;
     RECT  10.08 34.079 11.61 34.115 ;
     RECT  10.188 34.115 11.61 34.205 ;
     RECT  7.815 33.437 8.262 34.231 ;
     RECT  10.764 34.205 11.61 34.349 ;
     RECT  7.815 34.231 8.802 34.385 ;
     RECT  10.764 34.349 11.502 34.385 ;
     RECT  10.764 34.385 11.286 34.493 ;
     RECT  2.415 33.821 2.697 34.591 ;
     RECT  7.815 34.385 8.55 34.603 ;
     RECT  10.908 34.493 11.286 34.619 ;
     RECT  7.704 34.603 8.55 34.699 ;
     RECT  7.416 34.699 8.55 34.733 ;
     RECT  10.908 34.619 11.25 34.763 ;
     RECT  13.215 33.719 13.497 35.131 ;
     RECT  14.22 33.719 41.13 35.131 ;
     RECT  9.54 35.005 9.558 35.159 ;
     RECT  9.432 35.167 9.45 35.339 ;
     RECT  7.416 34.733 8.478 35.467 ;
     RECT  13.215 35.131 41.13 35.537 ;
     RECT  10.908 34.763 10.926 35.581 ;
     RECT  2.304 34.591 2.697 35.609 ;
     RECT  7.416 35.467 8.55 35.699 ;
     RECT  10.908 35.581 10.962 35.743 ;
     RECT  10.908 35.743 11.034 35.941 ;
     RECT  7.416 35.699 8.097 35.969 ;
     RECT  10.8 35.941 11.43 36.041 ;
     RECT  12.24 35.941 12.258 36.041 ;
     RECT  10.836 36.041 11.43 36.043 ;
     RECT  0.108 34.108 0.198 36.113 ;
     RECT  10.836 36.043 11.466 36.235 ;
     RECT  7.488 35.969 8.097 36.239 ;
     RECT  0.324 36.139 0.342 36.269 ;
     RECT  10.836 36.235 11.97 36.347 ;
     RECT  2.415 35.609 2.697 36.379 ;
     RECT  10.836 36.347 11.394 36.413 ;
     RECT  2.415 36.379 2.79 36.419 ;
     RECT  2.415 36.419 2.697 36.715 ;
     RECT  13.215 35.537 13.497 36.751 ;
     RECT  13.104 36.751 13.497 36.797 ;
     RECT  0.144 36.859 0.162 37.037 ;
     RECT  11.304 36.413 11.394 37.325 ;
     RECT  0.108 37.483 0.126 37.589 ;
     RECT  2.304 36.715 2.697 37.805 ;
     RECT  13.215 36.797 13.497 37.963 ;
     RECT  2.415 37.805 2.697 38.101 ;
     RECT  11.412 37.723 11.43 38.129 ;
     RECT  2.415 38.101 2.79 38.141 ;
     RECT  13.104 37.963 13.497 38.251 ;
     RECT  14.22 35.537 41.13 38.251 ;
     RECT  0.144 38.347 0.162 38.428 ;
     RECT  2.415 38.141 2.697 38.911 ;
     RECT  13.104 38.251 41.13 38.939 ;
     RECT  10.944 38.923 10.962 38.983 ;
     RECT  13.14 38.939 41.13 39.047 ;
     RECT  10.944 38.983 11.43 39.055 ;
     RECT  10.944 39.055 11.646 39.115 ;
     RECT  7.815 36.239 8.097 39.307 ;
     RECT  10.944 39.115 11.682 39.361 ;
     RECT  2.304 38.911 2.697 39.437 ;
     RECT  10.692 39.361 11.682 39.479 ;
     RECT  7.416 39.307 8.097 39.499 ;
     RECT  10.836 39.479 11.682 39.631 ;
     RECT  0.108 38.428 0.198 39.857 ;
     RECT  2.415 39.437 2.697 39.883 ;
     RECT  13.14 39.047 13.497 39.901 ;
     RECT  7.416 39.499 8.154 39.929 ;
     RECT  0.144 39.857 0.198 39.979 ;
     RECT  2.415 39.883 2.862 40.027 ;
     RECT  10.836 39.631 11.97 40.027 ;
     RECT  2.415 40.027 2.97 40.123 ;
     RECT  10.836 40.027 12.222 40.135 ;
     RECT  13.104 39.901 13.497 40.135 ;
     RECT  0.144 39.979 0.234 40.157 ;
     RECT  2.415 40.123 3.078 40.199 ;
     RECT  7.704 39.929 8.154 40.199 ;
     RECT  7.815 40.199 8.154 40.289 ;
     RECT  10.836 40.135 13.497 40.289 ;
     RECT  11.412 40.289 13.497 40.469 ;
     RECT  11.412 40.469 12.186 40.589 ;
     RECT  0.144 40.157 0.162 40.637 ;
     RECT  2.415 40.199 2.79 40.739 ;
     RECT  11.412 40.589 11.97 40.739 ;
     RECT  12.996 40.469 13.497 40.973 ;
     RECT  2.415 40.739 2.697 41.035 ;
     RECT  13.176 40.973 13.497 41.179 ;
     RECT  14.22 39.047 41.13 41.179 ;
     RECT  13.176 41.179 41.13 41.719 ;
     RECT  12.888 41.719 41.13 41.791 ;
     RECT  12.816 41.791 41.13 41.945 ;
     RECT  11.412 40.739 11.934 42.017 ;
     RECT  11.412 42.017 11.466 42.089 ;
     RECT  2.304 41.035 2.697 42.125 ;
     RECT  11.448 42.089 11.466 42.179 ;
     RECT  13.032 41.945 41.13 42.215 ;
     RECT  2.415 42.125 2.697 42.421 ;
     RECT  2.415 42.421 2.79 42.461 ;
     RECT  0.144 42.667 0.162 42.748 ;
     RECT  7.815 40.289 8.097 42.763 ;
     RECT  7.815 42.763 8.19 42.871 ;
     RECT  13.104 42.215 41.13 42.899 ;
     RECT  7.815 42.871 8.406 42.961 ;
     RECT  10.836 42.961 10.854 43.033 ;
     RECT  7.344 42.961 8.406 43.037 ;
     RECT  10.368 43.033 10.854 43.133 ;
     RECT  2.415 42.461 2.697 43.231 ;
     RECT  10.44 43.133 10.854 43.295 ;
     RECT  13.104 42.899 13.497 43.295 ;
     RECT  10.584 43.295 10.854 43.325 ;
     RECT  7.704 43.037 8.406 43.375 ;
     RECT  10.62 43.325 10.854 43.375 ;
     RECT  7.704 43.375 8.514 43.411 ;
     RECT  7.704 43.411 8.586 43.501 ;
     RECT  10.62 43.375 10.926 43.501 ;
     RECT  9.684 43.375 9.702 43.529 ;
     RECT  7.704 43.501 8.658 43.661 ;
     RECT  7.704 43.661 8.154 43.799 ;
     RECT  10.62 43.501 10.962 43.951 ;
     RECT  10.62 43.951 11.322 44.041 ;
     RECT  6.84 44.155 6.858 44.203 ;
     RECT  10.62 44.041 11.61 44.221 ;
     RECT  2.304 43.231 2.697 44.249 ;
     RECT  10.548 44.221 11.61 44.249 ;
     RECT  13.215 43.295 13.497 44.311 ;
     RECT  10.548 44.249 11.43 44.375 ;
     RECT  6.84 44.203 7.038 44.381 ;
     RECT  12.564 44.311 13.497 44.383 ;
     RECT  14.22 42.899 41.13 44.383 ;
     RECT  9.144 44.059 9.198 44.447 ;
     RECT  12.564 44.383 41.13 44.483 ;
     RECT  12.564 44.483 13.497 44.587 ;
     RECT  9.18 44.447 9.198 44.609 ;
     RECT  0.108 42.748 0.198 44.753 ;
     RECT  7.815 43.799 8.154 44.789 ;
     RECT  7.815 44.789 8.097 44.923 ;
     RECT  7.416 44.923 8.097 45.149 ;
     RECT  11.268 44.375 11.43 45.185 ;
     RECT  0.144 44.753 0.162 45.245 ;
     RECT  11.412 45.185 11.43 45.259 ;
     RECT  12.528 44.587 13.497 45.259 ;
     RECT  11.412 45.259 13.497 45.419 ;
     RECT  12.78 45.419 13.497 45.689 ;
     RECT  11.52 45.419 11.718 46.201 ;
     RECT  2.415 44.249 2.697 46.381 ;
     RECT  2.304 46.381 2.697 46.445 ;
     RECT  3.996 46.507 4.014 46.555 ;
     RECT  3.996 46.555 4.086 46.603 ;
     RECT  13.032 45.689 13.497 46.615 ;
     RECT  14.22 44.483 41.13 46.615 ;
     RECT  10.296 46.381 10.314 46.651 ;
     RECT  11.52 46.201 11.79 46.651 ;
     RECT  0.144 46.555 0.162 46.732 ;
     RECT  7.815 45.149 8.097 46.741 ;
     RECT  10.26 46.651 11.79 46.741 ;
     RECT  10.26 46.741 11.898 46.805 ;
     RECT  9.144 45.211 9.162 46.813 ;
     RECT  10.404 46.805 11.898 46.849 ;
     RECT  13.032 46.615 41.13 46.849 ;
     RECT  10.404 46.849 41.13 46.877 ;
     RECT  3.996 46.603 4.554 46.949 ;
     RECT  3.996 46.949 4.014 47.039 ;
     RECT  10.404 46.877 10.422 47.147 ;
     RECT  11.16 46.877 41.13 47.147 ;
     RECT  7.416 46.741 8.097 47.179 ;
     RECT  7.056 47.179 8.097 47.371 ;
     RECT  0.108 46.732 0.198 47.453 ;
     RECT  8.964 46.813 9.162 47.461 ;
     RECT  11.484 47.147 41.13 47.489 ;
     RECT  0.108 47.453 0.126 47.501 ;
     RECT  2.415 46.445 2.697 47.551 ;
     RECT  5.148 47.083 5.166 47.551 ;
     RECT  8.964 47.461 9.234 47.551 ;
     RECT  5.148 47.551 5.202 47.597 ;
     RECT  11.88 47.489 41.13 47.693 ;
     RECT  6.84 47.371 8.097 47.695 ;
     RECT  8.964 47.551 9.954 47.695 ;
     RECT  12.132 47.693 41.13 47.723 ;
     RECT  6.84 47.695 9.954 47.731 ;
     RECT  6.192 47.731 9.954 47.849 ;
     RECT  6.192 47.849 6.21 47.885 ;
     RECT  7.344 47.849 9.954 47.885 ;
     RECT  12.168 47.723 41.13 47.885 ;
     RECT  7.416 47.885 8.982 48.119 ;
     RECT  10.764 47.965 10.854 48.227 ;
     RECT  10.764 48.227 10.782 48.263 ;
     RECT  9.756 47.885 9.954 48.271 ;
     RECT  5.148 47.597 5.166 48.299 ;
     RECT  7.452 48.119 8.406 48.299 ;
     RECT  0.108 48.331 0.126 48.433 ;
     RECT  2.304 47.551 2.697 48.569 ;
     RECT  9.756 48.271 9.99 48.703 ;
     RECT  7.704 48.299 8.406 48.839 ;
     RECT  13.215 47.885 41.13 48.901 ;
     RECT  7.815 48.839 8.406 48.955 ;
     RECT  9.324 48.703 10.206 48.965 ;
     RECT  6.948 48.907 6.966 49.003 ;
     RECT  7.815 48.955 8.586 49.003 ;
     RECT  9.324 48.965 9.99 49.003 ;
     RECT  12.564 48.901 41.13 49.009 ;
     RECT  0.108 48.433 0.198 49.085 ;
     RECT  0.108 49.085 0.126 49.133 ;
     RECT  1.116 49.003 1.134 49.181 ;
     RECT  7.815 49.003 9.99 49.271 ;
     RECT  10.728 49.081 10.89 49.291 ;
     RECT  11.952 49.009 41.13 49.291 ;
     RECT  2.415 48.569 2.697 49.339 ;
     RECT  2.415 49.339 2.79 49.379 ;
     RECT  3.96 49.441 3.978 49.613 ;
     RECT  6.84 49.003 6.966 49.621 ;
     RECT  2.415 49.379 2.697 49.675 ;
     RECT  4.428 49.621 4.554 49.757 ;
     RECT  9.144 49.271 9.99 49.783 ;
     RECT  10.728 49.291 41.13 49.783 ;
     RECT  5.904 49.855 5.922 49.891 ;
     RECT  6.84 49.621 7.038 49.891 ;
     RECT  6.84 49.891 7.074 49.981 ;
     RECT  7.815 49.271 8.406 49.981 ;
     RECT  0.252 49.963 0.27 50.044 ;
     RECT  0.108 50.044 0.27 50.081 ;
     RECT  4.428 49.757 4.482 50.093 ;
     RECT  4.464 50.093 4.482 50.117 ;
     RECT  6.768 49.981 8.406 50.125 ;
     RECT  9.144 49.783 41.13 50.125 ;
     RECT  6.768 50.125 41.13 50.161 ;
     RECT  6.732 50.161 41.13 50.279 ;
     RECT  0.108 50.081 0.198 50.285 ;
     RECT  0.18 50.285 0.198 50.333 ;
     RECT  5.364 49.891 5.922 50.347 ;
     RECT  6.732 50.279 11.106 50.347 ;
     RECT  5.364 50.347 11.106 50.521 ;
     RECT  2.304 49.675 2.697 50.665 ;
     RECT  2.304 50.665 3.402 50.728 ;
     RECT  2.268 50.728 3.402 50.819 ;
     RECT  4.536 50.521 11.106 50.923 ;
     RECT  4.32 50.923 11.106 51.241 ;
     RECT  11.844 50.279 41.13 51.241 ;
     RECT  4.32 51.241 41.13 51.307 ;
     RECT  3.996 51.307 41.13 51.359 ;
     RECT  0.144 51.403 0.162 51.673 ;
     RECT  4.14 51.359 41.13 51.773 ;
     RECT  6.084 51.773 41.13 51.809 ;
     RECT  4.14 51.773 5.202 51.899 ;
     RECT  2.304 50.819 2.697 51.917 ;
     RECT  0.108 51.673 0.198 52.169 ;
     RECT  4.14 51.899 5.022 52.411 ;
     RECT  6.192 51.809 41.13 52.439 ;
     RECT  2.415 51.917 2.697 52.555 ;
     RECT  3.42 52.411 5.022 52.555 ;
     RECT  6.192 52.439 12.402 52.555 ;
     RECT  6.12 52.555 12.402 52.591 ;
     RECT  2.415 52.555 5.022 52.651 ;
     RECT  2.304 52.651 5.022 52.843 ;
     RECT  2.268 52.843 5.022 52.861 ;
     RECT  2.232 52.861 5.022 52.973 ;
     RECT  2.268 52.973 5.022 52.979 ;
     RECT  2.304 52.979 5.022 52.987 ;
     RECT  5.76 52.591 12.402 52.987 ;
     RECT  2.304 52.987 12.402 53.069 ;
     RECT  0.468 52.411 0.558 53.083 ;
     RECT  0.468 53.083 0.63 53.159 ;
     RECT  0.468 53.159 0.558 53.168 ;
     RECT  11.196 53.069 12.402 53.179 ;
     RECT  13.14 52.439 41.13 53.179 ;
     RECT  0.144 53.371 0.162 53.549 ;
     RECT  2.304 53.069 10.35 53.555 ;
     RECT  3.996 53.555 10.35 53.797 ;
     RECT  11.196 53.179 41.13 53.797 ;
     RECT  2.304 53.555 2.862 54.329 ;
     RECT  3.996 53.797 41.13 54.509 ;
     RECT  8.964 54.509 41.13 54.599 ;
     RECT  9 54.599 41.13 54.749 ;
     RECT  0.144 54.283 0.162 54.796 ;
     RECT  9 54.749 11.61 54.905 ;
     RECT  3.996 54.509 8.097 55.049 ;
     RECT  2.304 54.329 2.697 55.085 ;
     RECT  5.148 55.049 8.097 55.139 ;
     RECT  9.036 54.905 11.61 55.139 ;
     RECT  5.148 55.139 5.346 55.175 ;
     RECT  6.624 55.139 8.097 55.175 ;
     RECT  9.036 55.139 9.234 55.181 ;
     RECT  0.108 54.796 0.198 55.255 ;
     RECT  9.036 55.181 9.162 55.283 ;
     RECT  10.26 55.139 11.61 55.283 ;
     RECT  12.456 54.749 41.13 55.283 ;
     RECT  2.415 55.085 2.697 55.381 ;
     RECT  6.768 55.175 8.097 55.409 ;
     RECT  9.036 55.283 9.054 55.409 ;
     RECT  2.415 55.381 2.79 55.421 ;
     RECT  6.84 55.409 8.097 55.481 ;
     RECT  10.62 55.283 11.61 55.561 ;
     RECT  6.84 55.481 6.966 55.589 ;
     RECT  12.708 55.283 41.13 55.589 ;
     RECT  7.815 55.481 8.097 55.651 ;
     RECT  6.948 55.589 6.966 55.679 ;
     RECT  0.108 55.255 0.234 55.709 ;
     RECT  12.708 55.589 13.497 55.715 ;
     RECT  10.62 55.561 11.934 55.787 ;
     RECT  10.62 55.787 11.718 55.823 ;
     RECT  12.852 55.715 13.497 55.823 ;
     RECT  7.815 55.651 8.262 55.921 ;
     RECT  3.996 55.049 4.05 55.985 ;
     RECT  7.815 55.921 8.55 55.997 ;
     RECT  4.032 55.985 4.05 56.021 ;
     RECT  2.415 55.421 2.697 56.191 ;
     RECT  10.8 55.823 11.718 56.569 ;
     RECT  7.815 55.997 8.226 56.632 ;
     RECT  7.704 56.632 8.226 56.669 ;
     RECT  9.936 56.641 9.954 56.759 ;
     RECT  7.815 56.669 8.226 56.827 ;
     RECT  10.8 56.569 11.97 56.867 ;
     RECT  9.36 56.839 9.378 56.939 ;
     RECT  7.815 56.827 8.55 57.001 ;
     RECT  7.815 57.001 9.27 57.101 ;
     RECT  10.728 57.001 10.746 57.101 ;
     RECT  13.215 55.823 13.497 57.109 ;
     RECT  6.84 57.115 6.858 57.163 ;
     RECT  2.304 56.191 2.697 57.209 ;
     RECT  7.815 57.101 8.154 57.209 ;
     RECT  11.484 56.867 11.97 57.271 ;
     RECT  6.84 57.163 6.966 57.341 ;
     RECT  13.176 57.109 13.497 57.343 ;
     RECT  11.484 57.271 12.006 57.649 ;
     RECT  13.104 57.343 13.497 57.649 ;
     RECT  11.484 57.649 13.497 57.721 ;
     RECT  0.108 55.709 0.198 57.725 ;
     RECT  0.108 57.725 0.126 57.773 ;
     RECT  11.016 57.721 13.497 57.847 ;
     RECT  10.62 57.847 13.497 57.919 ;
     RECT  9.144 57.101 9.27 57.947 ;
     RECT  2.415 57.209 2.697 57.979 ;
     RECT  10.296 57.919 13.497 57.991 ;
     RECT  6.84 57.341 6.858 58.013 ;
     RECT  2.415 57.979 2.79 58.019 ;
     RECT  7.815 57.209 8.097 58.123 ;
     RECT  10.188 57.991 13.497 58.145 ;
     RECT  2.415 58.019 2.697 58.315 ;
     RECT  10.872 58.145 13.497 58.523 ;
     RECT  10.872 58.523 12.006 58.559 ;
     RECT  7.815 58.123 8.55 58.649 ;
     RECT  13.104 58.523 13.497 58.765 ;
     RECT  14.22 55.589 41.13 58.765 ;
     RECT  10.872 58.559 10.926 58.891 ;
     RECT  8.82 58.693 8.838 58.919 ;
     RECT  10.836 58.891 10.926 59.027 ;
     RECT  10.836 59.027 10.854 59.063 ;
     RECT  0.108 58.603 0.126 59.189 ;
     RECT  13.104 58.765 41.13 59.323 ;
     RECT  2.304 58.315 2.697 59.405 ;
     RECT  13.068 59.323 41.13 59.539 ;
     RECT  11.988 58.559 12.006 59.563 ;
     RECT  12.888 59.539 41.13 59.563 ;
     RECT  11.988 59.563 41.13 59.567 ;
     RECT  12.204 59.567 41.13 59.729 ;
     RECT  7.815 58.649 8.097 60.007 ;
     RECT  7.815 60.007 8.55 60.077 ;
     RECT  0.144 59.515 0.162 60.232 ;
     RECT  0.108 60.232 0.162 60.241 ;
     RECT  7.815 60.077 8.097 60.331 ;
     RECT  12.456 59.729 41.13 60.341 ;
     RECT  0.108 60.241 0.198 60.427 ;
     RECT  11.376 59.755 11.394 60.547 ;
     RECT  10.836 60.547 11.394 60.571 ;
     RECT  7.416 60.331 8.097 60.575 ;
     RECT  0.108 60.427 0.234 60.605 ;
     RECT  10.836 60.571 11.43 60.667 ;
     RECT  0.108 60.605 0.198 60.719 ;
     RECT  10.836 60.667 11.466 60.719 ;
     RECT  12.456 60.341 13.497 60.719 ;
     RECT  10.944 60.719 11.466 60.809 ;
     RECT  2.415 59.405 2.697 61.003 ;
     RECT  10.944 60.809 10.962 61.181 ;
     RECT  7.815 60.575 8.097 61.483 ;
     RECT  11.916 60.811 12.078 61.501 ;
     RECT  13.104 60.719 13.497 61.501 ;
     RECT  2.304 61.003 2.697 61.529 ;
     RECT  0.108 60.719 0.162 61.579 ;
     RECT  7.704 61.483 8.097 61.675 ;
     RECT  11.916 61.501 13.497 61.735 ;
     RECT  7.704 61.675 8.55 61.799 ;
     RECT  7.704 61.799 8.262 61.963 ;
     RECT  7.416 61.963 8.262 62.131 ;
     RECT  7.272 62.131 8.262 62.167 ;
     RECT  11.232 61.735 13.497 62.203 ;
     RECT  14.22 60.341 41.13 62.203 ;
     RECT  2.415 61.529 2.697 62.299 ;
     RECT  7.164 62.167 8.262 62.299 ;
     RECT  2.415 62.299 2.79 62.339 ;
     RECT  7.056 62.299 8.262 62.339 ;
     RECT  9.072 62.167 9.09 62.401 ;
     RECT  5.148 62.131 5.166 62.429 ;
     RECT  7.815 62.339 8.262 62.539 ;
     RECT  9.072 62.401 9.198 62.573 ;
     RECT  11.232 62.203 41.13 62.735 ;
     RECT  3.996 62.041 4.014 62.765 ;
     RECT  11.844 62.735 41.13 62.807 ;
     RECT  7.056 62.339 7.074 62.827 ;
     RECT  6.912 62.827 7.074 62.851 ;
     RECT  10.908 62.743 10.998 62.851 ;
     RECT  7.815 62.539 8.334 62.941 ;
     RECT  9.072 62.573 9.162 62.941 ;
     RECT  10.836 62.851 10.998 62.941 ;
     RECT  12.024 62.807 41.13 62.969 ;
     RECT  0.108 61.579 0.198 63.005 ;
     RECT  10.8 62.941 10.998 63.013 ;
     RECT  12.06 62.969 41.13 63.041 ;
     RECT  7.815 62.941 9.162 63.053 ;
     RECT  2.415 62.339 2.697 63.112 ;
     RECT  10.728 63.013 10.998 63.113 ;
     RECT  6.768 62.851 7.074 63.115 ;
     RECT  7.815 63.053 8.334 63.115 ;
     RECT  6.768 63.115 8.334 63.275 ;
     RECT  0.108 63.005 0.126 63.437 ;
     RECT  10.8 63.113 10.998 63.481 ;
     RECT  5.148 63.307 5.166 63.509 ;
     RECT  9.108 63.053 9.162 63.517 ;
     RECT  9.108 63.517 9.45 63.617 ;
     RECT  10.8 63.481 11.034 63.617 ;
     RECT  10.8 63.617 10.962 63.689 ;
     RECT  2.304 63.112 2.697 63.725 ;
     RECT  6.84 63.275 8.334 63.779 ;
     RECT  9.108 63.617 9.126 63.815 ;
     RECT  12.24 63.041 41.13 63.815 ;
     RECT  7.416 63.779 8.334 63.821 ;
     RECT  2.415 63.725 2.697 64.021 ;
     RECT  7.416 63.821 8.154 64.049 ;
     RECT  2.415 64.021 2.79 64.061 ;
     RECT  10.836 63.689 10.962 64.319 ;
     RECT  11.736 63.895 11.898 64.319 ;
     RECT  13.104 63.815 41.13 64.319 ;
     RECT  10.944 64.319 10.962 64.355 ;
     RECT  11.736 64.319 11.754 64.355 ;
     RECT  7.416 64.049 8.097 64.589 ;
     RECT  11.052 64.363 11.61 64.625 ;
     RECT  11.592 64.625 11.61 64.859 ;
     RECT  14.22 64.319 41.13 65.129 ;
     RECT  2.415 64.061 2.697 65.281 ;
     RECT  7.704 64.589 8.097 65.371 ;
     RECT  10.836 65.407 10.854 65.551 ;
     RECT  13.104 64.319 13.497 65.669 ;
     RECT  10.836 65.551 11.106 65.705 ;
     RECT  0.18 65.467 0.198 65.713 ;
     RECT  2.304 65.281 2.697 65.849 ;
     RECT  10.836 65.705 11.07 65.947 ;
     RECT  10.8 65.947 11.07 65.983 ;
     RECT  7.704 65.371 8.406 65.995 ;
     RECT  7.704 65.995 8.442 66.091 ;
     RECT  10.728 65.983 11.07 66.253 ;
     RECT  10.692 66.253 11.07 66.325 ;
     RECT  7.416 66.091 8.442 66.331 ;
     RECT  0.108 65.713 0.198 66.365 ;
     RECT  0.108 66.365 0.126 66.413 ;
     RECT  13.176 65.669 13.497 66.451 ;
     RECT  14.22 65.129 41.094 66.451 ;
     RECT  7.272 66.331 8.442 66.479 ;
     RECT  2.415 65.849 2.697 66.619 ;
     RECT  2.415 66.619 2.79 66.659 ;
     RECT  13.176 66.451 41.094 66.721 ;
     RECT  3.996 66.571 4.014 66.749 ;
     RECT  7.416 66.479 8.442 66.757 ;
     RECT  10.62 66.325 11.07 66.757 ;
     RECT  13.14 66.721 41.094 66.757 ;
     RECT  10.26 66.757 11.07 66.829 ;
     RECT  12.204 66.757 12.222 66.829 ;
     RECT  13.068 66.757 41.094 66.829 ;
     RECT  10.116 66.829 11.07 66.901 ;
     RECT  12.168 66.829 41.094 66.929 ;
     RECT  2.415 66.659 2.697 66.955 ;
     RECT  10.116 66.901 11.286 66.991 ;
     RECT  12.168 66.929 41.058 67.051 ;
     RECT  7.416 66.757 8.55 67.085 ;
     RECT  10.116 66.991 11.358 67.085 ;
     RECT  12.132 67.051 41.058 67.127 ;
     RECT  10.116 67.085 11.106 67.163 ;
     RECT  12.384 67.127 41.058 67.163 ;
     RECT  6.228 66.865 6.246 67.199 ;
     RECT  12.42 67.163 41.058 67.199 ;
     RECT  7.416 67.085 8.19 67.387 ;
     RECT  6.84 67.387 8.19 67.559 ;
     RECT  9.324 67.441 9.342 67.595 ;
     RECT  0.108 67.243 0.126 67.739 ;
     RECT  7.815 67.559 8.19 67.867 ;
     RECT  10.764 67.163 11.106 67.945 ;
     RECT  2.304 66.955 2.697 68.045 ;
     RECT  10.728 67.945 11.106 68.071 ;
     RECT  10.476 68.071 11.106 68.107 ;
     RECT  13.104 67.199 41.058 68.107 ;
     RECT  9.54 67.981 9.558 68.135 ;
     RECT  6.84 67.559 7.038 68.141 ;
     RECT  10.476 68.107 11.394 68.141 ;
     RECT  12.672 68.107 41.058 68.215 ;
     RECT  6.84 68.141 6.966 68.237 ;
     RECT  7.815 67.867 8.262 68.237 ;
     RECT  10.836 68.141 11.394 68.251 ;
     RECT  12.564 68.215 41.058 68.251 ;
     RECT  2.415 68.045 2.697 68.341 ;
     RECT  2.415 68.341 2.79 68.381 ;
     RECT  7.815 68.237 8.154 68.639 ;
     RECT  10.836 68.251 41.058 68.639 ;
     RECT  0.216 68.587 0.234 68.668 ;
     RECT  0.108 68.668 0.234 68.819 ;
     RECT  12.708 68.639 41.058 68.945 ;
     RECT  2.415 68.381 2.697 69.025 ;
     RECT  12.816 68.945 41.058 69.215 ;
     RECT  10.836 68.639 11.934 69.359 ;
     RECT  7.02 69.595 7.038 69.739 ;
     RECT  10.836 69.359 11.394 69.739 ;
     RECT  6.876 69.739 7.038 69.763 ;
     RECT  6.84 69.763 7.038 69.869 ;
     RECT  10.26 69.739 11.394 69.899 ;
     RECT  6.948 69.869 6.966 70.013 ;
     RECT  10.404 69.899 10.962 70.013 ;
     RECT  11.772 70.123 11.97 70.141 ;
     RECT  13.104 69.215 41.058 70.141 ;
     RECT  2.304 69.025 2.697 70.169 ;
     RECT  11.772 70.141 41.058 70.367 ;
     RECT  10.836 70.013 10.962 70.637 ;
     RECT  0.108 68.819 0.198 70.673 ;
     RECT  0.144 70.673 0.162 70.877 ;
     RECT  2.415 70.169 2.697 70.939 ;
     RECT  10.944 70.637 10.962 70.939 ;
     RECT  2.415 70.939 2.79 70.979 ;
     RECT  11.916 70.367 41.058 71.213 ;
     RECT  10.944 70.939 11.142 71.221 ;
     RECT  11.916 71.213 12.006 71.221 ;
     RECT  2.415 70.979 2.697 71.275 ;
     RECT  10.944 71.221 12.006 71.357 ;
     RECT  7.815 68.639 8.097 71.455 ;
     RECT  6.912 71.467 6.93 71.491 ;
     RECT  7.815 71.455 8.406 71.491 ;
     RECT  10.908 71.383 10.926 71.717 ;
     RECT  6.912 71.491 8.406 71.761 ;
     RECT  6.912 71.761 8.55 71.789 ;
     RECT  3.996 71.755 4.014 71.879 ;
     RECT  11.988 71.357 12.006 71.951 ;
     RECT  6.912 71.789 6.966 71.995 ;
     RECT  7.704 71.789 8.55 72.121 ;
     RECT  0.108 72.043 0.126 72.149 ;
     RECT  6.84 71.995 6.966 72.173 ;
     RECT  7.704 72.121 8.658 72.193 ;
     RECT  10.836 71.887 10.854 72.193 ;
     RECT  10.8 72.193 10.854 72.293 ;
     RECT  2.304 71.275 2.697 72.365 ;
     RECT  7.704 72.193 8.73 72.571 ;
     RECT  10.836 72.293 10.854 72.571 ;
     RECT  13.176 71.213 41.058 72.571 ;
     RECT  2.415 72.365 2.697 72.661 ;
     RECT  2.415 72.661 2.79 72.701 ;
     RECT  12.6 72.571 41.058 72.733 ;
     RECT  5.688 72.391 5.706 72.763 ;
     RECT  5.22 72.763 5.706 72.769 ;
     RECT  10.836 72.571 10.926 72.805 ;
     RECT  11.7 72.733 11.718 72.805 ;
     RECT  12.564 72.733 41.058 72.805 ;
     RECT  7.704 72.571 8.802 72.841 ;
     RECT  4.536 72.769 6.318 72.959 ;
     RECT  0.144 72.763 0.162 72.967 ;
     RECT  10.836 72.805 41.058 73.031 ;
     RECT  4.536 72.959 4.554 73.037 ;
     RECT  10.836 73.031 39.366 73.037 ;
     RECT  10.908 73.037 39.366 73.067 ;
     RECT  7.128 72.841 8.802 73.111 ;
     RECT  11.772 73.067 39.366 73.139 ;
     RECT  40.215 73.031 41.058 73.139 ;
     RECT  5.904 72.959 5.922 73.229 ;
     RECT  6.984 73.111 8.802 73.229 ;
     RECT  2.415 72.701 2.697 73.273 ;
     RECT  9.828 72.931 9.846 73.273 ;
     RECT  11.988 73.139 39.366 73.337 ;
     RECT  12.096 73.337 39.366 73.379 ;
     RECT  7.704 73.229 8.802 73.381 ;
     RECT  40.215 73.139 40.554 73.409 ;
     RECT  9.828 73.273 9.99 73.499 ;
     RECT  12.096 73.379 12.114 73.499 ;
     RECT  7.704 73.381 9.018 73.535 ;
     RECT  9.828 73.499 9.882 73.535 ;
     RECT  12.888 73.379 39.366 73.535 ;
     RECT  13.104 73.535 39.366 73.769 ;
     RECT  10.908 73.067 11.034 73.921 ;
     RECT  9.54 73.741 9.81 74.075 ;
     RECT  10.836 73.921 11.034 74.281 ;
     RECT  7.704 73.535 8.802 74.345 ;
     RECT  10.836 74.281 11.502 74.389 ;
     RECT  10.584 74.389 11.502 74.438 ;
     RECT  7.704 74.345 8.514 74.443 ;
     RECT  2.304 73.273 2.697 74.489 ;
     RECT  13.104 73.769 38.682 74.551 ;
     RECT  10.584 74.438 11.79 74.587 ;
     RECT  12.6 74.551 38.682 74.587 ;
     RECT  0.108 72.967 0.198 74.683 ;
     RECT  0.108 74.683 0.27 74.861 ;
     RECT  7.416 74.443 8.514 74.893 ;
     RECT  10.584 74.587 38.682 74.893 ;
     RECT  5.328 74.821 5.346 74.923 ;
     RECT  6.876 74.893 8.514 74.929 ;
     RECT  10.548 74.893 38.682 74.965 ;
     RECT  5.22 74.923 5.346 74.971 ;
     RECT  5.22 74.971 5.634 75.001 ;
     RECT  6.84 74.929 8.514 75.001 ;
     RECT  9.54 74.075 9.558 75.001 ;
     RECT  10.548 74.965 38.79 75.001 ;
     RECT  0.108 74.861 0.198 75.005 ;
     RECT  0.108 75.005 0.126 75.053 ;
     RECT  5.04 75.001 8.514 75.127 ;
     RECT  9.54 75.001 38.79 75.127 ;
     RECT  5.04 75.127 38.79 75.199 ;
     RECT  2.415 74.489 2.697 75.211 ;
     RECT  2.415 75.211 3.186 75.271 ;
     RECT  2.415 75.271 3.402 75.307 ;
     RECT  2.304 75.307 3.402 75.425 ;
     RECT  5.04 75.199 38.862 75.505 ;
     RECT  2.304 75.425 3.186 75.569 ;
     RECT  5.04 75.505 38.934 75.659 ;
     RECT  5.184 75.659 38.934 75.695 ;
     RECT  5.544 75.695 38.934 75.775 ;
     RECT  3.96 75.499 4.014 75.787 ;
     RECT  0.108 75.883 0.126 75.931 ;
     RECT  0.108 75.931 0.198 76.171 ;
     RECT  0.108 76.171 0.342 76.172 ;
     RECT  5.544 75.775 39.006 76.199 ;
     RECT  0.144 76.172 0.342 76.301 ;
     RECT  3.96 75.787 4.446 76.343 ;
     RECT  5.544 76.199 5.778 76.441 ;
     RECT  2.304 75.569 2.862 76.469 ;
     RECT  0.144 76.301 0.162 76.541 ;
     RECT  5.508 76.441 5.778 76.555 ;
     RECT  5.292 76.555 5.778 76.603 ;
     RECT  6.696 76.199 39.006 76.613 ;
     RECT  2.304 76.469 2.79 76.685 ;
     RECT  5.22 76.603 5.778 76.739 ;
     RECT  6.696 76.613 9.666 76.919 ;
     RECT  6.696 76.919 9.414 76.973 ;
     RECT  6.696 76.973 9.198 76.981 ;
     RECT  6.084 76.981 9.198 77.009 ;
     RECT  2.415 76.685 2.79 77.021 ;
     RECT  4.5 76.747 5.166 77.021 ;
     RECT  10.404 76.613 39.006 77.045 ;
     RECT  6.084 77.009 8.838 77.189 ;
     RECT  0.108 77.227 0.126 77.275 ;
     RECT  4.5 77.021 4.554 77.279 ;
     RECT  6.192 77.189 8.838 77.279 ;
     RECT  10.476 77.045 39.006 77.279 ;
     RECT  6.84 77.279 8.838 77.315 ;
     RECT  10.548 77.279 39.006 77.423 ;
     RECT  4.536 77.279 4.554 77.459 ;
     RECT  6.84 77.315 8.694 77.459 ;
     RECT  0.108 77.275 0.198 77.516 ;
     RECT  10.908 77.423 39.006 77.549 ;
     RECT  7.2 77.459 8.694 77.729 ;
     RECT  0.144 77.516 0.162 77.819 ;
     RECT  10.908 77.549 10.926 77.891 ;
     RECT  7.815 77.729 8.694 77.999 ;
     RECT  11.7 77.549 39.006 78.089 ;
     RECT  11.7 78.089 11.718 78.125 ;
     RECT  12.672 78.089 39.006 78.125 ;
     RECT  13.215 78.125 39.006 78.233 ;
     RECT  14.256 78.233 39.006 78.539 ;
     RECT  14.292 78.539 39.006 78.629 ;
     RECT  14.868 78.629 39.006 78.665 ;
     RECT  14.976 78.665 39.006 78.899 ;
     RECT  15.012 78.899 39.006 90.239 ;
     RECT  2.415 77.021 2.697 101.267 ;
     RECT  7.815 77.999 8.097 101.267 ;
     RECT  13.215 78.233 13.497 101.267 ;
     RECT  40.215 73.409 40.497 101.267 ;
     RECT  45.615 2.413 45.897 101.267 ;
     RECT  51.015 2.413 51.297 101.267 ;
     RECT  2.415 101.267 2.505 101.537 ;
     RECT  7.815 101.267 7.905 101.537 ;
     RECT  13.215 101.267 13.305 101.537 ;
     RECT  40.215 101.267 40.305 101.537 ;
     RECT  45.615 101.267 45.705 101.537 ;
     RECT  51.015 101.267 51.105 101.537 ;
     RECT  15.156 90.239 39.006 102.077 ;
     RECT  15.444 102.077 39.006 103.661 ;
    LAYER M4 ;
     RECT  0.06 26.928 0.173 77.544 ;
     RECT  0.173 26.928 2.408 77.448 ;
     RECT  2.408 2.148 2.512 101.532 ;
     RECT  2.512 2.418 2.704 101.262 ;
     RECT  2.704 26.928 7.808 77.448 ;
     RECT  7.808 2.148 7.912 101.532 ;
     RECT  7.912 2.418 8.104 101.262 ;
     RECT  8.104 50.64 8.129 77.352 ;
     RECT  8.104 26.928 8.237 47.064 ;
     RECT  8.129 50.64 8.345 66.024 ;
     RECT  8.129 67.056 8.345 77.352 ;
     RECT  8.345 64.128 8.417 66.024 ;
     RECT  8.417 66 8.453 66.024 ;
     RECT  8.345 73.296 8.489 77.352 ;
     RECT  8.104 48.096 8.531 49.608 ;
     RECT  8.237 31.728 8.561 47.064 ;
     RECT  8.345 50.64 8.561 61.704 ;
     RECT  8.345 63.024 8.561 63.048 ;
     RECT  8.345 67.056 8.561 72.168 ;
     RECT  8.561 50.64 8.597 61.224 ;
     RECT  8.531 48.096 8.669 49.512 ;
     RECT  8.561 32.304 9.029 34.2 ;
     RECT  8.597 53.424 9.137 61.224 ;
     RECT  8.561 35.952 9.173 47.064 ;
     RECT  8.489 73.296 9.425 76.968 ;
     RECT  8.669 49.248 9.569 49.512 ;
     RECT  9.425 73.296 9.857 76.728 ;
     RECT  9.857 74.112 9.875 76.728 ;
     RECT  9.029 32.496 9.997 34.2 ;
     RECT  9.997 32.16 10.217 34.2 ;
     RECT  8.597 50.64 10.361 52.44 ;
     RECT  9.137 54.864 10.465 61.224 ;
     RECT  9.875 75.984 10.537 76.728 ;
     RECT  10.217 32.16 10.613 33.96 ;
     RECT  9.173 35.952 10.613 46.392 ;
     RECT  10.465 54.72 10.837 61.224 ;
     RECT  10.537 75.984 10.937 77.352 ;
     RECT  9.875 74.112 10.969 75 ;
     RECT  10.361 51.216 11.005 52.44 ;
     RECT  9.137 53.424 11.005 53.592 ;
     RECT  10.825 62.88 11.009 62.904 ;
     RECT  10.969 74.112 11.009 75.144 ;
     RECT  8.561 67.584 11.041 71.4 ;
     RECT  11.041 67.056 11.117 71.4 ;
     RECT  11.005 51.216 11.221 53.592 ;
     RECT  10.837 54.72 11.261 61.272 ;
     RECT  9.569 49.296 11.365 49.512 ;
     RECT  11.261 56.784 11.365 61.272 ;
     RECT  11.221 62.304 11.365 62.472 ;
     RECT  11.117 68.208 11.405 71.4 ;
     RECT  8.237 26.928 11.441 30.696 ;
     RECT  10.613 35.952 11.441 42.6 ;
     RECT  11.365 49.296 11.441 49.8 ;
     RECT  11.441 27.072 11.477 30.696 ;
     RECT  11.441 36.048 11.477 42.6 ;
     RECT  10.613 44.112 11.477 46.392 ;
     RECT  11.441 49.344 11.513 49.8 ;
     RECT  8.417 64.128 11.513 64.488 ;
     RECT  11.221 51.216 11.516 53.688 ;
     RECT  11.261 54.72 11.516 55.608 ;
     RECT  10.613 32.496 11.621 33.96 ;
     RECT  11.513 64.128 11.621 64.392 ;
     RECT  11.477 44.4 11.653 46.392 ;
     RECT  10.937 76.176 11.689 77.352 ;
     RECT  11.621 32.496 11.693 33.864 ;
     RECT  11.513 49.776 11.701 49.8 ;
     RECT  11.516 51.216 11.701 55.608 ;
     RECT  11.693 32.496 11.801 33.288 ;
     RECT  11.365 56.784 11.837 62.472 ;
     RECT  11.701 49.776 11.843 55.608 ;
     RECT  11.653 44.4 11.869 46.968 ;
     RECT  8.669 48.096 11.869 48.12 ;
     RECT  11.477 27.12 11.905 30.696 ;
     RECT  11.621 64.128 11.909 64.152 ;
     RECT  11.801 32.496 11.945 33.048 ;
     RECT  11.837 57.36 11.945 62.472 ;
     RECT  10.825 73.008 11.977 73.032 ;
     RECT  11.905 27.12 11.981 30.84 ;
     RECT  11.981 27.168 12.053 30.84 ;
     RECT  11.945 57.936 12.085 62.472 ;
     RECT  11.977 73.008 12.121 73.08 ;
     RECT  11.477 36.096 12.233 42.6 ;
     RECT  11.009 74.304 12.337 75.144 ;
     RECT  11.689 76.176 12.337 78.12 ;
     RECT  11.117 67.056 12.373 67.08 ;
     RECT  12.373 67.056 12.481 67.128 ;
     RECT  11.945 32.496 12.697 32.904 ;
     RECT  12.121 73.008 12.697 73.272 ;
     RECT  12.697 73.008 12.805 73.32 ;
     RECT  12.337 74.304 12.805 78.12 ;
     RECT  12.481 66.912 12.877 67.128 ;
     RECT  11.869 44.4 13.021 48.12 ;
     RECT  11.843 49.776 13.021 55.224 ;
     RECT  12.085 57.936 13.093 62.76 ;
     RECT  12.697 31.968 13.165 32.904 ;
     RECT  12.053 27.168 13.208 30.408 ;
     RECT  13.165 31.44 13.208 32.904 ;
     RECT  12.233 36.096 13.208 39.24 ;
     RECT  12.233 40.608 13.208 42.6 ;
     RECT  13.021 44.4 13.208 55.224 ;
     RECT  13.093 57.936 13.208 63.624 ;
     RECT  12.877 66.912 13.208 67.176 ;
     RECT  11.405 68.4 13.208 71.4 ;
     RECT  12.805 73.008 13.208 78.12 ;
     RECT  13.208 2.148 13.312 101.532 ;
     RECT  13.312 2.418 13.504 101.262 ;
     RECT  13.504 45.984 13.673 52.488 ;
     RECT  13.504 67.008 13.715 67.176 ;
     RECT  13.504 53.808 13.817 55.224 ;
     RECT  13.715 67.008 13.925 67.128 ;
     RECT  13.504 68.352 13.997 78.12 ;
     RECT  13.504 63.264 14.033 63.624 ;
     RECT  13.925 67.008 14.033 67.08 ;
     RECT  13.997 68.352 14.097 77.304 ;
     RECT  14.097 68.4 14.321 77.304 ;
     RECT  13.504 41.232 14.857 42.744 ;
     RECT  13.673 45.984 14.857 52.2 ;
     RECT  13.817 54.096 14.857 55.224 ;
     RECT  14.785 56.4 14.857 56.424 ;
     RECT  14.033 63.504 14.857 63.624 ;
     RECT  14.857 41.232 14.897 43.272 ;
     RECT  13.504 36.096 15.001 39.24 ;
     RECT  13.504 58.416 15.001 62.28 ;
     RECT  14.857 63.504 15.001 64.344 ;
     RECT  14.897 41.472 15.037 43.272 ;
     RECT  14.033 67.056 15.037 67.08 ;
     RECT  15.037 41.472 15.073 43.56 ;
     RECT  14.857 45.984 15.113 56.424 ;
     RECT  15.001 58.416 15.145 64.344 ;
     RECT  15.037 67.008 15.145 67.08 ;
     RECT  15.073 41.472 15.185 44.424 ;
     RECT  14.773 0.144 15.217 0.168 ;
     RECT  15.217 0.144 15.253 0.264 ;
     RECT  15.185 41.616 15.325 44.424 ;
     RECT  13.504 27.168 15.349 32.904 ;
     RECT  14.321 68.4 15.365 77.256 ;
     RECT  15.145 66.672 15.397 67.272 ;
     RECT  15.145 102.048 15.473 102.072 ;
     RECT  15.145 58.416 15.505 64.44 ;
     RECT  15.397 66.672 15.505 67.32 ;
     RECT  15.365 68.4 15.505 68.424 ;
     RECT  15.113 46.08 15.541 56.424 ;
     RECT  15.253 79.68 15.577 79.704 ;
     RECT  15.577 79.248 15.596 79.704 ;
     RECT  15.397 98.64 15.649 98.664 ;
     RECT  15.589 103.104 15.685 103.56 ;
     RECT  15.541 82.608 15.689 82.632 ;
     RECT  15.505 66.672 15.731 68.424 ;
     RECT  15.505 58.416 15.757 65.016 ;
     RECT  15.397 91.776 15.779 91.8 ;
     RECT  15.649 98.64 15.827 99.192 ;
     RECT  15.253 0.048 15.829 0.264 ;
     RECT  15.829 0.048 15.877 0.456 ;
     RECT  15.685 103.056 15.901 103.56 ;
     RECT  15.827 98.64 15.905 98.664 ;
     RECT  15.901 102.624 15.923 103.56 ;
     RECT  15.877 0.048 15.977 0.552 ;
     RECT  15.932 97.488 16.019 97.512 ;
     RECT  15.365 69.552 16.045 77.256 ;
     RECT  15.923 102.624 16.115 103.224 ;
     RECT  15.757 58.416 16.117 65.688 ;
     RECT  15.731 66.672 16.117 67.32 ;
     RECT  15.596 78.624 16.117 79.704 ;
     RECT  15.325 41.616 16.225 44.472 ;
     RECT  15.541 46.08 16.265 57.144 ;
     RECT  15.977 0.048 16.337 0.456 ;
     RECT  15.001 36 16.337 39.24 ;
     RECT  16.115 102.96 16.403 103.224 ;
     RECT  16.337 37.536 16.409 39.24 ;
     RECT  16.117 78.624 16.433 79.848 ;
     RECT  16.124 80.928 16.433 80.952 ;
     RECT  16.265 46.272 16.445 57.144 ;
     RECT  16.337 0.048 16.553 0.168 ;
     RECT  16.445 51.072 16.553 57.144 ;
     RECT  16.045 69.552 16.585 77.544 ;
     RECT  16.433 78.624 16.585 80.952 ;
     RECT  16.585 69.552 16.697 80.952 ;
     RECT  16.553 51.312 16.729 57.144 ;
     RECT  16.117 58.416 16.729 67.32 ;
     RECT  16.513 34.656 16.765 34.68 ;
     RECT  16.337 36 16.765 36.456 ;
     RECT  16.225 41.616 16.787 44.712 ;
     RECT  16.765 34.656 16.828 36.456 ;
     RECT  15.349 27.168 16.835 33.288 ;
     RECT  16.729 51.312 16.835 67.32 ;
     RECT  16.697 80.928 16.837 80.952 ;
     RECT  16.697 69.552 16.877 79.848 ;
     RECT  16.409 37.536 16.913 39.192 ;
     RECT  16.787 42.192 16.913 44.712 ;
     RECT  16.877 70.608 16.913 79.848 ;
     RECT  16.837 80.928 16.921 81.48 ;
     RECT  16.913 37.536 16.931 37.56 ;
     RECT  16.835 66.816 17.053 67.32 ;
     RECT  16.913 70.704 17.057 79.848 ;
     RECT  16.921 80.928 17.075 80.952 ;
     RECT  17.053 66.816 17.089 67.416 ;
     RECT  15.731 68.4 17.089 68.424 ;
     RECT  16.913 38.544 17.237 39.192 ;
     RECT  16.877 69.552 17.324 69.576 ;
     RECT  17.324 69.408 17.345 69.576 ;
     RECT  17.345 69.408 17.411 69.432 ;
     RECT  17.089 66.816 17.413 68.424 ;
     RECT  16.913 42.192 17.417 44.472 ;
     RECT  17.269 103.488 17.458 103.512 ;
     RECT  16.835 51.408 17.845 65.784 ;
     RECT  17.413 66.816 17.845 68.952 ;
     RECT  17.458 103.44 17.941 103.56 ;
     RECT  16.445 46.272 17.989 49.272 ;
     RECT  17.66 82.08 17.989 82.104 ;
     RECT  17.417 42.24 18.025 44.472 ;
     RECT  17.989 45.6 18.025 49.272 ;
     RECT  17.057 70.848 18.025 79.848 ;
     RECT  16.553 0.048 18.037 0.072 ;
     RECT  18.037 0.048 18.065 0.36 ;
     RECT  18.065 0.336 18.085 0.36 ;
     RECT  18.025 70.8 18.085 79.848 ;
     RECT  17.989 81.984 18.169 82.104 ;
     RECT  17.941 103.344 18.229 103.56 ;
     RECT  16.835 31.392 18.277 33.288 ;
     RECT  18.085 70.704 18.284 79.848 ;
     RECT  18.284 70.704 18.313 80.712 ;
     RECT  18.313 70.128 18.341 80.712 ;
     RECT  18.085 50.304 18.385 50.328 ;
     RECT  17.845 51.408 18.385 68.952 ;
     RECT  18.025 42.24 18.421 49.272 ;
     RECT  18.229 103.248 18.422 103.56 ;
     RECT  18.341 70.128 18.449 80.952 ;
     RECT  18.169 81.984 18.449 82.632 ;
     RECT  18.133 2.832 18.608 2.856 ;
     RECT  16.835 27.168 18.608 30.12 ;
     RECT  18.277 31.248 18.608 33.288 ;
     RECT  16.828 34.656 18.608 36.36 ;
     RECT  17.237 39.168 18.608 39.192 ;
     RECT  18.421 42 18.608 49.272 ;
     RECT  18.385 50.304 18.608 68.952 ;
     RECT  18.449 70.128 18.608 82.632 ;
     RECT  18.229 83.808 18.608 83.832 ;
     RECT  18.133 85.488 18.608 85.512 ;
     RECT  18.349 98.64 18.608 98.664 ;
     RECT  18.277 100.896 18.608 100.92 ;
     RECT  18.608 2.148 18.712 101.532 ;
     RECT  18.422 103.248 18.803 103.512 ;
     RECT  18.712 2.418 18.904 101.262 ;
     RECT  18.904 38.688 19.001 38.712 ;
     RECT  18.904 27.168 19.037 36.408 ;
     RECT  18.803 103.296 19.043 103.512 ;
     RECT  19.043 103.296 19.139 103.416 ;
     RECT  18.085 0.336 19.213 0.552 ;
     RECT  18.904 53.04 19.217 68.472 ;
     RECT  18.904 71.136 19.217 78.552 ;
     RECT  19.217 53.04 19.235 53.064 ;
     RECT  18.904 80.928 19.261 80.952 ;
     RECT  18.904 86.016 19.283 87.768 ;
     RECT  18.904 2.832 19.289 2.856 ;
     RECT  19.139 103.296 19.331 103.32 ;
     RECT  19.217 71.136 19.397 71.688 ;
     RECT  19.283 87.744 19.427 87.768 ;
     RECT  19.217 54.24 19.469 68.472 ;
     RECT  19.213 0.24 19.501 0.552 ;
     RECT  19.283 86.016 19.619 86.664 ;
     RECT  18.904 79.824 19.667 79.848 ;
     RECT  18.904 46.128 19.708 51.432 ;
     RECT  19.501 0.24 19.765 1.128 ;
     RECT  19.765 0.192 19.813 1.128 ;
     RECT  19.217 72.864 19.901 78.552 ;
     RECT  19.037 31.44 19.937 36.408 ;
     RECT  18.904 98.64 19.937 98.664 ;
     RECT  19.708 46.128 19.969 49.368 ;
     RECT  19.901 78.528 19.969 78.552 ;
     RECT  19.969 78.528 19.97 78.6 ;
     RECT  19.969 45.936 19.973 49.368 ;
     RECT  19.973 47.856 20.003 49.368 ;
     RECT  19.813 0.096 20.005 1.128 ;
     RECT  19.933 38.832 20.005 38.856 ;
     RECT  18.904 41.04 20.041 44.712 ;
     RECT  19.973 45.936 20.041 46.872 ;
     RECT  19.901 72.864 20.081 76.968 ;
     RECT  19.937 31.44 20.113 34.968 ;
     RECT  19.397 71.136 20.113 71.16 ;
     RECT  19.97 78.576 20.153 78.6 ;
     RECT  20.081 72.864 20.189 73.464 ;
     RECT  20.113 70.704 20.224 71.16 ;
     RECT  20.189 72.864 20.225 73.224 ;
     RECT  20.005 38.832 20.293 39.384 ;
     RECT  19.708 50.4 20.333 51.432 ;
     RECT  20.225 72.864 20.441 72.984 ;
     RECT  20.003 47.952 20.477 49.368 ;
     RECT  20.224 70.656 20.477 71.16 ;
     RECT  19.619 86.64 20.477 86.664 ;
     RECT  19.469 55.104 20.653 68.472 ;
     RECT  20.081 74.544 20.657 76.968 ;
     RECT  20.677 80.352 20.689 80.376 ;
     RECT  20.657 76.944 20.693 76.968 ;
     RECT  20.293 38.688 20.725 39.384 ;
     RECT  20.041 41.04 20.725 46.872 ;
     RECT  20.653 55.104 20.725 68.904 ;
     RECT  20.689 79.92 20.725 80.376 ;
     RECT  20.333 51.408 20.789 51.432 ;
     RECT  20.761 52.416 20.789 52.44 ;
     RECT  20.725 79.824 20.801 80.376 ;
     RECT  20.477 48.096 20.867 49.368 ;
     RECT  20.789 51.408 20.873 52.44 ;
     RECT  20.801 79.824 20.915 79.944 ;
     RECT  19.937 36 20.917 36.408 ;
     RECT  20.725 54.144 20.933 68.904 ;
     RECT  20.329 90.576 20.945 90.6 ;
     RECT  20.933 53.568 20.981 68.904 ;
     RECT  20.915 79.824 21.011 79.896 ;
     RECT  19.037 27.168 21.061 30.12 ;
     RECT  20.113 31.392 21.061 34.968 ;
     RECT  20.657 74.544 21.089 75.48 ;
     RECT  21.011 79.872 21.107 79.896 ;
     RECT  21.085 78.768 21.116 78.792 ;
     RECT  21.089 75.264 21.125 75.48 ;
     RECT  20.867 49.008 21.157 49.368 ;
     RECT  20.333 50.4 21.157 50.424 ;
     RECT  21.125 75.456 21.205 75.48 ;
     RECT  21.116 78.672 21.299 78.792 ;
     RECT  20.981 54.576 21.337 68.904 ;
     RECT  21.061 27.168 21.409 34.968 ;
     RECT  20.917 36 21.409 37.08 ;
     RECT  21.157 49.008 21.445 50.424 ;
     RECT  20.725 38.688 21.481 46.872 ;
     RECT  21.404 82.56 21.491 82.584 ;
     RECT  21.509 91.056 21.593 91.08 ;
     RECT  21.481 38.688 21.665 47.832 ;
     RECT  21.445 49.008 21.665 51.336 ;
     RECT  21.581 81.504 21.665 81.528 ;
     RECT  21.637 86.592 21.692 86.616 ;
     RECT  21.692 86.064 21.779 86.616 ;
     RECT  21.779 86.112 21.809 86.616 ;
     RECT  21.809 86.112 21.875 86.232 ;
     RECT  21.665 49.008 21.881 51.24 ;
     RECT  20.873 52.416 21.913 52.44 ;
     RECT  21.913 52.368 21.914 52.44 ;
     RECT  20.981 53.568 21.989 53.592 ;
     RECT  21.661 100.896 22.021 100.92 ;
     RECT  21.881 50.4 22.025 50.568 ;
     RECT  21.875 86.208 22.163 86.232 ;
     RECT  21.337 54.576 22.201 69.624 ;
     RECT  22.021 100.896 22.213 101.4 ;
     RECT  21.877 80.976 22.241 81 ;
     RECT  22.268 84.384 22.355 84.408 ;
     RECT  22.213 100.896 22.385 101.448 ;
     RECT  21.665 38.736 22.489 47.832 ;
     RECT  22.057 48.816 22.489 48.84 ;
     RECT  22.489 38.736 22.493 48.84 ;
     RECT  22.385 100.896 22.547 100.968 ;
     RECT  22.201 53.808 22.565 69.624 ;
     RECT  22.547 100.944 22.643 100.968 ;
     RECT  22.565 63.648 22.645 69.624 ;
     RECT  21.409 27.168 22.669 37.08 ;
     RECT  22.493 38.736 22.669 45 ;
     RECT  20.005 0.048 22.739 1.128 ;
     RECT  22.633 97.536 22.751 97.56 ;
     RECT  22.645 63.648 22.787 69.672 ;
     RECT  22.669 38.496 22.789 45 ;
     RECT  22.661 84.912 22.849 84.936 ;
     RECT  22.493 45.984 22.925 48.84 ;
     RECT  22.777 21.648 22.931 21.672 ;
     RECT  22.669 27.168 22.957 37.176 ;
     RECT  22.789 38.208 22.957 45 ;
     RECT  22.057 102.624 22.957 102.648 ;
     RECT  22.565 53.808 22.961 62.568 ;
     RECT  20.485 72.432 22.993 72.456 ;
     RECT  22.751 97.488 23.027 97.56 ;
     RECT  22.957 102.624 23.029 103.416 ;
     RECT  22.957 27.072 23.033 45 ;
     RECT  23.029 102.624 23.057 103.464 ;
     RECT  21.914 52.368 23.077 52.392 ;
     RECT  22.961 53.808 23.077 61.224 ;
     RECT  22.741 82.656 23.132 82.68 ;
     RECT  23.029 83.76 23.132 83.784 ;
     RECT  23.057 102.624 23.173 103.56 ;
     RECT  23.173 102.576 23.174 103.56 ;
     RECT  22.025 50.544 23.209 50.568 ;
     RECT  23.174 102.576 23.257 103.512 ;
     RECT  23.132 82.656 23.461 83.784 ;
     RECT  22.849 84.912 23.461 85.512 ;
     RECT  21.299 78.672 23.653 78.696 ;
     RECT  22.739 0.048 23.814 0.552 ;
     RECT  23.077 52.368 23.857 61.224 ;
     RECT  23.257 102.576 23.857 103.32 ;
     RECT  23.857 101.664 23.987 103.32 ;
     RECT  23.557 6.816 24.008 6.84 ;
     RECT  23.365 13.92 24.008 13.944 ;
     RECT  23.033 27.072 24.008 39.864 ;
     RECT  23.033 40.848 24.008 45 ;
     RECT  22.925 46.176 24.008 48.84 ;
     RECT  23.209 50.544 24.008 50.76 ;
     RECT  23.857 52.032 24.008 61.224 ;
     RECT  22.961 62.544 24.008 62.568 ;
     RECT  22.787 63.648 24.008 69.576 ;
     RECT  20.477 71.136 24.008 71.16 ;
     RECT  22.993 72.432 24.008 72.888 ;
     RECT  23.065 74.64 24.008 74.664 ;
     RECT  23.653 78.672 24.008 79.272 ;
     RECT  22.849 80.928 24.008 80.952 ;
     RECT  23.461 82.656 24.008 85.512 ;
     RECT  23.365 97.44 24.008 97.464 ;
     RECT  22.093 99.168 24.008 99.192 ;
     RECT  23.987 101.664 24.008 101.736 ;
     RECT  24.008 2.148 24.112 101.736 ;
     RECT  23.814 0.144 24.113 0.552 ;
     RECT  23.987 103.296 24.229 103.32 ;
     RECT  24.229 103.296 24.277 103.416 ;
     RECT  24.112 2.418 24.304 101.736 ;
     RECT  24.304 62.544 24.419 62.568 ;
     RECT  24.304 83.808 24.419 86.04 ;
     RECT  24.304 64.944 24.437 74.664 ;
     RECT  24.113 0.144 24.467 0.504 ;
     RECT  24.304 76.944 24.467 78.12 ;
     RECT  24.304 49.248 24.473 50.184 ;
     RECT  24.304 51.168 24.473 53.064 ;
     RECT  24.304 54.336 24.473 61.512 ;
     RECT  24.304 46.176 24.509 47.88 ;
     RECT  24.467 77.04 24.509 78.12 ;
     RECT  24.473 49.584 24.515 50.184 ;
     RECT  24.419 84.384 24.515 86.04 ;
     RECT  24.515 84.96 24.545 84.984 ;
     RECT  24.304 98.64 24.556 99.192 ;
     RECT  24.304 75.84 24.581 75.864 ;
     RECT  24.509 46.176 24.611 46.584 ;
     RECT  24.515 86.016 24.611 86.04 ;
     RECT  24.556 98.784 24.611 99.192 ;
     RECT  24.304 100.32 24.725 101.736 ;
     RECT  24.437 64.992 24.755 74.664 ;
     RECT  24.509 77.472 24.755 78.12 ;
     RECT  24.473 55.488 24.833 61.512 ;
     RECT  24.725 100.32 24.851 101.016 ;
     RECT  24.755 64.992 24.869 74.136 ;
     RECT  24.304 21.648 24.941 21.672 ;
     RECT  24.473 51.312 24.941 53.064 ;
     RECT  24.277 103.296 24.965 103.512 ;
     RECT  24.833 55.872 25.013 61.512 ;
     RECT  24.941 51.312 25.091 51.336 ;
     RECT  24.941 52.416 25.121 53.064 ;
     RECT  24.965 103.296 25.333 103.56 ;
     RECT  24.304 26.208 25.381 44.808 ;
     RECT  24.611 99.168 25.445 99.192 ;
     RECT  25.121 52.464 25.477 53.064 ;
     RECT  24.473 54.336 25.477 54.36 ;
     RECT  24.611 46.272 25.513 46.584 ;
     RECT  24.509 47.664 25.513 47.88 ;
     RECT  24.304 93.504 25.523 93.528 ;
     RECT  25.013 56.448 25.619 61.512 ;
     RECT  25.333 102.624 25.619 103.56 ;
     RECT  24.755 78.096 25.667 78.12 ;
     RECT  24.304 6.864 25.669 6.888 ;
     RECT  24.467 0.144 25.693 0.312 ;
     RECT  25.628 88.944 25.715 88.968 ;
     RECT  24.304 80.352 25.717 80.376 ;
     RECT  24.304 81.504 25.717 81.576 ;
     RECT  25.477 52.464 25.763 54.36 ;
     RECT  25.693 0.144 25.765 0.456 ;
     RECT  25.381 26.208 25.801 45.048 ;
     RECT  25.513 46.272 25.801 47.88 ;
     RECT  25.717 80.352 25.811 81.576 ;
     RECT  25.669 6.864 25.813 6.936 ;
     RECT  25.813 6.864 25.837 6.984 ;
     RECT  25.765 0.144 25.858 0.552 ;
     RECT  25.801 26.208 25.873 47.88 ;
     RECT  24.304 25.104 25.877 25.176 ;
     RECT  25.619 57.024 25.949 61.512 ;
     RECT  25.811 80.928 25.949 81.576 ;
     RECT  25.837 6.816 25.955 6.984 ;
     RECT  25.868 18.768 25.955 18.792 ;
     RECT  25.868 84.336 25.955 84.36 ;
     RECT  24.851 100.896 25.981 101.016 ;
     RECT  25.858 0.096 26.003 0.552 ;
     RECT  25.873 26.208 26.003 48.504 ;
     RECT  25.981 100.896 26.003 101.496 ;
     RECT  24.869 65.376 26.053 74.136 ;
     RECT  25.873 23.376 26.089 24.024 ;
     RECT  25.763 54.144 26.099 54.36 ;
     RECT  25.945 82.656 26.099 82.68 ;
     RECT  24.304 13.92 26.117 13.944 ;
     RECT  26.089 22.8 26.125 24.024 ;
     RECT  25.877 25.104 26.125 25.128 ;
     RECT  26.003 26.208 26.125 47.544 ;
     RECT  26.053 65.376 26.149 74.76 ;
     RECT  26.053 10.848 26.165 10.872 ;
     RECT  26.125 22.8 26.165 25.128 ;
     RECT  26.117 13.92 26.201 14.856 ;
     RECT  26.003 0.144 26.225 0.552 ;
     RECT  26.149 64.368 26.237 74.76 ;
     RECT  25.949 81.36 26.269 81.576 ;
     RECT  26.003 100.944 26.291 101.496 ;
     RECT  24.304 15.984 26.341 16.008 ;
     RECT  25.949 57.024 26.417 57.048 ;
     RECT  26.341 15.984 26.428 16.584 ;
     RECT  26.341 2.88 26.437 2.904 ;
     RECT  25.949 58.128 26.525 61.512 ;
     RECT  26.237 74.16 26.525 74.76 ;
     RECT  26.245 20.496 26.561 20.52 ;
     RECT  26.149 62.592 26.561 62.616 ;
     RECT  26.237 64.368 26.561 73.176 ;
     RECT  26.413 84.384 26.579 84.408 ;
     RECT  26.437 2.88 26.581 2.952 ;
     RECT  26.581 16.992 26.621 17.016 ;
     RECT  26.225 0.144 26.627 0.6 ;
     RECT  26.581 2.496 26.629 2.952 ;
     RECT  26.621 16.992 26.668 17.112 ;
     RECT  26.165 22.8 26.668 23.736 ;
     RECT  26.525 74.16 26.669 74.664 ;
     RECT  26.269 81.36 26.675 82.104 ;
     RECT  26.629 2.304 26.725 3.432 ;
     RECT  26.533 11.424 26.741 11.448 ;
     RECT  26.725 2.256 26.771 3.432 ;
     RECT  26.677 12.528 26.777 12.552 ;
     RECT  26.668 17.088 26.809 17.112 ;
     RECT  26.771 2.256 26.813 2.424 ;
     RECT  26.125 26.16 26.819 47.544 ;
     RECT  25.955 6.864 26.821 6.984 ;
     RECT  26.813 2.256 26.832 2.28 ;
     RECT  26.819 26.16 26.857 46.584 ;
     RECT  26.201 13.92 26.867 13.944 ;
     RECT  25.763 52.464 26.867 53.016 ;
     RECT  26.485 91.776 26.867 91.8 ;
     RECT  26.737 9.696 26.885 9.72 ;
     RECT  26.857 46.08 26.915 46.584 ;
     RECT  26.291 101.472 26.917 101.496 ;
     RECT  25.619 102.624 26.917 103.224 ;
     RECT  26.857 26.16 26.963 45.048 ;
     RECT  26.963 26.16 27.011 44.088 ;
     RECT  26.821 6.864 27.013 7.464 ;
     RECT  26.953 80.928 27.059 80.952 ;
     RECT  27.013 6.864 27.107 7.512 ;
     RECT  24.515 49.776 27.107 50.184 ;
     RECT  26.561 65.376 27.107 73.176 ;
     RECT  26.953 76.896 27.137 76.92 ;
     RECT  26.917 101.472 27.155 103.224 ;
     RECT  26.428 15.984 27.203 16.008 ;
     RECT  27.107 50.16 27.203 50.184 ;
     RECT  26.627 0.192 27.212 0.6 ;
     RECT  27.155 101.472 27.251 101.496 ;
     RECT  27.107 7.488 27.281 7.512 ;
     RECT  27.205 14.256 27.301 14.28 ;
     RECT  26.165 24.768 27.317 25.128 ;
     RECT  26.675 82.08 27.346 82.104 ;
     RECT  27.346 82.08 27.347 82.152 ;
     RECT  26.525 58.656 27.388 61.512 ;
     RECT  27.301 14.256 27.389 14.328 ;
     RECT  26.867 52.464 27.395 52.488 ;
     RECT  26.771 3.408 27.397 3.432 ;
     RECT  27.347 82.128 27.491 82.152 ;
     RECT  26.809 17.088 27.493 17.64 ;
     RECT  27.457 18.768 27.493 18.792 ;
     RECT  27.397 3.408 27.533 4.008 ;
     RECT  27.107 66.768 27.565 73.176 ;
     RECT  26.669 74.16 27.565 74.184 ;
     RECT  27.493 17.088 27.577 18.792 ;
     RECT  27.493 8.544 27.605 8.568 ;
     RECT  27.389 14.304 27.605 14.328 ;
     RECT  27.577 18.768 27.637 18.792 ;
     RECT  27.565 66.768 27.649 74.184 ;
     RECT  27.637 18.768 27.677 19.368 ;
     RECT  27.529 57.024 27.677 57.048 ;
     RECT  27.388 58.704 27.709 61.512 ;
     RECT  27.533 3.408 27.713 3.432 ;
     RECT  27.577 17.088 27.713 17.688 ;
     RECT  27.649 66.768 27.713 72.936 ;
     RECT  26.561 64.368 27.733 64.392 ;
     RECT  27.155 102.528 27.733 103.224 ;
     RECT  27.709 58.704 27.745 61.992 ;
     RECT  27.665 5.712 27.749 5.736 ;
     RECT  27.745 15.456 27.773 15.48 ;
     RECT  25.837 98.64 27.779 98.664 ;
     RECT  27.011 26.16 27.781 42.792 ;
     RECT  27.773 15.408 27.845 15.48 ;
     RECT  26.668 22.8 27.857 22.824 ;
     RECT  26.821 75.84 27.877 75.864 ;
     RECT  27.637 13.056 27.929 13.08 ;
     RECT  27.845 14.832 27.929 15.48 ;
     RECT  27.781 25.68 27.929 42.792 ;
     RECT  27.929 15.408 27.965 15.48 ;
     RECT  27.745 58.704 27.965 62.712 ;
     RECT  27.212 0.192 27.973 0.696 ;
     RECT  27.733 1.92 27.973 1.944 ;
     RECT  27.733 102.528 27.997 103.512 ;
     RECT  27.929 25.68 28.001 25.704 ;
     RECT  27.713 17.616 28.037 17.688 ;
     RECT  27.973 0.192 28.076 1.944 ;
     RECT  27.961 95.184 28.115 95.208 ;
     RECT  27.733 63.84 28.141 64.392 ;
     RECT  27.107 65.376 28.141 65.784 ;
     RECT  27.713 66.768 28.141 72.696 ;
     RECT  28.076 0.144 28.165 1.944 ;
     RECT  27.929 26.736 28.213 42.792 ;
     RECT  28.172 7.44 28.259 7.464 ;
     RECT  28.037 17.664 28.297 17.688 ;
     RECT  28.165 0.144 28.321 2.328 ;
     RECT  28.321 0.096 28.325 2.328 ;
     RECT  28.213 26.736 28.361 42.84 ;
     RECT  27.965 58.704 28.393 62.184 ;
     RECT  28.325 0.096 28.405 1.944 ;
     RECT  28.405 11.424 28.453 11.448 ;
     RECT  28.285 24.528 28.46 24.552 ;
     RECT  28.46 24.432 28.501 24.552 ;
     RECT  27.997 102.528 28.501 103.56 ;
     RECT  27.677 19.344 28.645 19.368 ;
     RECT  28.501 102.528 28.826 103.608 ;
     RECT  27.649 74.16 28.844 74.184 ;
     RECT  27.877 75.84 28.844 76.44 ;
     RECT  28.141 63.84 28.861 72.696 ;
     RECT  28.844 74.16 28.885 76.44 ;
     RECT  28.405 0.144 28.901 1.944 ;
     RECT  28.361 26.736 28.969 42.744 ;
     RECT  28.861 63.84 28.969 73.08 ;
     RECT  28.969 63.792 29.077 73.08 ;
     RECT  28.885 74.064 29.077 76.44 ;
     RECT  29.105 97.104 29.125 97.128 ;
     RECT  28.826 102.528 29.125 103.56 ;
     RECT  29.125 97.008 29.149 97.128 ;
     RECT  28.453 11.424 29.173 11.544 ;
     RECT  29.041 12.528 29.173 12.552 ;
     RECT  26.915 46.56 29.224 46.584 ;
     RECT  28.885 16.512 29.269 16.536 ;
     RECT  28.901 1.92 29.329 1.944 ;
     RECT  29.329 1.92 29.369 2.04 ;
     RECT  27.011 43.872 29.401 44.088 ;
     RECT  29.369 2.016 29.408 2.04 ;
     RECT  29.084 3.408 29.408 3.432 ;
     RECT  29.173 11.424 29.408 12.552 ;
     RECT  27.965 15.408 29.408 15.432 ;
     RECT  29.269 16.512 29.408 16.584 ;
     RECT  28.645 18.768 29.408 19.368 ;
     RECT  28.501 24.432 29.408 24.744 ;
     RECT  28.969 26.688 29.408 42.744 ;
     RECT  29.401 43.872 29.408 44.472 ;
     RECT  29.224 46.56 29.408 46.68 ;
     RECT  26.099 54.336 29.408 54.36 ;
     RECT  28.393 58.128 29.408 62.184 ;
     RECT  29.077 63.792 29.408 76.44 ;
     RECT  29.149 96.912 29.408 97.128 ;
     RECT  29.125 101.616 29.408 103.56 ;
     RECT  29.408 2.016 29.555 103.56 ;
     RECT  29.555 2.418 29.704 103.56 ;
     RECT  29.704 40.848 29.765 42.792 ;
     RECT  29.704 12 29.801 12.552 ;
     RECT  29.704 35.04 29.843 39.288 ;
     RECT  29.704 3.408 29.873 3.432 ;
     RECT  29.704 6.096 29.891 6.12 ;
     RECT  29.704 97.536 29.891 97.56 ;
     RECT  29.801 12.528 29.939 12.552 ;
     RECT  29.765 40.992 30.125 42.792 ;
     RECT  29.704 4.512 30.131 4.536 ;
     RECT  29.704 16.56 30.161 16.584 ;
     RECT  29.704 45.552 30.179 45.576 ;
     RECT  29.704 83.808 30.227 83.832 ;
     RECT  29.704 43.872 30.275 44.568 ;
     RECT  28.901 0.144 30.277 0.936 ;
     RECT  29.704 18.24 30.305 19.992 ;
     RECT  30.275 43.872 30.305 44.472 ;
     RECT  30.305 18.816 30.323 19.992 ;
     RECT  30.323 18.816 30.371 18.84 ;
     RECT  29.704 26.736 30.413 33.288 ;
     RECT  29.704 96.288 30.449 96.312 ;
     RECT  29.704 10.848 30.485 10.872 ;
     RECT  29.704 54.336 30.563 54.36 ;
     RECT  29.704 57.504 30.563 63.96 ;
     RECT  30.277 0.096 30.613 0.936 ;
     RECT  30.613 0.096 30.625 1.512 ;
     RECT  29.704 14.256 30.629 14.28 ;
     RECT  29.704 75.936 30.629 76.92 ;
     RECT  30.563 58.32 30.701 63.96 ;
     RECT  30.323 19.968 30.755 19.992 ;
     RECT  30.741 2.88 30.757 2.904 ;
     RECT  30.125 40.992 30.805 42.744 ;
     RECT  30.701 63.792 30.841 63.96 ;
     RECT  29.704 64.992 30.841 74.664 ;
     RECT  30.757 2.736 30.845 2.904 ;
     RECT  30.845 2.736 30.899 2.856 ;
     RECT  30.841 63.792 30.917 74.664 ;
     RECT  30.805 40.752 30.947 42.744 ;
     RECT  30.701 58.32 30.947 62.808 ;
     RECT  30.853 78.576 31.043 78.6 ;
     RECT  30.853 82.704 31.043 82.728 ;
     RECT  30.853 86.544 31.043 86.568 ;
     RECT  30.853 96.912 31.043 96.936 ;
     RECT  29.843 36.336 31.129 39.288 ;
     RECT  29.843 35.04 31.133 35.064 ;
     RECT  30.305 43.92 31.139 44.472 ;
     RECT  31.129 36.336 31.165 39.336 ;
     RECT  30.947 41.232 31.169 42.744 ;
     RECT  31.139 44.064 31.277 44.472 ;
     RECT  30.413 27.168 31.345 33.288 ;
     RECT  30.917 71.52 31.349 74.664 ;
     RECT  31.165 36.336 31.381 39.528 ;
     RECT  31.345 27.168 31.489 33.384 ;
     RECT  30.917 63.792 31.529 70.44 ;
     RECT  31.529 64.416 31.571 70.44 ;
     RECT  30.629 75.936 31.573 75.96 ;
     RECT  31.571 64.416 31.601 67.32 ;
     RECT  31.349 71.52 31.619 74.088 ;
     RECT  31.573 75.168 31.619 75.96 ;
     RECT  31.619 75.168 31.66 75.816 ;
     RECT  30.625 0.048 31.673 1.512 ;
     RECT  30.947 59.616 31.705 62.808 ;
     RECT  31.619 71.52 31.709 73.08 ;
     RECT  31.601 64.416 31.715 67.128 ;
     RECT  30.947 58.32 31.717 58.536 ;
     RECT  31.597 22.8 31.853 22.824 ;
     RECT  31.717 58.176 31.861 58.536 ;
     RECT  31.619 74.064 31.889 74.088 ;
     RECT  30.899 2.832 31.907 2.856 ;
     RECT  31.777 56.976 31.907 57 ;
     RECT  31.861 58.08 31.909 58.536 ;
     RECT  31.705 59.616 31.909 63.288 ;
     RECT  31.717 54.768 31.921 54.792 ;
     RECT  31.909 58.08 31.921 63.288 ;
     RECT  29.704 101.712 31.955 103.56 ;
     RECT  31.381 36.24 31.961 39.528 ;
     RECT  31.813 14.256 31.997 14.28 ;
     RECT  31.673 0.096 32.005 1.512 ;
     RECT  31.571 68.4 32.021 70.44 ;
     RECT  31.709 71.52 32.021 72.984 ;
     RECT  31.909 5.712 32.033 5.736 ;
     RECT  32.005 0.096 32.177 1.752 ;
     RECT  31.921 57.984 32.209 63.288 ;
     RECT  31.489 26.784 32.389 33.384 ;
     RECT  32.353 96.912 32.465 96.936 ;
     RECT  31.921 54.72 32.569 54.792 ;
     RECT  31.66 75.792 32.573 75.816 ;
     RECT  32.569 53.904 32.677 54.792 ;
     RECT  31.715 64.992 32.677 67.128 ;
     RECT  32.021 68.4 32.677 72.984 ;
     RECT  32.177 0.096 32.749 1.512 ;
     RECT  32.209 57.696 32.761 63.288 ;
     RECT  31.169 41.616 32.869 42.744 ;
     RECT  31.277 44.16 32.869 44.184 ;
     RECT  32.497 45.648 32.869 45.672 ;
     RECT  32.869 41.616 32.893 45.768 ;
     RECT  31.955 101.76 32.893 103.56 ;
     RECT  32.893 41.616 32.915 46.248 ;
     RECT  31.429 6.816 32.917 6.84 ;
     RECT  32.915 41.616 32.956 43.32 ;
     RECT  32.893 101.76 32.965 103.608 ;
     RECT  32.677 53.904 32.969 55.512 ;
     RECT  32.956 41.616 33.011 42.792 ;
     RECT  32.915 44.88 33.011 46.248 ;
     RECT  31.961 36.24 33.041 39.288 ;
     RECT  32.917 6.72 33.059 6.84 ;
     RECT  32.677 64.992 33.059 72.984 ;
     RECT  31.237 34.8 33.061 34.824 ;
     RECT  33.041 36.24 33.061 36.312 ;
     RECT  33.059 67.104 33.061 72.984 ;
     RECT  33.059 64.992 33.077 65.592 ;
     RECT  33.011 41.616 33.113 42.6 ;
     RECT  32.761 57.696 33.148 63 ;
     RECT  33.113 41.616 33.149 41.64 ;
     RECT  33.061 67.104 33.185 73.032 ;
     RECT  33.157 98.736 33.253 98.76 ;
     RECT  32.389 26.592 33.261 33.384 ;
     RECT  33.061 34.8 33.261 36.312 ;
     RECT  33.253 98.64 33.299 98.76 ;
     RECT  33.261 26.592 33.437 36.312 ;
     RECT  33.041 37.296 33.541 39.288 ;
     RECT  33.185 67.104 33.581 72.984 ;
     RECT  33.581 67.104 33.589 68.952 ;
     RECT  33.011 44.88 33.617 44.904 ;
     RECT  33.541 37.296 33.653 40.008 ;
     RECT  33.589 67.104 33.689 68.904 ;
     RECT  33.437 26.592 33.721 33.576 ;
     RECT  33.689 68.88 33.779 68.904 ;
     RECT  33.653 37.584 33.781 40.008 ;
     RECT  33.437 34.8 33.797 36.312 ;
     RECT  33.781 37.584 33.877 40.344 ;
     RECT  33.148 59.712 34.117 63 ;
     RECT  33.077 65.568 34.397 65.592 ;
     RECT  33.689 67.104 34.397 67.656 ;
     RECT  33.011 46.224 34.477 46.248 ;
     RECT  33.877 37.584 34.513 40.488 ;
     RECT  33.901 64.32 34.541 64.44 ;
     RECT  34.397 65.568 34.541 67.656 ;
     RECT  34.477 45.744 34.693 46.248 ;
     RECT  33.721 26.208 34.765 33.576 ;
     RECT  32.749 0.048 34.808 1.512 ;
     RECT  32.725 11.136 34.808 11.16 ;
     RECT  33.793 16.368 34.808 16.392 ;
     RECT  34.009 19.056 34.808 19.08 ;
     RECT  34.765 26.208 34.808 34.392 ;
     RECT  33.797 35.424 34.808 36.312 ;
     RECT  34.513 37.584 34.808 41.256 ;
     RECT  34.693 45.744 34.808 46.824 ;
     RECT  32.969 53.904 34.808 53.928 ;
     RECT  32.969 55.488 34.808 55.512 ;
     RECT  33.148 57.696 34.808 58.248 ;
     RECT  34.117 59.28 34.808 63 ;
     RECT  34.541 64.32 34.808 67.656 ;
     RECT  33.581 70.128 34.808 72.984 ;
     RECT  33.145 74.544 34.808 74.568 ;
     RECT  33.299 98.64 34.808 98.664 ;
     RECT  32.965 101.712 34.808 103.608 ;
     RECT  34.808 0.048 35.104 103.608 ;
     RECT  35.104 26.544 35.219 34.392 ;
     RECT  35.104 65.52 35.219 71.304 ;
     RECT  35.219 26.544 35.267 34.248 ;
     RECT  35.104 59.808 35.267 63 ;
     RECT  35.104 38.784 35.309 39.336 ;
     RECT  35.267 26.544 35.315 33.624 ;
     RECT  35.219 65.568 35.317 71.304 ;
     RECT  35.104 16.368 35.363 19.416 ;
     RECT  35.104 14.256 35.381 14.28 ;
     RECT  35.317 66.144 35.459 71.304 ;
     RECT  35.104 41.232 35.525 41.256 ;
     RECT  35.104 101.712 35.525 103.608 ;
     RECT  35.104 0.048 35.633 2.904 ;
     RECT  35.315 28.464 35.633 33.624 ;
     RECT  35.633 28.464 35.651 29.112 ;
     RECT  35.633 30.096 35.651 33.624 ;
     RECT  35.309 39.312 35.669 39.336 ;
     RECT  35.651 28.464 35.699 28.488 ;
     RECT  35.315 26.544 35.741 27.48 ;
     RECT  35.104 35.424 35.741 37.032 ;
     RECT  35.104 72.384 35.741 72.984 ;
     RECT  35.104 98.64 35.741 98.664 ;
     RECT  35.459 66.144 35.777 69.384 ;
     RECT  35.741 72.96 35.795 72.984 ;
     RECT  35.741 36.288 35.813 37.032 ;
     RECT  35.267 60.864 35.813 61.704 ;
     RECT  35.633 0.048 35.891 2.856 ;
     RECT  35.651 30.192 36.035 33.624 ;
     RECT  35.813 36.432 36.065 37.032 ;
     RECT  35.891 0.048 36.083 2.808 ;
     RECT  36.035 30.768 36.101 33.624 ;
     RECT  36.101 30.912 36.131 33.624 ;
     RECT  35.525 101.712 36.209 102.6 ;
     RECT  35.267 59.808 36.313 59.832 ;
     RECT  35.813 60.864 36.313 61.128 ;
     RECT  35.104 57.696 36.323 57.72 ;
     RECT  36.083 0.048 36.467 2.28 ;
     RECT  35.777 66.768 36.497 69.384 ;
     RECT  36.131 30.912 36.515 33.384 ;
     RECT  36.209 101.712 36.515 102.552 ;
     RECT  35.104 11.136 36.563 11.16 ;
     RECT  35.104 55.488 36.563 55.512 ;
     RECT  35.741 26.544 36.611 26.616 ;
     RECT  36.601 40.368 36.629 40.392 ;
     RECT  36.313 59.76 36.641 61.128 ;
     RECT  36.097 7.392 36.659 7.416 ;
     RECT  35.363 16.56 36.713 19.416 ;
     RECT  36.629 40.368 36.713 40.488 ;
     RECT  36.497 66.864 36.749 69.384 ;
     RECT  36.641 59.808 36.785 61.128 ;
     RECT  35.104 45.744 36.803 46.824 ;
     RECT  36.745 74.688 36.817 74.712 ;
     RECT  36.749 68.976 36.821 69.384 ;
     RECT  36.817 74.688 36.829 75.288 ;
     RECT  36.529 5.088 36.851 5.112 ;
     RECT  36.611 26.592 36.853 26.616 ;
     RECT  36.803 46.512 36.899 46.824 ;
     RECT  36.829 74.736 36.901 75.288 ;
     RECT  36.785 60.576 36.925 61.128 ;
     RECT  36.749 66.864 36.929 67.656 ;
     RECT  36.853 39.888 36.947 39.912 ;
     RECT  36.853 26.592 36.965 26.808 ;
     RECT  36.925 60.576 36.965 61.32 ;
     RECT  36.713 16.56 37.001 17.688 ;
     RECT  36.965 61.008 37.037 61.32 ;
     RECT  36.853 37.632 37.043 37.656 ;
     RECT  36.899 46.8 37.043 46.824 ;
     RECT  36.901 75.264 37.043 75.288 ;
     RECT  36.515 101.712 37.139 102.504 ;
     RECT  35.104 53.904 37.187 53.928 ;
     RECT  37.093 12.528 37.189 12.552 ;
     RECT  36.713 19.056 37.235 19.416 ;
     RECT  35.267 62.976 37.235 63 ;
     RECT  36.965 26.784 37.249 26.808 ;
     RECT  36.515 30.912 37.283 32.808 ;
     RECT  35.104 64.32 37.283 64.344 ;
     RECT  37.189 12.528 37.397 12.6 ;
     RECT  37.249 26.784 37.397 27.336 ;
     RECT  37.397 26.784 37.505 26.808 ;
     RECT  37.429 38.784 37.513 38.808 ;
     RECT  37.397 12.528 37.541 12.552 ;
     RECT  37.283 30.912 37.667 30.936 ;
     RECT  37.283 32.208 37.715 32.808 ;
     RECT  37.715 32.208 37.763 32.232 ;
     RECT  37.001 16.56 37.811 17.112 ;
     RECT  36.821 68.976 37.811 69 ;
     RECT  37.235 19.392 37.859 19.416 ;
     RECT  35.459 71.28 37.859 71.304 ;
     RECT  36.929 66.864 37.864 67.08 ;
     RECT  37.789 82.656 37.937 82.68 ;
     RECT  37.864 66.816 38.081 67.08 ;
     RECT  38.081 66.816 38.153 66.984 ;
     RECT  37.139 101.712 38.221 102.456 ;
     RECT  36.065 36.432 38.243 36.456 ;
     RECT  37.897 30.816 38.291 30.84 ;
     RECT  38.221 101.664 38.333 102.456 ;
     RECT  38.153 66.96 38.369 66.984 ;
     RECT  38.333 101.712 38.405 102.456 ;
     RECT  38.405 102.432 38.477 102.456 ;
     RECT  37.811 17.088 38.621 17.112 ;
     RECT  35.525 103.584 38.693 103.608 ;
     RECT  36.467 0.048 39.377 1.512 ;
     RECT  39.377 0.048 39.737 0.072 ;
     RECT  39.377 1.392 40.208 1.512 ;
     RECT  40.208 1.392 40.312 101.532 ;
     RECT  40.312 2.418 40.504 101.262 ;
     RECT  40.312 1.392 40.565 1.416 ;
     RECT  45.608 2.148 45.712 101.532 ;
     RECT  45.712 2.418 45.904 101.262 ;
     RECT  51.008 2.148 51.112 101.532 ;
     RECT  51.112 2.418 51.304 101.262 ;
    LAYER M5 ;
     RECT  19.92 0.016 38.28 0.085 ;
     RECT  15.264 0.037 17.208 0.133 ;
     RECT  19.824 0.085 38.28 0.181 ;
     RECT  14.784 0.133 17.208 0.325 ;
     RECT  14.784 0.325 18.072 0.517 ;
     RECT  14.784 0.517 18.12 2.137 ;
     RECT  2.4 2.137 2.52 2.151 ;
     RECT  7.8 2.137 7.92 2.151 ;
     RECT  13.2 2.137 13.32 2.151 ;
     RECT  14.784 2.137 18.72 2.151 ;
     RECT  19.776 0.181 38.28 2.151 ;
     RECT  40.2 2.137 40.32 2.151 ;
     RECT  45.6 2.137 45.72 2.151 ;
     RECT  51 2.137 51.12 2.151 ;
     RECT  13.2 2.151 13.512 30.325 ;
     RECT  14.784 2.151 38.28 30.851 ;
     RECT  13.2 30.325 13.752 31.379 ;
     RECT  0.192 31.189 0.216 31.427 ;
     RECT  2.4 2.151 2.712 34.021 ;
     RECT  2.304 34.021 2.712 34.211 ;
     RECT  0.192 35.221 0.216 35.459 ;
     RECT  0.144 36.085 0.168 36.275 ;
     RECT  14.784 30.851 38.232 36.467 ;
     RECT  10.848 39.013 10.872 39.155 ;
     RECT  2.4 34.211 2.712 43.141 ;
     RECT  2.304 43.141 2.712 43.331 ;
     RECT  0.192 43.861 0.216 44.099 ;
     RECT  13.2 31.379 13.512 47.173 ;
     RECT  14.784 36.467 37.848 47.173 ;
     RECT  7.8 2.151 8.112 48.085 ;
     RECT  13.2 47.173 37.848 48.085 ;
     RECT  0.144 48.997 0.168 49.187 ;
     RECT  13.104 48.085 37.848 49.235 ;
     RECT  13.2 49.235 37.848 49.331 ;
     RECT  7.8 48.085 8.52 49.619 ;
     RECT  11.712 50.101 11.736 51.299 ;
     RECT  13.2 49.331 13.512 52.453 ;
     RECT  0.288 51.397 0.312 52.499 ;
     RECT  13.056 52.453 13.512 53.219 ;
     RECT  7.8 49.619 8.112 54.085 ;
     RECT  11.568 52.165 11.592 54.469 ;
     RECT  14.784 49.331 37.848 54.563 ;
     RECT  6.816 54.085 8.112 54.899 ;
     RECT  11.568 54.469 11.832 54.899 ;
     RECT  14.784 54.563 22.488 58.835 ;
     RECT  21.456 58.835 22.488 59.221 ;
     RECT  23.568 54.563 37.848 59.221 ;
     RECT  14.784 58.835 20.376 60.373 ;
     RECT  21.456 59.221 37.848 60.373 ;
     RECT  14.784 60.373 37.848 60.467 ;
     RECT  14.784 60.467 22.776 60.515 ;
     RECT  14.784 60.515 20.136 60.563 ;
     RECT  21.168 60.515 22.776 60.803 ;
     RECT  21.168 60.803 22.488 61.043 ;
     RECT  21.168 61.043 22.392 61.091 ;
     RECT  11.808 54.899 11.832 61.141 ;
     RECT  10.848 61.141 11.832 61.283 ;
     RECT  11.808 61.283 11.832 62.195 ;
     RECT  21.168 61.091 22.2 62.195 ;
     RECT  14.784 60.563 20.088 62.677 ;
     RECT  21.168 62.195 22.152 62.677 ;
     RECT  13.2 53.219 13.512 62.725 ;
     RECT  13.104 62.725 13.512 63.589 ;
     RECT  13.104 63.589 13.704 63.635 ;
     RECT  24 60.467 37.848 63.829 ;
     RECT  2.4 43.331 2.712 64.117 ;
     RECT  14.784 62.677 22.152 64.261 ;
     RECT  2.304 64.117 2.712 64.307 ;
     RECT  14.784 64.261 22.2 64.931 ;
     RECT  0.192 65.461 0.216 65.699 ;
     RECT  23.664 63.829 37.848 66.661 ;
     RECT  14.784 64.931 21.912 66.995 ;
     RECT  21.072 66.995 21.912 68.101 ;
     RECT  23.04 66.661 37.848 68.101 ;
     RECT  13.2 63.635 13.704 68.341 ;
     RECT  14.784 66.995 20.088 68.341 ;
     RECT  13.2 68.341 20.088 69.587 ;
     RECT  14.688 69.587 20.088 70.691 ;
     RECT  21.072 68.101 37.848 71.315 ;
     RECT  14.784 70.691 20.088 72.421 ;
     RECT  21.072 71.315 37.752 72.421 ;
     RECT  13.2 69.587 13.512 74.341 ;
     RECT  13.2 74.341 13.704 74.629 ;
     RECT  14.784 72.421 37.752 74.629 ;
     RECT  13.2 74.629 37.752 74.677 ;
     RECT  12.528 74.677 37.752 75.491 ;
     RECT  9.84 74.629 9.864 75.635 ;
     RECT  0.144 76.021 0.168 76.307 ;
     RECT  12.528 75.491 20.52 76.355 ;
     RECT  13.2 76.355 20.52 76.933 ;
     RECT  13.2 76.933 20.616 76.979 ;
     RECT  15.408 76.979 20.616 78.661 ;
     RECT  21.6 75.491 37.752 78.661 ;
     RECT  15.408 78.661 37.752 81.011 ;
     RECT  15.408 81.011 21.624 81.539 ;
     RECT  15.408 81.539 21.384 82.549 ;
     RECT  22.752 81.011 37.752 82.691 ;
     RECT  23.184 82.691 37.752 83.749 ;
     RECT  15.408 82.549 21.48 84.373 ;
     RECT  23.04 83.749 37.752 84.373 ;
     RECT  15.408 84.373 37.752 98.675 ;
     RECT  2.4 64.307 2.712 101.529 ;
     RECT  7.8 54.899 8.112 101.529 ;
     RECT  13.2 76.979 13.512 101.529 ;
     RECT  40.2 2.151 40.512 101.529 ;
     RECT  45.6 2.151 45.912 101.529 ;
     RECT  51 2.151 51.312 101.529 ;
     RECT  2.4 101.529 2.52 101.543 ;
     RECT  7.8 101.529 7.92 101.543 ;
     RECT  13.2 101.529 13.32 101.543 ;
     RECT  40.2 101.529 40.32 101.543 ;
     RECT  45.6 101.529 45.72 101.543 ;
     RECT  51 101.529 51.12 101.543 ;
     RECT  15.648 98.675 37.752 101.795 ;
     RECT  15.648 101.795 37.704 102.419 ;
     RECT  15.648 102.419 37.128 102.515 ;
     RECT  15.648 102.515 36.504 102.563 ;
     RECT  15.648 102.563 35.928 102.611 ;
     RECT  15.648 102.611 35.208 102.707 ;
     RECT  15.648 102.707 34.056 103.093 ;
     RECT  35.184 102.707 35.208 103.523 ;
     RECT  15.6 103.093 34.056 103.571 ;
     RECT  15.696 103.571 34.056 103.632 ;
  END
END ot_qwen_die_station
END LIBRARY
